VERSION 5.8 ;
BUSBITCHARS "[]" ;
DIVIDERCHAR "/" ;
UNITS
    DATABASE MICRONS 1000 ;
END UNITS

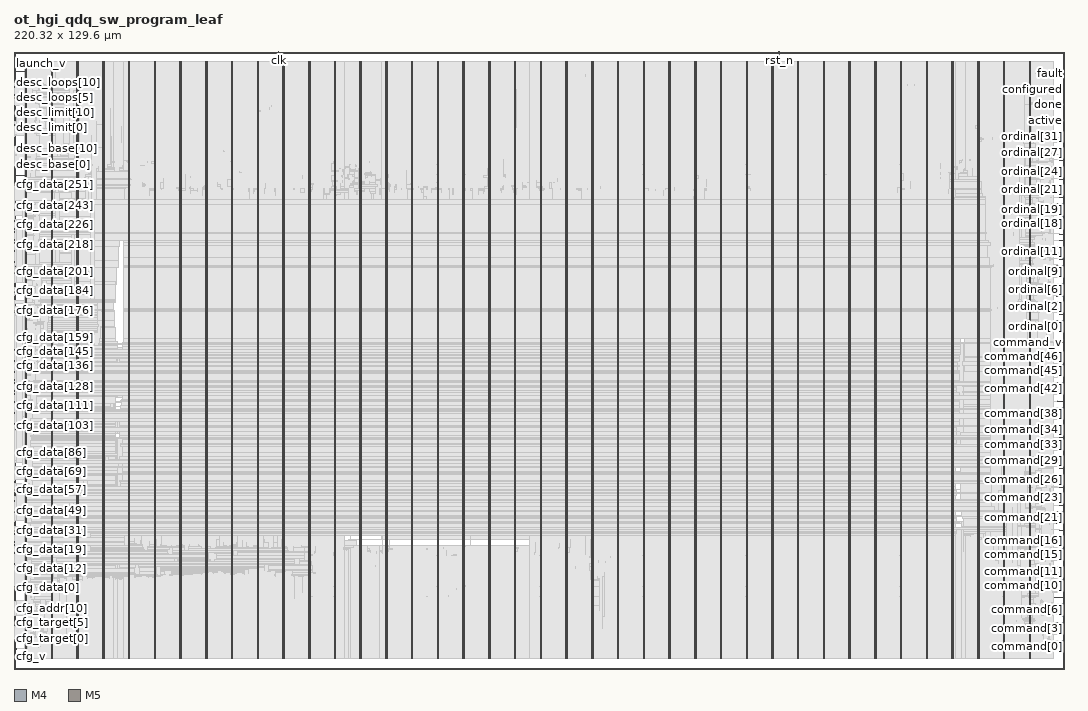
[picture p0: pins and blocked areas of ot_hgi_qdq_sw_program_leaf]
MACRO ot_hgi_qdq_sw_program_leaf
  FOREIGN ot_hgi_qdq_sw_program_leaf 0 0 ;
  CLASS BLOCK ;
  SIZE 220.32 BY 129.6 ;
  PIN active
    DIRECTION OUTPUT ;
    USE SIGNAL ;
    PORT
      LAYER M4 ;
        RECT  220.236 115.056 220.32 115.08 ;
    END
    PORT
      LAYER M4 ;
        RECT  218.869 115.056 220.284 115.08 ;
    END
  END active
  PIN cfg_addr[0]
    DIRECTION INPUT ;
    USE SIGNAL ;
    PORT
      LAYER M4 ;
        RECT  0 11.136 0.084 11.16 ;
    END
  END cfg_addr[0]
  PIN cfg_addr[10]
    DIRECTION INPUT ;
    USE SIGNAL ;
    PORT
      LAYER M4 ;
        RECT  0 14.4 0.084 14.424 ;
    END
  END cfg_addr[10]
  PIN cfg_addr[11]
    DIRECTION INPUT ;
    USE SIGNAL ;
    PORT
      LAYER M4 ;
        RECT  0 14.736 0.084 14.76 ;
    END
  END cfg_addr[11]
  PIN cfg_addr[1]
    DIRECTION INPUT ;
    USE SIGNAL ;
    PORT
      LAYER M4 ;
        RECT  0 11.472 0.084 11.496 ;
    END
  END cfg_addr[1]
  PIN cfg_addr[2]
    DIRECTION INPUT ;
    USE SIGNAL ;
    PORT
      LAYER M4 ;
        RECT  0 11.76 0.084 11.784 ;
    END
  END cfg_addr[2]
  PIN cfg_addr[3]
    DIRECTION INPUT ;
    USE SIGNAL ;
    PORT
      LAYER M4 ;
        RECT  0 12.096 0.084 12.12 ;
    END
  END cfg_addr[3]
  PIN cfg_addr[4]
    DIRECTION INPUT ;
    USE SIGNAL ;
    PORT
      LAYER M4 ;
        RECT  0 12.432 0.084 12.456 ;
    END
  END cfg_addr[4]
  PIN cfg_addr[5]
    DIRECTION INPUT ;
    USE SIGNAL ;
    PORT
      LAYER M4 ;
        RECT  0 12.768 0.084 12.792 ;
    END
  END cfg_addr[5]
  PIN cfg_addr[6]
    DIRECTION INPUT ;
    USE SIGNAL ;
    PORT
      LAYER M4 ;
        RECT  0 13.104 0.084 13.128 ;
    END
  END cfg_addr[6]
  PIN cfg_addr[7]
    DIRECTION INPUT ;
    USE SIGNAL ;
    PORT
      LAYER M4 ;
        RECT  0 13.44 0.084 13.464 ;
    END
  END cfg_addr[7]
  PIN cfg_addr[8]
    DIRECTION INPUT ;
    USE SIGNAL ;
    PORT
      LAYER M4 ;
        RECT  0 13.776 0.084 13.8 ;
    END
  END cfg_addr[8]
  PIN cfg_addr[9]
    DIRECTION INPUT ;
    USE SIGNAL ;
    PORT
      LAYER M4 ;
        RECT  0 14.112 0.084 14.136 ;
    END
  END cfg_addr[9]
  PIN cfg_data[0]
    DIRECTION INPUT ;
    USE SIGNAL ;
    PORT
      LAYER M4 ;
        RECT  0 17.088 0.084 17.112 ;
    END
  END cfg_data[0]
  PIN cfg_data[100]
    DIRECTION INPUT ;
    USE SIGNAL ;
    PORT
      LAYER M4 ;
        RECT  0 50.064 0.084 50.088 ;
    END
  END cfg_data[100]
  PIN cfg_data[101]
    DIRECTION INPUT ;
    USE SIGNAL ;
    PORT
      LAYER M4 ;
        RECT  0 50.4 0.084 50.424 ;
    END
  END cfg_data[101]
  PIN cfg_data[102]
    DIRECTION INPUT ;
    USE SIGNAL ;
    PORT
      LAYER M4 ;
        RECT  0 50.736 0.084 50.76 ;
    END
  END cfg_data[102]
  PIN cfg_data[103]
    DIRECTION INPUT ;
    USE SIGNAL ;
    PORT
      LAYER M4 ;
        RECT  0 51.072 0.084 51.096 ;
    END
  END cfg_data[103]
  PIN cfg_data[104]
    DIRECTION INPUT ;
    USE SIGNAL ;
    PORT
      LAYER M4 ;
        RECT  0 51.408 0.084 51.432 ;
    END
  END cfg_data[104]
  PIN cfg_data[105]
    DIRECTION INPUT ;
    USE SIGNAL ;
    PORT
      LAYER M4 ;
        RECT  0 51.744 0.084 51.768 ;
    END
  END cfg_data[105]
  PIN cfg_data[106]
    DIRECTION INPUT ;
    USE SIGNAL ;
    PORT
      LAYER M4 ;
        RECT  0 52.08 0.084 52.104 ;
    END
  END cfg_data[106]
  PIN cfg_data[107]
    DIRECTION INPUT ;
    USE SIGNAL ;
    PORT
      LAYER M4 ;
        RECT  0 52.416 0.084 52.44 ;
    END
  END cfg_data[107]
  PIN cfg_data[108]
    DIRECTION INPUT ;
    USE SIGNAL ;
    PORT
      LAYER M4 ;
        RECT  0 52.704 0.084 52.728 ;
    END
  END cfg_data[108]
  PIN cfg_data[109]
    DIRECTION INPUT ;
    USE SIGNAL ;
    PORT
      LAYER M4 ;
        RECT  0 53.04 0.084 53.064 ;
    END
  END cfg_data[109]
  PIN cfg_data[10]
    DIRECTION INPUT ;
    USE SIGNAL ;
    PORT
      LAYER M4 ;
        RECT  0 20.4 0.084 20.424 ;
    END
  END cfg_data[10]
  PIN cfg_data[110]
    DIRECTION INPUT ;
    USE SIGNAL ;
    PORT
      LAYER M4 ;
        RECT  0 53.376 0.084 53.4 ;
    END
  END cfg_data[110]
  PIN cfg_data[111]
    DIRECTION INPUT ;
    USE SIGNAL ;
    PORT
      LAYER M4 ;
        RECT  0 53.712 0.084 53.736 ;
    END
  END cfg_data[111]
  PIN cfg_data[112]
    DIRECTION INPUT ;
    USE SIGNAL ;
    PORT
      LAYER M4 ;
        RECT  0 54.048 0.084 54.072 ;
    END
  END cfg_data[112]
  PIN cfg_data[113]
    DIRECTION INPUT ;
    USE SIGNAL ;
    PORT
      LAYER M4 ;
        RECT  0 54.384 0.084 54.408 ;
    END
  END cfg_data[113]
  PIN cfg_data[114]
    DIRECTION INPUT ;
    USE SIGNAL ;
    PORT
      LAYER M4 ;
        RECT  0 54.72 0.084 54.744 ;
    END
  END cfg_data[114]
  PIN cfg_data[115]
    DIRECTION INPUT ;
    USE SIGNAL ;
    PORT
      LAYER M4 ;
        RECT  0 55.056 0.084 55.08 ;
    END
  END cfg_data[115]
  PIN cfg_data[116]
    DIRECTION INPUT ;
    USE SIGNAL ;
    PORT
      LAYER M4 ;
        RECT  0 55.344 0.084 55.368 ;
    END
  END cfg_data[116]
  PIN cfg_data[117]
    DIRECTION INPUT ;
    USE SIGNAL ;
    PORT
      LAYER M4 ;
        RECT  0 55.68 0.084 55.704 ;
    END
  END cfg_data[117]
  PIN cfg_data[118]
    DIRECTION INPUT ;
    USE SIGNAL ;
    PORT
      LAYER M4 ;
        RECT  0 56.016 0.084 56.04 ;
    END
  END cfg_data[118]
  PIN cfg_data[119]
    DIRECTION INPUT ;
    USE SIGNAL ;
    PORT
      LAYER M4 ;
        RECT  0 56.352 0.084 56.376 ;
    END
  END cfg_data[119]
  PIN cfg_data[11]
    DIRECTION INPUT ;
    USE SIGNAL ;
    PORT
      LAYER M4 ;
        RECT  0 20.736 0.084 20.76 ;
    END
  END cfg_data[11]
  PIN cfg_data[120]
    DIRECTION INPUT ;
    USE SIGNAL ;
    PORT
      LAYER M4 ;
        RECT  0 56.688 0.084 56.712 ;
    END
  END cfg_data[120]
  PIN cfg_data[121]
    DIRECTION INPUT ;
    USE SIGNAL ;
    PORT
      LAYER M4 ;
        RECT  0 57.024 0.084 57.048 ;
    END
  END cfg_data[121]
  PIN cfg_data[122]
    DIRECTION INPUT ;
    USE SIGNAL ;
    PORT
      LAYER M4 ;
        RECT  0 57.36 0.084 57.384 ;
    END
  END cfg_data[122]
  PIN cfg_data[123]
    DIRECTION INPUT ;
    USE SIGNAL ;
    PORT
      LAYER M4 ;
        RECT  0 57.696 0.084 57.72 ;
    END
  END cfg_data[123]
  PIN cfg_data[124]
    DIRECTION INPUT ;
    USE SIGNAL ;
    PORT
      LAYER M4 ;
        RECT  0 57.984 0.084 58.008 ;
    END
  END cfg_data[124]
  PIN cfg_data[125]
    DIRECTION INPUT ;
    USE SIGNAL ;
    PORT
      LAYER M4 ;
        RECT  0 58.32 0.084 58.344 ;
    END
  END cfg_data[125]
  PIN cfg_data[126]
    DIRECTION INPUT ;
    USE SIGNAL ;
    PORT
      LAYER M4 ;
        RECT  0 58.656 0.084 58.68 ;
    END
  END cfg_data[126]
  PIN cfg_data[127]
    DIRECTION INPUT ;
    USE SIGNAL ;
    PORT
      LAYER M4 ;
        RECT  0 58.992 0.084 59.016 ;
    END
  END cfg_data[127]
  PIN cfg_data[128]
    DIRECTION INPUT ;
    USE SIGNAL ;
    PORT
      LAYER M4 ;
        RECT  0 59.328 0.084 59.352 ;
    END
  END cfg_data[128]
  PIN cfg_data[129]
    DIRECTION INPUT ;
    USE SIGNAL ;
    PORT
      LAYER M4 ;
        RECT  0 59.664 0.084 59.688 ;
    END
  END cfg_data[129]
  PIN cfg_data[12]
    DIRECTION INPUT ;
    USE SIGNAL ;
    PORT
      LAYER M4 ;
        RECT  0 21.024 0.084 21.048 ;
    END
  END cfg_data[12]
  PIN cfg_data[130]
    DIRECTION INPUT ;
    USE SIGNAL ;
    PORT
      LAYER M4 ;
        RECT  0 60 0.084 60.024 ;
    END
  END cfg_data[130]
  PIN cfg_data[131]
    DIRECTION INPUT ;
    USE SIGNAL ;
    PORT
      LAYER M4 ;
        RECT  0 60.336 0.084 60.36 ;
    END
  END cfg_data[131]
  PIN cfg_data[132]
    DIRECTION INPUT ;
    USE SIGNAL ;
    PORT
      LAYER M4 ;
        RECT  0 60.624 0.084 60.648 ;
    END
  END cfg_data[132]
  PIN cfg_data[133]
    DIRECTION INPUT ;
    USE SIGNAL ;
    PORT
      LAYER M4 ;
        RECT  0 60.96 0.084 60.984 ;
    END
  END cfg_data[133]
  PIN cfg_data[134]
    DIRECTION INPUT ;
    USE SIGNAL ;
    PORT
      LAYER M4 ;
        RECT  0 61.296 0.084 61.32 ;
    END
  END cfg_data[134]
  PIN cfg_data[135]
    DIRECTION INPUT ;
    USE SIGNAL ;
    PORT
      LAYER M4 ;
        RECT  0 61.632 0.084 61.656 ;
    END
  END cfg_data[135]
  PIN cfg_data[136]
    DIRECTION INPUT ;
    USE SIGNAL ;
    PORT
      LAYER M4 ;
        RECT  0 61.968 0.084 61.992 ;
    END
  END cfg_data[136]
  PIN cfg_data[137]
    DIRECTION INPUT ;
    USE SIGNAL ;
    PORT
      LAYER M4 ;
        RECT  0 62.304 0.084 62.328 ;
    END
  END cfg_data[137]
  PIN cfg_data[138]
    DIRECTION INPUT ;
    USE SIGNAL ;
    PORT
      LAYER M4 ;
        RECT  0 62.64 0.084 62.664 ;
    END
  END cfg_data[138]
  PIN cfg_data[139]
    DIRECTION INPUT ;
    USE SIGNAL ;
    PORT
      LAYER M4 ;
        RECT  0 62.976 0.084 63 ;
    END
  END cfg_data[139]
  PIN cfg_data[13]
    DIRECTION INPUT ;
    USE SIGNAL ;
    PORT
      LAYER M4 ;
        RECT  0 21.36 0.084 21.384 ;
    END
  END cfg_data[13]
  PIN cfg_data[140]
    DIRECTION INPUT ;
    USE SIGNAL ;
    PORT
      LAYER M4 ;
        RECT  0 63.264 0.084 63.288 ;
    END
  END cfg_data[140]
  PIN cfg_data[141]
    DIRECTION INPUT ;
    USE SIGNAL ;
    PORT
      LAYER M4 ;
        RECT  0 63.6 0.084 63.624 ;
    END
  END cfg_data[141]
  PIN cfg_data[142]
    DIRECTION INPUT ;
    USE SIGNAL ;
    PORT
      LAYER M4 ;
        RECT  0 63.936 0.084 63.96 ;
    END
  END cfg_data[142]
  PIN cfg_data[143]
    DIRECTION INPUT ;
    USE SIGNAL ;
    PORT
      LAYER M4 ;
        RECT  0 64.272 0.084 64.296 ;
    END
  END cfg_data[143]
  PIN cfg_data[144]
    DIRECTION INPUT ;
    USE SIGNAL ;
    PORT
      LAYER M4 ;
        RECT  0 64.608 0.084 64.632 ;
    END
  END cfg_data[144]
  PIN cfg_data[145]
    DIRECTION INPUT ;
    USE SIGNAL ;
    PORT
      LAYER M4 ;
        RECT  0 64.944 0.084 64.968 ;
    END
  END cfg_data[145]
  PIN cfg_data[146]
    DIRECTION INPUT ;
    USE SIGNAL ;
    PORT
      LAYER M4 ;
        RECT  0 65.28 0.084 65.304 ;
    END
  END cfg_data[146]
  PIN cfg_data[147]
    DIRECTION INPUT ;
    USE SIGNAL ;
    PORT
      LAYER M4 ;
        RECT  0 65.616 0.084 65.64 ;
    END
  END cfg_data[147]
  PIN cfg_data[148]
    DIRECTION INPUT ;
    USE SIGNAL ;
    PORT
      LAYER M4 ;
        RECT  0 65.904 0.084 65.928 ;
    END
  END cfg_data[148]
  PIN cfg_data[149]
    DIRECTION INPUT ;
    USE SIGNAL ;
    PORT
      LAYER M4 ;
        RECT  0 66.24 0.084 66.264 ;
    END
  END cfg_data[149]
  PIN cfg_data[14]
    DIRECTION INPUT ;
    USE SIGNAL ;
    PORT
      LAYER M4 ;
        RECT  0 21.696 0.084 21.72 ;
    END
  END cfg_data[14]
  PIN cfg_data[150]
    DIRECTION INPUT ;
    USE SIGNAL ;
    PORT
      LAYER M4 ;
        RECT  0 66.576 0.084 66.6 ;
    END
  END cfg_data[150]
  PIN cfg_data[151]
    DIRECTION INPUT ;
    USE SIGNAL ;
    PORT
      LAYER M4 ;
        RECT  0 66.912 0.084 66.936 ;
    END
  END cfg_data[151]
  PIN cfg_data[152]
    DIRECTION INPUT ;
    USE SIGNAL ;
    PORT
      LAYER M4 ;
        RECT  0 67.248 0.084 67.272 ;
    END
  END cfg_data[152]
  PIN cfg_data[153]
    DIRECTION INPUT ;
    USE SIGNAL ;
    PORT
      LAYER M4 ;
        RECT  0 67.584 0.084 67.608 ;
    END
  END cfg_data[153]
  PIN cfg_data[154]
    DIRECTION INPUT ;
    USE SIGNAL ;
    PORT
      LAYER M4 ;
        RECT  0 67.92 0.084 67.944 ;
    END
  END cfg_data[154]
  PIN cfg_data[155]
    DIRECTION INPUT ;
    USE SIGNAL ;
    PORT
      LAYER M4 ;
        RECT  0 68.256 0.084 68.28 ;
    END
  END cfg_data[155]
  PIN cfg_data[156]
    DIRECTION INPUT ;
    USE SIGNAL ;
    PORT
      LAYER M4 ;
        RECT  0 68.544 0.084 68.568 ;
    END
  END cfg_data[156]
  PIN cfg_data[157]
    DIRECTION INPUT ;
    USE SIGNAL ;
    PORT
      LAYER M4 ;
        RECT  0 68.88 0.084 68.904 ;
    END
  END cfg_data[157]
  PIN cfg_data[158]
    DIRECTION INPUT ;
    USE SIGNAL ;
    PORT
      LAYER M4 ;
        RECT  0 69.216 0.084 69.24 ;
    END
  END cfg_data[158]
  PIN cfg_data[159]
    DIRECTION INPUT ;
    USE SIGNAL ;
    PORT
      LAYER M4 ;
        RECT  0 69.552 0.084 69.576 ;
    END
  END cfg_data[159]
  PIN cfg_data[15]
    DIRECTION INPUT ;
    USE SIGNAL ;
    PORT
      LAYER M4 ;
        RECT  0 22.032 0.084 22.056 ;
    END
  END cfg_data[15]
  PIN cfg_data[160]
    DIRECTION INPUT ;
    USE SIGNAL ;
    PORT
      LAYER M4 ;
        RECT  0 69.888 0.084 69.912 ;
    END
  END cfg_data[160]
  PIN cfg_data[161]
    DIRECTION INPUT ;
    USE SIGNAL ;
    PORT
      LAYER M4 ;
        RECT  0 70.224 0.084 70.248 ;
    END
  END cfg_data[161]
  PIN cfg_data[162]
    DIRECTION INPUT ;
    USE SIGNAL ;
    PORT
      LAYER M4 ;
        RECT  0 70.56 0.084 70.584 ;
    END
  END cfg_data[162]
  PIN cfg_data[163]
    DIRECTION INPUT ;
    USE SIGNAL ;
    PORT
      LAYER M4 ;
        RECT  0 70.896 0.084 70.92 ;
    END
  END cfg_data[163]
  PIN cfg_data[164]
    DIRECTION INPUT ;
    USE SIGNAL ;
    PORT
      LAYER M4 ;
        RECT  0 71.184 0.084 71.208 ;
    END
  END cfg_data[164]
  PIN cfg_data[165]
    DIRECTION INPUT ;
    USE SIGNAL ;
    PORT
      LAYER M4 ;
        RECT  0 71.52 0.084 71.544 ;
    END
  END cfg_data[165]
  PIN cfg_data[166]
    DIRECTION INPUT ;
    USE SIGNAL ;
    PORT
      LAYER M4 ;
        RECT  0 71.856 0.084 71.88 ;
    END
  END cfg_data[166]
  PIN cfg_data[167]
    DIRECTION INPUT ;
    USE SIGNAL ;
    PORT
      LAYER M4 ;
        RECT  0 72.192 0.084 72.216 ;
    END
  END cfg_data[167]
  PIN cfg_data[168]
    DIRECTION INPUT ;
    USE SIGNAL ;
    PORT
      LAYER M4 ;
        RECT  0 72.528 0.084 72.552 ;
    END
  END cfg_data[168]
  PIN cfg_data[169]
    DIRECTION INPUT ;
    USE SIGNAL ;
    PORT
      LAYER M4 ;
        RECT  0 72.864 0.084 72.888 ;
    END
  END cfg_data[169]
  PIN cfg_data[16]
    DIRECTION INPUT ;
    USE SIGNAL ;
    PORT
      LAYER M4 ;
        RECT  0 22.368 0.084 22.392 ;
    END
  END cfg_data[16]
  PIN cfg_data[170]
    DIRECTION INPUT ;
    USE SIGNAL ;
    PORT
      LAYER M4 ;
        RECT  0 73.2 0.084 73.224 ;
    END
  END cfg_data[170]
  PIN cfg_data[171]
    DIRECTION INPUT ;
    USE SIGNAL ;
    PORT
      LAYER M4 ;
        RECT  0 73.536 0.084 73.56 ;
    END
  END cfg_data[171]
  PIN cfg_data[172]
    DIRECTION INPUT ;
    USE SIGNAL ;
    PORT
      LAYER M4 ;
        RECT  0 73.824 0.084 73.848 ;
    END
  END cfg_data[172]
  PIN cfg_data[173]
    DIRECTION INPUT ;
    USE SIGNAL ;
    PORT
      LAYER M4 ;
        RECT  0 74.16 0.084 74.184 ;
    END
  END cfg_data[173]
  PIN cfg_data[174]
    DIRECTION INPUT ;
    USE SIGNAL ;
    PORT
      LAYER M4 ;
        RECT  0 74.496 0.084 74.52 ;
    END
  END cfg_data[174]
  PIN cfg_data[175]
    DIRECTION INPUT ;
    USE SIGNAL ;
    PORT
      LAYER M4 ;
        RECT  0 74.832 0.084 74.856 ;
    END
  END cfg_data[175]
  PIN cfg_data[176]
    DIRECTION INPUT ;
    USE SIGNAL ;
    PORT
      LAYER M4 ;
        RECT  0 75.168 0.084 75.192 ;
    END
  END cfg_data[176]
  PIN cfg_data[177]
    DIRECTION INPUT ;
    USE SIGNAL ;
    PORT
      LAYER M4 ;
        RECT  0 75.504 0.084 75.528 ;
    END
  END cfg_data[177]
  PIN cfg_data[178]
    DIRECTION INPUT ;
    USE SIGNAL ;
    PORT
      LAYER M4 ;
        RECT  0 75.84 0.084 75.864 ;
    END
  END cfg_data[178]
  PIN cfg_data[179]
    DIRECTION INPUT ;
    USE SIGNAL ;
    PORT
      LAYER M4 ;
        RECT  0 76.176 0.084 76.2 ;
    END
  END cfg_data[179]
  PIN cfg_data[17]
    DIRECTION INPUT ;
    USE SIGNAL ;
    PORT
      LAYER M4 ;
        RECT  0 22.704 0.084 22.728 ;
    END
  END cfg_data[17]
  PIN cfg_data[180]
    DIRECTION INPUT ;
    USE SIGNAL ;
    PORT
      LAYER M4 ;
        RECT  0 76.464 0.084 76.488 ;
    END
  END cfg_data[180]
  PIN cfg_data[181]
    DIRECTION INPUT ;
    USE SIGNAL ;
    PORT
      LAYER M4 ;
        RECT  0 76.8 0.084 76.824 ;
    END
  END cfg_data[181]
  PIN cfg_data[182]
    DIRECTION INPUT ;
    USE SIGNAL ;
    PORT
      LAYER M4 ;
        RECT  0 77.136 0.084 77.16 ;
    END
  END cfg_data[182]
  PIN cfg_data[183]
    DIRECTION INPUT ;
    USE SIGNAL ;
    PORT
      LAYER M4 ;
        RECT  0 77.472 0.084 77.496 ;
    END
  END cfg_data[183]
  PIN cfg_data[184]
    DIRECTION INPUT ;
    USE SIGNAL ;
    PORT
      LAYER M4 ;
        RECT  0 77.808 0.084 77.832 ;
    END
  END cfg_data[184]
  PIN cfg_data[185]
    DIRECTION INPUT ;
    USE SIGNAL ;
    PORT
      LAYER M4 ;
        RECT  0 78.144 0.084 78.168 ;
    END
  END cfg_data[185]
  PIN cfg_data[186]
    DIRECTION INPUT ;
    USE SIGNAL ;
    PORT
      LAYER M4 ;
        RECT  0 78.48 0.084 78.504 ;
    END
  END cfg_data[186]
  PIN cfg_data[187]
    DIRECTION INPUT ;
    USE SIGNAL ;
    PORT
      LAYER M4 ;
        RECT  0 78.816 0.084 78.84 ;
    END
  END cfg_data[187]
  PIN cfg_data[188]
    DIRECTION INPUT ;
    USE SIGNAL ;
    PORT
      LAYER M4 ;
        RECT  0 79.104 0.084 79.128 ;
    END
  END cfg_data[188]
  PIN cfg_data[189]
    DIRECTION INPUT ;
    USE SIGNAL ;
    PORT
      LAYER M4 ;
        RECT  0 79.44 0.084 79.464 ;
    END
  END cfg_data[189]
  PIN cfg_data[18]
    DIRECTION INPUT ;
    USE SIGNAL ;
    PORT
      LAYER M4 ;
        RECT  0 23.04 0.084 23.064 ;
    END
  END cfg_data[18]
  PIN cfg_data[190]
    DIRECTION INPUT ;
    USE SIGNAL ;
    PORT
      LAYER M4 ;
        RECT  0 79.776 0.084 79.8 ;
    END
  END cfg_data[190]
  PIN cfg_data[191]
    DIRECTION INPUT ;
    USE SIGNAL ;
    PORT
      LAYER M4 ;
        RECT  0 80.112 0.084 80.136 ;
    END
  END cfg_data[191]
  PIN cfg_data[192]
    DIRECTION INPUT ;
    USE SIGNAL ;
    PORT
      LAYER M4 ;
        RECT  0 80.448 0.084 80.472 ;
    END
  END cfg_data[192]
  PIN cfg_data[193]
    DIRECTION INPUT ;
    USE SIGNAL ;
    PORT
      LAYER M4 ;
        RECT  0 80.784 0.084 80.808 ;
    END
  END cfg_data[193]
  PIN cfg_data[194]
    DIRECTION INPUT ;
    USE SIGNAL ;
    PORT
      LAYER M4 ;
        RECT  0 81.12 0.084 81.144 ;
    END
  END cfg_data[194]
  PIN cfg_data[195]
    DIRECTION INPUT ;
    USE SIGNAL ;
    PORT
      LAYER M4 ;
        RECT  0 81.456 0.084 81.48 ;
    END
  END cfg_data[195]
  PIN cfg_data[196]
    DIRECTION INPUT ;
    USE SIGNAL ;
    PORT
      LAYER M4 ;
        RECT  0 81.744 0.084 81.768 ;
    END
  END cfg_data[196]
  PIN cfg_data[197]
    DIRECTION INPUT ;
    USE SIGNAL ;
    PORT
      LAYER M4 ;
        RECT  0 82.08 0.084 82.104 ;
    END
  END cfg_data[197]
  PIN cfg_data[198]
    DIRECTION INPUT ;
    USE SIGNAL ;
    PORT
      LAYER M4 ;
        RECT  0 82.416 0.084 82.44 ;
    END
  END cfg_data[198]
  PIN cfg_data[199]
    DIRECTION INPUT ;
    USE SIGNAL ;
    PORT
      LAYER M4 ;
        RECT  0 82.752 0.084 82.776 ;
    END
  END cfg_data[199]
  PIN cfg_data[19]
    DIRECTION INPUT ;
    USE SIGNAL ;
    PORT
      LAYER M4 ;
        RECT  0 23.376 0.084 23.4 ;
    END
  END cfg_data[19]
  PIN cfg_data[1]
    DIRECTION INPUT ;
    USE SIGNAL ;
    PORT
      LAYER M4 ;
        RECT  0 17.424 0.084 17.448 ;
    END
  END cfg_data[1]
  PIN cfg_data[200]
    DIRECTION INPUT ;
    USE SIGNAL ;
    PORT
      LAYER M4 ;
        RECT  0 83.088 0.084 83.112 ;
    END
  END cfg_data[200]
  PIN cfg_data[201]
    DIRECTION INPUT ;
    USE SIGNAL ;
    PORT
      LAYER M4 ;
        RECT  0 83.424 0.084 83.448 ;
    END
  END cfg_data[201]
  PIN cfg_data[202]
    DIRECTION INPUT ;
    USE SIGNAL ;
    PORT
      LAYER M4 ;
        RECT  0 83.76 0.084 83.784 ;
    END
  END cfg_data[202]
  PIN cfg_data[203]
    DIRECTION INPUT ;
    USE SIGNAL ;
    PORT
      LAYER M4 ;
        RECT  0 84.096 0.084 84.12 ;
    END
  END cfg_data[203]
  PIN cfg_data[204]
    DIRECTION INPUT ;
    USE SIGNAL ;
    PORT
      LAYER M4 ;
        RECT  0 84.384 0.084 84.408 ;
    END
  END cfg_data[204]
  PIN cfg_data[205]
    DIRECTION INPUT ;
    USE SIGNAL ;
    PORT
      LAYER M4 ;
        RECT  0 84.72 0.084 84.744 ;
    END
  END cfg_data[205]
  PIN cfg_data[206]
    DIRECTION INPUT ;
    USE SIGNAL ;
    PORT
      LAYER M4 ;
        RECT  0 85.056 0.084 85.08 ;
    END
  END cfg_data[206]
  PIN cfg_data[207]
    DIRECTION INPUT ;
    USE SIGNAL ;
    PORT
      LAYER M4 ;
        RECT  0 85.392 0.084 85.416 ;
    END
  END cfg_data[207]
  PIN cfg_data[208]
    DIRECTION INPUT ;
    USE SIGNAL ;
    PORT
      LAYER M4 ;
        RECT  0 85.728 0.084 85.752 ;
    END
  END cfg_data[208]
  PIN cfg_data[209]
    DIRECTION INPUT ;
    USE SIGNAL ;
    PORT
      LAYER M4 ;
        RECT  0 86.064 0.084 86.088 ;
    END
  END cfg_data[209]
  PIN cfg_data[20]
    DIRECTION INPUT ;
    USE SIGNAL ;
    PORT
      LAYER M4 ;
        RECT  0 23.664 0.084 23.688 ;
    END
  END cfg_data[20]
  PIN cfg_data[210]
    DIRECTION INPUT ;
    USE SIGNAL ;
    PORT
      LAYER M4 ;
        RECT  0 86.4 0.084 86.424 ;
    END
  END cfg_data[210]
  PIN cfg_data[211]
    DIRECTION INPUT ;
    USE SIGNAL ;
    PORT
      LAYER M4 ;
        RECT  0 86.736 0.084 86.76 ;
    END
  END cfg_data[211]
  PIN cfg_data[212]
    DIRECTION INPUT ;
    USE SIGNAL ;
    PORT
      LAYER M4 ;
        RECT  0 87.024 0.084 87.048 ;
    END
  END cfg_data[212]
  PIN cfg_data[213]
    DIRECTION INPUT ;
    USE SIGNAL ;
    PORT
      LAYER M4 ;
        RECT  0 87.36 0.084 87.384 ;
    END
  END cfg_data[213]
  PIN cfg_data[214]
    DIRECTION INPUT ;
    USE SIGNAL ;
    PORT
      LAYER M4 ;
        RECT  0 87.696 0.084 87.72 ;
    END
  END cfg_data[214]
  PIN cfg_data[215]
    DIRECTION INPUT ;
    USE SIGNAL ;
    PORT
      LAYER M4 ;
        RECT  0 88.032 0.084 88.056 ;
    END
  END cfg_data[215]
  PIN cfg_data[216]
    DIRECTION INPUT ;
    USE SIGNAL ;
    PORT
      LAYER M4 ;
        RECT  0 88.368 0.084 88.392 ;
    END
  END cfg_data[216]
  PIN cfg_data[217]
    DIRECTION INPUT ;
    USE SIGNAL ;
    PORT
      LAYER M4 ;
        RECT  0 88.704 0.084 88.728 ;
    END
  END cfg_data[217]
  PIN cfg_data[218]
    DIRECTION INPUT ;
    USE SIGNAL ;
    PORT
      LAYER M4 ;
        RECT  0 89.04 0.084 89.064 ;
    END
  END cfg_data[218]
  PIN cfg_data[219]
    DIRECTION INPUT ;
    USE SIGNAL ;
    PORT
      LAYER M4 ;
        RECT  0 89.376 0.084 89.4 ;
    END
  END cfg_data[219]
  PIN cfg_data[21]
    DIRECTION INPUT ;
    USE SIGNAL ;
    PORT
      LAYER M4 ;
        RECT  0 24 0.084 24.024 ;
    END
  END cfg_data[21]
  PIN cfg_data[220]
    DIRECTION INPUT ;
    USE SIGNAL ;
    PORT
      LAYER M4 ;
        RECT  0 89.664 0.084 89.688 ;
    END
  END cfg_data[220]
  PIN cfg_data[221]
    DIRECTION INPUT ;
    USE SIGNAL ;
    PORT
      LAYER M4 ;
        RECT  0 90 0.084 90.024 ;
    END
  END cfg_data[221]
  PIN cfg_data[222]
    DIRECTION INPUT ;
    USE SIGNAL ;
    PORT
      LAYER M4 ;
        RECT  0 90.336 0.084 90.36 ;
    END
  END cfg_data[222]
  PIN cfg_data[223]
    DIRECTION INPUT ;
    USE SIGNAL ;
    PORT
      LAYER M4 ;
        RECT  0 90.672 0.084 90.696 ;
    END
  END cfg_data[223]
  PIN cfg_data[224]
    DIRECTION INPUT ;
    USE SIGNAL ;
    PORT
      LAYER M4 ;
        RECT  0 91.008 0.084 91.032 ;
    END
  END cfg_data[224]
  PIN cfg_data[225]
    DIRECTION INPUT ;
    USE SIGNAL ;
    PORT
      LAYER M4 ;
        RECT  0 91.344 0.084 91.368 ;
    END
  END cfg_data[225]
  PIN cfg_data[226]
    DIRECTION INPUT ;
    USE SIGNAL ;
    PORT
      LAYER M4 ;
        RECT  0 91.68 0.084 91.704 ;
    END
  END cfg_data[226]
  PIN cfg_data[227]
    DIRECTION INPUT ;
    USE SIGNAL ;
    PORT
      LAYER M4 ;
        RECT  0 92.016 0.084 92.04 ;
    END
  END cfg_data[227]
  PIN cfg_data[228]
    DIRECTION INPUT ;
    USE SIGNAL ;
    PORT
      LAYER M4 ;
        RECT  0 92.304 0.084 92.328 ;
    END
  END cfg_data[228]
  PIN cfg_data[229]
    DIRECTION INPUT ;
    USE SIGNAL ;
    PORT
      LAYER M4 ;
        RECT  0 92.64 0.084 92.664 ;
    END
  END cfg_data[229]
  PIN cfg_data[22]
    DIRECTION INPUT ;
    USE SIGNAL ;
    PORT
      LAYER M4 ;
        RECT  0 24.336 0.084 24.36 ;
    END
  END cfg_data[22]
  PIN cfg_data[230]
    DIRECTION INPUT ;
    USE SIGNAL ;
    PORT
      LAYER M4 ;
        RECT  0 92.976 0.084 93 ;
    END
  END cfg_data[230]
  PIN cfg_data[231]
    DIRECTION INPUT ;
    USE SIGNAL ;
    PORT
      LAYER M4 ;
        RECT  0 93.312 0.084 93.336 ;
    END
  END cfg_data[231]
  PIN cfg_data[232]
    DIRECTION INPUT ;
    USE SIGNAL ;
    PORT
      LAYER M4 ;
        RECT  0 93.648 0.084 93.672 ;
    END
  END cfg_data[232]
  PIN cfg_data[233]
    DIRECTION INPUT ;
    USE SIGNAL ;
    PORT
      LAYER M4 ;
        RECT  0 93.984 0.084 94.008 ;
    END
  END cfg_data[233]
  PIN cfg_data[234]
    DIRECTION INPUT ;
    USE SIGNAL ;
    PORT
      LAYER M4 ;
        RECT  0 94.32 0.084 94.344 ;
    END
  END cfg_data[234]
  PIN cfg_data[235]
    DIRECTION INPUT ;
    USE SIGNAL ;
    PORT
      LAYER M4 ;
        RECT  0 94.656 0.084 94.68 ;
    END
  END cfg_data[235]
  PIN cfg_data[236]
    DIRECTION INPUT ;
    USE SIGNAL ;
    PORT
      LAYER M4 ;
        RECT  0 94.944 0.084 94.968 ;
    END
  END cfg_data[236]
  PIN cfg_data[237]
    DIRECTION INPUT ;
    USE SIGNAL ;
    PORT
      LAYER M4 ;
        RECT  0 95.28 0.084 95.304 ;
    END
  END cfg_data[237]
  PIN cfg_data[238]
    DIRECTION INPUT ;
    USE SIGNAL ;
    PORT
      LAYER M4 ;
        RECT  0 95.616 0.084 95.64 ;
    END
  END cfg_data[238]
  PIN cfg_data[239]
    DIRECTION INPUT ;
    USE SIGNAL ;
    PORT
      LAYER M4 ;
        RECT  0 95.952 0.084 95.976 ;
    END
  END cfg_data[239]
  PIN cfg_data[23]
    DIRECTION INPUT ;
    USE SIGNAL ;
    PORT
      LAYER M4 ;
        RECT  0 24.672 0.084 24.696 ;
    END
  END cfg_data[23]
  PIN cfg_data[240]
    DIRECTION INPUT ;
    USE SIGNAL ;
    PORT
      LAYER M4 ;
        RECT  0 96.288 0.084 96.312 ;
    END
  END cfg_data[240]
  PIN cfg_data[241]
    DIRECTION INPUT ;
    USE SIGNAL ;
    PORT
      LAYER M4 ;
        RECT  0 96.624 0.084 96.648 ;
    END
  END cfg_data[241]
  PIN cfg_data[242]
    DIRECTION INPUT ;
    USE SIGNAL ;
    PORT
      LAYER M4 ;
        RECT  0 96.96 0.084 96.984 ;
    END
  END cfg_data[242]
  PIN cfg_data[243]
    DIRECTION INPUT ;
    USE SIGNAL ;
    PORT
      LAYER M4 ;
        RECT  0 97.296 0.084 97.32 ;
    END
  END cfg_data[243]
  PIN cfg_data[244]
    DIRECTION INPUT ;
    USE SIGNAL ;
    PORT
      LAYER M4 ;
        RECT  0 97.584 0.084 97.608 ;
    END
  END cfg_data[244]
  PIN cfg_data[245]
    DIRECTION INPUT ;
    USE SIGNAL ;
    PORT
      LAYER M4 ;
        RECT  0 97.92 0.084 97.944 ;
    END
  END cfg_data[245]
  PIN cfg_data[246]
    DIRECTION INPUT ;
    USE SIGNAL ;
    PORT
      LAYER M4 ;
        RECT  0 98.256 0.084 98.28 ;
    END
  END cfg_data[246]
  PIN cfg_data[247]
    DIRECTION INPUT ;
    USE SIGNAL ;
    PORT
      LAYER M4 ;
        RECT  0 98.592 0.084 98.616 ;
    END
  END cfg_data[247]
  PIN cfg_data[248]
    DIRECTION INPUT ;
    USE SIGNAL ;
    PORT
      LAYER M4 ;
        RECT  0 98.928 0.084 98.952 ;
    END
  END cfg_data[248]
  PIN cfg_data[249]
    DIRECTION INPUT ;
    USE SIGNAL ;
    PORT
      LAYER M4 ;
        RECT  0 99.264 0.084 99.288 ;
    END
  END cfg_data[249]
  PIN cfg_data[24]
    DIRECTION INPUT ;
    USE SIGNAL ;
    PORT
      LAYER M4 ;
        RECT  0 25.008 0.084 25.032 ;
    END
  END cfg_data[24]
  PIN cfg_data[250]
    DIRECTION INPUT ;
    USE SIGNAL ;
    PORT
      LAYER M4 ;
        RECT  0 99.6 0.084 99.624 ;
    END
  END cfg_data[250]
  PIN cfg_data[251]
    DIRECTION INPUT ;
    USE SIGNAL ;
    PORT
      LAYER M4 ;
        RECT  0 99.936 0.084 99.96 ;
    END
  END cfg_data[251]
  PIN cfg_data[252]
    DIRECTION INPUT ;
    USE SIGNAL ;
    PORT
      LAYER M4 ;
        RECT  0 100.224 0.084 100.248 ;
    END
  END cfg_data[252]
  PIN cfg_data[253]
    DIRECTION INPUT ;
    USE SIGNAL ;
    PORT
      LAYER M4 ;
        RECT  0 100.56 0.084 100.584 ;
    END
  END cfg_data[253]
  PIN cfg_data[254]
    DIRECTION INPUT ;
    USE SIGNAL ;
    PORT
      LAYER M4 ;
        RECT  0 100.896 0.084 100.92 ;
    END
  END cfg_data[254]
  PIN cfg_data[255]
    DIRECTION INPUT ;
    USE SIGNAL ;
    PORT
      LAYER M4 ;
        RECT  0 101.232 0.084 101.256 ;
    END
  END cfg_data[255]
  PIN cfg_data[25]
    DIRECTION INPUT ;
    USE SIGNAL ;
    PORT
      LAYER M4 ;
        RECT  0 25.344 0.084 25.368 ;
    END
  END cfg_data[25]
  PIN cfg_data[26]
    DIRECTION INPUT ;
    USE SIGNAL ;
    PORT
      LAYER M4 ;
        RECT  0 25.68 0.084 25.704 ;
    END
  END cfg_data[26]
  PIN cfg_data[27]
    DIRECTION INPUT ;
    USE SIGNAL ;
    PORT
      LAYER M4 ;
        RECT  0 26.016 0.084 26.04 ;
    END
  END cfg_data[27]
  PIN cfg_data[28]
    DIRECTION INPUT ;
    USE SIGNAL ;
    PORT
      LAYER M4 ;
        RECT  0 26.304 0.084 26.328 ;
    END
  END cfg_data[28]
  PIN cfg_data[29]
    DIRECTION INPUT ;
    USE SIGNAL ;
    PORT
      LAYER M4 ;
        RECT  0 26.64 0.084 26.664 ;
    END
  END cfg_data[29]
  PIN cfg_data[2]
    DIRECTION INPUT ;
    USE SIGNAL ;
    PORT
      LAYER M4 ;
        RECT  0 17.76 0.084 17.784 ;
    END
  END cfg_data[2]
  PIN cfg_data[30]
    DIRECTION INPUT ;
    USE SIGNAL ;
    PORT
      LAYER M4 ;
        RECT  0 26.976 0.084 27 ;
    END
  END cfg_data[30]
  PIN cfg_data[31]
    DIRECTION INPUT ;
    USE SIGNAL ;
    PORT
      LAYER M4 ;
        RECT  0 27.312 0.084 27.336 ;
    END
  END cfg_data[31]
  PIN cfg_data[32]
    DIRECTION INPUT ;
    USE SIGNAL ;
    PORT
      LAYER M4 ;
        RECT  0 27.648 0.084 27.672 ;
    END
  END cfg_data[32]
  PIN cfg_data[33]
    DIRECTION INPUT ;
    USE SIGNAL ;
    PORT
      LAYER M4 ;
        RECT  0 27.984 0.084 28.008 ;
    END
  END cfg_data[33]
  PIN cfg_data[34]
    DIRECTION INPUT ;
    USE SIGNAL ;
    PORT
      LAYER M4 ;
        RECT  0 28.32 0.084 28.344 ;
    END
  END cfg_data[34]
  PIN cfg_data[35]
    DIRECTION INPUT ;
    USE SIGNAL ;
    PORT
      LAYER M4 ;
        RECT  0 28.656 0.084 28.68 ;
    END
  END cfg_data[35]
  PIN cfg_data[36]
    DIRECTION INPUT ;
    USE SIGNAL ;
    PORT
      LAYER M4 ;
        RECT  0 28.944 0.084 28.968 ;
    END
  END cfg_data[36]
  PIN cfg_data[37]
    DIRECTION INPUT ;
    USE SIGNAL ;
    PORT
      LAYER M4 ;
        RECT  0 29.28 0.084 29.304 ;
    END
  END cfg_data[37]
  PIN cfg_data[38]
    DIRECTION INPUT ;
    USE SIGNAL ;
    PORT
      LAYER M4 ;
        RECT  0 29.616 0.084 29.64 ;
    END
  END cfg_data[38]
  PIN cfg_data[39]
    DIRECTION INPUT ;
    USE SIGNAL ;
    PORT
      LAYER M4 ;
        RECT  0 29.952 0.084 29.976 ;
    END
  END cfg_data[39]
  PIN cfg_data[3]
    DIRECTION INPUT ;
    USE SIGNAL ;
    PORT
      LAYER M4 ;
        RECT  0 18.096 0.084 18.12 ;
    END
  END cfg_data[3]
  PIN cfg_data[40]
    DIRECTION INPUT ;
    USE SIGNAL ;
    PORT
      LAYER M4 ;
        RECT  0 30.288 0.084 30.312 ;
    END
  END cfg_data[40]
  PIN cfg_data[41]
    DIRECTION INPUT ;
    USE SIGNAL ;
    PORT
      LAYER M4 ;
        RECT  0 30.624 0.084 30.648 ;
    END
  END cfg_data[41]
  PIN cfg_data[42]
    DIRECTION INPUT ;
    USE SIGNAL ;
    PORT
      LAYER M4 ;
        RECT  0 30.96 0.084 30.984 ;
    END
  END cfg_data[42]
  PIN cfg_data[43]
    DIRECTION INPUT ;
    USE SIGNAL ;
    PORT
      LAYER M4 ;
        RECT  0 31.296 0.084 31.32 ;
    END
  END cfg_data[43]
  PIN cfg_data[44]
    DIRECTION INPUT ;
    USE SIGNAL ;
    PORT
      LAYER M4 ;
        RECT  0 31.584 0.084 31.608 ;
    END
  END cfg_data[44]
  PIN cfg_data[45]
    DIRECTION INPUT ;
    USE SIGNAL ;
    PORT
      LAYER M4 ;
        RECT  0 31.92 0.084 31.944 ;
    END
  END cfg_data[45]
  PIN cfg_data[46]
    DIRECTION INPUT ;
    USE SIGNAL ;
    PORT
      LAYER M4 ;
        RECT  0 32.256 0.084 32.28 ;
    END
  END cfg_data[46]
  PIN cfg_data[47]
    DIRECTION INPUT ;
    USE SIGNAL ;
    PORT
      LAYER M4 ;
        RECT  0 32.592 0.084 32.616 ;
    END
  END cfg_data[47]
  PIN cfg_data[48]
    DIRECTION INPUT ;
    USE SIGNAL ;
    PORT
      LAYER M4 ;
        RECT  0 32.928 0.084 32.952 ;
    END
  END cfg_data[48]
  PIN cfg_data[49]
    DIRECTION INPUT ;
    USE SIGNAL ;
    PORT
      LAYER M4 ;
        RECT  0 33.264 0.084 33.288 ;
    END
  END cfg_data[49]
  PIN cfg_data[4]
    DIRECTION INPUT ;
    USE SIGNAL ;
    PORT
      LAYER M4 ;
        RECT  0 18.384 0.084 18.408 ;
    END
  END cfg_data[4]
  PIN cfg_data[50]
    DIRECTION INPUT ;
    USE SIGNAL ;
    PORT
      LAYER M4 ;
        RECT  0 33.6 0.084 33.624 ;
    END
  END cfg_data[50]
  PIN cfg_data[51]
    DIRECTION INPUT ;
    USE SIGNAL ;
    PORT
      LAYER M4 ;
        RECT  0 33.936 0.084 33.96 ;
    END
  END cfg_data[51]
  PIN cfg_data[52]
    DIRECTION INPUT ;
    USE SIGNAL ;
    PORT
      LAYER M4 ;
        RECT  0 34.224 0.084 34.248 ;
    END
  END cfg_data[52]
  PIN cfg_data[53]
    DIRECTION INPUT ;
    USE SIGNAL ;
    PORT
      LAYER M4 ;
        RECT  0 34.56 0.084 34.584 ;
    END
  END cfg_data[53]
  PIN cfg_data[54]
    DIRECTION INPUT ;
    USE SIGNAL ;
    PORT
      LAYER M4 ;
        RECT  0 34.896 0.084 34.92 ;
    END
  END cfg_data[54]
  PIN cfg_data[55]
    DIRECTION INPUT ;
    USE SIGNAL ;
    PORT
      LAYER M4 ;
        RECT  0 35.232 0.084 35.256 ;
    END
  END cfg_data[55]
  PIN cfg_data[56]
    DIRECTION INPUT ;
    USE SIGNAL ;
    PORT
      LAYER M4 ;
        RECT  0 35.568 0.084 35.592 ;
    END
  END cfg_data[56]
  PIN cfg_data[57]
    DIRECTION INPUT ;
    USE SIGNAL ;
    PORT
      LAYER M4 ;
        RECT  0 35.904 0.084 35.928 ;
    END
  END cfg_data[57]
  PIN cfg_data[58]
    DIRECTION INPUT ;
    USE SIGNAL ;
    PORT
      LAYER M4 ;
        RECT  0 36.24 0.084 36.264 ;
    END
  END cfg_data[58]
  PIN cfg_data[59]
    DIRECTION INPUT ;
    USE SIGNAL ;
    PORT
      LAYER M4 ;
        RECT  0 36.576 0.084 36.6 ;
    END
  END cfg_data[59]
  PIN cfg_data[5]
    DIRECTION INPUT ;
    USE SIGNAL ;
    PORT
      LAYER M4 ;
        RECT  0 18.72 0.084 18.744 ;
    END
  END cfg_data[5]
  PIN cfg_data[60]
    DIRECTION INPUT ;
    USE SIGNAL ;
    PORT
      LAYER M4 ;
        RECT  0 36.864 0.084 36.888 ;
    END
  END cfg_data[60]
  PIN cfg_data[61]
    DIRECTION INPUT ;
    USE SIGNAL ;
    PORT
      LAYER M4 ;
        RECT  0 37.2 0.084 37.224 ;
    END
  END cfg_data[61]
  PIN cfg_data[62]
    DIRECTION INPUT ;
    USE SIGNAL ;
    PORT
      LAYER M4 ;
        RECT  0 37.536 0.084 37.56 ;
    END
  END cfg_data[62]
  PIN cfg_data[63]
    DIRECTION INPUT ;
    USE SIGNAL ;
    PORT
      LAYER M4 ;
        RECT  0 37.872 0.084 37.896 ;
    END
  END cfg_data[63]
  PIN cfg_data[64]
    DIRECTION INPUT ;
    USE SIGNAL ;
    PORT
      LAYER M4 ;
        RECT  0 38.208 0.084 38.232 ;
    END
  END cfg_data[64]
  PIN cfg_data[65]
    DIRECTION INPUT ;
    USE SIGNAL ;
    PORT
      LAYER M4 ;
        RECT  0 38.544 0.084 38.568 ;
    END
  END cfg_data[65]
  PIN cfg_data[66]
    DIRECTION INPUT ;
    USE SIGNAL ;
    PORT
      LAYER M4 ;
        RECT  0 38.88 0.084 38.904 ;
    END
  END cfg_data[66]
  PIN cfg_data[67]
    DIRECTION INPUT ;
    USE SIGNAL ;
    PORT
      LAYER M4 ;
        RECT  0 39.216 0.084 39.24 ;
    END
  END cfg_data[67]
  PIN cfg_data[68]
    DIRECTION INPUT ;
    USE SIGNAL ;
    PORT
      LAYER M4 ;
        RECT  0 39.504 0.084 39.528 ;
    END
  END cfg_data[68]
  PIN cfg_data[69]
    DIRECTION INPUT ;
    USE SIGNAL ;
    PORT
      LAYER M4 ;
        RECT  0 39.84 0.084 39.864 ;
    END
  END cfg_data[69]
  PIN cfg_data[6]
    DIRECTION INPUT ;
    USE SIGNAL ;
    PORT
      LAYER M4 ;
        RECT  0 19.056 0.084 19.08 ;
    END
  END cfg_data[6]
  PIN cfg_data[70]
    DIRECTION INPUT ;
    USE SIGNAL ;
    PORT
      LAYER M4 ;
        RECT  0 40.176 0.084 40.2 ;
    END
  END cfg_data[70]
  PIN cfg_data[71]
    DIRECTION INPUT ;
    USE SIGNAL ;
    PORT
      LAYER M4 ;
        RECT  0 40.512 0.084 40.536 ;
    END
  END cfg_data[71]
  PIN cfg_data[72]
    DIRECTION INPUT ;
    USE SIGNAL ;
    PORT
      LAYER M4 ;
        RECT  0 40.848 0.084 40.872 ;
    END
  END cfg_data[72]
  PIN cfg_data[73]
    DIRECTION INPUT ;
    USE SIGNAL ;
    PORT
      LAYER M4 ;
        RECT  0 41.184 0.084 41.208 ;
    END
  END cfg_data[73]
  PIN cfg_data[74]
    DIRECTION INPUT ;
    USE SIGNAL ;
    PORT
      LAYER M4 ;
        RECT  0 41.52 0.084 41.544 ;
    END
  END cfg_data[74]
  PIN cfg_data[75]
    DIRECTION INPUT ;
    USE SIGNAL ;
    PORT
      LAYER M4 ;
        RECT  0 41.856 0.084 41.88 ;
    END
  END cfg_data[75]
  PIN cfg_data[76]
    DIRECTION INPUT ;
    USE SIGNAL ;
    PORT
      LAYER M4 ;
        RECT  0 42.144 0.084 42.168 ;
    END
  END cfg_data[76]
  PIN cfg_data[77]
    DIRECTION INPUT ;
    USE SIGNAL ;
    PORT
      LAYER M4 ;
        RECT  0 42.48 0.084 42.504 ;
    END
  END cfg_data[77]
  PIN cfg_data[78]
    DIRECTION INPUT ;
    USE SIGNAL ;
    PORT
      LAYER M4 ;
        RECT  0 42.816 0.084 42.84 ;
    END
  END cfg_data[78]
  PIN cfg_data[79]
    DIRECTION INPUT ;
    USE SIGNAL ;
    PORT
      LAYER M4 ;
        RECT  0 43.152 0.084 43.176 ;
    END
  END cfg_data[79]
  PIN cfg_data[7]
    DIRECTION INPUT ;
    USE SIGNAL ;
    PORT
      LAYER M4 ;
        RECT  0 19.392 0.084 19.416 ;
    END
  END cfg_data[7]
  PIN cfg_data[80]
    DIRECTION INPUT ;
    USE SIGNAL ;
    PORT
      LAYER M4 ;
        RECT  0 43.488 0.084 43.512 ;
    END
  END cfg_data[80]
  PIN cfg_data[81]
    DIRECTION INPUT ;
    USE SIGNAL ;
    PORT
      LAYER M4 ;
        RECT  0 43.824 0.084 43.848 ;
    END
  END cfg_data[81]
  PIN cfg_data[82]
    DIRECTION INPUT ;
    USE SIGNAL ;
    PORT
      LAYER M4 ;
        RECT  0 44.16 0.084 44.184 ;
    END
  END cfg_data[82]
  PIN cfg_data[83]
    DIRECTION INPUT ;
    USE SIGNAL ;
    PORT
      LAYER M4 ;
        RECT  0 44.496 0.084 44.52 ;
    END
  END cfg_data[83]
  PIN cfg_data[84]
    DIRECTION INPUT ;
    USE SIGNAL ;
    PORT
      LAYER M4 ;
        RECT  0 44.784 0.084 44.808 ;
    END
  END cfg_data[84]
  PIN cfg_data[85]
    DIRECTION INPUT ;
    USE SIGNAL ;
    PORT
      LAYER M4 ;
        RECT  0 45.12 0.084 45.144 ;
    END
  END cfg_data[85]
  PIN cfg_data[86]
    DIRECTION INPUT ;
    USE SIGNAL ;
    PORT
      LAYER M4 ;
        RECT  0 45.456 0.084 45.48 ;
    END
  END cfg_data[86]
  PIN cfg_data[87]
    DIRECTION INPUT ;
    USE SIGNAL ;
    PORT
      LAYER M4 ;
        RECT  0 45.792 0.084 45.816 ;
    END
  END cfg_data[87]
  PIN cfg_data[88]
    DIRECTION INPUT ;
    USE SIGNAL ;
    PORT
      LAYER M4 ;
        RECT  0 46.128 0.084 46.152 ;
    END
  END cfg_data[88]
  PIN cfg_data[89]
    DIRECTION INPUT ;
    USE SIGNAL ;
    PORT
      LAYER M4 ;
        RECT  0 46.464 0.084 46.488 ;
    END
  END cfg_data[89]
  PIN cfg_data[8]
    DIRECTION INPUT ;
    USE SIGNAL ;
    PORT
      LAYER M4 ;
        RECT  0 19.728 0.084 19.752 ;
    END
  END cfg_data[8]
  PIN cfg_data[90]
    DIRECTION INPUT ;
    USE SIGNAL ;
    PORT
      LAYER M4 ;
        RECT  0 46.8 0.084 46.824 ;
    END
  END cfg_data[90]
  PIN cfg_data[91]
    DIRECTION INPUT ;
    USE SIGNAL ;
    PORT
      LAYER M4 ;
        RECT  0 47.136 0.084 47.16 ;
    END
  END cfg_data[91]
  PIN cfg_data[92]
    DIRECTION INPUT ;
    USE SIGNAL ;
    PORT
      LAYER M4 ;
        RECT  0 47.424 0.084 47.448 ;
    END
  END cfg_data[92]
  PIN cfg_data[93]
    DIRECTION INPUT ;
    USE SIGNAL ;
    PORT
      LAYER M4 ;
        RECT  0 47.76 0.084 47.784 ;
    END
  END cfg_data[93]
  PIN cfg_data[94]
    DIRECTION INPUT ;
    USE SIGNAL ;
    PORT
      LAYER M4 ;
        RECT  0 48.096 0.084 48.12 ;
    END
  END cfg_data[94]
  PIN cfg_data[95]
    DIRECTION INPUT ;
    USE SIGNAL ;
    PORT
      LAYER M4 ;
        RECT  0 48.432 0.084 48.456 ;
    END
  END cfg_data[95]
  PIN cfg_data[96]
    DIRECTION INPUT ;
    USE SIGNAL ;
    PORT
      LAYER M4 ;
        RECT  0 48.768 0.084 48.792 ;
    END
  END cfg_data[96]
  PIN cfg_data[97]
    DIRECTION INPUT ;
    USE SIGNAL ;
    PORT
      LAYER M4 ;
        RECT  0 49.104 0.084 49.128 ;
    END
  END cfg_data[97]
  PIN cfg_data[98]
    DIRECTION INPUT ;
    USE SIGNAL ;
    PORT
      LAYER M4 ;
        RECT  0 49.44 0.084 49.464 ;
    END
  END cfg_data[98]
  PIN cfg_data[99]
    DIRECTION INPUT ;
    USE SIGNAL ;
    PORT
      LAYER M4 ;
        RECT  0 49.776 0.084 49.8 ;
    END
  END cfg_data[99]
  PIN cfg_data[9]
    DIRECTION INPUT ;
    USE SIGNAL ;
    PORT
      LAYER M4 ;
        RECT  0 20.064 0.084 20.088 ;
    END
  END cfg_data[9]
  PIN cfg_target[0]
    DIRECTION INPUT ;
    USE SIGNAL ;
    PORT
      LAYER M4 ;
        RECT  0 6.48 0.084 6.504 ;
    END
  END cfg_target[0]
  PIN cfg_target[1]
    DIRECTION INPUT ;
    USE SIGNAL ;
    PORT
      LAYER M4 ;
        RECT  0 6.816 0.084 6.84 ;
    END
  END cfg_target[1]
  PIN cfg_target[2]
    DIRECTION INPUT ;
    USE SIGNAL ;
    PORT
      LAYER M4 ;
        RECT  0 7.152 0.084 7.176 ;
    END
  END cfg_target[2]
  PIN cfg_target[3]
    DIRECTION INPUT ;
    USE SIGNAL ;
    PORT
      LAYER M4 ;
        RECT  0 7.488 0.084 7.512 ;
    END
  END cfg_target[3]
  PIN cfg_target[4]
    DIRECTION INPUT ;
    USE SIGNAL ;
    PORT
      LAYER M4 ;
        RECT  0 7.824 0.084 7.848 ;
    END
  END cfg_target[4]
  PIN cfg_target[5]
    DIRECTION INPUT ;
    USE SIGNAL ;
    PORT
      LAYER M4 ;
        RECT  0 8.112 0.084 8.136 ;
    END
  END cfg_target[5]
  PIN cfg_target[6]
    DIRECTION INPUT ;
    USE SIGNAL ;
    PORT
      LAYER M4 ;
        RECT  0 8.448 0.084 8.472 ;
    END
  END cfg_target[6]
  PIN cfg_target[7]
    DIRECTION INPUT ;
    USE SIGNAL ;
    PORT
      LAYER M4 ;
        RECT  0 8.784 0.084 8.808 ;
    END
  END cfg_target[7]
  PIN cfg_v
    DIRECTION INPUT ;
    USE SIGNAL ;
    PORT
      LAYER M4 ;
        RECT  0 4.176 0.084 4.2 ;
    END
    PORT
      LAYER M4 ;
        RECT  0.06 4.176 0.569 4.2 ;
    END
  END cfg_v
  PIN clk
    DIRECTION INPUT ;
    USE SIGNAL ;
    PORT
      LAYER M5 ;
        RECT  55.488 129.516 55.512 129.6 ;
    END
    PORT
      LAYER M5 ;
        RECT  55.488 127.463 55.512 129.552 ;
    END
  END clk
  PIN command[0]
    DIRECTION OUTPUT ;
    USE SIGNAL ;
    PORT
      LAYER M4 ;
        RECT  220.236 4.656 220.32 4.68 ;
    END
    PORT
      LAYER M4 ;
        RECT  219.409 4.656 220.284 4.68 ;
    END
  END command[0]
  PIN command[10]
    DIRECTION OUTPUT ;
    USE SIGNAL ;
    PORT
      LAYER M4 ;
        RECT  220.236 17.52 220.32 17.544 ;
    END
    PORT
      LAYER M4 ;
        RECT  219.409 17.52 220.284 17.544 ;
    END
  END command[10]
  PIN command[11]
    DIRECTION OUTPUT ;
    USE SIGNAL ;
    PORT
      LAYER M4 ;
        RECT  220.236 18.816 220.32 18.84 ;
    END
    PORT
      LAYER M4 ;
        RECT  219.409 18.816 220.284 18.84 ;
    END
  END command[11]
  PIN command[12]
    DIRECTION OUTPUT ;
    USE SIGNAL ;
    PORT
      LAYER M4 ;
        RECT  220.236 20.112 220.32 20.136 ;
    END
    PORT
      LAYER M4 ;
        RECT  219.409 20.112 220.284 20.136 ;
    END
  END command[12]
  PIN command[13]
    DIRECTION OUTPUT ;
    USE SIGNAL ;
    PORT
      LAYER M4 ;
        RECT  220.236 21.408 220.32 21.432 ;
    END
    PORT
      LAYER M4 ;
        RECT  218.869 21.408 220.284 21.432 ;
    END
  END command[13]
  PIN command[14]
    DIRECTION OUTPUT ;
    USE SIGNAL ;
    PORT
      LAYER M4 ;
        RECT  220.236 22.704 220.32 22.728 ;
    END
    PORT
      LAYER M4 ;
        RECT  219.409 22.704 220.284 22.728 ;
    END
  END command[14]
  PIN command[15]
    DIRECTION OUTPUT ;
    USE SIGNAL ;
    PORT
      LAYER M4 ;
        RECT  220.236 23.952 220.32 23.976 ;
    END
    PORT
      LAYER M4 ;
        RECT  219.409 23.952 220.284 23.976 ;
    END
  END command[15]
  PIN command[16]
    DIRECTION OUTPUT ;
    USE SIGNAL ;
    PORT
      LAYER M4 ;
        RECT  220.236 25.248 220.32 25.272 ;
    END
    PORT
      LAYER M4 ;
        RECT  219.409 25.248 220.284 25.272 ;
    END
  END command[16]
  PIN command[17]
    DIRECTION OUTPUT ;
    USE SIGNAL ;
    PORT
      LAYER M4 ;
        RECT  220.236 26.544 220.32 26.568 ;
    END
    PORT
      LAYER M4 ;
        RECT  219.409 26.544 220.284 26.568 ;
    END
  END command[17]
  PIN command[18]
    DIRECTION OUTPUT ;
    USE SIGNAL ;
    PORT
      LAYER M4 ;
        RECT  220.236 27.84 220.32 27.864 ;
    END
    PORT
      LAYER M4 ;
        RECT  219.409 27.84 220.284 27.864 ;
    END
  END command[18]
  PIN command[19]
    DIRECTION OUTPUT ;
    USE SIGNAL ;
    PORT
      LAYER M4 ;
        RECT  220.236 29.136 220.32 29.16 ;
    END
    PORT
      LAYER M4 ;
        RECT  219.409 29.136 220.284 29.16 ;
    END
  END command[19]
  PIN command[1]
    DIRECTION OUTPUT ;
    USE SIGNAL ;
    PORT
      LAYER M4 ;
        RECT  220.236 5.904 220.32 5.928 ;
    END
    PORT
      LAYER M4 ;
        RECT  219.409 5.904 220.284 5.928 ;
    END
  END command[1]
  PIN command[20]
    DIRECTION OUTPUT ;
    USE SIGNAL ;
    PORT
      LAYER M4 ;
        RECT  220.236 30.432 220.32 30.456 ;
    END
    PORT
      LAYER M4 ;
        RECT  218.833 30.432 220.284 30.456 ;
    END
  END command[20]
  PIN command[21]
    DIRECTION OUTPUT ;
    USE SIGNAL ;
    PORT
      LAYER M4 ;
        RECT  220.236 31.728 220.32 31.752 ;
    END
    PORT
      LAYER M4 ;
        RECT  219.409 31.728 220.284 31.752 ;
    END
  END command[21]
  PIN command[22]
    DIRECTION OUTPUT ;
    USE SIGNAL ;
    PORT
      LAYER M4 ;
        RECT  220.236 33.024 220.32 33.048 ;
    END
    PORT
      LAYER M4 ;
        RECT  218.869 33.024 220.284 33.048 ;
    END
  END command[22]
  PIN command[23]
    DIRECTION OUTPUT ;
    USE SIGNAL ;
    PORT
      LAYER M4 ;
        RECT  220.236 34.272 220.32 34.296 ;
    END
    PORT
      LAYER M4 ;
        RECT  219.409 34.272 220.284 34.296 ;
    END
  END command[23]
  PIN command[24]
    DIRECTION OUTPUT ;
    USE SIGNAL ;
    PORT
      LAYER M4 ;
        RECT  220.236 35.568 220.32 35.592 ;
    END
    PORT
      LAYER M4 ;
        RECT  218.833 35.568 220.284 35.592 ;
    END
  END command[24]
  PIN command[25]
    DIRECTION OUTPUT ;
    USE SIGNAL ;
    PORT
      LAYER M4 ;
        RECT  220.236 36.864 220.32 36.888 ;
    END
    PORT
      LAYER M4 ;
        RECT  219.409 36.864 220.284 36.888 ;
    END
  END command[25]
  PIN command[26]
    DIRECTION OUTPUT ;
    USE SIGNAL ;
    PORT
      LAYER M4 ;
        RECT  220.236 38.16 220.32 38.184 ;
    END
    PORT
      LAYER M4 ;
        RECT  219.409 38.16 220.284 38.184 ;
    END
  END command[26]
  PIN command[27]
    DIRECTION OUTPUT ;
    USE SIGNAL ;
    PORT
      LAYER M4 ;
        RECT  220.236 39.456 220.32 39.48 ;
    END
    PORT
      LAYER M4 ;
        RECT  218.869 39.456 220.284 39.48 ;
    END
  END command[27]
  PIN command[28]
    DIRECTION OUTPUT ;
    USE SIGNAL ;
    PORT
      LAYER M4 ;
        RECT  220.236 40.752 220.32 40.776 ;
    END
    PORT
      LAYER M4 ;
        RECT  218.833 40.752 220.284 40.776 ;
    END
  END command[28]
  PIN command[29]
    DIRECTION OUTPUT ;
    USE SIGNAL ;
    PORT
      LAYER M4 ;
        RECT  220.236 42.048 220.32 42.072 ;
    END
    PORT
      LAYER M4 ;
        RECT  219.409 42.048 220.284 42.072 ;
    END
  END command[29]
  PIN command[2]
    DIRECTION OUTPUT ;
    USE SIGNAL ;
    PORT
      LAYER M4 ;
        RECT  220.236 7.2 220.32 7.224 ;
    END
    PORT
      LAYER M4 ;
        RECT  219.409 7.2 220.284 7.224 ;
    END
  END command[2]
  PIN command[30]
    DIRECTION OUTPUT ;
    USE SIGNAL ;
    PORT
      LAYER M4 ;
        RECT  220.236 43.296 220.32 43.32 ;
    END
    PORT
      LAYER M4 ;
        RECT  219.409 43.296 220.284 43.32 ;
    END
  END command[30]
  PIN command[31]
    DIRECTION OUTPUT ;
    USE SIGNAL ;
    PORT
      LAYER M4 ;
        RECT  220.236 44.592 220.32 44.616 ;
    END
    PORT
      LAYER M4 ;
        RECT  218.869 44.592 220.284 44.616 ;
    END
  END command[31]
  PIN command[32]
    DIRECTION OUTPUT ;
    USE SIGNAL ;
    PORT
      LAYER M4 ;
        RECT  220.236 45.888 220.32 45.912 ;
    END
    PORT
      LAYER M4 ;
        RECT  218.869 45.888 220.284 45.912 ;
    END
  END command[32]
  PIN command[33]
    DIRECTION OUTPUT ;
    USE SIGNAL ;
    PORT
      LAYER M4 ;
        RECT  220.236 47.184 220.32 47.208 ;
    END
    PORT
      LAYER M4 ;
        RECT  219.409 47.184 220.284 47.208 ;
    END
  END command[33]
  PIN command[34]
    DIRECTION OUTPUT ;
    USE SIGNAL ;
    PORT
      LAYER M4 ;
        RECT  220.236 48.48 220.32 48.504 ;
    END
    PORT
      LAYER M4 ;
        RECT  219.409 48.48 220.284 48.504 ;
    END
  END command[34]
  PIN command[35]
    DIRECTION OUTPUT ;
    USE SIGNAL ;
    PORT
      LAYER M4 ;
        RECT  220.236 49.776 220.32 49.8 ;
    END
    PORT
      LAYER M4 ;
        RECT  218.869 49.776 220.284 49.8 ;
    END
  END command[35]
  PIN command[36]
    DIRECTION OUTPUT ;
    USE SIGNAL ;
    PORT
      LAYER M4 ;
        RECT  220.236 51.072 220.32 51.096 ;
    END
    PORT
      LAYER M4 ;
        RECT  218.869 51.072 220.284 51.096 ;
    END
  END command[36]
  PIN command[37]
    DIRECTION OUTPUT ;
    USE SIGNAL ;
    PORT
      LAYER M4 ;
        RECT  220.236 52.32 220.32 52.344 ;
    END
    PORT
      LAYER M4 ;
        RECT  219.409 52.32 220.284 52.344 ;
    END
  END command[37]
  PIN command[38]
    DIRECTION OUTPUT ;
    USE SIGNAL ;
    PORT
      LAYER M4 ;
        RECT  220.236 53.616 220.32 53.64 ;
    END
    PORT
      LAYER M4 ;
        RECT  219.445 53.616 220.284 53.64 ;
    END
  END command[38]
  PIN command[39]
    DIRECTION OUTPUT ;
    USE SIGNAL ;
    PORT
      LAYER M4 ;
        RECT  220.236 54.912 220.32 54.936 ;
    END
    PORT
      LAYER M4 ;
        RECT  219.409 54.912 220.284 54.936 ;
    END
  END command[39]
  PIN command[3]
    DIRECTION OUTPUT ;
    USE SIGNAL ;
    PORT
      LAYER M4 ;
        RECT  220.236 8.496 220.32 8.52 ;
    END
    PORT
      LAYER M4 ;
        RECT  219.409 8.496 220.284 8.52 ;
    END
  END command[3]
  PIN command[40]
    DIRECTION OUTPUT ;
    USE SIGNAL ;
    PORT
      LAYER M4 ;
        RECT  220.236 56.208 220.32 56.232 ;
    END
    PORT
      LAYER M4 ;
        RECT  218.869 56.208 220.284 56.232 ;
    END
  END command[40]
  PIN command[41]
    DIRECTION OUTPUT ;
    USE SIGNAL ;
    PORT
      LAYER M4 ;
        RECT  220.236 57.504 220.32 57.528 ;
    END
    PORT
      LAYER M4 ;
        RECT  219.409 57.504 220.284 57.528 ;
    END
  END command[41]
  PIN command[42]
    DIRECTION OUTPUT ;
    USE SIGNAL ;
    PORT
      LAYER M4 ;
        RECT  220.236 58.8 220.32 58.824 ;
    END
    PORT
      LAYER M4 ;
        RECT  219.445 58.8 220.284 58.824 ;
    END
  END command[42]
  PIN command[43]
    DIRECTION OUTPUT ;
    USE SIGNAL ;
    PORT
      LAYER M4 ;
        RECT  220.236 60.096 220.32 60.12 ;
    END
    PORT
      LAYER M4 ;
        RECT  218.869 60.096 220.284 60.12 ;
    END
  END command[43]
  PIN command[44]
    DIRECTION OUTPUT ;
    USE SIGNAL ;
    PORT
      LAYER M4 ;
        RECT  220.236 61.344 220.32 61.368 ;
    END
    PORT
      LAYER M4 ;
        RECT  218.869 61.344 220.284 61.368 ;
    END
  END command[44]
  PIN command[45]
    DIRECTION OUTPUT ;
    USE SIGNAL ;
    PORT
      LAYER M4 ;
        RECT  220.236 62.64 220.32 62.664 ;
    END
    PORT
      LAYER M4 ;
        RECT  219.409 62.64 220.284 62.664 ;
    END
  END command[45]
  PIN command[46]
    DIRECTION OUTPUT ;
    USE SIGNAL ;
    PORT
      LAYER M4 ;
        RECT  220.236 63.936 220.32 63.96 ;
    END
    PORT
      LAYER M4 ;
        RECT  219.409 63.936 220.284 63.96 ;
    END
  END command[46]
  PIN command[47]
    DIRECTION OUTPUT ;
    USE SIGNAL ;
    PORT
      LAYER M4 ;
        RECT  220.236 65.232 220.32 65.256 ;
    END
    PORT
      LAYER M4 ;
        RECT  219.409 65.232 220.284 65.256 ;
    END
  END command[47]
  PIN command[4]
    DIRECTION OUTPUT ;
    USE SIGNAL ;
    PORT
      LAYER M4 ;
        RECT  220.236 9.792 220.32 9.816 ;
    END
    PORT
      LAYER M4 ;
        RECT  218.293 9.792 220.284 9.816 ;
    END
  END command[4]
  PIN command[5]
    DIRECTION OUTPUT ;
    USE SIGNAL ;
    PORT
      LAYER M4 ;
        RECT  220.236 11.088 220.32 11.112 ;
    END
    PORT
      LAYER M4 ;
        RECT  219.409 11.088 220.284 11.112 ;
    END
  END command[5]
  PIN command[6]
    DIRECTION OUTPUT ;
    USE SIGNAL ;
    PORT
      LAYER M4 ;
        RECT  220.236 12.384 220.32 12.408 ;
    END
    PORT
      LAYER M4 ;
        RECT  219.409 12.384 220.284 12.408 ;
    END
  END command[6]
  PIN command[7]
    DIRECTION OUTPUT ;
    USE SIGNAL ;
    PORT
      LAYER M4 ;
        RECT  220.236 13.68 220.32 13.704 ;
    END
    PORT
      LAYER M4 ;
        RECT  219.409 13.68 220.284 13.704 ;
    END
  END command[7]
  PIN command[8]
    DIRECTION OUTPUT ;
    USE SIGNAL ;
    PORT
      LAYER M4 ;
        RECT  220.236 14.928 220.32 14.952 ;
    END
    PORT
      LAYER M4 ;
        RECT  218.293 14.928 220.284 14.952 ;
    END
  END command[8]
  PIN command[9]
    DIRECTION OUTPUT ;
    USE SIGNAL ;
    PORT
      LAYER M4 ;
        RECT  220.236 16.224 220.32 16.248 ;
    END
    PORT
      LAYER M4 ;
        RECT  218.869 16.224 220.284 16.248 ;
    END
  END command[9]
  PIN command_v
    DIRECTION OUTPUT ;
    USE SIGNAL ;
    PORT
      LAYER M4 ;
        RECT  220.236 68.544 220.32 68.568 ;
    END
    PORT
      LAYER M4 ;
        RECT  219.409 68.544 220.284 68.568 ;
    END
  END command_v
  PIN configured
    DIRECTION OUTPUT ;
    USE SIGNAL ;
    PORT
      LAYER M4 ;
        RECT  220.236 121.632 220.32 121.656 ;
    END
    PORT
      LAYER M4 ;
        RECT  219.409 121.632 220.284 121.656 ;
    END
  END configured
  PIN desc_base[0]
    DIRECTION INPUT ;
    USE SIGNAL ;
    PORT
      LAYER M4 ;
        RECT  0 105.888 0.084 105.912 ;
    END
  END desc_base[0]
  PIN desc_base[10]
    DIRECTION INPUT ;
    USE SIGNAL ;
    PORT
      LAYER M4 ;
        RECT  0 109.2 0.084 109.224 ;
    END
  END desc_base[10]
  PIN desc_base[11]
    DIRECTION INPUT ;
    USE SIGNAL ;
    PORT
      LAYER M4 ;
        RECT  0 109.536 0.084 109.56 ;
    END
  END desc_base[11]
  PIN desc_base[1]
    DIRECTION INPUT ;
    USE SIGNAL ;
    PORT
      LAYER M4 ;
        RECT  0 106.224 0.084 106.248 ;
    END
  END desc_base[1]
  PIN desc_base[2]
    DIRECTION INPUT ;
    USE SIGNAL ;
    PORT
      LAYER M4 ;
        RECT  0 106.56 0.084 106.584 ;
    END
  END desc_base[2]
  PIN desc_base[3]
    DIRECTION INPUT ;
    USE SIGNAL ;
    PORT
      LAYER M4 ;
        RECT  0 106.896 0.084 106.92 ;
    END
  END desc_base[3]
  PIN desc_base[4]
    DIRECTION INPUT ;
    USE SIGNAL ;
    PORT
      LAYER M4 ;
        RECT  0 107.232 0.084 107.256 ;
    END
  END desc_base[4]
  PIN desc_base[5]
    DIRECTION INPUT ;
    USE SIGNAL ;
    PORT
      LAYER M4 ;
        RECT  0 107.52 0.084 107.544 ;
    END
  END desc_base[5]
  PIN desc_base[6]
    DIRECTION INPUT ;
    USE SIGNAL ;
    PORT
      LAYER M4 ;
        RECT  0 107.856 0.084 107.88 ;
    END
  END desc_base[6]
  PIN desc_base[7]
    DIRECTION INPUT ;
    USE SIGNAL ;
    PORT
      LAYER M4 ;
        RECT  0 108.192 0.084 108.216 ;
    END
  END desc_base[7]
  PIN desc_base[8]
    DIRECTION INPUT ;
    USE SIGNAL ;
    PORT
      LAYER M4 ;
        RECT  0 108.528 0.084 108.552 ;
    END
  END desc_base[8]
  PIN desc_base[9]
    DIRECTION INPUT ;
    USE SIGNAL ;
    PORT
      LAYER M4 ;
        RECT  0 108.864 0.084 108.888 ;
    END
  END desc_base[9]
  PIN desc_limit[0]
    DIRECTION INPUT ;
    USE SIGNAL ;
    PORT
      LAYER M4 ;
        RECT  0 111.84 0.084 111.864 ;
    END
  END desc_limit[0]
  PIN desc_limit[10]
    DIRECTION INPUT ;
    USE SIGNAL ;
    PORT
      LAYER M4 ;
        RECT  0 115.152 0.084 115.176 ;
    END
  END desc_limit[10]
  PIN desc_limit[11]
    DIRECTION INPUT ;
    USE SIGNAL ;
    PORT
      LAYER M4 ;
        RECT  0 115.488 0.084 115.512 ;
    END
  END desc_limit[11]
  PIN desc_limit[12]
    DIRECTION INPUT ;
    USE SIGNAL ;
    PORT
      LAYER M4 ;
        RECT  0 115.824 0.084 115.848 ;
    END
  END desc_limit[12]
  PIN desc_limit[1]
    DIRECTION INPUT ;
    USE SIGNAL ;
    PORT
      LAYER M4 ;
        RECT  0 112.176 0.084 112.2 ;
    END
  END desc_limit[1]
  PIN desc_limit[2]
    DIRECTION INPUT ;
    USE SIGNAL ;
    PORT
      LAYER M4 ;
        RECT  0 112.512 0.084 112.536 ;
    END
  END desc_limit[2]
  PIN desc_limit[3]
    DIRECTION INPUT ;
    USE SIGNAL ;
    PORT
      LAYER M4 ;
        RECT  0 112.848 0.084 112.872 ;
    END
  END desc_limit[3]
  PIN desc_limit[4]
    DIRECTION INPUT ;
    USE SIGNAL ;
    PORT
      LAYER M4 ;
        RECT  0 113.184 0.084 113.208 ;
    END
  END desc_limit[4]
  PIN desc_limit[5]
    DIRECTION INPUT ;
    USE SIGNAL ;
    PORT
      LAYER M4 ;
        RECT  0 113.52 0.084 113.544 ;
    END
  END desc_limit[5]
  PIN desc_limit[6]
    DIRECTION INPUT ;
    USE SIGNAL ;
    PORT
      LAYER M4 ;
        RECT  0 113.856 0.084 113.88 ;
    END
  END desc_limit[6]
  PIN desc_limit[7]
    DIRECTION INPUT ;
    USE SIGNAL ;
    PORT
      LAYER M4 ;
        RECT  0 114.144 0.084 114.168 ;
    END
  END desc_limit[7]
  PIN desc_limit[8]
    DIRECTION INPUT ;
    USE SIGNAL ;
    PORT
      LAYER M4 ;
        RECT  0 114.48 0.084 114.504 ;
    END
  END desc_limit[8]
  PIN desc_limit[9]
    DIRECTION INPUT ;
    USE SIGNAL ;
    PORT
      LAYER M4 ;
        RECT  0 114.816 0.084 114.84 ;
    END
  END desc_limit[9]
  PIN desc_loops[0]
    DIRECTION INPUT ;
    USE SIGNAL ;
    PORT
      LAYER M4 ;
        RECT  0 118.128 0.084 118.152 ;
    END
  END desc_loops[0]
  PIN desc_loops[10]
    DIRECTION INPUT ;
    USE SIGNAL ;
    PORT
      LAYER M4 ;
        RECT  0 121.44 0.084 121.464 ;
    END
  END desc_loops[10]
  PIN desc_loops[11]
    DIRECTION INPUT ;
    USE SIGNAL ;
    PORT
      LAYER M4 ;
        RECT  0 121.776 0.084 121.8 ;
    END
  END desc_loops[11]
  PIN desc_loops[12]
    DIRECTION INPUT ;
    USE SIGNAL ;
    PORT
      LAYER M4 ;
        RECT  0 122.112 0.084 122.136 ;
    END
  END desc_loops[12]
  PIN desc_loops[13]
    DIRECTION INPUT ;
    USE SIGNAL ;
    PORT
      LAYER M4 ;
        RECT  0 122.448 0.084 122.472 ;
    END
  END desc_loops[13]
  PIN desc_loops[14]
    DIRECTION INPUT ;
    USE SIGNAL ;
    PORT
      LAYER M4 ;
        RECT  0 122.784 0.084 122.808 ;
    END
  END desc_loops[14]
  PIN desc_loops[15]
    DIRECTION INPUT ;
    USE SIGNAL ;
    PORT
      LAYER M4 ;
        RECT  0 123.072 0.084 123.096 ;
    END
  END desc_loops[15]
  PIN desc_loops[1]
    DIRECTION INPUT ;
    USE SIGNAL ;
    PORT
      LAYER M4 ;
        RECT  0 118.464 0.084 118.488 ;
    END
  END desc_loops[1]
  PIN desc_loops[2]
    DIRECTION INPUT ;
    USE SIGNAL ;
    PORT
      LAYER M4 ;
        RECT  0 118.8 0.084 118.824 ;
    END
  END desc_loops[2]
  PIN desc_loops[3]
    DIRECTION INPUT ;
    USE SIGNAL ;
    PORT
      LAYER M4 ;
        RECT  0 119.136 0.084 119.16 ;
    END
  END desc_loops[3]
  PIN desc_loops[4]
    DIRECTION INPUT ;
    USE SIGNAL ;
    PORT
      LAYER M4 ;
        RECT  0 119.472 0.084 119.496 ;
    END
  END desc_loops[4]
  PIN desc_loops[5]
    DIRECTION INPUT ;
    USE SIGNAL ;
    PORT
      LAYER M4 ;
        RECT  0 119.808 0.084 119.832 ;
    END
  END desc_loops[5]
  PIN desc_loops[6]
    DIRECTION INPUT ;
    USE SIGNAL ;
    PORT
      LAYER M4 ;
        RECT  0 120.144 0.084 120.168 ;
    END
  END desc_loops[6]
  PIN desc_loops[7]
    DIRECTION INPUT ;
    USE SIGNAL ;
    PORT
      LAYER M4 ;
        RECT  0 120.432 0.084 120.456 ;
    END
  END desc_loops[7]
  PIN desc_loops[8]
    DIRECTION INPUT ;
    USE SIGNAL ;
    PORT
      LAYER M4 ;
        RECT  0 120.768 0.084 120.792 ;
    END
  END desc_loops[8]
  PIN desc_loops[9]
    DIRECTION INPUT ;
    USE SIGNAL ;
    PORT
      LAYER M4 ;
        RECT  0 121.104 0.084 121.128 ;
    END
  END desc_loops[9]
  PIN desc_v
    DIRECTION INPUT ;
    USE SIGNAL ;
    PORT
      LAYER M4 ;
        RECT  0 103.584 0.084 103.608 ;
    END
    PORT
      LAYER M4 ;
        RECT  0.06 103.584 2.408 103.608 ;
    END
  END desc_v
  PIN done
    DIRECTION OUTPUT ;
    USE SIGNAL ;
    PORT
      LAYER M4 ;
        RECT  220.236 118.368 220.32 118.392 ;
    END
    PORT
      LAYER M4 ;
        RECT  218.869 118.368 220.284 118.392 ;
    END
  END done
  PIN fault
    DIRECTION OUTPUT ;
    USE SIGNAL ;
    PORT
      LAYER M4 ;
        RECT  220.236 124.944 220.32 124.968 ;
    END
    PORT
      LAYER M4 ;
        RECT  219.445 124.944 220.284 124.968 ;
    END
  END fault
  PIN launch_v
    DIRECTION INPUT ;
    USE SIGNAL ;
    PORT
      LAYER M4 ;
        RECT  0 125.424 0.084 125.448 ;
    END
    PORT
      LAYER M4 ;
        RECT  0.06 125.424 2.408 125.448 ;
    END
  END launch_v
  PIN ordinal[0]
    DIRECTION OUTPUT ;
    USE SIGNAL ;
    PORT
      LAYER M4 ;
        RECT  220.236 71.808 220.32 71.832 ;
    END
    PORT
      LAYER M4 ;
        RECT  219.409 71.808 220.284 71.832 ;
    END
  END ordinal[0]
  PIN ordinal[10]
    DIRECTION OUTPUT ;
    USE SIGNAL ;
    PORT
      LAYER M4 ;
        RECT  220.236 84.72 220.32 84.744 ;
    END
    PORT
      LAYER M4 ;
        RECT  218.833 84.72 220.284 84.744 ;
    END
  END ordinal[10]
  PIN ordinal[11]
    DIRECTION OUTPUT ;
    USE SIGNAL ;
    PORT
      LAYER M4 ;
        RECT  220.236 86.016 220.32 86.04 ;
    END
    PORT
      LAYER M4 ;
        RECT  219.409 86.016 220.284 86.04 ;
    END
  END ordinal[11]
  PIN ordinal[12]
    DIRECTION OUTPUT ;
    USE SIGNAL ;
    PORT
      LAYER M4 ;
        RECT  220.236 87.264 220.32 87.288 ;
    END
    PORT
      LAYER M4 ;
        RECT  219.409 87.264 220.284 87.288 ;
    END
  END ordinal[12]
  PIN ordinal[13]
    DIRECTION OUTPUT ;
    USE SIGNAL ;
    PORT
      LAYER M4 ;
        RECT  220.236 88.56 220.32 88.584 ;
    END
    PORT
      LAYER M4 ;
        RECT  218.833 88.56 220.284 88.584 ;
    END
  END ordinal[13]
  PIN ordinal[14]
    DIRECTION OUTPUT ;
    USE SIGNAL ;
    PORT
      LAYER M4 ;
        RECT  220.236 89.856 220.32 89.88 ;
    END
    PORT
      LAYER M4 ;
        RECT  219.409 89.856 220.284 89.88 ;
    END
  END ordinal[14]
  PIN ordinal[15]
    DIRECTION OUTPUT ;
    USE SIGNAL ;
    PORT
      LAYER M4 ;
        RECT  220.236 91.152 220.32 91.176 ;
    END
    PORT
      LAYER M4 ;
        RECT  219.409 91.152 220.284 91.176 ;
    END
  END ordinal[15]
  PIN ordinal[16]
    DIRECTION OUTPUT ;
    USE SIGNAL ;
    PORT
      LAYER M4 ;
        RECT  220.236 92.448 220.32 92.472 ;
    END
    PORT
      LAYER M4 ;
        RECT  218.869 92.448 220.284 92.472 ;
    END
  END ordinal[16]
  PIN ordinal[17]
    DIRECTION OUTPUT ;
    USE SIGNAL ;
    PORT
      LAYER M4 ;
        RECT  220.236 93.744 220.32 93.768 ;
    END
    PORT
      LAYER M4 ;
        RECT  219.409 93.744 220.284 93.768 ;
    END
  END ordinal[17]
  PIN ordinal[18]
    DIRECTION OUTPUT ;
    USE SIGNAL ;
    PORT
      LAYER M4 ;
        RECT  220.236 95.04 220.32 95.064 ;
    END
    PORT
      LAYER M4 ;
        RECT  219.409 95.04 220.284 95.064 ;
    END
  END ordinal[18]
  PIN ordinal[19]
    DIRECTION OUTPUT ;
    USE SIGNAL ;
    PORT
      LAYER M4 ;
        RECT  220.236 96.336 220.32 96.36 ;
    END
    PORT
      LAYER M4 ;
        RECT  219.445 96.336 220.284 96.36 ;
    END
  END ordinal[19]
  PIN ordinal[1]
    DIRECTION OUTPUT ;
    USE SIGNAL ;
    PORT
      LAYER M4 ;
        RECT  220.236 73.104 220.32 73.128 ;
    END
    PORT
      LAYER M4 ;
        RECT  218.833 73.104 220.284 73.128 ;
    END
  END ordinal[1]
  PIN ordinal[20]
    DIRECTION OUTPUT ;
    USE SIGNAL ;
    PORT
      LAYER M4 ;
        RECT  220.236 97.584 220.32 97.608 ;
    END
    PORT
      LAYER M4 ;
        RECT  218.869 97.584 220.284 97.608 ;
    END
  END ordinal[20]
  PIN ordinal[21]
    DIRECTION OUTPUT ;
    USE SIGNAL ;
    PORT
      LAYER M4 ;
        RECT  220.236 98.88 220.32 98.904 ;
    END
    PORT
      LAYER M4 ;
        RECT  219.409 98.88 220.284 98.904 ;
    END
  END ordinal[21]
  PIN ordinal[22]
    DIRECTION OUTPUT ;
    USE SIGNAL ;
    PORT
      LAYER M4 ;
        RECT  220.236 100.176 220.32 100.2 ;
    END
    PORT
      LAYER M4 ;
        RECT  218.257 100.176 220.284 100.2 ;
    END
  END ordinal[22]
  PIN ordinal[23]
    DIRECTION OUTPUT ;
    USE SIGNAL ;
    PORT
      LAYER M4 ;
        RECT  220.236 101.472 220.32 101.496 ;
    END
    PORT
      LAYER M4 ;
        RECT  219.409 101.472 220.284 101.496 ;
    END
  END ordinal[23]
  PIN ordinal[24]
    DIRECTION OUTPUT ;
    USE SIGNAL ;
    PORT
      LAYER M4 ;
        RECT  220.236 102.768 220.32 102.792 ;
    END
    PORT
      LAYER M4 ;
        RECT  219.409 102.768 220.284 102.792 ;
    END
  END ordinal[24]
  PIN ordinal[25]
    DIRECTION OUTPUT ;
    USE SIGNAL ;
    PORT
      LAYER M4 ;
        RECT  220.236 104.064 220.32 104.088 ;
    END
    PORT
      LAYER M4 ;
        RECT  218.869 104.064 220.284 104.088 ;
    END
  END ordinal[25]
  PIN ordinal[26]
    DIRECTION OUTPUT ;
    USE SIGNAL ;
    PORT
      LAYER M4 ;
        RECT  220.236 105.36 220.32 105.384 ;
    END
    PORT
      LAYER M4 ;
        RECT  219.409 105.36 220.284 105.384 ;
    END
  END ordinal[26]
  PIN ordinal[27]
    DIRECTION OUTPUT ;
    USE SIGNAL ;
    PORT
      LAYER M4 ;
        RECT  220.236 106.608 220.32 106.632 ;
    END
    PORT
      LAYER M4 ;
        RECT  219.409 106.608 220.284 106.632 ;
    END
  END ordinal[27]
  PIN ordinal[28]
    DIRECTION OUTPUT ;
    USE SIGNAL ;
    PORT
      LAYER M4 ;
        RECT  220.236 107.904 220.32 107.928 ;
    END
    PORT
      LAYER M4 ;
        RECT  219.409 107.904 220.284 107.928 ;
    END
  END ordinal[28]
  PIN ordinal[29]
    DIRECTION OUTPUT ;
    USE SIGNAL ;
    PORT
      LAYER M4 ;
        RECT  220.236 109.2 220.32 109.224 ;
    END
    PORT
      LAYER M4 ;
        RECT  218.833 109.2 220.284 109.224 ;
    END
  END ordinal[29]
  PIN ordinal[2]
    DIRECTION OUTPUT ;
    USE SIGNAL ;
    PORT
      LAYER M4 ;
        RECT  220.236 74.4 220.32 74.424 ;
    END
    PORT
      LAYER M4 ;
        RECT  219.409 74.4 220.284 74.424 ;
    END
  END ordinal[2]
  PIN ordinal[30]
    DIRECTION OUTPUT ;
    USE SIGNAL ;
    PORT
      LAYER M4 ;
        RECT  220.236 110.496 220.32 110.52 ;
    END
    PORT
      LAYER M4 ;
        RECT  219.409 110.496 220.284 110.52 ;
    END
  END ordinal[30]
  PIN ordinal[31]
    DIRECTION OUTPUT ;
    USE SIGNAL ;
    PORT
      LAYER M4 ;
        RECT  220.236 111.792 220.32 111.816 ;
    END
    PORT
      LAYER M4 ;
        RECT  219.445 111.792 220.284 111.816 ;
    END
  END ordinal[31]
  PIN ordinal[3]
    DIRECTION OUTPUT ;
    USE SIGNAL ;
    PORT
      LAYER M4 ;
        RECT  220.236 75.696 220.32 75.72 ;
    END
    PORT
      LAYER M4 ;
        RECT  219.409 75.696 220.284 75.72 ;
    END
  END ordinal[3]
  PIN ordinal[4]
    DIRECTION OUTPUT ;
    USE SIGNAL ;
    PORT
      LAYER M4 ;
        RECT  220.236 76.992 220.32 77.016 ;
    END
    PORT
      LAYER M4 ;
        RECT  218.869 76.992 220.284 77.016 ;
    END
  END ordinal[4]
  PIN ordinal[5]
    DIRECTION OUTPUT ;
    USE SIGNAL ;
    PORT
      LAYER M4 ;
        RECT  220.236 78.24 220.32 78.264 ;
    END
    PORT
      LAYER M4 ;
        RECT  218.833 78.24 220.284 78.264 ;
    END
  END ordinal[5]
  PIN ordinal[6]
    DIRECTION OUTPUT ;
    USE SIGNAL ;
    PORT
      LAYER M4 ;
        RECT  220.236 79.536 220.32 79.56 ;
    END
    PORT
      LAYER M4 ;
        RECT  219.409 79.536 220.284 79.56 ;
    END
  END ordinal[6]
  PIN ordinal[7]
    DIRECTION OUTPUT ;
    USE SIGNAL ;
    PORT
      LAYER M4 ;
        RECT  220.236 80.832 220.32 80.856 ;
    END
    PORT
      LAYER M4 ;
        RECT  219.409 80.832 220.284 80.856 ;
    END
  END ordinal[7]
  PIN ordinal[8]
    DIRECTION OUTPUT ;
    USE SIGNAL ;
    PORT
      LAYER M4 ;
        RECT  220.236 82.128 220.32 82.152 ;
    END
    PORT
      LAYER M4 ;
        RECT  218.869 82.128 220.284 82.152 ;
    END
  END ordinal[8]
  PIN ordinal[9]
    DIRECTION OUTPUT ;
    USE SIGNAL ;
    PORT
      LAYER M4 ;
        RECT  220.236 83.424 220.32 83.448 ;
    END
    PORT
      LAYER M4 ;
        RECT  219.409 83.424 220.284 83.448 ;
    END
  END ordinal[9]
  PIN rst_n
    DIRECTION INPUT ;
    USE SIGNAL ;
    PORT
      LAYER M5 ;
        RECT  160.512 129.516 160.536 129.6 ;
    END
    PORT
      LAYER M5 ;
        RECT  160.512 127.909 160.536 129.552 ;
    END
  END rst_n
  PIN VDD
    DIRECTION INOUT ;
    USE POWER ;
    PORT
      LAYER M5 ;
        RECT  213.192 2.151 213.312 127.449 ;
        RECT  207.792 2.151 207.912 127.449 ;
        RECT  202.392 2.151 202.512 127.449 ;
        RECT  196.992 2.151 197.112 127.449 ;
        RECT  191.592 2.151 191.712 127.449 ;
        RECT  186.192 2.151 186.312 127.449 ;
        RECT  180.792 2.151 180.912 127.449 ;
        RECT  175.392 2.151 175.512 127.449 ;
        RECT  169.992 2.151 170.112 127.449 ;
        RECT  164.592 2.151 164.712 127.449 ;
        RECT  159.192 2.151 159.312 127.449 ;
        RECT  153.792 2.151 153.912 127.449 ;
        RECT  148.392 2.151 148.512 127.449 ;
        RECT  142.992 2.151 143.112 127.449 ;
        RECT  137.592 2.151 137.712 127.449 ;
        RECT  132.192 2.151 132.312 127.449 ;
        RECT  126.792 2.151 126.912 127.449 ;
        RECT  121.392 2.151 121.512 127.449 ;
        RECT  115.992 2.151 116.112 127.449 ;
        RECT  110.592 2.151 110.712 127.449 ;
        RECT  105.192 2.151 105.312 127.449 ;
        RECT  99.792 2.151 99.912 127.449 ;
        RECT  94.392 2.151 94.512 127.449 ;
        RECT  88.992 2.151 89.112 127.449 ;
        RECT  83.592 2.151 83.712 127.449 ;
        RECT  78.192 2.151 78.312 127.449 ;
        RECT  72.792 2.151 72.912 127.449 ;
        RECT  67.392 2.151 67.512 127.449 ;
        RECT  61.992 2.151 62.112 127.449 ;
        RECT  56.592 2.151 56.712 127.449 ;
        RECT  51.192 2.151 51.312 127.449 ;
        RECT  45.792 2.151 45.912 127.449 ;
        RECT  40.392 2.151 40.512 127.449 ;
        RECT  34.992 2.151 35.112 127.449 ;
        RECT  29.592 2.151 29.712 127.449 ;
        RECT  24.192 2.151 24.312 127.449 ;
        RECT  18.792 2.151 18.912 127.449 ;
        RECT  13.392 2.151 13.512 127.449 ;
        RECT  7.992 2.151 8.112 127.449 ;
        RECT  2.592 2.151 2.712 127.449 ;
    END
  END VDD
  PIN VSS
    DIRECTION INOUT ;
    USE GROUND ;
    PORT
      LAYER M5 ;
        RECT  213 2.137 213.12 127.463 ;
        RECT  207.6 2.137 207.72 127.463 ;
        RECT  202.2 2.137 202.32 127.463 ;
        RECT  196.8 2.137 196.92 127.463 ;
        RECT  191.4 2.137 191.52 127.463 ;
        RECT  186 2.137 186.12 127.463 ;
        RECT  180.6 2.137 180.72 127.463 ;
        RECT  175.2 2.137 175.32 127.463 ;
        RECT  169.8 2.137 169.92 127.463 ;
        RECT  164.4 2.137 164.52 127.463 ;
        RECT  159 2.137 159.12 127.463 ;
        RECT  153.6 2.137 153.72 127.463 ;
        RECT  148.2 2.137 148.32 127.463 ;
        RECT  142.8 2.137 142.92 127.463 ;
        RECT  137.4 2.137 137.52 127.463 ;
        RECT  132 2.137 132.12 127.463 ;
        RECT  126.6 2.137 126.72 127.463 ;
        RECT  121.2 2.137 121.32 127.463 ;
        RECT  115.8 2.137 115.92 127.463 ;
        RECT  110.4 2.137 110.52 127.463 ;
        RECT  105 2.137 105.12 127.463 ;
        RECT  99.6 2.137 99.72 127.463 ;
        RECT  94.2 2.137 94.32 127.463 ;
        RECT  88.8 2.137 88.92 127.463 ;
        RECT  83.4 2.137 83.52 127.463 ;
        RECT  78 2.137 78.12 127.463 ;
        RECT  72.6 2.137 72.72 127.463 ;
        RECT  67.2 2.137 67.32 127.463 ;
        RECT  61.8 2.137 61.92 127.463 ;
        RECT  56.4 2.137 56.52 127.463 ;
        RECT  51 2.137 51.12 127.463 ;
        RECT  45.6 2.137 45.72 127.463 ;
        RECT  40.2 2.137 40.32 127.463 ;
        RECT  34.8 2.137 34.92 127.463 ;
        RECT  29.4 2.137 29.52 127.463 ;
        RECT  24 2.137 24.12 127.463 ;
        RECT  18.6 2.137 18.72 127.463 ;
        RECT  13.2 2.137 13.32 127.463 ;
        RECT  7.8 2.137 7.92 127.463 ;
        RECT  2.4 2.137 2.52 127.463 ;
    END
  END VSS
  # OT_OBS_CLOSED layer=M5 d_um=1.536 added=190
  OBS
    LAYER RVTN ;
     RECT  2.16 2.16 218.16 2.295 ;
     RECT  2.16 2.565 218.16 2.835 ;
     RECT  2.16 3.105 218.16 3.375 ;
     RECT  2.16 3.645 218.16 3.915 ;
     RECT  2.16 4.185 218.16 4.455 ;
     RECT  2.16 4.725 218.16 4.995 ;
     RECT  2.16 5.265 218.16 5.535 ;
     RECT  2.16 5.805 218.16 6.075 ;
     RECT  2.16 6.345 218.16 6.615 ;
     RECT  2.16 6.885 218.16 7.155 ;
     RECT  2.16 7.425 218.16 7.695 ;
     RECT  2.16 7.965 218.16 8.235 ;
     RECT  2.16 8.505 218.16 8.775 ;
     RECT  2.16 9.045 218.16 9.315 ;
     RECT  2.16 9.585 218.16 9.855 ;
     RECT  2.16 10.125 218.16 10.395 ;
     RECT  2.16 10.665 218.16 10.935 ;
     RECT  2.16 11.205 218.16 11.475 ;
     RECT  2.16 11.745 218.16 12.015 ;
     RECT  2.16 12.285 218.16 12.555 ;
     RECT  2.16 12.825 218.16 13.095 ;
     RECT  2.16 13.365 218.16 13.635 ;
     RECT  2.16 13.905 218.16 14.175 ;
     RECT  2.16 14.445 218.16 14.715 ;
     RECT  2.16 14.985 218.16 15.255 ;
     RECT  2.16 15.525 218.16 15.795 ;
     RECT  2.16 16.065 218.16 16.335 ;
     RECT  2.16 16.605 218.16 16.875 ;
     RECT  2.16 17.145 218.16 17.415 ;
     RECT  2.16 17.685 218.16 17.955 ;
     RECT  2.16 18.225 218.16 18.495 ;
     RECT  2.16 18.765 218.16 19.035 ;
     RECT  2.16 19.305 218.16 19.575 ;
     RECT  2.16 19.845 218.16 20.115 ;
     RECT  2.16 20.385 218.16 20.655 ;
     RECT  2.16 20.925 218.16 21.195 ;
     RECT  2.16 21.465 218.16 21.735 ;
     RECT  2.16 22.005 218.16 22.275 ;
     RECT  2.16 22.545 218.16 22.815 ;
     RECT  2.16 23.085 218.16 23.355 ;
     RECT  2.16 23.625 218.16 23.895 ;
     RECT  2.16 24.165 218.16 24.435 ;
     RECT  2.16 24.705 218.16 24.975 ;
     RECT  2.16 25.245 218.16 25.515 ;
     RECT  2.16 25.785 218.16 25.92 ;
     RECT  2.16 25.92 20.844 26.055 ;
     RECT  199.692 25.92 218.16 26.055 ;
     RECT  2.16 26.325 20.844 26.595 ;
     RECT  199.692 26.325 218.16 26.595 ;
     RECT  2.16 26.865 20.844 27.135 ;
     RECT  199.692 26.865 218.16 27.135 ;
     RECT  2.16 27.405 20.844 27.675 ;
     RECT  199.692 27.405 218.16 27.675 ;
     RECT  2.16 27.945 20.844 28.215 ;
     RECT  199.692 27.945 218.16 28.215 ;
     RECT  2.16 28.485 20.844 28.755 ;
     RECT  199.692 28.485 218.16 28.755 ;
     RECT  2.16 29.025 20.844 29.295 ;
     RECT  199.692 29.025 218.16 29.295 ;
     RECT  2.16 29.565 20.844 29.835 ;
     RECT  199.692 29.565 218.16 29.835 ;
     RECT  2.16 30.105 20.844 30.375 ;
     RECT  199.692 30.105 218.16 30.375 ;
     RECT  2.16 30.645 20.844 30.915 ;
     RECT  199.692 30.645 218.16 30.915 ;
     RECT  2.16 31.185 20.844 31.455 ;
     RECT  199.692 31.185 218.16 31.455 ;
     RECT  2.16 31.725 20.844 31.995 ;
     RECT  199.692 31.725 218.16 31.995 ;
     RECT  2.16 32.265 20.844 32.535 ;
     RECT  199.692 32.265 218.16 32.535 ;
     RECT  2.16 32.805 20.844 33.075 ;
     RECT  199.692 32.805 218.16 33.075 ;
     RECT  2.16 33.345 20.844 33.615 ;
     RECT  199.692 33.345 218.16 33.615 ;
     RECT  2.16 33.885 20.844 34.155 ;
     RECT  199.692 33.885 218.16 34.155 ;
     RECT  2.16 34.425 20.844 34.695 ;
     RECT  199.692 34.425 218.16 34.695 ;
     RECT  2.16 34.965 20.844 35.235 ;
     RECT  199.692 34.965 218.16 35.235 ;
     RECT  2.16 35.505 20.844 35.775 ;
     RECT  199.692 35.505 218.16 35.775 ;
     RECT  2.16 36.045 20.844 36.315 ;
     RECT  199.692 36.045 218.16 36.315 ;
     RECT  2.16 36.585 20.844 36.855 ;
     RECT  199.692 36.585 218.16 36.855 ;
     RECT  2.16 37.125 20.844 37.395 ;
     RECT  199.692 37.125 218.16 37.395 ;
     RECT  2.16 37.665 20.844 37.935 ;
     RECT  199.692 37.665 218.16 37.935 ;
     RECT  2.16 38.205 20.844 38.475 ;
     RECT  199.692 38.205 218.16 38.475 ;
     RECT  2.16 38.745 20.844 39.015 ;
     RECT  199.692 38.745 218.16 39.015 ;
     RECT  2.16 39.285 20.844 39.555 ;
     RECT  199.692 39.285 218.16 39.555 ;
     RECT  2.16 39.825 20.844 40.095 ;
     RECT  199.692 39.825 218.16 40.095 ;
     RECT  2.16 40.365 20.844 40.635 ;
     RECT  199.692 40.365 218.16 40.635 ;
     RECT  2.16 40.905 20.844 41.175 ;
     RECT  199.692 40.905 218.16 41.175 ;
     RECT  2.16 41.445 20.844 41.715 ;
     RECT  199.692 41.445 218.16 41.715 ;
     RECT  2.16 41.985 20.844 42.255 ;
     RECT  199.692 41.985 218.16 42.255 ;
     RECT  2.16 42.525 20.844 42.795 ;
     RECT  199.692 42.525 218.16 42.795 ;
     RECT  2.16 43.065 20.844 43.335 ;
     RECT  199.692 43.065 218.16 43.335 ;
     RECT  2.16 43.605 20.844 43.875 ;
     RECT  199.692 43.605 218.16 43.875 ;
     RECT  2.16 44.145 20.844 44.415 ;
     RECT  199.692 44.145 218.16 44.415 ;
     RECT  2.16 44.685 20.844 44.955 ;
     RECT  199.692 44.685 218.16 44.955 ;
     RECT  2.16 45.225 20.844 45.495 ;
     RECT  199.692 45.225 218.16 45.495 ;
     RECT  2.16 45.765 20.844 46.035 ;
     RECT  199.692 45.765 218.16 46.035 ;
     RECT  2.16 46.305 20.844 46.575 ;
     RECT  199.692 46.305 218.16 46.575 ;
     RECT  2.16 46.845 20.844 47.115 ;
     RECT  199.692 46.845 218.16 47.115 ;
     RECT  2.16 47.385 20.844 47.655 ;
     RECT  199.692 47.385 218.16 47.655 ;
     RECT  2.16 47.925 20.844 48.195 ;
     RECT  199.692 47.925 218.16 48.195 ;
     RECT  2.16 48.465 20.844 48.735 ;
     RECT  199.692 48.465 218.16 48.735 ;
     RECT  2.16 49.005 20.844 49.275 ;
     RECT  199.692 49.005 218.16 49.275 ;
     RECT  2.16 49.545 20.844 49.815 ;
     RECT  199.692 49.545 218.16 49.815 ;
     RECT  2.16 50.085 20.844 50.355 ;
     RECT  199.692 50.085 218.16 50.355 ;
     RECT  2.16 50.625 20.844 50.895 ;
     RECT  199.692 50.625 218.16 50.895 ;
     RECT  2.16 51.165 20.844 51.435 ;
     RECT  199.692 51.165 218.16 51.435 ;
     RECT  2.16 51.705 20.844 51.975 ;
     RECT  199.692 51.705 218.16 51.975 ;
     RECT  2.16 52.245 20.844 52.515 ;
     RECT  199.692 52.245 218.16 52.515 ;
     RECT  2.16 52.785 20.844 53.055 ;
     RECT  199.692 52.785 218.16 53.055 ;
     RECT  2.16 53.325 20.844 53.595 ;
     RECT  199.692 53.325 218.16 53.595 ;
     RECT  2.16 53.865 20.844 54.135 ;
     RECT  199.692 53.865 218.16 54.135 ;
     RECT  2.16 54.405 20.844 54.675 ;
     RECT  199.692 54.405 218.16 54.675 ;
     RECT  2.16 54.945 20.844 55.215 ;
     RECT  199.692 54.945 218.16 55.215 ;
     RECT  2.16 55.485 20.844 55.755 ;
     RECT  199.692 55.485 218.16 55.755 ;
     RECT  2.16 56.025 20.844 56.295 ;
     RECT  199.692 56.025 218.16 56.295 ;
     RECT  2.16 56.565 20.844 56.835 ;
     RECT  199.692 56.565 218.16 56.835 ;
     RECT  2.16 57.105 20.844 57.375 ;
     RECT  199.692 57.105 218.16 57.375 ;
     RECT  2.16 57.645 20.844 57.915 ;
     RECT  199.692 57.645 218.16 57.915 ;
     RECT  2.16 58.185 20.844 58.455 ;
     RECT  199.692 58.185 218.16 58.455 ;
     RECT  2.16 58.725 20.844 58.995 ;
     RECT  199.692 58.725 218.16 58.995 ;
     RECT  2.16 59.265 20.844 59.535 ;
     RECT  199.692 59.265 218.16 59.535 ;
     RECT  2.16 59.805 20.844 60.075 ;
     RECT  199.692 59.805 218.16 60.075 ;
     RECT  2.16 60.345 20.844 60.615 ;
     RECT  199.692 60.345 218.16 60.615 ;
     RECT  2.16 60.885 20.844 61.155 ;
     RECT  199.692 60.885 218.16 61.155 ;
     RECT  2.16 61.425 20.844 61.695 ;
     RECT  199.692 61.425 218.16 61.695 ;
     RECT  2.16 61.965 20.844 62.235 ;
     RECT  199.692 61.965 218.16 62.235 ;
     RECT  2.16 62.505 20.844 62.775 ;
     RECT  199.692 62.505 218.16 62.775 ;
     RECT  2.16 63.045 20.844 63.315 ;
     RECT  199.692 63.045 218.16 63.315 ;
     RECT  2.16 63.585 20.844 63.855 ;
     RECT  199.692 63.585 218.16 63.855 ;
     RECT  2.16 64.125 20.844 64.395 ;
     RECT  199.692 64.125 218.16 64.395 ;
     RECT  2.16 64.665 20.844 64.935 ;
     RECT  199.692 64.665 218.16 64.935 ;
     RECT  2.16 65.205 20.844 65.475 ;
     RECT  199.692 65.205 218.16 65.475 ;
     RECT  2.16 65.745 20.844 66.015 ;
     RECT  199.692 65.745 218.16 66.015 ;
     RECT  2.16 66.285 20.844 66.555 ;
     RECT  199.692 66.285 218.16 66.555 ;
     RECT  2.16 66.825 20.844 67.095 ;
     RECT  199.692 66.825 218.16 67.095 ;
     RECT  2.16 67.365 20.844 67.635 ;
     RECT  199.692 67.365 218.16 67.635 ;
     RECT  2.16 67.905 20.844 68.175 ;
     RECT  199.692 67.905 218.16 68.175 ;
     RECT  2.16 68.445 20.844 68.715 ;
     RECT  199.692 68.445 218.16 68.715 ;
     RECT  2.16 68.985 20.844 69.255 ;
     RECT  199.692 68.985 218.16 69.255 ;
     RECT  2.16 69.525 20.844 69.795 ;
     RECT  199.692 69.525 218.16 69.795 ;
     RECT  2.16 70.065 20.844 70.335 ;
     RECT  199.692 70.065 218.16 70.335 ;
     RECT  2.16 70.605 20.844 70.875 ;
     RECT  199.692 70.605 218.16 70.875 ;
     RECT  2.16 71.145 20.844 71.415 ;
     RECT  199.692 71.145 218.16 71.415 ;
     RECT  2.16 71.685 20.844 71.955 ;
     RECT  199.692 71.685 218.16 71.955 ;
     RECT  2.16 72.225 20.844 72.495 ;
     RECT  199.692 72.225 218.16 72.495 ;
     RECT  2.16 72.765 20.844 73.035 ;
     RECT  199.692 72.765 218.16 73.035 ;
     RECT  2.16 73.305 20.844 73.575 ;
     RECT  199.692 73.305 218.16 73.575 ;
     RECT  2.16 73.845 20.844 74.115 ;
     RECT  199.692 73.845 218.16 74.115 ;
     RECT  2.16 74.385 20.844 74.655 ;
     RECT  199.692 74.385 218.16 74.655 ;
     RECT  2.16 74.925 20.844 75.195 ;
     RECT  199.692 74.925 218.16 75.195 ;
     RECT  2.16 75.465 20.844 75.735 ;
     RECT  199.692 75.465 218.16 75.735 ;
     RECT  2.16 76.005 20.844 76.275 ;
     RECT  199.692 76.005 218.16 76.275 ;
     RECT  2.16 76.545 20.844 76.815 ;
     RECT  199.692 76.545 218.16 76.815 ;
     RECT  2.16 77.085 20.844 77.355 ;
     RECT  199.692 77.085 218.16 77.355 ;
     RECT  2.16 77.625 20.844 77.895 ;
     RECT  199.692 77.625 218.16 77.895 ;
     RECT  2.16 78.165 20.844 78.435 ;
     RECT  199.692 78.165 218.16 78.435 ;
     RECT  2.16 78.705 20.844 78.975 ;
     RECT  199.692 78.705 218.16 78.975 ;
     RECT  2.16 79.245 20.844 79.515 ;
     RECT  199.692 79.245 218.16 79.515 ;
     RECT  2.16 79.785 20.844 80.055 ;
     RECT  199.692 79.785 218.16 80.055 ;
     RECT  2.16 80.325 20.844 80.595 ;
     RECT  199.692 80.325 218.16 80.595 ;
     RECT  2.16 80.865 20.844 81.135 ;
     RECT  199.692 80.865 218.16 81.135 ;
     RECT  2.16 81.405 20.844 81.675 ;
     RECT  199.692 81.405 218.16 81.675 ;
     RECT  2.16 81.945 20.844 82.215 ;
     RECT  199.692 81.945 218.16 82.215 ;
     RECT  2.16 82.485 20.844 82.755 ;
     RECT  199.692 82.485 218.16 82.755 ;
     RECT  2.16 83.025 20.844 83.295 ;
     RECT  199.692 83.025 218.16 83.295 ;
     RECT  2.16 83.565 20.844 83.835 ;
     RECT  199.692 83.565 218.16 83.835 ;
     RECT  2.16 84.105 20.844 84.375 ;
     RECT  199.692 84.105 218.16 84.375 ;
     RECT  2.16 84.645 20.844 84.915 ;
     RECT  199.692 84.645 218.16 84.915 ;
     RECT  2.16 85.185 20.844 85.455 ;
     RECT  199.692 85.185 218.16 85.455 ;
     RECT  2.16 85.725 20.844 85.995 ;
     RECT  199.692 85.725 218.16 85.995 ;
     RECT  2.16 86.265 20.844 86.535 ;
     RECT  199.692 86.265 218.16 86.535 ;
     RECT  2.16 86.805 20.844 87.075 ;
     RECT  199.692 86.805 218.16 87.075 ;
     RECT  2.16 87.345 20.844 87.615 ;
     RECT  199.692 87.345 218.16 87.615 ;
     RECT  2.16 87.885 20.844 88.155 ;
     RECT  199.692 87.885 218.16 88.155 ;
     RECT  2.16 88.425 20.844 88.695 ;
     RECT  199.692 88.425 218.16 88.695 ;
     RECT  2.16 88.965 20.844 89.235 ;
     RECT  199.692 88.965 218.16 89.235 ;
     RECT  2.16 89.505 20.844 89.775 ;
     RECT  199.692 89.505 218.16 89.775 ;
     RECT  2.16 90.045 20.844 90.315 ;
     RECT  199.692 90.045 218.16 90.315 ;
     RECT  2.16 90.585 20.844 90.855 ;
     RECT  199.692 90.585 218.16 90.855 ;
     RECT  2.16 91.125 20.844 91.395 ;
     RECT  199.692 91.125 218.16 91.395 ;
     RECT  2.16 91.665 20.844 91.935 ;
     RECT  199.692 91.665 218.16 91.935 ;
     RECT  2.16 92.205 20.844 92.475 ;
     RECT  199.692 92.205 218.16 92.475 ;
     RECT  2.16 92.745 20.844 93.015 ;
     RECT  199.692 92.745 218.16 93.015 ;
     RECT  2.16 93.285 20.844 93.555 ;
     RECT  199.692 93.285 218.16 93.555 ;
     RECT  2.16 93.825 20.844 94.095 ;
     RECT  199.692 93.825 218.16 94.095 ;
     RECT  2.16 94.365 20.844 94.635 ;
     RECT  199.692 94.365 218.16 94.635 ;
     RECT  2.16 94.905 20.844 95.175 ;
     RECT  199.692 94.905 218.16 95.175 ;
     RECT  2.16 95.445 20.844 95.715 ;
     RECT  199.692 95.445 218.16 95.715 ;
     RECT  2.16 95.985 20.844 96.255 ;
     RECT  199.692 95.985 218.16 96.255 ;
     RECT  2.16 96.525 20.844 96.795 ;
     RECT  199.692 96.525 218.16 96.795 ;
     RECT  2.16 97.065 20.844 97.335 ;
     RECT  199.692 97.065 218.16 97.335 ;
     RECT  2.16 97.605 20.844 97.875 ;
     RECT  199.692 97.605 218.16 97.875 ;
     RECT  2.16 98.145 20.844 98.415 ;
     RECT  199.692 98.145 218.16 98.415 ;
     RECT  2.16 98.685 20.844 98.955 ;
     RECT  199.692 98.685 218.16 98.955 ;
     RECT  2.16 99.225 20.844 99.495 ;
     RECT  199.692 99.225 218.16 99.495 ;
     RECT  2.16 99.765 20.844 100.035 ;
     RECT  199.692 99.765 218.16 100.035 ;
     RECT  2.16 100.305 20.844 100.575 ;
     RECT  199.692 100.305 218.16 100.575 ;
     RECT  2.16 100.845 218.16 101.115 ;
     RECT  2.16 101.385 218.16 101.655 ;
     RECT  2.16 101.925 218.16 102.195 ;
     RECT  2.16 102.465 218.16 102.735 ;
     RECT  2.16 103.005 218.16 103.275 ;
     RECT  2.16 103.545 218.16 103.815 ;
     RECT  2.16 104.085 218.16 104.355 ;
     RECT  2.16 104.625 218.16 104.895 ;
     RECT  2.16 105.165 218.16 105.435 ;
     RECT  2.16 105.705 218.16 105.975 ;
     RECT  2.16 106.245 218.16 106.515 ;
     RECT  2.16 106.785 218.16 107.055 ;
     RECT  2.16 107.325 218.16 107.595 ;
     RECT  2.16 107.865 218.16 108.135 ;
     RECT  2.16 108.405 218.16 108.675 ;
     RECT  2.16 108.945 218.16 109.215 ;
     RECT  2.16 109.485 218.16 109.755 ;
     RECT  2.16 110.025 218.16 110.295 ;
     RECT  2.16 110.565 218.16 110.835 ;
     RECT  2.16 111.105 218.16 111.375 ;
     RECT  2.16 111.645 218.16 111.915 ;
     RECT  2.16 112.185 218.16 112.455 ;
     RECT  2.16 112.725 218.16 112.995 ;
     RECT  2.16 113.265 218.16 113.535 ;
     RECT  2.16 113.805 218.16 114.075 ;
     RECT  2.16 114.345 218.16 114.615 ;
     RECT  2.16 114.885 218.16 115.155 ;
     RECT  2.16 115.425 218.16 115.695 ;
     RECT  2.16 115.965 218.16 116.235 ;
     RECT  2.16 116.505 218.16 116.775 ;
     RECT  2.16 117.045 218.16 117.315 ;
     RECT  2.16 117.585 218.16 117.855 ;
     RECT  2.16 118.125 218.16 118.395 ;
     RECT  2.16 118.665 218.16 118.935 ;
     RECT  2.16 119.205 218.16 119.475 ;
     RECT  2.16 119.745 218.16 120.015 ;
     RECT  2.16 120.285 218.16 120.555 ;
     RECT  2.16 120.825 218.16 121.095 ;
     RECT  2.16 121.365 218.16 121.635 ;
     RECT  2.16 121.905 218.16 122.175 ;
     RECT  2.16 122.445 218.16 122.715 ;
     RECT  2.16 122.985 218.16 123.255 ;
     RECT  2.16 123.525 218.16 123.795 ;
     RECT  2.16 124.065 218.16 124.335 ;
     RECT  2.16 124.605 218.16 124.875 ;
     RECT  2.16 125.145 218.16 125.415 ;
     RECT  2.16 125.685 218.16 125.955 ;
     RECT  2.16 126.225 218.16 126.495 ;
     RECT  2.16 126.765 218.16 127.035 ;
     RECT  2.16 127.305 218.16 127.44 ;
    LAYER RVTP ;
     RECT  2.16 2.295 218.16 2.565 ;
     RECT  2.16 2.835 218.16 3.105 ;
     RECT  2.16 3.375 218.16 3.645 ;
     RECT  2.16 3.915 218.16 4.185 ;
     RECT  2.16 4.455 218.16 4.725 ;
     RECT  2.16 4.995 218.16 5.265 ;
     RECT  2.16 5.535 218.16 5.805 ;
     RECT  2.16 6.075 218.16 6.345 ;
     RECT  2.16 6.615 218.16 6.885 ;
     RECT  2.16 7.155 218.16 7.425 ;
     RECT  2.16 7.695 218.16 7.965 ;
     RECT  2.16 8.235 218.16 8.505 ;
     RECT  2.16 8.775 218.16 9.045 ;
     RECT  2.16 9.315 218.16 9.585 ;
     RECT  2.16 9.855 218.16 10.125 ;
     RECT  2.16 10.395 218.16 10.665 ;
     RECT  2.16 10.935 218.16 11.205 ;
     RECT  2.16 11.475 218.16 11.745 ;
     RECT  2.16 12.015 218.16 12.285 ;
     RECT  2.16 12.555 218.16 12.825 ;
     RECT  2.16 13.095 218.16 13.365 ;
     RECT  2.16 13.635 218.16 13.905 ;
     RECT  2.16 14.175 218.16 14.445 ;
     RECT  2.16 14.715 218.16 14.985 ;
     RECT  2.16 15.255 218.16 15.525 ;
     RECT  2.16 15.795 218.16 16.065 ;
     RECT  2.16 16.335 218.16 16.605 ;
     RECT  2.16 16.875 218.16 17.145 ;
     RECT  2.16 17.415 218.16 17.685 ;
     RECT  2.16 17.955 218.16 18.225 ;
     RECT  2.16 18.495 218.16 18.765 ;
     RECT  2.16 19.035 218.16 19.305 ;
     RECT  2.16 19.575 218.16 19.845 ;
     RECT  2.16 20.115 218.16 20.385 ;
     RECT  2.16 20.655 218.16 20.925 ;
     RECT  2.16 21.195 218.16 21.465 ;
     RECT  2.16 21.735 218.16 22.005 ;
     RECT  2.16 22.275 218.16 22.545 ;
     RECT  2.16 22.815 218.16 23.085 ;
     RECT  2.16 23.355 218.16 23.625 ;
     RECT  2.16 23.895 218.16 24.165 ;
     RECT  2.16 24.435 218.16 24.705 ;
     RECT  2.16 24.975 218.16 25.245 ;
     RECT  2.16 25.515 218.16 25.785 ;
     RECT  2.16 26.055 20.844 26.325 ;
     RECT  199.692 26.055 218.16 26.325 ;
     RECT  2.16 26.595 20.844 26.865 ;
     RECT  199.692 26.595 218.16 26.865 ;
     RECT  2.16 27.135 20.844 27.405 ;
     RECT  199.692 27.135 218.16 27.405 ;
     RECT  2.16 27.675 20.844 27.945 ;
     RECT  199.692 27.675 218.16 27.945 ;
     RECT  2.16 28.215 20.844 28.485 ;
     RECT  199.692 28.215 218.16 28.485 ;
     RECT  2.16 28.755 20.844 29.025 ;
     RECT  199.692 28.755 218.16 29.025 ;
     RECT  2.16 29.295 20.844 29.565 ;
     RECT  199.692 29.295 218.16 29.565 ;
     RECT  2.16 29.835 20.844 30.105 ;
     RECT  199.692 29.835 218.16 30.105 ;
     RECT  2.16 30.375 20.844 30.645 ;
     RECT  199.692 30.375 218.16 30.645 ;
     RECT  2.16 30.915 20.844 31.185 ;
     RECT  199.692 30.915 218.16 31.185 ;
     RECT  2.16 31.455 20.844 31.725 ;
     RECT  199.692 31.455 218.16 31.725 ;
     RECT  2.16 31.995 20.844 32.265 ;
     RECT  199.692 31.995 218.16 32.265 ;
     RECT  2.16 32.535 20.844 32.805 ;
     RECT  199.692 32.535 218.16 32.805 ;
     RECT  2.16 33.075 20.844 33.345 ;
     RECT  199.692 33.075 218.16 33.345 ;
     RECT  2.16 33.615 20.844 33.885 ;
     RECT  199.692 33.615 218.16 33.885 ;
     RECT  2.16 34.155 20.844 34.425 ;
     RECT  199.692 34.155 218.16 34.425 ;
     RECT  2.16 34.695 20.844 34.965 ;
     RECT  199.692 34.695 218.16 34.965 ;
     RECT  2.16 35.235 20.844 35.505 ;
     RECT  199.692 35.235 218.16 35.505 ;
     RECT  2.16 35.775 20.844 36.045 ;
     RECT  199.692 35.775 218.16 36.045 ;
     RECT  2.16 36.315 20.844 36.585 ;
     RECT  199.692 36.315 218.16 36.585 ;
     RECT  2.16 36.855 20.844 37.125 ;
     RECT  199.692 36.855 218.16 37.125 ;
     RECT  2.16 37.395 20.844 37.665 ;
     RECT  199.692 37.395 218.16 37.665 ;
     RECT  2.16 37.935 20.844 38.205 ;
     RECT  199.692 37.935 218.16 38.205 ;
     RECT  2.16 38.475 20.844 38.745 ;
     RECT  199.692 38.475 218.16 38.745 ;
     RECT  2.16 39.015 20.844 39.285 ;
     RECT  199.692 39.015 218.16 39.285 ;
     RECT  2.16 39.555 20.844 39.825 ;
     RECT  199.692 39.555 218.16 39.825 ;
     RECT  2.16 40.095 20.844 40.365 ;
     RECT  199.692 40.095 218.16 40.365 ;
     RECT  2.16 40.635 20.844 40.905 ;
     RECT  199.692 40.635 218.16 40.905 ;
     RECT  2.16 41.175 20.844 41.445 ;
     RECT  199.692 41.175 218.16 41.445 ;
     RECT  2.16 41.715 20.844 41.985 ;
     RECT  199.692 41.715 218.16 41.985 ;
     RECT  2.16 42.255 20.844 42.525 ;
     RECT  199.692 42.255 218.16 42.525 ;
     RECT  2.16 42.795 20.844 43.065 ;
     RECT  199.692 42.795 218.16 43.065 ;
     RECT  2.16 43.335 20.844 43.605 ;
     RECT  199.692 43.335 218.16 43.605 ;
     RECT  2.16 43.875 20.844 44.145 ;
     RECT  199.692 43.875 218.16 44.145 ;
     RECT  2.16 44.415 20.844 44.685 ;
     RECT  199.692 44.415 218.16 44.685 ;
     RECT  2.16 44.955 20.844 45.225 ;
     RECT  199.692 44.955 218.16 45.225 ;
     RECT  2.16 45.495 20.844 45.765 ;
     RECT  199.692 45.495 218.16 45.765 ;
     RECT  2.16 46.035 20.844 46.305 ;
     RECT  199.692 46.035 218.16 46.305 ;
     RECT  2.16 46.575 20.844 46.845 ;
     RECT  199.692 46.575 218.16 46.845 ;
     RECT  2.16 47.115 20.844 47.385 ;
     RECT  199.692 47.115 218.16 47.385 ;
     RECT  2.16 47.655 20.844 47.925 ;
     RECT  199.692 47.655 218.16 47.925 ;
     RECT  2.16 48.195 20.844 48.465 ;
     RECT  199.692 48.195 218.16 48.465 ;
     RECT  2.16 48.735 20.844 49.005 ;
     RECT  199.692 48.735 218.16 49.005 ;
     RECT  2.16 49.275 20.844 49.545 ;
     RECT  199.692 49.275 218.16 49.545 ;
     RECT  2.16 49.815 20.844 50.085 ;
     RECT  199.692 49.815 218.16 50.085 ;
     RECT  2.16 50.355 20.844 50.625 ;
     RECT  199.692 50.355 218.16 50.625 ;
     RECT  2.16 50.895 20.844 51.165 ;
     RECT  199.692 50.895 218.16 51.165 ;
     RECT  2.16 51.435 20.844 51.705 ;
     RECT  199.692 51.435 218.16 51.705 ;
     RECT  2.16 51.975 20.844 52.245 ;
     RECT  199.692 51.975 218.16 52.245 ;
     RECT  2.16 52.515 20.844 52.785 ;
     RECT  199.692 52.515 218.16 52.785 ;
     RECT  2.16 53.055 20.844 53.325 ;
     RECT  199.692 53.055 218.16 53.325 ;
     RECT  2.16 53.595 20.844 53.865 ;
     RECT  199.692 53.595 218.16 53.865 ;
     RECT  2.16 54.135 20.844 54.405 ;
     RECT  199.692 54.135 218.16 54.405 ;
     RECT  2.16 54.675 20.844 54.945 ;
     RECT  199.692 54.675 218.16 54.945 ;
     RECT  2.16 55.215 20.844 55.485 ;
     RECT  199.692 55.215 218.16 55.485 ;
     RECT  2.16 55.755 20.844 56.025 ;
     RECT  199.692 55.755 218.16 56.025 ;
     RECT  2.16 56.295 20.844 56.565 ;
     RECT  199.692 56.295 218.16 56.565 ;
     RECT  2.16 56.835 20.844 57.105 ;
     RECT  199.692 56.835 218.16 57.105 ;
     RECT  2.16 57.375 20.844 57.645 ;
     RECT  199.692 57.375 218.16 57.645 ;
     RECT  2.16 57.915 20.844 58.185 ;
     RECT  199.692 57.915 218.16 58.185 ;
     RECT  2.16 58.455 20.844 58.725 ;
     RECT  199.692 58.455 218.16 58.725 ;
     RECT  2.16 58.995 20.844 59.265 ;
     RECT  199.692 58.995 218.16 59.265 ;
     RECT  2.16 59.535 20.844 59.805 ;
     RECT  199.692 59.535 218.16 59.805 ;
     RECT  2.16 60.075 20.844 60.345 ;
     RECT  199.692 60.075 218.16 60.345 ;
     RECT  2.16 60.615 20.844 60.885 ;
     RECT  199.692 60.615 218.16 60.885 ;
     RECT  2.16 61.155 20.844 61.425 ;
     RECT  199.692 61.155 218.16 61.425 ;
     RECT  2.16 61.695 20.844 61.965 ;
     RECT  199.692 61.695 218.16 61.965 ;
     RECT  2.16 62.235 20.844 62.505 ;
     RECT  199.692 62.235 218.16 62.505 ;
     RECT  2.16 62.775 20.844 63.045 ;
     RECT  199.692 62.775 218.16 63.045 ;
     RECT  2.16 63.315 20.844 63.585 ;
     RECT  199.692 63.315 218.16 63.585 ;
     RECT  2.16 63.855 20.844 64.125 ;
     RECT  199.692 63.855 218.16 64.125 ;
     RECT  2.16 64.395 20.844 64.665 ;
     RECT  199.692 64.395 218.16 64.665 ;
     RECT  2.16 64.935 20.844 65.205 ;
     RECT  199.692 64.935 218.16 65.205 ;
     RECT  2.16 65.475 20.844 65.745 ;
     RECT  199.692 65.475 218.16 65.745 ;
     RECT  2.16 66.015 20.844 66.285 ;
     RECT  199.692 66.015 218.16 66.285 ;
     RECT  2.16 66.555 20.844 66.825 ;
     RECT  199.692 66.555 218.16 66.825 ;
     RECT  2.16 67.095 20.844 67.365 ;
     RECT  199.692 67.095 218.16 67.365 ;
     RECT  2.16 67.635 20.844 67.905 ;
     RECT  199.692 67.635 218.16 67.905 ;
     RECT  2.16 68.175 20.844 68.445 ;
     RECT  199.692 68.175 218.16 68.445 ;
     RECT  2.16 68.715 20.844 68.985 ;
     RECT  199.692 68.715 218.16 68.985 ;
     RECT  2.16 69.255 20.844 69.525 ;
     RECT  199.692 69.255 218.16 69.525 ;
     RECT  2.16 69.795 20.844 70.065 ;
     RECT  199.692 69.795 218.16 70.065 ;
     RECT  2.16 70.335 20.844 70.605 ;
     RECT  199.692 70.335 218.16 70.605 ;
     RECT  2.16 70.875 20.844 71.145 ;
     RECT  199.692 70.875 218.16 71.145 ;
     RECT  2.16 71.415 20.844 71.685 ;
     RECT  199.692 71.415 218.16 71.685 ;
     RECT  2.16 71.955 20.844 72.225 ;
     RECT  199.692 71.955 218.16 72.225 ;
     RECT  2.16 72.495 20.844 72.765 ;
     RECT  199.692 72.495 218.16 72.765 ;
     RECT  2.16 73.035 20.844 73.305 ;
     RECT  199.692 73.035 218.16 73.305 ;
     RECT  2.16 73.575 20.844 73.845 ;
     RECT  199.692 73.575 218.16 73.845 ;
     RECT  2.16 74.115 20.844 74.385 ;
     RECT  199.692 74.115 218.16 74.385 ;
     RECT  2.16 74.655 20.844 74.925 ;
     RECT  199.692 74.655 218.16 74.925 ;
     RECT  2.16 75.195 20.844 75.465 ;
     RECT  199.692 75.195 218.16 75.465 ;
     RECT  2.16 75.735 20.844 76.005 ;
     RECT  199.692 75.735 218.16 76.005 ;
     RECT  2.16 76.275 20.844 76.545 ;
     RECT  199.692 76.275 218.16 76.545 ;
     RECT  2.16 76.815 20.844 77.085 ;
     RECT  199.692 76.815 218.16 77.085 ;
     RECT  2.16 77.355 20.844 77.625 ;
     RECT  199.692 77.355 218.16 77.625 ;
     RECT  2.16 77.895 20.844 78.165 ;
     RECT  199.692 77.895 218.16 78.165 ;
     RECT  2.16 78.435 20.844 78.705 ;
     RECT  199.692 78.435 218.16 78.705 ;
     RECT  2.16 78.975 20.844 79.245 ;
     RECT  199.692 78.975 218.16 79.245 ;
     RECT  2.16 79.515 20.844 79.785 ;
     RECT  199.692 79.515 218.16 79.785 ;
     RECT  2.16 80.055 20.844 80.325 ;
     RECT  199.692 80.055 218.16 80.325 ;
     RECT  2.16 80.595 20.844 80.865 ;
     RECT  199.692 80.595 218.16 80.865 ;
     RECT  2.16 81.135 20.844 81.405 ;
     RECT  199.692 81.135 218.16 81.405 ;
     RECT  2.16 81.675 20.844 81.945 ;
     RECT  199.692 81.675 218.16 81.945 ;
     RECT  2.16 82.215 20.844 82.485 ;
     RECT  199.692 82.215 218.16 82.485 ;
     RECT  2.16 82.755 20.844 83.025 ;
     RECT  199.692 82.755 218.16 83.025 ;
     RECT  2.16 83.295 20.844 83.565 ;
     RECT  199.692 83.295 218.16 83.565 ;
     RECT  2.16 83.835 20.844 84.105 ;
     RECT  199.692 83.835 218.16 84.105 ;
     RECT  2.16 84.375 20.844 84.645 ;
     RECT  199.692 84.375 218.16 84.645 ;
     RECT  2.16 84.915 20.844 85.185 ;
     RECT  199.692 84.915 218.16 85.185 ;
     RECT  2.16 85.455 20.844 85.725 ;
     RECT  199.692 85.455 218.16 85.725 ;
     RECT  2.16 85.995 20.844 86.265 ;
     RECT  199.692 85.995 218.16 86.265 ;
     RECT  2.16 86.535 20.844 86.805 ;
     RECT  199.692 86.535 218.16 86.805 ;
     RECT  2.16 87.075 20.844 87.345 ;
     RECT  199.692 87.075 218.16 87.345 ;
     RECT  2.16 87.615 20.844 87.885 ;
     RECT  199.692 87.615 218.16 87.885 ;
     RECT  2.16 88.155 20.844 88.425 ;
     RECT  199.692 88.155 218.16 88.425 ;
     RECT  2.16 88.695 20.844 88.965 ;
     RECT  199.692 88.695 218.16 88.965 ;
     RECT  2.16 89.235 20.844 89.505 ;
     RECT  199.692 89.235 218.16 89.505 ;
     RECT  2.16 89.775 20.844 90.045 ;
     RECT  199.692 89.775 218.16 90.045 ;
     RECT  2.16 90.315 20.844 90.585 ;
     RECT  199.692 90.315 218.16 90.585 ;
     RECT  2.16 90.855 20.844 91.125 ;
     RECT  199.692 90.855 218.16 91.125 ;
     RECT  2.16 91.395 20.844 91.665 ;
     RECT  199.692 91.395 218.16 91.665 ;
     RECT  2.16 91.935 20.844 92.205 ;
     RECT  199.692 91.935 218.16 92.205 ;
     RECT  2.16 92.475 20.844 92.745 ;
     RECT  199.692 92.475 218.16 92.745 ;
     RECT  2.16 93.015 20.844 93.285 ;
     RECT  199.692 93.015 218.16 93.285 ;
     RECT  2.16 93.555 20.844 93.825 ;
     RECT  199.692 93.555 218.16 93.825 ;
     RECT  2.16 94.095 20.844 94.365 ;
     RECT  199.692 94.095 218.16 94.365 ;
     RECT  2.16 94.635 20.844 94.905 ;
     RECT  199.692 94.635 218.16 94.905 ;
     RECT  2.16 95.175 20.844 95.445 ;
     RECT  199.692 95.175 218.16 95.445 ;
     RECT  2.16 95.715 20.844 95.985 ;
     RECT  199.692 95.715 218.16 95.985 ;
     RECT  2.16 96.255 20.844 96.525 ;
     RECT  199.692 96.255 218.16 96.525 ;
     RECT  2.16 96.795 20.844 97.065 ;
     RECT  199.692 96.795 218.16 97.065 ;
     RECT  2.16 97.335 20.844 97.605 ;
     RECT  199.692 97.335 218.16 97.605 ;
     RECT  2.16 97.875 20.844 98.145 ;
     RECT  199.692 97.875 218.16 98.145 ;
     RECT  2.16 98.415 20.844 98.685 ;
     RECT  199.692 98.415 218.16 98.685 ;
     RECT  2.16 98.955 20.844 99.225 ;
     RECT  199.692 98.955 218.16 99.225 ;
     RECT  2.16 99.495 20.844 99.765 ;
     RECT  199.692 99.495 218.16 99.765 ;
     RECT  2.16 100.035 20.844 100.305 ;
     RECT  199.692 100.035 218.16 100.305 ;
     RECT  2.16 100.575 20.844 100.71 ;
     RECT  199.692 100.575 218.16 100.71 ;
     RECT  2.16 100.71 218.16 100.845 ;
     RECT  2.16 101.115 218.16 101.385 ;
     RECT  2.16 101.655 218.16 101.925 ;
     RECT  2.16 102.195 218.16 102.465 ;
     RECT  2.16 102.735 218.16 103.005 ;
     RECT  2.16 103.275 218.16 103.545 ;
     RECT  2.16 103.815 218.16 104.085 ;
     RECT  2.16 104.355 218.16 104.625 ;
     RECT  2.16 104.895 218.16 105.165 ;
     RECT  2.16 105.435 218.16 105.705 ;
     RECT  2.16 105.975 218.16 106.245 ;
     RECT  2.16 106.515 218.16 106.785 ;
     RECT  2.16 107.055 218.16 107.325 ;
     RECT  2.16 107.595 218.16 107.865 ;
     RECT  2.16 108.135 218.16 108.405 ;
     RECT  2.16 108.675 218.16 108.945 ;
     RECT  2.16 109.215 218.16 109.485 ;
     RECT  2.16 109.755 218.16 110.025 ;
     RECT  2.16 110.295 218.16 110.565 ;
     RECT  2.16 110.835 218.16 111.105 ;
     RECT  2.16 111.375 218.16 111.645 ;
     RECT  2.16 111.915 218.16 112.185 ;
     RECT  2.16 112.455 218.16 112.725 ;
     RECT  2.16 112.995 218.16 113.265 ;
     RECT  2.16 113.535 218.16 113.805 ;
     RECT  2.16 114.075 218.16 114.345 ;
     RECT  2.16 114.615 218.16 114.885 ;
     RECT  2.16 115.155 218.16 115.425 ;
     RECT  2.16 115.695 218.16 115.965 ;
     RECT  2.16 116.235 218.16 116.505 ;
     RECT  2.16 116.775 218.16 117.045 ;
     RECT  2.16 117.315 218.16 117.585 ;
     RECT  2.16 117.855 218.16 118.125 ;
     RECT  2.16 118.395 218.16 118.665 ;
     RECT  2.16 118.935 218.16 119.205 ;
     RECT  2.16 119.475 218.16 119.745 ;
     RECT  2.16 120.015 218.16 120.285 ;
     RECT  2.16 120.555 218.16 120.825 ;
     RECT  2.16 121.095 218.16 121.365 ;
     RECT  2.16 121.635 218.16 121.905 ;
     RECT  2.16 122.175 218.16 122.445 ;
     RECT  2.16 122.715 218.16 122.985 ;
     RECT  2.16 123.255 218.16 123.525 ;
     RECT  2.16 123.795 218.16 124.065 ;
     RECT  2.16 124.335 218.16 124.605 ;
     RECT  2.16 124.875 218.16 125.145 ;
     RECT  2.16 125.415 218.16 125.685 ;
     RECT  2.16 125.955 218.16 126.225 ;
     RECT  2.16 126.495 218.16 126.765 ;
     RECT  2.16 127.035 218.16 127.305 ;
    LAYER M1 ;
     RECT  2.16 2.151 218.16 25.929 ;
     RECT  22.896 28.08 197.64 98.55 ;
     RECT  2.16 25.929 20.844 100.701 ;
     RECT  199.692 25.929 218.16 100.701 ;
     RECT  2.16 100.701 218.16 127.449 ;
    LAYER M2 ;
     RECT  0.103 17.622 0.139 25.74 ;
     RECT  0.103 27.072 0.139 28.71 ;
     RECT  0.103 43.272 0.139 43.56 ;
     RECT  0.103 44.892 0.139 50.04 ;
     RECT  0.103 50.832 0.139 53.82 ;
     RECT  0.103 54.882 0.139 58.41 ;
     RECT  0.103 59.814 0.139 69.246 ;
     RECT  0.103 118.332 0.139 119.16 ;
     RECT  0.103 120.222 0.139 122.94 ;
     RECT  0.103 11.142 0.535 14.13 ;
     RECT  0.103 31.122 0.535 36.27 ;
     RECT  0.103 37.332 0.535 38.97 ;
     RECT  0.139 43.272 0.535 50.04 ;
     RECT  0.139 50.832 0.535 69.246 ;
     RECT  0.103 70.002 0.535 74.34 ;
     RECT  0.103 75.51 0.535 75.96 ;
     RECT  0.103 81.144 0.535 83.79 ;
     RECT  0.103 84.582 0.535 94.32 ;
     RECT  0.103 114.282 0.535 114.84 ;
     RECT  0.103 115.902 0.535 115.92 ;
     RECT  0.103 41.994 1.723 42.48 ;
     RECT  0.535 43.272 1.723 69.246 ;
     RECT  0.535 70.002 1.723 74.412 ;
     RECT  0.535 75.168 1.723 75.96 ;
     RECT  0.103 78.642 1.723 80.118 ;
     RECT  0.535 81.144 1.723 94.32 ;
     RECT  0.103 95.112 1.723 97.56 ;
     RECT  0.535 4.23 2.16 4.248 ;
     RECT  0.103 6.552 2.16 9 ;
     RECT  0.535 11.142 2.16 14.4 ;
     RECT  0.139 17.622 2.16 28.71 ;
     RECT  0.103 29.502 2.16 29.898 ;
     RECT  0.535 31.122 2.16 38.97 ;
     RECT  0.103 39.762 2.16 41.238 ;
     RECT  1.723 41.994 2.16 75.96 ;
     RECT  0.103 76.752 2.16 77.31 ;
     RECT  1.723 78.642 2.16 80.28 ;
     RECT  1.723 81.144 2.16 97.56 ;
     RECT  0.103 98.352 2.16 101.34 ;
     RECT  0.103 105.75 2.16 109.71 ;
     RECT  0.103 111.852 2.16 113.49 ;
     RECT  0.535 114.282 2.16 115.92 ;
     RECT  0.139 118.332 2.16 122.94 ;
     RECT  1.723 125.352 2.16 125.37 ;
     RECT  2.16 2.151 20.844 127.449 ;
     RECT  20.844 79.686 20.867 81.864 ;
     RECT  20.844 84.312 20.903 86.364 ;
     RECT  20.844 89.856 20.939 91.692 ;
     RECT  20.867 79.686 20.975 79.704 ;
     RECT  20.844 31.086 21.011 33.534 ;
     RECT  20.903 85.626 21.011 86.364 ;
     RECT  20.844 75.096 21.047 75.114 ;
     RECT  21.011 31.086 21.083 32.724 ;
     RECT  20.844 34.47 21.083 62.694 ;
     RECT  21.083 49.446 21.119 62.694 ;
     RECT  21.119 55.836 21.155 62.694 ;
     RECT  21.083 34.47 21.263 48.564 ;
     RECT  21.083 31.086 21.299 31.284 ;
     RECT  20.844 92.556 21.299 96.714 ;
     RECT  20.844 71.586 21.371 71.604 ;
     RECT  20.844 76.986 21.371 77.004 ;
     RECT  20.867 80.766 21.407 81.864 ;
     RECT  21.407 81.306 21.443 81.864 ;
     RECT  20.844 82.926 21.479 82.944 ;
     RECT  21.299 31.158 21.515 31.284 ;
     RECT  21.263 34.506 21.515 48.564 ;
     RECT  21.443 81.306 21.515 81.324 ;
     RECT  21.515 34.506 21.551 36.954 ;
     RECT  20.903 84.312 21.551 84.636 ;
     RECT  20.844 88.128 21.587 88.65 ;
     RECT  21.011 85.77 21.623 86.364 ;
     RECT  20.844 29.61 21.659 30.204 ;
     RECT  21.083 32.166 21.659 32.598 ;
     RECT  21.011 33.516 21.659 33.534 ;
     RECT  21.515 37.71 21.659 48.564 ;
     RECT  21.119 49.446 21.659 54.234 ;
     RECT  20.844 63.522 21.659 68.4 ;
     RECT  20.939 90.936 21.659 91.692 ;
     RECT  20.844 2.151 21.695 28.584 ;
     RECT  21.551 36.936 21.695 36.954 ;
     RECT  21.659 63.594 21.695 68.4 ;
     RECT  21.299 92.556 21.839 96.624 ;
     RECT  21.839 92.556 21.911 95.094 ;
     RECT  21.551 84.312 21.947 84.33 ;
     RECT  21.587 88.2 21.983 88.65 ;
     RECT  21.623 85.77 22.019 85.788 ;
     RECT  21.983 88.632 22.055 88.65 ;
     RECT  21.659 91.368 22.091 91.692 ;
     RECT  21.551 34.506 22.127 35.604 ;
     RECT  21.659 30.006 22.459 30.024 ;
     RECT  22.135 30.852 22.459 30.87 ;
     RECT  22.279 34.281 22.459 34.299 ;
     RECT  21.659 32.166 22.531 32.292 ;
     RECT  22.459 30.006 22.675 30.87 ;
     RECT  21.119 55.026 22.711 55.044 ;
     RECT  22.531 32.076 22.783 32.292 ;
     RECT  21.695 2.151 22.896 28.44 ;
     RECT  22.675 29.916 22.896 30.87 ;
     RECT  22.783 31.932 22.896 32.292 ;
     RECT  22.459 34.2 22.896 34.299 ;
     RECT  22.127 35.208 22.896 35.604 ;
     RECT  21.659 37.71 22.896 48.492 ;
     RECT  21.659 49.446 22.896 53.964 ;
     RECT  22.711 55.026 22.896 55.089 ;
     RECT  21.155 55.836 22.896 56.124 ;
     RECT  21.155 56.916 22.896 62.694 ;
     RECT  21.695 63.594 22.896 67.392 ;
     RECT  21.695 68.184 22.896 68.364 ;
     RECT  20.939 89.856 22.896 89.874 ;
     RECT  22.091 91.674 22.896 91.692 ;
     RECT  21.911 92.556 22.896 94.392 ;
     RECT  21.839 95.886 22.896 96.624 ;
     RECT  20.844 97.776 22.896 127.449 ;
     RECT  22.896 2.151 69.395 127.449 ;
     RECT  69.395 2.151 70.267 26.964 ;
     RECT  70.267 2.151 70.511 27.09 ;
     RECT  70.511 2.151 70.583 26.118 ;
     RECT  70.583 2.151 76.775 25.974 ;
     RECT  70.511 27.072 77.215 27.09 ;
     RECT  69.395 28.08 77.215 127.449 ;
     RECT  76.775 2.151 108.211 25.929 ;
     RECT  77.215 27.072 108.211 127.449 ;
     RECT  108.211 2.151 197.64 127.449 ;
     RECT  197.64 31.932 198.383 32.184 ;
     RECT  197.64 78.912 198.383 79.236 ;
     RECT  197.64 92.214 198.383 92.304 ;
     RECT  197.64 35.586 198.391 35.604 ;
     RECT  197.64 39.366 198.391 41.364 ;
     RECT  198.391 34.974 198.679 35.604 ;
     RECT  197.64 70.506 198.679 70.524 ;
     RECT  198.679 70.416 198.715 70.524 ;
     RECT  198.391 39.33 198.751 41.364 ;
     RECT  198.715 70.038 198.751 70.524 ;
     RECT  197.64 2.151 198.823 29.664 ;
     RECT  197.64 30.546 198.823 31.014 ;
     RECT  198.751 69.336 198.823 70.524 ;
     RECT  198.679 34.974 198.859 36.144 ;
     RECT  198.859 34.434 198.895 36.612 ;
     RECT  198.823 69.336 198.895 71.136 ;
     RECT  197.64 37.674 198.931 37.692 ;
     RECT  198.751 39.258 199.147 41.364 ;
     RECT  197.64 42.192 199.147 68.544 ;
     RECT  198.787 75.51 199.219 75.528 ;
     RECT  199.183 73.512 199.255 73.53 ;
     RECT  199.219 74.898 199.327 75.528 ;
     RECT  199.327 74.898 199.363 76.068 ;
     RECT  199.147 81.684 199.399 81.702 ;
     RECT  199.075 88.164 199.435 88.182 ;
     RECT  199.111 84.15 199.471 84.168 ;
     RECT  198.383 32.004 199.507 32.184 ;
     RECT  198.895 34.434 199.507 36.684 ;
     RECT  198.931 37.674 199.507 38.304 ;
     RECT  198.571 90.522 199.507 90.54 ;
     RECT  199.507 32.004 199.543 32.832 ;
     RECT  199.507 33.966 199.543 36.684 ;
     RECT  197.64 94.266 199.543 95.544 ;
     RECT  199.435 96.696 199.543 96.714 ;
     RECT  199.507 37.476 199.579 38.304 ;
     RECT  199.147 39.258 199.579 68.544 ;
     RECT  198.859 85.806 199.579 85.824 ;
     RECT  199.543 94.266 199.579 96.714 ;
     RECT  197.64 97.506 199.579 127.449 ;
     RECT  199.471 84.15 199.615 84.834 ;
     RECT  197.64 80.334 199.651 80.352 ;
     RECT  199.399 81.45 199.651 81.702 ;
     RECT  198.823 2.151 199.692 31.014 ;
     RECT  199.543 32.004 199.692 36.684 ;
     RECT  199.579 37.476 199.692 68.544 ;
     RECT  198.895 69.336 199.692 71.208 ;
     RECT  199.255 73.476 199.692 73.53 ;
     RECT  199.363 74.826 199.692 76.068 ;
     RECT  199.507 77.526 199.692 77.544 ;
     RECT  198.383 78.912 199.692 78.93 ;
     RECT  199.651 80.334 199.692 81.702 ;
     RECT  199.615 83.736 199.692 84.834 ;
     RECT  199.579 85.77 199.692 85.824 ;
     RECT  199.435 88.164 199.692 88.254 ;
     RECT  199.507 90.396 199.692 90.54 ;
     RECT  198.383 92.286 199.692 92.304 ;
     RECT  199.579 94.266 199.692 127.449 ;
     RECT  199.692 2.151 218.16 127.449 ;
     RECT  218.16 100.206 218.291 100.224 ;
     RECT  218.16 9.756 218.327 9.774 ;
     RECT  218.16 14.922 218.327 14.94 ;
     RECT  218.16 30.546 218.867 30.564 ;
     RECT  218.16 35.676 218.867 35.694 ;
     RECT  218.16 40.806 218.867 40.824 ;
     RECT  218.16 73.206 218.867 73.224 ;
     RECT  218.16 78.336 218.867 78.354 ;
     RECT  218.16 84.816 218.867 84.834 ;
     RECT  218.16 88.596 218.867 88.614 ;
     RECT  218.16 109.386 218.867 109.404 ;
     RECT  218.16 16.146 218.903 16.164 ;
     RECT  218.16 21.402 218.903 21.42 ;
     RECT  218.16 33.012 218.903 33.03 ;
     RECT  218.16 39.456 218.903 39.474 ;
     RECT  218.16 44.586 218.903 44.604 ;
     RECT  218.16 45.846 218.903 45.864 ;
     RECT  218.16 49.716 218.903 49.734 ;
     RECT  218.16 50.94 218.903 50.958 ;
     RECT  218.16 56.196 218.903 56.214 ;
     RECT  218.16 60.084 218.903 60.102 ;
     RECT  218.16 61.2 218.903 61.218 ;
     RECT  218.16 76.986 218.903 77.004 ;
     RECT  218.16 82.116 218.903 82.134 ;
     RECT  218.16 92.448 218.903 92.466 ;
     RECT  218.16 97.578 218.903 97.596 ;
     RECT  218.16 104.058 218.903 104.076 ;
     RECT  218.16 115.056 218.903 115.074 ;
     RECT  218.16 118.368 218.903 118.386 ;
     RECT  218.16 4.662 219.443 4.68 ;
     RECT  218.16 5.976 219.443 5.994 ;
     RECT  218.16 7.326 219.443 7.344 ;
     RECT  218.16 8.676 219.443 8.694 ;
     RECT  218.16 11.376 219.443 11.394 ;
     RECT  218.16 12.456 219.443 12.474 ;
     RECT  218.16 13.806 219.443 13.824 ;
     RECT  218.16 17.586 219.443 17.604 ;
     RECT  218.16 18.936 219.443 18.954 ;
     RECT  218.16 20.286 219.443 20.304 ;
     RECT  218.16 22.716 219.443 22.734 ;
     RECT  218.16 24.066 219.443 24.084 ;
     RECT  218.16 25.416 219.443 25.434 ;
     RECT  218.16 26.766 219.443 26.784 ;
     RECT  218.16 27.846 219.443 27.864 ;
     RECT  218.16 29.196 219.443 29.214 ;
     RECT  218.16 31.896 219.443 31.914 ;
     RECT  218.16 34.326 219.443 34.344 ;
     RECT  218.16 37.026 219.443 37.044 ;
     RECT  218.16 38.178 219.443 38.196 ;
     RECT  218.16 42.426 219.443 42.444 ;
     RECT  218.16 43.308 219.443 43.326 ;
     RECT  218.16 47.322 219.443 47.34 ;
     RECT  218.16 48.636 219.443 48.654 ;
     RECT  218.16 52.326 219.443 52.344 ;
     RECT  218.16 54.918 219.443 54.936 ;
     RECT  218.16 57.582 219.443 57.6 ;
     RECT  218.16 62.676 219.443 62.694 ;
     RECT  218.16 64.062 219.443 64.08 ;
     RECT  218.16 65.376 219.443 65.394 ;
     RECT  218.16 68.616 219.443 68.634 ;
     RECT  218.16 71.856 219.443 71.874 ;
     RECT  218.16 74.826 219.443 74.844 ;
     RECT  218.16 75.708 219.443 75.726 ;
     RECT  218.16 79.686 219.443 79.704 ;
     RECT  218.16 80.838 219.443 80.856 ;
     RECT  218.16 83.466 219.443 83.484 ;
     RECT  218.16 86.166 219.443 86.184 ;
     RECT  218.16 87.282 219.443 87.3 ;
     RECT  218.16 89.946 219.443 89.964 ;
     RECT  218.16 91.296 219.443 91.314 ;
     RECT  218.16 93.762 219.443 93.78 ;
     RECT  218.16 95.076 219.443 95.094 ;
     RECT  218.16 98.892 219.443 98.91 ;
     RECT  218.16 101.556 219.443 101.574 ;
     RECT  218.16 102.906 219.443 102.924 ;
     RECT  218.16 105.372 219.443 105.39 ;
     RECT  218.16 106.956 219.443 106.974 ;
     RECT  218.16 108.036 219.443 108.054 ;
     RECT  218.16 110.502 219.443 110.52 ;
     RECT  218.16 121.806 219.443 121.824 ;
     RECT  218.16 53.262 219.479 53.28 ;
     RECT  218.16 58.662 219.479 58.68 ;
     RECT  218.16 96.156 219.479 96.174 ;
     RECT  218.16 111.546 219.479 111.564 ;
     RECT  218.16 124.506 219.479 124.524 ;
    LAYER M3 ;
     RECT  2.415 2.143 2.505 2.413 ;
     RECT  7.815 2.143 7.905 2.413 ;
     RECT  13.215 2.143 13.305 2.413 ;
     RECT  18.615 2.143 18.705 2.413 ;
     RECT  24.015 2.143 24.105 2.413 ;
     RECT  29.415 2.143 29.505 2.413 ;
     RECT  34.815 2.143 34.905 2.413 ;
     RECT  40.215 2.143 40.305 2.413 ;
     RECT  45.615 2.143 45.705 2.413 ;
     RECT  51.015 2.143 51.105 2.413 ;
     RECT  56.415 2.143 56.505 2.413 ;
     RECT  61.815 2.143 61.905 2.413 ;
     RECT  67.215 2.143 67.305 2.413 ;
     RECT  72.615 2.143 72.705 2.413 ;
     RECT  78.015 2.143 78.105 2.413 ;
     RECT  83.415 2.143 83.505 2.413 ;
     RECT  88.815 2.143 88.905 2.413 ;
     RECT  94.215 2.143 94.305 2.413 ;
     RECT  99.615 2.143 99.705 2.413 ;
     RECT  105.015 2.143 105.105 2.413 ;
     RECT  110.415 2.143 110.505 2.413 ;
     RECT  115.815 2.143 115.905 2.413 ;
     RECT  121.215 2.143 121.305 2.413 ;
     RECT  126.615 2.143 126.705 2.413 ;
     RECT  132.015 2.143 132.105 2.413 ;
     RECT  137.415 2.143 137.505 2.413 ;
     RECT  142.815 2.143 142.905 2.413 ;
     RECT  148.215 2.143 148.305 2.413 ;
     RECT  153.615 2.143 153.705 2.413 ;
     RECT  159.015 2.143 159.105 2.413 ;
     RECT  164.415 2.143 164.505 2.413 ;
     RECT  169.815 2.143 169.905 2.413 ;
     RECT  175.215 2.143 175.305 2.413 ;
     RECT  180.615 2.143 180.705 2.413 ;
     RECT  186.015 2.143 186.105 2.413 ;
     RECT  191.415 2.143 191.505 2.413 ;
     RECT  196.815 2.143 196.905 2.413 ;
     RECT  202.215 2.143 202.305 2.413 ;
     RECT  207.615 2.143 207.705 2.413 ;
     RECT  213.015 2.143 213.105 2.413 ;
     RECT  0.54 4.171 0.558 4.253 ;
     RECT  2.415 2.413 2.697 4.261 ;
     RECT  2.415 4.261 2.862 4.649 ;
     RECT  5.112 4.531 5.13 4.685 ;
     RECT  219.42 4.648 219.438 4.685 ;
     RECT  4.392 4.729 4.59 4.801 ;
     RECT  5.364 4.693 5.382 4.801 ;
     RECT  3.996 4.801 4.59 4.919 ;
     RECT  3.996 4.919 4.41 4.955 ;
     RECT  4.392 4.955 4.41 5.117 ;
     RECT  5.364 4.801 5.634 5.459 ;
     RECT  217.008 5.845 217.026 5.881 ;
     RECT  219.42 5.899 219.438 5.999 ;
     RECT  217.008 5.881 217.134 6.115 ;
     RECT  215.964 6.115 215.982 6.151 ;
     RECT  217.008 6.115 217.386 6.151 ;
     RECT  215.928 6.151 215.982 6.269 ;
     RECT  216.936 6.151 217.386 6.269 ;
     RECT  216.936 6.269 217.314 6.305 ;
     RECT  4.5 6.523 4.518 6.691 ;
     RECT  5.616 5.459 5.634 6.691 ;
     RECT  4.068 6.691 4.698 6.809 ;
     RECT  4.068 6.809 4.59 6.817 ;
     RECT  217.08 6.305 217.314 6.845 ;
     RECT  215.928 6.269 215.946 7.123 ;
     RECT  215.892 7.123 215.946 7.195 ;
     RECT  3.996 6.817 4.59 7.231 ;
     RECT  3.888 7.231 4.59 7.259 ;
     RECT  215.892 7.195 215.982 7.321 ;
     RECT  5.472 6.691 5.634 7.339 ;
     RECT  219.42 7.195 219.438 7.349 ;
     RECT  2.415 4.649 2.697 7.357 ;
     RECT  217.8 7.321 217.818 7.421 ;
     RECT  215.892 7.321 216.018 7.465 ;
     RECT  3.888 7.259 4.554 7.501 ;
     RECT  214.704 7.483 214.722 7.501 ;
     RECT  215.892 7.465 216.27 7.501 ;
     RECT  1.728 7.357 2.697 7.517 ;
     RECT  3.456 7.501 4.554 7.655 ;
     RECT  5.472 7.339 6.03 7.663 ;
     RECT  6.804 7.501 6.822 7.663 ;
     RECT  214.704 7.501 214.902 7.735 ;
     RECT  215.712 7.501 216.27 7.735 ;
     RECT  5.472 7.663 6.822 7.889 ;
     RECT  214.704 7.735 216.27 7.997 ;
     RECT  4.068 7.655 4.554 8.041 ;
     RECT  214.884 7.997 216.27 8.041 ;
     RECT  5.472 7.889 6.246 8.159 ;
     RECT  214.884 8.041 216.63 8.159 ;
     RECT  214.92 8.159 216.63 8.195 ;
     RECT  213.015 2.413 213.297 8.203 ;
     RECT  4.068 8.041 4.626 8.311 ;
     RECT  5.472 8.159 6.21 8.311 ;
     RECT  4.068 8.311 6.21 8.429 ;
     RECT  6.984 7.933 7.002 8.429 ;
     RECT  214.92 8.195 215.982 8.429 ;
     RECT  210.348 8.311 210.366 8.501 ;
     RECT  214.92 8.429 215.838 8.501 ;
     RECT  213.015 8.203 213.39 8.509 ;
     RECT  214.92 8.501 215.766 8.537 ;
     RECT  5.544 8.429 6.21 8.699 ;
     RECT  219.42 8.491 219.438 8.699 ;
     RECT  4.068 8.429 4.554 8.735 ;
     RECT  217.188 8.509 217.206 8.735 ;
     RECT  4.068 8.735 4.086 8.815 ;
     RECT  3.924 8.815 4.086 8.861 ;
     RECT  5.544 8.699 5.706 8.879 ;
     RECT  214.92 8.537 215.478 8.941 ;
     RECT  3.96 8.861 4.086 8.969 ;
     RECT  214.524 8.941 215.478 8.969 ;
     RECT  0.108 6.475 0.126 9.005 ;
     RECT  215.316 8.969 215.334 9.005 ;
     RECT  212.652 8.509 213.39 9.019 ;
     RECT  3.96 8.969 3.978 9.041 ;
     RECT  214.524 8.969 214.542 9.077 ;
     RECT  121.215 2.413 121.497 9.247 ;
     RECT  212.292 9.019 213.39 9.481 ;
     RECT  218.304 9.751 218.322 9.821 ;
     RECT  212.076 9.481 213.75 9.895 ;
     RECT  212.076 9.895 214.218 10.123 ;
     RECT  210.348 10.027 210.366 10.157 ;
     RECT  212.076 10.123 214.326 10.229 ;
     RECT  215.82 10.201 215.838 10.253 ;
     RECT  212.076 10.229 214.218 10.267 ;
     RECT  5.544 8.879 5.634 10.291 ;
     RECT  5.22 10.291 5.634 10.349 ;
     RECT  211.788 10.267 214.218 10.363 ;
     RECT  211.608 10.363 214.218 10.589 ;
     RECT  211.608 10.589 214.074 10.625 ;
     RECT  5.508 10.349 5.634 10.637 ;
     RECT  212.148 10.625 213.75 10.733 ;
     RECT  212.616 10.733 213.75 10.895 ;
     RECT  123.516 8.473 123.534 11.101 ;
     RECT  212.652 10.895 213.75 11.129 ;
     RECT  215.964 11.222 215.982 11.281 ;
     RECT  217.26 11.245 217.71 11.281 ;
     RECT  3.816 11.281 3.834 11.323 ;
     RECT  215.676 11.281 215.982 11.365 ;
     RECT  215.568 11.365 215.982 11.371 ;
     RECT  215.496 11.371 215.982 11.399 ;
     RECT  219.42 11.083 219.438 11.399 ;
     RECT  216.936 11.281 217.818 11.435 ;
     RECT  3.672 11.323 3.834 11.551 ;
     RECT  215.496 11.399 215.766 11.551 ;
     RECT  216.936 11.435 217.494 11.551 ;
     RECT  215.388 11.551 215.766 11.669 ;
     RECT  216.504 11.551 217.494 11.669 ;
     RECT  213.015 11.129 213.75 11.677 ;
     RECT  4.752 11.371 4.77 11.749 ;
     RECT  213.015 11.677 214.362 11.749 ;
     RECT  5.544 10.637 5.634 11.785 ;
     RECT  6.372 10.603 6.39 11.785 ;
     RECT  216.504 11.669 217.35 11.813 ;
     RECT  2.415 7.517 2.697 11.821 ;
     RECT  3.672 11.551 3.942 11.821 ;
     RECT  5.544 11.785 6.426 11.821 ;
     RECT  7.815 2.413 8.097 11.821 ;
     RECT  7.308 11.821 8.097 11.885 ;
     RECT  2.415 11.821 3.942 11.899 ;
     RECT  4.752 11.749 4.806 11.899 ;
     RECT  5.544 11.821 6.534 11.911 ;
     RECT  216.576 11.813 217.35 11.939 ;
     RECT  7.815 11.885 8.097 11.941 ;
     RECT  2.415 11.899 4.806 11.947 ;
     RECT  1.728 11.947 4.806 11.975 ;
     RECT  216.576 11.939 217.242 11.975 ;
     RECT  5.544 11.911 6.822 11.981 ;
     RECT  7.815 11.941 8.154 11.981 ;
     RECT  3.6 11.975 4.806 12.091 ;
     RECT  5.544 11.981 5.922 12.091 ;
     RECT  1.728 11.975 2.697 12.125 ;
     RECT  3.6 12.091 5.922 12.209 ;
     RECT  6.696 11.981 6.822 12.209 ;
     RECT  3.6 12.209 4.014 12.245 ;
     RECT  210.348 12.181 210.366 12.281 ;
     RECT  213.015 11.749 214.938 12.353 ;
     RECT  213.015 12.353 214.866 12.479 ;
     RECT  219.42 12.379 219.438 12.479 ;
     RECT  213.015 12.479 214.758 12.551 ;
     RECT  213.015 12.551 214.686 12.557 ;
     RECT  9.072 11.911 9.09 12.559 ;
     RECT  9.072 12.559 9.486 12.587 ;
     RECT  216.576 11.975 216.954 12.631 ;
     RECT  4.752 12.209 5.922 12.749 ;
     RECT  3.996 12.245 4.014 12.785 ;
     RECT  215.82 12.631 216.954 12.785 ;
     RECT  215.928 12.785 216.954 13.019 ;
     RECT  215.928 13.019 215.946 13.055 ;
     RECT  216.72 13.019 216.738 13.055 ;
     RECT  4.752 12.749 5.706 13.063 ;
     RECT  6.696 12.209 6.714 13.063 ;
     RECT  7.815 11.981 8.097 13.099 ;
     RECT  121.215 9.247 121.554 13.261 ;
     RECT  122.76 12.253 122.778 13.261 ;
     RECT  9.468 12.587 9.486 13.567 ;
     RECT  4.536 13.063 5.706 13.595 ;
     RECT  8.82 13.567 9.486 13.613 ;
     RECT  2.415 12.125 2.697 13.639 ;
     RECT  2.415 13.639 3.222 13.829 ;
     RECT  213.015 12.557 214.398 13.829 ;
     RECT  219.42 13.675 219.438 13.829 ;
     RECT  217.8 13.801 217.818 13.901 ;
     RECT  215.46 13.801 215.478 13.945 ;
     RECT  4.536 13.595 5.634 13.981 ;
     RECT  215.46 13.945 216.054 13.981 ;
     RECT  4.14 13.981 5.634 14.071 ;
     RECT  6.696 13.063 6.894 14.071 ;
     RECT  7.704 13.099 8.097 14.071 ;
     RECT  215.316 13.981 216.054 14.099 ;
     RECT  0.108 11.128 0.126 14.144 ;
     RECT  215.316 14.099 215.802 14.369 ;
     RECT  215.316 14.369 215.622 14.405 ;
     RECT  0.54 14.377 0.558 14.429 ;
     RECT  6.696 14.071 8.097 14.485 ;
     RECT  213.015 13.829 213.93 14.485 ;
     RECT  3.996 14.071 5.634 14.521 ;
     RECT  6.516 14.485 8.097 14.521 ;
     RECT  215.496 14.405 215.622 14.639 ;
     RECT  91.188 14.611 91.206 14.669 ;
     RECT  3.744 14.521 8.097 14.675 ;
     RECT  59.904 14.635 59.922 14.675 ;
     RECT  92.304 14.635 92.322 14.675 ;
     RECT  215.496 14.639 215.514 14.675 ;
     RECT  2.415 13.829 2.697 14.731 ;
     RECT  2.304 14.731 2.697 14.945 ;
     RECT  218.304 14.917 218.322 14.957 ;
     RECT  212.976 14.485 213.93 15.025 ;
     RECT  211.392 10.705 211.41 15.061 ;
     RECT  67.215 2.413 67.497 15.151 ;
     RECT  78.015 2.413 78.297 15.151 ;
     RECT  99.615 2.413 99.897 15.151 ;
     RECT  110.415 2.413 110.697 15.151 ;
     RECT  121.215 13.261 122.778 15.151 ;
     RECT  132.015 2.413 132.297 15.151 ;
     RECT  142.815 2.413 143.097 15.151 ;
     RECT  153.615 2.413 153.897 15.151 ;
     RECT  164.415 2.413 164.697 15.151 ;
     RECT  175.215 2.413 175.497 15.151 ;
     RECT  186.015 2.413 186.297 15.151 ;
     RECT  196.815 2.413 197.097 15.151 ;
     RECT  207.615 2.413 207.897 15.151 ;
     RECT  211.392 15.061 212.094 15.151 ;
     RECT  212.832 15.025 214.326 15.151 ;
     RECT  61.815 2.413 62.097 15.163 ;
     RECT  94.215 2.413 94.497 15.163 ;
     RECT  4.356 14.675 8.097 15.179 ;
     RECT  67.104 15.151 67.497 15.197 ;
     RECT  77.904 15.151 78.297 15.197 ;
     RECT  99.504 15.151 99.897 15.197 ;
     RECT  110.304 15.151 110.697 15.197 ;
     RECT  121.104 15.151 122.778 15.197 ;
     RECT  131.904 15.151 132.297 15.197 ;
     RECT  142.704 15.151 143.097 15.197 ;
     RECT  153.504 15.151 153.897 15.197 ;
     RECT  164.304 15.151 164.697 15.197 ;
     RECT  175.104 15.151 175.497 15.197 ;
     RECT  185.904 15.151 186.297 15.197 ;
     RECT  196.704 15.151 197.097 15.197 ;
     RECT  207.504 15.151 207.897 15.197 ;
     RECT  3.564 15.061 3.582 15.215 ;
     RECT  61.815 15.163 62.694 15.293 ;
     RECT  86.652 15.163 86.67 15.293 ;
     RECT  94.215 15.163 94.626 15.293 ;
     RECT  211.392 15.151 214.326 15.295 ;
     RECT  90.036 15.259 90.054 15.296 ;
     RECT  91.152 15.259 91.17 15.359 ;
     RECT  211.392 15.295 214.866 15.449 ;
     RECT  211.392 15.449 211.95 15.485 ;
     RECT  212.688 15.449 214.866 15.755 ;
     RECT  60.696 15.961 60.714 16.013 ;
     RECT  218.88 16.141 218.898 16.253 ;
     RECT  217.944 16.105 217.962 16.259 ;
     RECT  216.252 16.375 216.27 16.411 ;
     RECT  217.8 16.375 217.818 16.411 ;
     RECT  214.344 15.755 214.866 16.507 ;
     RECT  217.188 16.411 217.818 16.529 ;
     RECT  214.2 16.507 214.866 16.537 ;
     RECT  215.676 16.411 216.27 16.537 ;
     RECT  214.2 16.537 216.27 16.541 ;
     RECT  217.188 16.529 217.602 16.565 ;
     RECT  214.2 16.541 215.55 16.637 ;
     RECT  94.215 15.293 94.497 16.795 ;
     RECT  217.224 16.565 217.53 16.799 ;
     RECT  11.016 5.431 11.034 16.807 ;
     RECT  92.916 16.771 92.934 16.829 ;
     RECT  94.032 16.795 94.497 16.835 ;
     RECT  214.416 16.637 215.55 16.979 ;
     RECT  2.415 14.945 2.697 17.077 ;
     RECT  4.752 15.179 8.097 17.077 ;
     RECT  217.224 16.799 217.386 17.105 ;
     RECT  2.268 17.077 2.697 17.117 ;
     RECT  67.215 15.197 67.497 17.311 ;
     RECT  78.015 15.197 78.297 17.311 ;
     RECT  88.815 2.413 89.097 17.311 ;
     RECT  99.615 15.197 99.897 17.311 ;
     RECT  110.415 15.197 110.697 17.311 ;
     RECT  121.215 15.197 122.778 17.311 ;
     RECT  132.015 15.197 132.297 17.311 ;
     RECT  142.815 15.197 143.097 17.311 ;
     RECT  153.615 15.197 153.897 17.311 ;
     RECT  164.415 15.197 164.697 17.311 ;
     RECT  175.215 15.197 175.497 17.311 ;
     RECT  186.015 15.197 186.297 17.311 ;
     RECT  196.815 15.197 197.097 17.311 ;
     RECT  207.615 15.197 207.897 17.311 ;
     RECT  94.215 16.835 94.497 17.323 ;
     RECT  67.104 17.311 67.497 17.357 ;
     RECT  77.904 17.311 78.297 17.357 ;
     RECT  88.704 17.311 89.097 17.357 ;
     RECT  92.304 17.311 92.322 17.357 ;
     RECT  99.504 17.311 99.897 17.357 ;
     RECT  110.304 17.311 110.697 17.357 ;
     RECT  121.104 17.311 122.778 17.357 ;
     RECT  131.904 17.311 132.297 17.357 ;
     RECT  142.704 17.311 143.097 17.357 ;
     RECT  153.504 17.311 153.897 17.357 ;
     RECT  164.304 17.311 164.697 17.357 ;
     RECT  175.104 17.311 175.497 17.357 ;
     RECT  185.904 17.311 186.297 17.357 ;
     RECT  196.704 17.311 197.097 17.357 ;
     RECT  207.504 17.311 207.897 17.357 ;
     RECT  213.015 15.755 213.297 17.419 ;
     RECT  214.416 16.979 215.514 17.419 ;
     RECT  94.215 17.323 94.662 17.453 ;
     RECT  210.348 17.323 210.366 17.453 ;
     RECT  93.42 17.419 93.438 17.519 ;
     RECT  213.015 17.419 215.514 17.609 ;
     RECT  219.42 17.515 219.438 17.609 ;
     RECT  217.8 17.581 217.818 17.681 ;
     RECT  4.5 17.077 8.097 17.761 ;
     RECT  214.416 17.609 215.514 17.761 ;
     RECT  216.612 17.581 216.774 17.761 ;
     RECT  2.415 17.117 2.697 18.139 ;
     RECT  3.78 17.761 8.097 18.139 ;
     RECT  214.416 17.761 216.774 18.149 ;
     RECT  214.416 18.149 216.63 18.185 ;
     RECT  214.416 18.185 215.622 18.221 ;
     RECT  9.468 13.613 9.486 18.301 ;
     RECT  2.415 18.139 8.097 18.455 ;
     RECT  121.215 17.357 122.778 18.499 ;
     RECT  211.392 15.485 211.41 18.527 ;
     RECT  9.072 18.301 9.486 18.535 ;
     RECT  13.215 2.413 13.497 18.697 ;
     RECT  14.328 18.661 14.346 18.697 ;
     RECT  3.42 18.455 8.097 18.725 ;
     RECT  12.96 18.697 14.346 18.769 ;
     RECT  12.6 18.769 14.346 18.805 ;
     RECT  121.176 18.499 122.778 18.805 ;
     RECT  121.068 18.805 122.778 18.833 ;
     RECT  214.416 18.221 214.434 18.907 ;
     RECT  4.212 18.725 8.097 18.931 ;
     RECT  21.312 18.841 21.33 18.931 ;
     RECT  22.14 18.841 22.554 18.931 ;
     RECT  122.508 18.833 122.778 18.959 ;
     RECT  219.42 18.811 219.438 18.959 ;
     RECT  3.42 18.725 3.438 18.995 ;
     RECT  21.312 18.931 22.554 19.003 ;
     RECT  217.8 18.931 217.818 19.031 ;
     RECT  4.212 18.931 8.262 19.039 ;
     RECT  9.036 18.535 9.486 19.039 ;
     RECT  11.016 16.807 11.07 19.039 ;
     RECT  21.312 19.003 22.986 19.039 ;
     RECT  4.212 19.039 9.486 19.111 ;
     RECT  10.584 19.039 11.07 19.111 ;
     RECT  21.312 19.039 23.022 19.111 ;
     RECT  213.015 17.609 213.297 19.111 ;
     RECT  215.28 18.221 215.622 19.111 ;
     RECT  18.615 2.413 18.897 19.201 ;
     RECT  19.944 18.967 19.962 19.201 ;
     RECT  215.208 19.111 215.622 19.229 ;
     RECT  15.48 19.039 15.498 19.237 ;
     RECT  16.524 19.075 16.542 19.237 ;
     RECT  29.415 2.413 29.697 19.237 ;
     RECT  4.212 19.111 11.07 19.301 ;
     RECT  15.444 19.237 16.974 19.309 ;
     RECT  9.036 19.301 11.07 19.345 ;
     RECT  12.24 18.805 14.346 19.345 ;
     RECT  15.444 19.309 17.262 19.345 ;
     RECT  18.615 19.201 19.962 19.381 ;
     RECT  24.015 2.413 24.297 19.381 ;
     RECT  28.26 19.237 28.278 19.381 ;
     RECT  29.016 19.237 29.697 19.381 ;
     RECT  30.636 19.345 30.654 19.381 ;
     RECT  60.48 16.105 60.498 19.381 ;
     RECT  213.015 19.111 213.354 19.381 ;
     RECT  214.236 18.907 214.434 19.381 ;
     RECT  59.904 19.381 60.498 19.387 ;
     RECT  122.508 18.959 122.526 19.409 ;
     RECT  15.3 19.345 17.622 19.435 ;
     RECT  18.396 19.381 19.962 19.435 ;
     RECT  9.036 19.345 11.106 19.471 ;
     RECT  12.024 19.345 14.346 19.471 ;
     RECT  20.7 19.111 23.022 19.471 ;
     RECT  23.904 19.381 24.297 19.471 ;
     RECT  26.712 19.381 26.73 19.471 ;
     RECT  28.26 19.381 30.654 19.471 ;
     RECT  58.788 14.755 58.806 19.471 ;
     RECT  59.904 19.387 60.786 19.471 ;
     RECT  207.615 17.357 207.897 19.471 ;
     RECT  123.516 11.101 123.966 19.499 ;
     RECT  25.38 19.243 25.398 19.507 ;
     RECT  26.712 19.471 26.802 19.507 ;
     RECT  28.08 19.471 30.654 19.507 ;
     RECT  61.815 15.293 62.097 19.507 ;
     RECT  207.504 19.471 207.897 19.517 ;
     RECT  9.036 19.471 14.346 19.531 ;
     RECT  15.3 19.435 19.962 19.531 ;
     RECT  213.015 19.381 214.434 19.535 ;
     RECT  58.572 19.471 58.806 19.543 ;
     RECT  25.38 19.507 26.802 19.579 ;
     RECT  27.72 19.507 30.654 19.579 ;
     RECT  210.348 19.483 210.366 19.613 ;
     RECT  9.036 19.531 19.962 19.615 ;
     RECT  20.7 19.471 24.297 19.615 ;
     RECT  25.38 19.579 26.946 19.615 ;
     RECT  27.72 19.579 30.906 19.615 ;
     RECT  59.76 19.471 60.786 19.615 ;
     RECT  61.815 19.507 62.154 19.615 ;
     RECT  58.284 19.543 58.878 19.627 ;
     RECT  59.76 19.615 62.154 19.627 ;
     RECT  25.38 19.615 30.906 19.643 ;
     RECT  2.415 18.455 2.697 19.651 ;
     RECT  30.78 19.643 30.906 19.651 ;
     RECT  33.156 19.579 33.174 19.651 ;
     RECT  34.815 2.413 35.097 19.651 ;
     RECT  54.828 19.381 54.846 19.651 ;
     RECT  214.2 19.535 214.434 19.651 ;
     RECT  215.208 19.229 215.514 19.651 ;
     RECT  214.2 19.651 215.514 19.679 ;
     RECT  9.036 19.615 24.297 19.741 ;
     RECT  34.815 19.651 35.622 19.741 ;
     RECT  30.78 19.651 31.122 19.768 ;
     RECT  214.416 19.679 215.514 19.769 ;
     RECT  30.78 19.768 31.374 19.777 ;
     RECT  32.688 19.651 33.174 19.777 ;
     RECT  34.2 19.741 35.622 19.777 ;
     RECT  45.615 2.413 45.897 19.777 ;
     RECT  211.464 19.768 211.482 19.777 ;
     RECT  25.38 19.643 30.006 19.805 ;
     RECT  32.688 19.777 35.622 19.805 ;
     RECT  58.284 19.627 62.154 19.805 ;
     RECT  90.036 19.768 90.054 19.805 ;
     RECT  91.152 19.741 91.17 19.805 ;
     RECT  211.464 19.777 212.022 19.805 ;
     RECT  9.036 19.741 24.606 19.813 ;
     RECT  25.38 19.805 25.398 19.813 ;
     RECT  58.356 19.805 62.154 19.841 ;
     RECT  33.048 19.805 35.622 19.849 ;
     RECT  36.504 19.813 36.63 19.849 ;
     RECT  30.78 19.777 31.806 19.853 ;
     RECT  54.72 19.651 54.846 19.877 ;
     RECT  213.015 19.535 213.354 19.877 ;
     RECT  45.324 19.777 45.897 19.885 ;
     RECT  4.212 19.301 8.262 19.921 ;
     RECT  33.048 19.849 36.63 19.921 ;
     RECT  37.44 19.777 37.458 19.921 ;
     RECT  9.036 19.813 25.398 19.949 ;
     RECT  39.24 19.885 39.258 20.011 ;
     RECT  121.068 18.833 121.554 20.039 ;
     RECT  33.048 19.921 37.458 20.047 ;
     RECT  44.208 20.011 44.226 20.047 ;
     RECT  45.324 19.885 46.17 20.047 ;
     RECT  48.384 19.849 48.402 20.047 ;
     RECT  63.216 19.963 63.234 20.047 ;
     RECT  38.52 20.011 39.258 20.059 ;
     RECT  4.032 19.921 8.262 20.075 ;
     RECT  33.048 20.047 37.494 20.083 ;
     RECT  38.34 20.059 39.366 20.083 ;
     RECT  44.208 20.047 44.442 20.083 ;
     RECT  33.048 20.083 39.366 20.119 ;
     RECT  63.216 20.047 63.342 20.119 ;
     RECT  62.928 20.119 63.342 20.147 ;
     RECT  44.136 20.083 44.442 20.149 ;
     RECT  43.992 20.149 44.442 20.155 ;
     RECT  45.324 20.047 46.782 20.155 ;
     RECT  54.828 19.877 54.846 20.155 ;
     RECT  2.415 19.651 3.114 20.191 ;
     RECT  4.212 20.075 8.262 20.191 ;
     RECT  9.036 19.949 25.182 20.191 ;
     RECT  33.048 20.119 39.474 20.191 ;
     RECT  40.215 2.413 40.497 20.191 ;
     RECT  41.904 20.119 41.922 20.191 ;
     RECT  43.992 20.155 47.034 20.191 ;
     RECT  48.024 20.047 48.402 20.191 ;
     RECT  54.828 20.155 54.918 20.191 ;
     RECT  56.415 2.413 56.697 20.191 ;
     RECT  62.928 20.147 62.946 20.219 ;
     RECT  33.048 20.191 40.554 20.281 ;
     RECT  123.948 19.499 123.966 20.309 ;
     RECT  219.42 20.107 219.438 20.309 ;
     RECT  41.832 20.191 41.922 20.317 ;
     RECT  42.768 20.281 42.786 20.317 ;
     RECT  43.992 20.191 48.402 20.317 ;
     RECT  54.828 20.191 56.697 20.317 ;
     RECT  58.464 19.841 62.154 20.317 ;
     RECT  214.416 19.769 215.442 20.345 ;
     RECT  33.048 20.281 40.842 20.425 ;
     RECT  41.724 20.317 42.786 20.425 ;
     RECT  54.828 20.317 56.862 20.425 ;
     RECT  214.416 20.345 215.118 20.425 ;
     RECT  2.415 20.191 3.15 20.461 ;
     RECT  53.136 20.461 53.838 20.525 ;
     RECT  26.244 19.805 29.862 20.551 ;
     RECT  30.78 19.853 31.626 20.551 ;
     RECT  43.956 20.317 48.402 20.551 ;
     RECT  2.415 20.461 3.402 20.579 ;
     RECT  214.344 20.425 215.118 20.579 ;
     RECT  33.048 20.425 42.786 20.587 ;
     RECT  53.388 20.525 53.838 20.587 ;
     RECT  54.828 20.425 56.97 20.587 ;
     RECT  58.464 20.317 62.73 20.587 ;
     RECT  212.004 19.805 212.022 20.587 ;
     RECT  213.015 19.877 213.297 20.587 ;
     RECT  214.416 20.579 214.902 20.615 ;
     RECT  53.388 20.587 54.09 20.623 ;
     RECT  54.828 20.587 62.73 20.623 ;
     RECT  32.4 20.587 42.786 20.659 ;
     RECT  43.56 20.551 48.402 20.659 ;
     RECT  30.708 20.551 31.626 20.695 ;
     RECT  32.4 20.659 48.402 20.695 ;
     RECT  121.068 20.039 121.497 20.695 ;
     RECT  30.708 20.695 48.402 20.857 ;
     RECT  90.612 20.821 90.63 20.861 ;
     RECT  53.388 20.623 62.73 20.885 ;
     RECT  212.004 20.587 213.297 20.92 ;
     RECT  30.708 20.857 48.438 20.929 ;
     RECT  49.248 20.011 49.266 20.929 ;
     RECT  206.352 20.827 206.37 20.957 ;
     RECT  211.428 20.92 213.297 20.957 ;
     RECT  212.112 20.957 213.297 20.993 ;
     RECT  4.212 20.191 25.182 21.001 ;
     RECT  30.708 20.929 49.266 21.001 ;
     RECT  2.415 20.579 2.697 21.019 ;
     RECT  4.176 21.001 25.182 21.029 ;
     RECT  30.708 21.001 49.734 21.091 ;
     RECT  51.015 2.413 51.297 21.091 ;
     RECT  22.068 21.029 25.182 21.127 ;
     RECT  2.304 21.019 2.697 21.155 ;
     RECT  4.176 21.029 21.222 21.155 ;
     RECT  212.724 20.993 213.297 21.155 ;
     RECT  22.068 21.127 25.29 21.199 ;
     RECT  26.244 20.551 29.898 21.235 ;
     RECT  30.708 21.091 51.297 21.271 ;
     RECT  217.116 21.235 217.134 21.271 ;
     RECT  217.116 21.271 217.242 21.361 ;
     RECT  30.636 21.271 51.354 21.397 ;
     RECT  52.524 20.731 52.542 21.397 ;
     RECT  26.208 21.235 29.898 21.403 ;
     RECT  30.636 21.397 52.542 21.403 ;
     RECT  117.792 21.163 117.81 21.425 ;
     RECT  218.88 21.397 218.898 21.437 ;
     RECT  217.116 21.361 217.818 21.461 ;
     RECT  26.208 21.403 52.542 21.469 ;
     RECT  215.82 21.433 215.838 21.469 ;
     RECT  214.416 20.615 214.434 21.505 ;
     RECT  215.424 21.469 215.838 21.505 ;
     RECT  120.816 20.695 121.497 21.541 ;
     RECT  214.416 21.505 215.838 21.541 ;
     RECT  217.116 21.461 217.422 21.541 ;
     RECT  214.416 21.541 216.018 21.581 ;
     RECT  211.176 21.361 211.194 21.631 ;
     RECT  53.496 20.885 62.73 21.659 ;
     RECT  214.416 21.581 215.838 21.659 ;
     RECT  0.108 17.419 0.126 21.667 ;
     RECT  214.416 21.659 215.73 21.695 ;
     RECT  217.008 21.541 217.422 21.695 ;
     RECT  0.108 21.667 0.558 21.725 ;
     RECT  75.816 21.469 75.834 21.731 ;
     RECT  4.212 21.155 21.222 21.775 ;
     RECT  214.416 21.695 215.442 21.839 ;
     RECT  22.068 21.199 25.47 21.901 ;
     RECT  26.208 21.469 52.578 21.901 ;
     RECT  53.496 21.659 62.334 21.901 ;
     RECT  213.015 21.155 213.297 21.928 ;
     RECT  214.416 21.839 214.866 21.928 ;
     RECT  4.212 21.775 21.258 21.937 ;
     RECT  21.996 21.901 62.334 21.937 ;
     RECT  92.304 21.928 92.322 21.965 ;
     RECT  93.42 21.901 93.438 21.965 ;
     RECT  213.015 21.928 214.866 21.965 ;
     RECT  217.224 21.695 217.422 21.965 ;
     RECT  4.212 21.937 62.334 22.001 ;
     RECT  214.2 21.965 214.866 22.037 ;
     RECT  4.212 22.001 58.95 22.081 ;
     RECT  3.636 22.081 58.95 22.199 ;
     RECT  120.708 21.541 121.497 22.235 ;
     RECT  217.26 21.965 217.422 22.235 ;
     RECT  9 22.199 58.95 22.469 ;
     RECT  59.832 22.001 62.334 22.469 ;
     RECT  3.636 22.199 8.262 22.505 ;
     RECT  124.02 22.315 124.038 22.505 ;
     RECT  34.344 22.469 41.418 22.55 ;
     RECT  3.636 22.505 8.097 22.585 ;
     RECT  34.344 22.55 41.382 22.589 ;
     RECT  2.415 21.155 2.697 22.621 ;
     RECT  216.252 22.585 216.27 22.621 ;
     RECT  206.604 22.171 206.622 22.711 ;
     RECT  219.42 22.699 219.438 22.739 ;
     RECT  59.832 22.469 62.097 22.775 ;
     RECT  122.544 22.351 122.562 22.775 ;
     RECT  217.8 22.621 217.818 22.775 ;
     RECT  34.344 22.589 41.202 22.784 ;
     RECT  213.015 21.965 213.297 22.795 ;
     RECT  214.2 22.037 214.218 22.795 ;
     RECT  215.172 22.711 215.19 22.829 ;
     RECT  34.344 22.784 41.166 22.883 ;
     RECT  42.156 22.469 58.95 22.883 ;
     RECT  2.415 22.621 2.79 22.891 ;
     RECT  3.6 22.585 8.097 22.891 ;
     RECT  213.015 22.795 214.218 22.891 ;
     RECT  216.252 22.621 216.486 22.891 ;
     RECT  34.344 22.883 41.022 23.009 ;
     RECT  216.108 22.891 216.486 23.045 ;
     RECT  42.444 22.883 58.95 23.161 ;
     RECT  59.832 22.775 61.038 23.161 ;
     RECT  213.015 22.891 214.398 23.161 ;
     RECT  213.015 23.161 214.974 23.213 ;
     RECT  9 22.469 33.606 23.251 ;
     RECT  34.344 23.009 40.806 23.251 ;
     RECT  2.415 22.891 8.097 23.287 ;
     RECT  216.36 23.045 216.486 23.315 ;
     RECT  2.415 23.287 8.154 23.323 ;
     RECT  9 23.251 40.806 23.323 ;
     RECT  121.215 22.235 121.497 23.431 ;
     RECT  207.615 19.517 207.897 23.521 ;
     RECT  216.396 23.315 216.486 23.549 ;
     RECT  120.672 23.431 121.497 23.585 ;
     RECT  125.244 23.395 125.262 23.585 ;
     RECT  214.2 23.213 214.974 23.585 ;
     RECT  216.396 23.549 216.414 23.585 ;
     RECT  214.272 23.585 214.974 23.621 ;
     RECT  213.015 23.213 213.318 23.629 ;
     RECT  212.616 23.629 213.318 23.657 ;
     RECT  214.272 23.621 214.326 23.657 ;
     RECT  42.444 23.161 61.038 23.729 ;
     RECT  67.215 17.357 67.497 23.791 ;
     RECT  78.015 17.357 78.297 23.791 ;
     RECT  88.815 17.357 89.097 23.791 ;
     RECT  99.615 17.357 99.897 23.791 ;
     RECT  110.415 17.357 110.697 23.791 ;
     RECT  132.015 17.357 132.297 23.791 ;
     RECT  142.815 17.357 143.097 23.791 ;
     RECT  153.615 17.357 153.897 23.791 ;
     RECT  164.415 17.357 164.697 23.791 ;
     RECT  175.215 17.357 175.497 23.791 ;
     RECT  186.015 17.357 186.297 23.791 ;
     RECT  196.815 17.357 197.097 23.791 ;
     RECT  207.615 23.521 208.314 23.791 ;
     RECT  61.815 22.775 62.097 23.803 ;
     RECT  94.215 17.453 94.497 23.803 ;
     RECT  91.764 23.791 91.782 23.827 ;
     RECT  77.904 23.791 78.297 23.837 ;
     RECT  88.704 23.791 89.097 23.837 ;
     RECT  91.764 23.827 92.178 23.837 ;
     RECT  99.504 23.791 99.897 23.837 ;
     RECT  110.304 23.791 110.697 23.837 ;
     RECT  131.904 23.791 132.297 23.837 ;
     RECT  142.704 23.791 143.097 23.837 ;
     RECT  153.504 23.791 153.897 23.837 ;
     RECT  164.304 23.791 164.697 23.837 ;
     RECT  175.104 23.791 175.497 23.837 ;
     RECT  185.904 23.791 186.297 23.837 ;
     RECT  196.704 23.791 197.097 23.837 ;
     RECT  207.504 23.791 208.314 23.837 ;
     RECT  92.16 23.837 92.178 23.899 ;
     RECT  92.16 23.899 92.898 23.927 ;
     RECT  61.815 23.803 62.694 23.933 ;
     RECT  94.215 23.803 94.626 23.933 ;
     RECT  92.88 23.927 92.898 23.999 ;
     RECT  206.028 22.711 206.622 24.061 ;
     RECT  2.415 23.323 40.806 24.089 ;
     RECT  219.42 23.947 219.438 24.089 ;
     RECT  215.244 23.791 215.442 24.133 ;
     RECT  217.8 24.061 217.818 24.161 ;
     RECT  215.244 24.133 215.514 24.205 ;
     RECT  2.415 24.089 32.49 24.233 ;
     RECT  33.3 24.089 40.806 24.241 ;
     RECT  42.444 23.729 45.99 24.241 ;
     RECT  46.98 23.729 61.038 24.367 ;
     RECT  61.815 23.933 62.097 24.367 ;
     RECT  109.116 23.935 109.134 24.367 ;
     RECT  115.815 2.413 116.097 24.367 ;
     RECT  67.104 23.791 67.497 24.368 ;
     RECT  109.116 24.367 109.458 24.395 ;
     RECT  215.244 24.205 215.586 24.395 ;
     RECT  212.616 23.657 213.297 24.403 ;
     RECT  215.352 24.395 215.586 24.431 ;
     RECT  106.596 24.367 106.614 24.467 ;
     RECT  109.368 24.395 109.458 24.467 ;
     RECT  33.3 24.241 40.914 24.511 ;
     RECT  42.048 24.241 45.99 24.511 ;
     RECT  63.036 24.205 63.054 24.511 ;
     RECT  77.22 24.331 77.238 24.511 ;
     RECT  74.7 24.511 74.718 24.619 ;
     RECT  78.015 23.837 78.297 24.619 ;
     RECT  63.036 24.511 63.306 24.629 ;
     RECT  215.424 24.431 215.586 24.629 ;
     RECT  74.664 24.619 74.718 24.637 ;
     RECT  75.996 24.331 76.014 24.653 ;
     RECT  214.308 23.657 214.326 24.653 ;
     RECT  74.628 24.637 74.718 24.673 ;
     RECT  2.415 24.233 32.166 24.701 ;
     RECT  46.98 24.367 62.097 24.701 ;
     RECT  63.252 24.629 63.306 24.709 ;
     RECT  105.015 2.413 105.297 24.709 ;
     RECT  77.184 24.511 77.238 24.745 ;
     RECT  212.292 24.403 213.297 24.745 ;
     RECT  33.3 24.511 46.098 24.781 ;
     RECT  46.98 24.701 57.618 24.781 ;
     RECT  76.932 24.745 77.238 24.781 ;
     RECT  15.984 24.701 32.166 24.809 ;
     RECT  33.3 24.781 57.618 24.809 ;
     RECT  74.124 24.673 74.718 24.809 ;
     RECT  36.648 24.809 57.618 24.899 ;
     RECT  63.252 24.709 63.342 24.899 ;
     RECT  90.648 23.827 90.666 24.899 ;
     RECT  215.424 24.629 215.514 24.899 ;
     RECT  36.648 24.899 57.51 24.935 ;
     RECT  76.716 24.781 77.238 24.935 ;
     RECT  215.424 24.899 215.442 24.935 ;
     RECT  91.764 24.907 91.782 24.944 ;
     RECT  15.984 24.809 27.378 25.007 ;
     RECT  69.732 24.781 69.75 25.051 ;
     RECT  78.015 24.619 78.57 25.051 ;
     RECT  28.116 24.809 32.166 25.141 ;
     RECT  61.815 24.701 62.097 25.147 ;
     RECT  212.076 24.745 213.297 25.177 ;
     RECT  36.648 24.935 57.438 25.205 ;
     RECT  210.6 21.631 211.194 25.213 ;
     RECT  211.968 25.177 213.297 25.213 ;
     RECT  42.228 25.205 57.438 25.241 ;
     RECT  78.015 25.051 79.398 25.241 ;
     RECT  61.815 25.147 62.19 25.277 ;
     RECT  86.652 25.147 86.67 25.277 ;
     RECT  15.984 25.007 27.198 25.286 ;
     RECT  36.648 25.205 41.202 25.313 ;
     RECT  74.124 24.809 74.682 25.313 ;
     RECT  69.156 25.051 70.29 25.321 ;
     RECT  105.015 24.709 105.57 25.321 ;
     RECT  42.228 25.241 53.334 25.439 ;
     RECT  54.108 25.241 57.438 25.439 ;
     RECT  58.608 24.701 60.966 25.439 ;
     RECT  90.036 25.243 90.054 25.439 ;
     RECT  105.015 25.321 105.822 25.439 ;
     RECT  219.42 25.243 219.438 25.439 ;
     RECT  91.152 25.411 91.17 25.469 ;
     RECT  15.984 25.286 27.162 25.475 ;
     RECT  42.444 25.439 47.898 25.475 ;
     RECT  48.708 25.439 53.334 25.475 ;
     RECT  54.252 25.439 55.242 25.475 ;
     RECT  105.015 25.439 105.57 25.475 ;
     RECT  114.192 25.249 114.21 25.475 ;
     RECT  115.815 24.367 116.586 25.475 ;
     RECT  48.708 25.475 51.534 25.511 ;
     RECT  58.608 25.439 59.13 25.511 ;
     RECT  217.584 25.411 217.602 25.511 ;
     RECT  54.324 25.475 55.242 25.517 ;
     RECT  55.98 25.439 57.078 25.517 ;
     RECT  33.3 24.809 35.874 25.547 ;
     RECT  48.708 25.511 49.446 25.547 ;
     RECT  56.088 25.517 57.078 25.547 ;
     RECT  28.116 25.141 32.562 25.555 ;
     RECT  60.228 25.439 60.966 25.555 ;
     RECT  61.815 25.277 62.097 25.555 ;
     RECT  214.056 25.447 214.074 25.555 ;
     RECT  69.156 25.321 70.686 25.565 ;
     RECT  50.256 25.511 51.534 25.583 ;
     RECT  28.044 25.555 32.562 25.591 ;
     RECT  33.3 25.547 35.694 25.591 ;
     RECT  69.372 25.565 70.686 25.591 ;
     RECT  132.015 23.837 132.297 25.591 ;
     RECT  210.6 25.213 213.297 25.591 ;
     RECT  214.056 25.555 214.758 25.591 ;
     RECT  28.044 25.591 35.694 25.613 ;
     RECT  28.332 25.613 35.694 25.619 ;
     RECT  36.648 25.313 39.402 25.619 ;
     RECT  58.608 25.511 58.734 25.619 ;
     RECT  37.656 25.619 39.402 25.661 ;
     RECT  50.256 25.583 51.297 25.667 ;
     RECT  60.228 25.555 62.097 25.667 ;
     RECT  67.215 24.368 67.497 25.667 ;
     RECT  72.615 2.413 72.897 25.667 ;
     RECT  78.015 25.241 78.858 25.667 ;
     RECT  83.415 2.413 83.697 25.667 ;
     RECT  88.815 23.837 89.097 25.667 ;
     RECT  99.615 23.837 99.897 25.667 ;
     RECT  105.015 25.475 105.297 25.667 ;
     RECT  110.415 23.837 110.697 25.667 ;
     RECT  115.815 25.475 116.097 25.667 ;
     RECT  120.924 23.585 121.497 25.667 ;
     RECT  126.615 2.413 126.897 25.667 ;
     RECT  137.415 2.413 137.697 25.667 ;
     RECT  142.815 23.837 143.097 25.667 ;
     RECT  148.215 2.413 148.497 25.667 ;
     RECT  153.615 23.837 153.897 25.667 ;
     RECT  159.015 2.413 159.297 25.667 ;
     RECT  164.415 23.837 164.697 25.667 ;
     RECT  169.815 2.413 170.097 25.667 ;
     RECT  175.215 23.837 175.497 25.667 ;
     RECT  180.615 2.413 180.897 25.667 ;
     RECT  186.015 23.837 186.297 25.667 ;
     RECT  191.415 2.413 191.697 25.667 ;
     RECT  196.815 23.837 197.097 25.667 ;
     RECT  94.215 23.933 94.497 25.681 ;
     RECT  30.708 25.619 35.694 25.709 ;
     RECT  42.444 25.475 46.998 25.709 ;
     RECT  48.708 25.547 49.122 25.709 ;
     RECT  50.256 25.667 51.174 25.709 ;
     RECT  56.16 25.547 57.078 25.709 ;
     RECT  58.608 25.619 58.626 25.709 ;
     RECT  60.228 25.667 61.905 25.709 ;
     RECT  210.6 25.591 214.758 25.709 ;
     RECT  0.108 21.725 0.126 25.745 ;
     RECT  33.084 25.709 35.694 25.745 ;
     RECT  38.16 25.661 39.402 25.745 ;
     RECT  56.16 25.709 57.006 25.745 ;
     RECT  60.228 25.709 60.354 25.745 ;
     RECT  61.236 25.709 61.905 25.745 ;
     RECT  74.124 25.313 74.142 25.745 ;
     RECT  36.648 25.619 36.918 25.757 ;
     RECT  38.772 25.745 39.402 25.757 ;
     RECT  210.6 25.709 211.698 25.757 ;
     RECT  40.215 25.313 41.202 25.781 ;
     RECT  43.956 25.709 46.998 25.781 ;
     RECT  63.252 24.899 63.27 25.781 ;
     RECT  48.708 25.709 48.87 25.817 ;
     RECT  56.16 25.745 56.574 25.817 ;
     RECT  94.215 25.681 94.698 25.817 ;
     RECT  2.415 24.701 15.174 25.825 ;
     RECT  15.984 25.475 26.982 25.825 ;
     RECT  199.26 24.637 199.278 25.825 ;
     RECT  30.708 25.709 31.95 25.853 ;
     RECT  34.164 25.745 35.694 25.853 ;
     RECT  43.956 25.781 44.55 25.853 ;
     RECT  60.336 25.745 60.354 25.853 ;
     RECT  69.372 25.591 71.226 25.861 ;
     RECT  34.776 25.853 35.694 25.889 ;
     RECT  40.215 25.781 40.698 25.889 ;
     RECT  45.288 25.781 46.998 25.889 ;
     RECT  50.256 25.709 51.105 25.889 ;
     RECT  34.815 25.889 35.694 25.937 ;
     RECT  40.215 25.889 40.305 25.937 ;
     RECT  45.615 25.889 46.998 25.937 ;
     RECT  51.015 25.889 51.105 25.937 ;
     RECT  56.16 25.817 56.505 25.937 ;
     RECT  61.815 25.745 61.905 25.937 ;
     RECT  67.215 25.667 67.305 25.937 ;
     RECT  72.615 25.667 72.705 25.937 ;
     RECT  78.015 25.667 78.105 25.937 ;
     RECT  83.415 25.667 83.505 25.937 ;
     RECT  88.815 25.667 88.905 25.937 ;
     RECT  94.215 25.817 94.305 25.937 ;
     RECT  99.615 25.667 99.705 25.937 ;
     RECT  105.015 25.667 105.105 25.937 ;
     RECT  110.415 25.667 110.505 25.937 ;
     RECT  115.815 25.667 115.905 25.937 ;
     RECT  120.924 25.667 121.305 25.937 ;
     RECT  126.615 25.667 126.705 25.937 ;
     RECT  132.015 25.591 132.39 25.937 ;
     RECT  137.415 25.667 137.505 25.937 ;
     RECT  142.815 25.667 142.905 25.937 ;
     RECT  148.215 25.667 148.305 25.937 ;
     RECT  153.615 25.667 153.705 25.937 ;
     RECT  159.015 25.667 159.105 25.937 ;
     RECT  164.415 25.667 164.505 25.937 ;
     RECT  169.815 25.667 169.905 25.937 ;
     RECT  175.215 25.667 175.305 25.937 ;
     RECT  180.615 25.667 180.705 25.937 ;
     RECT  186.015 25.667 186.105 25.937 ;
     RECT  191.415 25.667 191.505 25.937 ;
     RECT  196.815 25.667 196.905 25.937 ;
     RECT  31.86 25.853 31.95 25.979 ;
     RECT  33.084 25.745 33.138 25.979 ;
     RECT  38.772 25.757 38.862 25.979 ;
     RECT  46.044 25.937 46.998 25.979 ;
     RECT  76.752 24.935 77.238 25.979 ;
     RECT  2.415 25.825 26.982 25.997 ;
     RECT  30.708 25.853 31.05 26.015 ;
     RECT  31.932 25.979 31.95 26.015 ;
     RECT  33.12 25.979 33.138 26.015 ;
     RECT  35.424 25.937 35.694 26.015 ;
     RECT  212.616 25.709 214.758 26.015 ;
     RECT  24.156 25.997 26.982 26.051 ;
     RECT  35.424 26.015 35.442 26.051 ;
     RECT  38.772 25.979 38.79 26.051 ;
     RECT  46.116 25.979 46.998 26.051 ;
     RECT  26.604 26.051 26.982 26.087 ;
     RECT  28.332 25.619 29.97 26.159 ;
     RECT  30.78 26.015 31.05 26.159 ;
     RECT  36.9 25.757 36.918 26.159 ;
     RECT  28.332 26.159 29.898 26.204 ;
     RECT  114.444 25.591 114.462 26.249 ;
     RECT  213.015 26.015 214.758 26.285 ;
     RECT  0.144 26.299 0.162 26.357 ;
     RECT  205.452 24.061 206.622 26.365 ;
     RECT  24.156 26.051 25.686 26.393 ;
     RECT  214.092 26.285 214.11 26.393 ;
     RECT  203.868 26.329 203.886 26.401 ;
     RECT  205.02 26.365 206.622 26.401 ;
     RECT  54.396 25.517 55.242 26.477 ;
     RECT  215.676 26.401 215.694 26.491 ;
     RECT  216.9 26.401 216.99 26.491 ;
     RECT  132.372 25.937 132.39 26.519 ;
     RECT  52.272 25.475 53.334 26.525 ;
     RECT  109.368 24.467 109.386 26.555 ;
     RECT  203.724 26.401 204.174 26.555 ;
     RECT  215.676 26.491 216.99 26.555 ;
     RECT  48.852 25.817 48.87 26.573 ;
     RECT  43.956 25.853 43.974 26.591 ;
     RECT  108.216 25.861 108.234 26.591 ;
     RECT  215.676 26.555 216.306 26.591 ;
     RECT  46.584 26.051 46.998 26.621 ;
     RECT  28.332 26.204 28.53 26.627 ;
     RECT  2.415 25.997 23.274 26.635 ;
     RECT  203.76 26.555 204.174 26.635 ;
     RECT  204.948 26.401 206.622 26.635 ;
     RECT  28.332 26.627 28.35 26.663 ;
     RECT  217.368 26.599 217.602 26.671 ;
     RECT  24.156 26.393 25.254 26.699 ;
     RECT  203.76 26.635 206.622 26.789 ;
     RECT  219.42 26.539 219.438 26.789 ;
     RECT  2.412 26.635 23.274 26.825 ;
     RECT  217.368 26.671 217.818 26.825 ;
     RECT  47.88 25.475 47.898 26.933 ;
     RECT  215.604 26.761 215.622 26.941 ;
     RECT  69.372 25.861 71.766 26.969 ;
     RECT  203.832 26.789 206.622 26.969 ;
     RECT  70.272 26.969 71.766 27.053 ;
     RECT  26.604 26.087 26.802 27.059 ;
     RECT  203.832 26.969 204.174 27.059 ;
     RECT  56.16 25.937 56.178 27.095 ;
     RECT  70.272 27.053 70.686 27.095 ;
     RECT  71.748 27.053 71.766 27.101 ;
     RECT  202.215 2.413 202.497 27.103 ;
     RECT  42.444 25.709 43.074 27.131 ;
     RECT  78.84 25.667 78.858 27.131 ;
     RECT  52.272 26.525 52.65 27.167 ;
     RECT  116.82 25.591 116.838 27.167 ;
     RECT  29.88 26.204 29.898 27.203 ;
     RECT  210.6 25.757 211.194 27.211 ;
     RECT  25.2 26.699 25.254 27.239 ;
     RECT  120.924 25.937 120.942 27.239 ;
     RECT  25.2 27.239 25.218 27.284 ;
     RECT  24.156 26.699 24.174 27.329 ;
     RECT  202.215 27.103 202.95 27.509 ;
     RECT  213.015 26.285 213.297 27.547 ;
     RECT  214.092 27.481 214.11 27.547 ;
     RECT  2.415 26.825 23.274 27.599 ;
     RECT  213.015 27.547 214.11 27.599 ;
     RECT  2.415 27.599 15.174 27.635 ;
     RECT  203.832 27.059 203.85 27.643 ;
     RECT  204.948 26.969 206.622 27.679 ;
     RECT  207.615 23.837 208.314 27.679 ;
     RECT  204.948 27.679 208.314 27.715 ;
     RECT  215.1 26.941 215.622 27.751 ;
     RECT  217.548 27.715 217.566 27.751 ;
     RECT  214.884 27.751 215.622 27.841 ;
     RECT  216.468 27.751 216.558 27.869 ;
     RECT  217.548 27.751 217.746 27.869 ;
     RECT  219.42 27.832 219.438 27.869 ;
     RECT  214.884 27.841 215.658 27.905 ;
     RECT  216.54 27.869 216.558 27.905 ;
     RECT  217.728 27.869 217.746 27.905 ;
     RECT  215.1 27.905 215.658 27.941 ;
     RECT  200.7 27.841 200.718 27.985 ;
     RECT  15.948 27.599 23.274 28.08 ;
     RECT  26.784 27.059 26.802 28.08 ;
     RECT  31.032 26.159 31.05 28.08 ;
     RECT  43.056 27.131 43.074 28.08 ;
     RECT  46.98 26.621 46.998 28.08 ;
     RECT  52.272 27.167 52.29 28.08 ;
     RECT  54.504 26.477 55.242 28.08 ;
     RECT  69.372 26.969 69.39 28.08 ;
     RECT  70.668 27.095 70.686 28.08 ;
     RECT  77.22 25.979 77.238 28.08 ;
     RECT  95.76 25.861 95.778 28.08 ;
     RECT  119.988 23.971 120.006 28.08 ;
     RECT  199.188 25.825 199.278 28.111 ;
     RECT  200.052 27.985 200.718 28.111 ;
     RECT  199.188 28.111 200.718 28.147 ;
     RECT  199.188 28.147 201.222 28.255 ;
     RECT  15.948 28.08 197.64 28.381 ;
     RECT  199.188 28.255 201.402 28.381 ;
     RECT  202.215 27.509 202.497 28.381 ;
     RECT  199.188 28.381 202.734 28.453 ;
     RECT  203.508 27.643 203.85 28.453 ;
     RECT  2.415 27.635 15.138 28.723 ;
     RECT  15.948 28.381 197.766 28.723 ;
     RECT  213.015 27.599 213.297 28.831 ;
     RECT  199.188 28.453 203.85 28.921 ;
     RECT  204.876 27.715 208.314 28.921 ;
     RECT  2.415 28.723 197.766 28.939 ;
     RECT  213.015 28.831 213.354 28.949 ;
     RECT  219.42 29.131 219.438 29.219 ;
     RECT  2.304 28.939 197.766 29.263 ;
     RECT  217.8 29.191 217.818 29.291 ;
     RECT  2.304 29.263 198.378 29.323 ;
     RECT  199.188 28.921 208.314 29.323 ;
     RECT  214.344 28.921 214.362 29.371 ;
     RECT  215.1 27.941 215.622 29.371 ;
     RECT  214.344 29.371 215.622 29.525 ;
     RECT  2.304 29.323 208.314 29.633 ;
     RECT  3.42 29.633 208.314 29.669 ;
     RECT  213.015 28.949 213.297 29.707 ;
     RECT  214.344 29.525 214.362 29.707 ;
     RECT  213.015 29.707 214.362 29.731 ;
     RECT  210.6 27.211 211.374 29.839 ;
     RECT  212.472 29.731 214.362 29.839 ;
     RECT  198.828 29.669 208.314 29.939 ;
     RECT  0.108 26.971 0.126 29.981 ;
     RECT  210.6 29.839 214.362 30.101 ;
     RECT  212.004 30.101 214.362 30.173 ;
     RECT  2.304 29.633 2.697 30.451 ;
     RECT  3.42 29.669 197.64 30.451 ;
     RECT  2.304 30.451 197.64 30.475 ;
     RECT  212.112 30.173 214.362 30.479 ;
     RECT  212.148 30.479 214.362 30.569 ;
     RECT  218.844 30.427 218.862 30.569 ;
     RECT  217.224 30.271 217.242 30.605 ;
     RECT  212.148 30.569 212.166 30.611 ;
     RECT  2.304 30.475 198.378 30.713 ;
     RECT  2.304 30.713 2.898 30.839 ;
     RECT  213.015 30.569 214.362 30.839 ;
     RECT  213.015 30.839 213.498 30.875 ;
     RECT  3.636 30.713 198.378 31.019 ;
     RECT  213.015 30.875 213.354 31.109 ;
     RECT  2.304 30.839 2.697 31.415 ;
     RECT  3.636 31.019 197.766 31.531 ;
     RECT  199.188 29.939 208.314 31.531 ;
     RECT  214.344 30.839 214.362 31.531 ;
     RECT  215.1 29.525 215.622 31.531 ;
     RECT  198.936 31.531 208.314 31.559 ;
     RECT  214.344 31.531 215.622 31.765 ;
     RECT  2.415 31.415 2.697 31.801 ;
     RECT  3.42 31.531 197.766 31.801 ;
     RECT  217.44 31.765 217.458 31.801 ;
     RECT  214.344 31.765 215.73 31.901 ;
     RECT  219.42 31.723 219.438 31.919 ;
     RECT  2.415 31.801 197.766 31.927 ;
     RECT  198.936 31.559 207.897 31.927 ;
     RECT  216.828 31.801 217.818 31.955 ;
     RECT  2.415 31.927 207.897 32.027 ;
     RECT  210.6 30.101 211.194 32.071 ;
     RECT  2.415 32.027 197.73 32.189 ;
     RECT  216.936 31.955 217.566 32.189 ;
     RECT  216.936 32.189 217.53 32.225 ;
     RECT  210.348 32.071 211.194 32.261 ;
     RECT  217.368 32.225 217.53 32.459 ;
     RECT  217.368 32.459 217.386 32.495 ;
     RECT  214.344 31.901 215.622 32.837 ;
     RECT  214.452 32.837 215.622 32.971 ;
     RECT  218.88 33.007 218.898 33.053 ;
     RECT  2.415 32.189 197.64 33.067 ;
     RECT  198.9 32.027 207.897 33.067 ;
     RECT  214.452 32.971 216.27 33.115 ;
     RECT  2.415 33.067 207.897 33.269 ;
     RECT  2.415 33.269 205.794 33.305 ;
     RECT  214.452 33.115 216.486 33.539 ;
     RECT  214.452 33.539 216.378 33.575 ;
     RECT  213.015 31.109 213.297 33.643 ;
     RECT  213.015 33.643 213.354 33.691 ;
     RECT  213.015 33.691 213.642 33.781 ;
     RECT  214.452 33.575 216.27 33.809 ;
     RECT  209.448 22.441 209.466 33.845 ;
     RECT  214.452 33.809 216.198 33.845 ;
     RECT  212.328 33.781 213.642 33.917 ;
     RECT  213.015 33.917 213.642 33.925 ;
     RECT  214.452 33.845 215.622 33.925 ;
     RECT  213.015 33.925 215.622 34.079 ;
     RECT  2.415 33.305 205.722 34.187 ;
     RECT  213.015 34.079 213.57 34.349 ;
     RECT  219.42 34.267 219.438 34.349 ;
     RECT  214.344 34.079 215.622 34.655 ;
     RECT  2.415 34.187 11.682 35.005 ;
     RECT  12.528 34.187 205.11 35.005 ;
     RECT  2.415 35.005 205.11 35.311 ;
     RECT  210.6 32.261 211.194 35.401 ;
     RECT  212.184 33.925 212.202 35.401 ;
     RECT  2.415 35.311 205.326 35.465 ;
     RECT  210.6 35.401 212.202 35.509 ;
     RECT  213.015 34.349 213.297 35.509 ;
     RECT  214.524 34.655 215.622 35.545 ;
     RECT  214.128 35.545 215.622 35.581 ;
     RECT  2.415 35.465 205.11 35.609 ;
     RECT  218.844 35.563 218.862 35.699 ;
     RECT  210.6 35.509 213.297 35.744 ;
     RECT  211.716 35.744 213.297 35.771 ;
     RECT  212.04 35.771 213.297 35.851 ;
     RECT  214.092 35.581 215.622 35.851 ;
     RECT  212.04 35.851 215.622 36.005 ;
     RECT  0.108 30.955 0.126 36.275 ;
     RECT  212.616 36.005 215.622 36.275 ;
     RECT  2.415 35.609 197.64 36.331 ;
     RECT  214.02 36.275 215.622 36.509 ;
     RECT  214.02 36.509 214.038 36.545 ;
     RECT  214.848 36.509 215.622 36.553 ;
     RECT  214.848 36.553 215.946 36.581 ;
     RECT  0.54 36.571 0.558 36.653 ;
     RECT  210.6 35.744 210.618 36.653 ;
     RECT  214.92 36.581 215.946 36.653 ;
     RECT  214.956 36.653 215.946 36.661 ;
     RECT  217.44 36.625 217.458 36.661 ;
     RECT  2.415 36.331 197.73 36.763 ;
     RECT  198.612 35.609 205.11 36.763 ;
     RECT  217.44 36.661 217.566 36.787 ;
     RECT  217.44 36.787 217.674 36.931 ;
     RECT  2.415 36.763 205.11 36.941 ;
     RECT  217.44 36.931 217.818 37.021 ;
     RECT  214.956 36.661 216.414 37.049 ;
     RECT  219.42 36.859 219.438 37.049 ;
     RECT  217.26 37.021 217.818 37.085 ;
     RECT  214.956 37.049 216.27 37.091 ;
     RECT  217.26 37.085 217.458 37.201 ;
     RECT  217.188 37.201 217.458 37.319 ;
     RECT  2.415 36.941 197.73 37.355 ;
     RECT  217.188 37.319 217.386 37.355 ;
     RECT  206.604 33.269 207.897 37.391 ;
     RECT  3.492 37.355 197.73 37.427 ;
     RECT  3.564 37.427 197.73 37.463 ;
     RECT  214.956 37.091 215.622 37.471 ;
     RECT  3.888 37.463 197.73 37.697 ;
     RECT  214.38 37.471 215.622 37.967 ;
     RECT  217.224 37.355 217.386 37.967 ;
     RECT  212.616 36.275 213.297 38.011 ;
     RECT  212.616 38.011 213.786 38.129 ;
     RECT  214.56 37.967 215.622 38.137 ;
     RECT  214.56 38.137 216.09 38.173 ;
     RECT  3.888 37.697 197.64 38.201 ;
     RECT  217.8 38.101 217.818 38.201 ;
     RECT  219.42 38.155 219.438 38.201 ;
     RECT  15.3 38.201 197.64 38.285 ;
     RECT  214.56 38.173 216.63 38.399 ;
     RECT  214.56 38.399 216.414 38.435 ;
     RECT  15.3 38.285 21.402 38.543 ;
     RECT  215.1 38.435 216.414 38.669 ;
     RECT  15.372 38.543 21.402 38.765 ;
     RECT  2.415 37.355 2.697 38.821 ;
     RECT  22.248 38.285 197.64 38.923 ;
     RECT  2.415 38.821 3.15 38.939 ;
     RECT  215.1 38.669 216.27 38.939 ;
     RECT  215.1 38.939 216.09 38.975 ;
     RECT  22.248 38.923 197.73 39.019 ;
     RECT  198.612 36.941 205.11 39.019 ;
     RECT  211.86 39.091 211.878 39.181 ;
     RECT  212.616 38.129 213.297 39.181 ;
     RECT  2.415 38.939 2.697 39.211 ;
     RECT  22.248 39.019 205.11 39.245 ;
     RECT  22.248 39.245 204.894 39.307 ;
     RECT  211.608 39.181 213.297 39.361 ;
     RECT  22.212 39.307 204.894 39.479 ;
     RECT  211.608 39.361 213.57 39.479 ;
     RECT  218.88 39.445 218.898 39.485 ;
     RECT  2.34 39.211 2.697 39.515 ;
     RECT  22.248 39.479 204.894 39.533 ;
     RECT  217.8 39.451 217.818 39.551 ;
     RECT  3.888 38.201 14.562 39.559 ;
     RECT  15.372 38.765 21.366 39.559 ;
     RECT  211.608 39.479 213.426 39.581 ;
     RECT  3.888 39.559 21.366 39.589 ;
     RECT  3.708 39.589 21.366 39.629 ;
     RECT  215.1 38.975 215.622 39.631 ;
     RECT  213.012 39.581 213.297 39.785 ;
     RECT  2.415 39.515 2.697 39.835 ;
     RECT  214.344 39.631 215.622 40.019 ;
     RECT  214.344 40.019 214.362 40.055 ;
     RECT  211.608 39.581 211.626 40.405 ;
     RECT  213.015 39.785 213.297 40.507 ;
     RECT  211.608 40.405 212.058 40.531 ;
     RECT  213.015 40.507 213.57 40.531 ;
     RECT  211.608 40.531 213.57 40.631 ;
     RECT  2.415 39.835 2.754 40.675 ;
     RECT  3.888 39.629 21.366 40.675 ;
     RECT  22.716 39.533 204.894 40.747 ;
     RECT  2.415 40.675 21.366 40.829 ;
     RECT  212.004 40.631 213.57 40.829 ;
     RECT  218.844 40.747 218.862 40.829 ;
     RECT  0.108 37.195 0.126 40.837 ;
     RECT  3.888 40.829 21.366 40.843 ;
     RECT  22.248 40.747 204.894 40.843 ;
     RECT  0.108 40.837 0.558 40.877 ;
     RECT  215.1 40.019 215.622 40.945 ;
     RECT  3.888 40.843 204.894 40.973 ;
     RECT  212.04 40.829 213.57 40.981 ;
     RECT  214.524 40.945 215.622 40.981 ;
     RECT  212.04 40.981 215.622 41.099 ;
     RECT  212.076 41.099 215.622 41.171 ;
     RECT  22.752 40.973 204.894 41.261 ;
     RECT  22.788 41.261 204.894 41.279 ;
     RECT  22.788 41.279 197.73 41.369 ;
     RECT  212.076 41.171 213.297 41.477 ;
     RECT  2.415 40.829 2.697 41.515 ;
     RECT  3.888 40.973 21.69 41.549 ;
     RECT  214.236 41.171 215.622 41.675 ;
     RECT  214.956 41.675 215.622 42.061 ;
     RECT  217.944 42.025 217.962 42.061 ;
     RECT  214.956 42.061 216.27 42.151 ;
     RECT  217.224 42.061 217.962 42.151 ;
     RECT  214.956 42.151 217.962 42.173 ;
     RECT  22.788 41.369 197.64 42.178 ;
     RECT  215.46 42.173 217.962 42.179 ;
     RECT  22.752 42.178 197.64 42.187 ;
     RECT  198.612 41.279 204.894 42.187 ;
     RECT  215.46 42.179 217.818 42.215 ;
     RECT  216.432 42.215 217.818 42.251 ;
     RECT  3.888 41.549 21.654 42.295 ;
     RECT  22.752 42.187 204.894 42.295 ;
     RECT  3.888 42.295 204.894 42.413 ;
     RECT  219.42 42.043 219.438 42.449 ;
     RECT  216.648 42.251 217.818 42.485 ;
     RECT  2.304 41.515 2.697 42.727 ;
     RECT  207.18 37.391 207.897 42.827 ;
     RECT  1.728 42.727 2.697 42.845 ;
     RECT  212.328 41.477 213.297 42.871 ;
     RECT  215.46 42.215 215.622 42.989 ;
     RECT  216.648 42.485 216.846 43.141 ;
     RECT  3.888 42.413 21.942 43.147 ;
     RECT  22.788 42.413 204.894 43.147 ;
     RECT  216.396 43.141 216.846 43.295 ;
     RECT  217.8 42.485 217.818 43.295 ;
     RECT  219.42 43.291 219.438 43.331 ;
     RECT  212.328 42.871 213.354 43.339 ;
     RECT  216.468 43.295 216.846 43.375 ;
     RECT  211.392 43.339 213.354 43.411 ;
     RECT  211.392 43.411 213.39 43.529 ;
     RECT  216.468 43.375 216.918 43.529 ;
     RECT  0.108 40.877 0.126 43.565 ;
     RECT  216.468 43.529 216.846 43.565 ;
     RECT  211.392 43.529 213.354 43.613 ;
     RECT  212.04 43.613 213.354 43.673 ;
     RECT  214.128 43.411 214.146 43.673 ;
     RECT  3.888 43.147 204.894 43.709 ;
     RECT  216.612 43.565 216.774 43.799 ;
     RECT  212.328 43.673 213.354 43.835 ;
     RECT  216.612 43.799 216.63 43.835 ;
     RECT  0.144 43.807 0.558 43.853 ;
     RECT  19.908 43.709 204.894 44.045 ;
     RECT  0.144 43.853 0.162 44.213 ;
     RECT  3.888 43.709 19.134 44.221 ;
     RECT  3.852 44.221 19.134 44.311 ;
     RECT  2.415 42.845 2.697 44.347 ;
     RECT  215.172 44.311 215.19 44.455 ;
     RECT  1.728 44.347 2.697 44.525 ;
     RECT  212.976 43.835 213.354 44.587 ;
     RECT  22.176 44.045 204.894 44.609 ;
     RECT  218.88 44.581 218.898 44.621 ;
     RECT  212.976 44.587 213.894 44.645 ;
     RECT  3.42 44.311 19.134 44.683 ;
     RECT  19.908 44.045 21.366 44.683 ;
     RECT  212.976 44.645 213.354 44.753 ;
     RECT  214.992 44.455 215.19 44.761 ;
     RECT  3.42 44.683 21.366 44.779 ;
     RECT  3.42 44.779 21.69 44.789 ;
     RECT  214.812 44.761 215.19 44.915 ;
     RECT  214.956 44.915 215.19 44.995 ;
     RECT  214.956 44.995 215.226 45.149 ;
     RECT  214.956 45.149 215.19 45.185 ;
     RECT  3.888 44.789 21.69 45.293 ;
     RECT  214.992 45.185 215.19 45.293 ;
     RECT  22.788 44.609 204.894 45.391 ;
     RECT  214.992 45.293 215.154 45.419 ;
     RECT  214.992 45.419 215.01 45.455 ;
     RECT  3.888 45.293 21.366 45.689 ;
     RECT  218.88 45.841 218.898 45.917 ;
     RECT  2.415 44.525 2.697 46.111 ;
     RECT  2.415 46.111 3.186 46.123 ;
     RECT  2.304 46.123 3.186 46.229 ;
     RECT  2.304 46.229 2.697 46.535 ;
     RECT  22.752 45.391 204.894 46.603 ;
     RECT  3.996 45.689 21.366 46.615 ;
     RECT  22.248 46.603 204.894 47.039 ;
     RECT  22.248 47.039 197.766 47.213 ;
     RECT  22.284 47.213 197.766 47.219 ;
     RECT  3.42 46.615 21.366 47.309 ;
     RECT  219.42 47.179 219.438 47.345 ;
     RECT  3.528 47.309 21.366 47.849 ;
     RECT  22.68 47.219 197.766 48.163 ;
     RECT  198.612 47.039 204.894 48.163 ;
     RECT  3.636 47.849 21.366 48.235 ;
     RECT  3.636 48.235 21.654 48.469 ;
     RECT  22.68 48.163 204.894 48.469 ;
     RECT  3.636 48.469 204.894 48.569 ;
     RECT  219.42 48.475 219.438 48.659 ;
     RECT  3.636 48.569 21.366 48.775 ;
     RECT  3.492 48.775 21.366 48.989 ;
     RECT  22.212 48.569 204.894 49.001 ;
     RECT  4.032 48.989 21.366 49.469 ;
     RECT  2.415 46.535 2.697 49.579 ;
     RECT  198.612 49.001 204.894 49.649 ;
     RECT  2.415 49.579 3.258 49.739 ;
     RECT  4.176 49.469 21.366 49.783 ;
     RECT  22.212 49.001 197.766 49.783 ;
     RECT  218.88 49.711 218.898 49.805 ;
     RECT  4.176 49.783 198.45 49.883 ;
     RECT  2.415 49.739 3.114 50.279 ;
     RECT  0.108 44.779 0.126 50.389 ;
     RECT  0.108 50.389 0.558 50.429 ;
     RECT  2.415 50.279 3.042 50.549 ;
     RECT  4.176 49.883 197.766 50.621 ;
     RECT  22.212 50.621 197.766 50.863 ;
     RECT  4.176 50.621 21.366 50.971 ;
     RECT  22.212 50.863 198.45 50.971 ;
     RECT  199.188 49.649 204.894 50.971 ;
     RECT  218.88 50.935 218.898 51.101 ;
     RECT  22.212 50.971 204.894 51.125 ;
     RECT  3.96 50.971 21.366 51.241 ;
     RECT  3.6 51.241 21.366 51.511 ;
     RECT  2.415 50.549 2.697 51.739 ;
     RECT  3.456 51.511 21.366 51.907 ;
     RECT  22.212 51.125 198.45 51.907 ;
     RECT  219.42 52.312 219.438 52.349 ;
     RECT  3.456 51.907 198.45 52.519 ;
     RECT  199.188 51.125 204.894 52.519 ;
     RECT  3.456 52.519 204.894 52.619 ;
     RECT  2.304 51.739 2.697 52.987 ;
     RECT  1.728 52.987 2.697 53.069 ;
     RECT  3.78 52.619 204.894 53.645 ;
     RECT  219.456 53.257 219.474 53.645 ;
     RECT  0.108 50.429 0.126 53.825 ;
     RECT  2.415 53.069 2.697 54.043 ;
     RECT  3.78 53.645 198.378 54.131 ;
     RECT  3.996 54.131 198.378 54.329 ;
     RECT  2.304 54.043 2.697 54.365 ;
     RECT  4.32 54.329 198.378 54.413 ;
     RECT  0.144 54.379 0.162 54.437 ;
     RECT  22.248 54.413 198.378 54.526 ;
     RECT  199.188 53.645 204.894 54.526 ;
     RECT  22.248 54.526 204.894 54.635 ;
     RECT  4.32 54.413 21.366 54.707 ;
     RECT  4.572 54.707 21.366 54.869 ;
     RECT  219.42 54.904 219.438 54.941 ;
     RECT  199.188 54.635 204.894 55.021 ;
     RECT  199.188 55.021 204.966 55.139 ;
     RECT  4.572 54.869 20.178 55.175 ;
     RECT  22.248 54.635 198.45 55.277 ;
     RECT  199.188 55.139 204.93 55.409 ;
     RECT  2.415 54.365 2.697 55.675 ;
     RECT  4.752 55.175 20.178 55.723 ;
     RECT  21.024 54.869 21.366 55.723 ;
     RECT  2.304 55.675 2.697 56.057 ;
     RECT  2.415 56.057 2.697 56.101 ;
     RECT  3.528 55.561 3.546 56.101 ;
     RECT  22.5 55.277 198.45 56.101 ;
     RECT  218.88 56.191 218.898 56.237 ;
     RECT  22.248 56.101 198.45 56.333 ;
     RECT  2.415 56.101 3.546 56.371 ;
     RECT  2.415 56.371 3.906 56.491 ;
     RECT  22.5 56.333 198.45 56.525 ;
     RECT  2.415 56.491 3.942 56.531 ;
     RECT  2.415 56.531 3.906 56.597 ;
     RECT  22.752 56.525 198.45 56.632 ;
     RECT  199.188 55.409 204.894 56.632 ;
     RECT  4.752 55.723 21.366 57.145 ;
     RECT  2.415 56.597 3.474 57.299 ;
     RECT  0.108 54.715 0.126 57.307 ;
     RECT  22.752 56.632 204.894 57.335 ;
     RECT  4.752 57.145 21.69 57.343 ;
     RECT  22.752 57.335 198.45 57.343 ;
     RECT  0.108 57.307 0.162 57.389 ;
     RECT  219.42 57.499 219.438 57.605 ;
     RECT  4.752 57.343 198.45 57.991 ;
     RECT  4.464 57.991 198.45 58.019 ;
     RECT  4.464 58.019 197.766 58.061 ;
     RECT  4.464 58.061 197.73 58.117 ;
     RECT  199.188 57.335 204.894 58.117 ;
     RECT  198.936 58.117 204.894 58.253 ;
     RECT  4.176 58.117 197.73 58.379 ;
     RECT  0.108 57.389 0.126 58.415 ;
     RECT  219.456 58.657 219.474 58.829 ;
     RECT  2.415 57.299 2.697 59.071 ;
     RECT  4.32 58.379 197.73 59.071 ;
     RECT  2.415 59.071 3.114 59.189 ;
     RECT  4.32 59.071 197.766 59.227 ;
     RECT  199.188 58.253 204.894 59.233 ;
     RECT  4.248 59.227 197.766 59.305 ;
     RECT  0.144 58.987 0.162 59.323 ;
     RECT  4.032 59.305 197.766 59.467 ;
     RECT  198.936 59.233 204.894 59.467 ;
     RECT  0.108 59.323 0.162 59.765 ;
     RECT  218.88 60.079 218.898 60.125 ;
     RECT  2.415 59.189 2.862 60.151 ;
     RECT  4.032 59.467 204.894 60.151 ;
     RECT  2.415 60.151 204.894 60.269 ;
     RECT  4.032 60.269 204.894 60.341 ;
     RECT  4.032 60.341 198.45 60.461 ;
     RECT  2.415 60.269 3.294 60.539 ;
     RECT  2.415 60.539 2.697 60.955 ;
     RECT  2.304 60.955 2.697 61.223 ;
     RECT  218.88 61.195 218.898 61.373 ;
     RECT  2.415 61.223 2.697 61.591 ;
     RECT  2.415 61.591 3.402 61.889 ;
     RECT  4.464 60.461 198.45 62.069 ;
     RECT  4.464 62.069 198.414 62.195 ;
     RECT  4.644 62.195 198.414 62.501 ;
     RECT  199.188 60.341 204.894 62.501 ;
     RECT  4.644 62.501 198.378 62.573 ;
     RECT  2.415 61.889 2.697 62.635 ;
     RECT  219.42 62.635 219.438 62.699 ;
     RECT  4.644 62.573 198.054 62.735 ;
     RECT  2.304 62.635 2.697 63.121 ;
     RECT  2.304 63.121 3.15 63.239 ;
     RECT  2.304 63.239 2.97 63.247 ;
     RECT  1.728 63.247 2.97 63.275 ;
     RECT  1.728 63.275 2.697 63.293 ;
     RECT  4.968 62.735 198.054 63.419 ;
     RECT  5.004 63.419 198.054 63.481 ;
     RECT  5.004 63.481 198.378 63.517 ;
     RECT  5.004 63.517 198.45 63.653 ;
     RECT  199.476 62.501 204.894 63.787 ;
     RECT  4.104 63.121 4.122 64.061 ;
     RECT  219.42 63.931 219.438 64.085 ;
     RECT  4.248 64.201 4.266 64.319 ;
     RECT  5.004 63.653 198.054 64.319 ;
     RECT  198.936 63.787 204.894 64.493 ;
     RECT  5.004 64.319 21.438 64.555 ;
     RECT  22.212 64.319 198.054 64.561 ;
     RECT  4.752 64.555 21.438 64.595 ;
     RECT  2.415 63.293 2.697 64.975 ;
     RECT  2.415 64.975 3.15 65.129 ;
     RECT  4.932 64.595 21.438 65.227 ;
     RECT  22.212 64.561 198.45 65.227 ;
     RECT  3.456 65.281 3.546 65.399 ;
     RECT  219.42 65.227 219.438 65.399 ;
     RECT  4.932 65.227 198.45 65.443 ;
     RECT  199.44 64.493 204.894 65.443 ;
     RECT  212.976 44.753 213.297 65.509 ;
     RECT  2.415 65.129 2.697 65.515 ;
     RECT  214.452 65.479 214.47 65.515 ;
     RECT  212.832 65.509 213.297 65.549 ;
     RECT  213.015 65.549 213.297 65.551 ;
     RECT  214.452 65.515 214.866 65.551 ;
     RECT  1.728 65.515 2.697 65.645 ;
     RECT  199.404 65.443 204.894 65.645 ;
     RECT  213.015 65.551 214.866 65.669 ;
     RECT  4.536 65.443 198.45 65.705 ;
     RECT  213.015 65.669 214.758 65.705 ;
     RECT  5.328 65.705 198.45 65.785 ;
     RECT  5.328 65.785 198.486 65.911 ;
     RECT  3.456 65.399 3.474 65.939 ;
     RECT  4.536 65.705 4.554 65.939 ;
     RECT  214.056 65.705 214.758 65.939 ;
     RECT  214.056 65.939 214.614 65.975 ;
     RECT  5.328 65.911 198.666 66.047 ;
     RECT  2.415 65.645 2.697 66.055 ;
     RECT  2.415 66.055 3.114 66.209 ;
     RECT  5.328 66.047 198.63 66.317 ;
     RECT  5.328 66.317 8.37 66.721 ;
     RECT  4.464 66.559 4.482 66.829 ;
     RECT  5.256 66.721 8.37 66.829 ;
     RECT  2.415 66.209 2.862 66.929 ;
     RECT  4.464 66.829 8.37 66.929 ;
     RECT  9.108 66.317 198.63 67.019 ;
     RECT  4.536 66.929 8.37 67.055 ;
     RECT  5.328 67.055 8.37 67.171 ;
     RECT  9.108 67.019 21.69 67.171 ;
     RECT  22.752 67.019 198.63 67.711 ;
     RECT  4.536 67.055 4.554 67.909 ;
     RECT  5.328 67.171 21.69 67.909 ;
     RECT  0.108 59.765 0.126 67.915 ;
     RECT  0.108 67.915 0.162 67.973 ;
     RECT  4.536 67.909 21.69 67.973 ;
     RECT  4.536 67.973 16.974 68.099 ;
     RECT  17.784 67.973 21.69 68.107 ;
     RECT  22.752 67.711 198.666 68.107 ;
     RECT  4.536 68.099 8.298 68.215 ;
     RECT  17.784 68.107 198.666 68.237 ;
     RECT  4.248 68.215 8.298 68.341 ;
     RECT  9.324 68.099 16.974 68.369 ;
     RECT  17.892 68.237 198.666 68.369 ;
     RECT  22.788 68.369 198.666 68.377 ;
     RECT  199.44 65.645 204.894 68.377 ;
     RECT  4.176 68.341 8.298 68.381 ;
     RECT  22.788 68.377 204.894 68.429 ;
     RECT  217.116 68.341 217.134 68.485 ;
     RECT  2.415 66.929 2.697 68.521 ;
     RECT  22.788 68.429 198.666 68.525 ;
     RECT  217.08 68.485 217.134 68.611 ;
     RECT  17.892 68.369 21.69 68.621 ;
     RECT  2.415 68.521 2.934 68.639 ;
     RECT  219.42 68.539 219.438 68.639 ;
     RECT  213.015 65.705 213.297 68.683 ;
     RECT  5.544 68.381 8.298 68.711 ;
     RECT  217.08 68.611 217.818 68.711 ;
     RECT  217.08 68.711 217.35 68.719 ;
     RECT  215.64 68.683 215.658 68.72 ;
     RECT  216.612 68.719 217.35 68.755 ;
     RECT  216.36 68.755 217.35 68.909 ;
     RECT  6.66 68.711 8.298 68.953 ;
     RECT  9.324 68.369 16.686 68.953 ;
     RECT  4.176 68.381 4.806 68.957 ;
     RECT  3.672 69.061 3.69 69.179 ;
     RECT  5.544 68.711 5.886 69.179 ;
     RECT  6.66 68.953 16.686 69.179 ;
     RECT  17.892 68.621 21.366 69.323 ;
     RECT  22.896 68.525 198.666 69.331 ;
     RECT  199.44 68.429 204.894 69.331 ;
     RECT  216.612 68.909 217.314 69.449 ;
     RECT  216.612 69.449 217.17 69.485 ;
     RECT  2.415 68.639 2.697 69.493 ;
     RECT  1.728 69.493 2.697 69.581 ;
     RECT  7.056 69.179 16.686 69.961 ;
     RECT  7.056 69.961 16.722 70.025 ;
     RECT  4.788 68.957 4.806 70.061 ;
     RECT  5.544 69.179 5.742 70.141 ;
     RECT  7.128 70.025 16.722 70.141 ;
     RECT  5.544 70.141 6.282 70.259 ;
     RECT  7.128 70.141 16.866 70.645 ;
     RECT  7.128 70.645 17.478 70.795 ;
     RECT  3.456 70.939 3.474 70.979 ;
     RECT  6.444 70.795 17.478 71.069 ;
     RECT  2.415 69.581 2.697 71.311 ;
     RECT  5.544 70.259 5.634 71.347 ;
     RECT  4.5 71.275 4.518 71.375 ;
     RECT  7.128 71.069 17.478 71.419 ;
     RECT  5.544 71.347 6.21 71.491 ;
     RECT  2.415 71.311 2.934 71.519 ;
     RECT  18.252 69.323 21.366 71.609 ;
     RECT  2.415 71.519 2.697 71.725 ;
     RECT  214.776 68.881 214.794 71.803 ;
     RECT  18.252 71.609 21.042 71.837 ;
     RECT  219.42 71.803 219.438 71.879 ;
     RECT  2.268 71.725 2.697 71.885 ;
     RECT  217.8 71.851 217.818 71.951 ;
     RECT  7.128 71.419 17.514 71.959 ;
     RECT  215.784 71.851 215.802 71.995 ;
     RECT  216.612 69.485 216.63 71.995 ;
     RECT  4.572 71.995 4.59 72.031 ;
     RECT  214.2 71.803 214.794 72.031 ;
     RECT  215.784 71.995 216.63 72.031 ;
     RECT  214.2 72.031 216.63 72.059 ;
     RECT  214.2 72.059 216.162 72.149 ;
     RECT  214.2 72.149 216.054 72.185 ;
     RECT  7.128 71.959 17.658 72.221 ;
     RECT  4.572 72.031 4.734 72.265 ;
     RECT  5.472 71.491 6.21 72.265 ;
     RECT  214.308 72.185 216.054 72.419 ;
     RECT  214.308 72.419 215.91 72.455 ;
     RECT  4.572 72.265 6.21 72.535 ;
     RECT  7.128 72.221 17.514 72.689 ;
     RECT  215.748 72.455 215.91 72.689 ;
     RECT  4.14 72.535 6.21 72.701 ;
     RECT  215.748 72.689 215.766 72.725 ;
     RECT  4.932 72.701 6.21 72.841 ;
     RECT  2.415 71.885 2.697 72.859 ;
     RECT  4.932 72.841 6.354 72.959 ;
     RECT  2.304 72.859 2.697 72.995 ;
     RECT  212.616 68.683 213.297 73.003 ;
     RECT  7.272 72.689 17.514 73.075 ;
     RECT  18.54 71.837 21.042 73.075 ;
     RECT  212.616 73.003 213.39 73.075 ;
     RECT  214.308 72.455 214.938 73.075 ;
     RECT  2.415 72.995 2.697 73.201 ;
     RECT  3.96 73.111 3.978 73.201 ;
     RECT  2.415 73.201 3.978 73.229 ;
     RECT  7.272 73.075 21.042 73.229 ;
     RECT  218.844 73.099 218.862 73.229 ;
     RECT  212.616 73.075 214.938 73.309 ;
     RECT  212.4 73.309 214.938 73.373 ;
     RECT  2.415 73.229 3.258 73.409 ;
     RECT  4.932 72.959 5.634 73.535 ;
     RECT  7.272 73.229 17.514 73.651 ;
     RECT  2.415 73.409 3.186 73.769 ;
     RECT  0.108 67.973 0.126 73.777 ;
     RECT  0.108 73.777 0.162 74.155 ;
     RECT  7.2 73.651 17.514 74.191 ;
     RECT  7.2 74.191 17.622 74.309 ;
     RECT  0.108 74.155 0.558 74.417 ;
     RECT  6.372 74.281 6.39 74.461 ;
     RECT  7.2 74.309 17.514 74.461 ;
     RECT  5.148 73.535 5.634 74.489 ;
     RECT  0.108 74.417 0.126 74.525 ;
     RECT  3.96 74.191 3.978 74.551 ;
     RECT  2.415 73.769 2.697 74.587 ;
     RECT  3.78 74.551 3.978 74.623 ;
     RECT  217.152 74.551 217.17 74.695 ;
     RECT  3.78 74.623 4.41 74.717 ;
     RECT  5.328 74.489 5.634 74.731 ;
     RECT  6.372 74.461 17.514 74.731 ;
     RECT  217.152 74.695 217.674 74.731 ;
     RECT  3.78 74.717 3.798 74.759 ;
     RECT  212.4 73.373 214.902 74.821 ;
     RECT  217.152 74.731 217.818 74.849 ;
     RECT  219.42 74.395 219.438 74.849 ;
     RECT  1.728 74.587 2.697 74.861 ;
     RECT  217.296 74.849 217.818 74.885 ;
     RECT  212.4 74.821 215.118 74.929 ;
     RECT  18.615 73.229 21.042 75.001 ;
     RECT  22.896 69.331 204.894 75.001 ;
     RECT  18.324 75.001 21.042 75.119 ;
     RECT  0.54 75.157 0.558 75.197 ;
     RECT  18.324 75.119 20.826 75.199 ;
     RECT  5.328 74.731 17.514 75.235 ;
     RECT  18.288 75.199 20.826 75.235 ;
     RECT  22.896 75.001 204.966 75.271 ;
     RECT  211.752 74.929 215.118 75.271 ;
     RECT  5.328 75.235 20.826 75.389 ;
     RECT  22.896 75.271 205.11 75.389 ;
     RECT  6.408 75.389 20.826 75.425 ;
     RECT  211.752 75.271 215.442 75.425 ;
     RECT  211.932 75.425 215.442 75.469 ;
     RECT  5.328 75.389 5.634 75.505 ;
     RECT  210.492 75.163 210.51 75.631 ;
     RECT  217.548 74.885 217.674 75.631 ;
     RECT  22.896 75.389 204.966 75.659 ;
     RECT  211.932 75.469 216.162 75.731 ;
     RECT  217.548 75.631 217.818 75.731 ;
     RECT  219.42 75.691 219.438 75.731 ;
     RECT  212.688 75.731 216.162 75.767 ;
     RECT  206.352 75.643 206.37 75.773 ;
     RECT  210.204 75.631 210.51 75.773 ;
     RECT  217.548 75.731 217.674 75.775 ;
     RECT  211.932 75.731 211.95 75.803 ;
     RECT  212.832 75.767 216.162 75.803 ;
     RECT  5.148 75.505 5.634 75.811 ;
     RECT  217.224 75.775 217.674 75.811 ;
     RECT  212.832 75.803 215.658 75.929 ;
     RECT  216.828 75.811 217.674 75.929 ;
     RECT  216.828 75.929 217.566 75.965 ;
     RECT  212.832 75.929 215.334 76.037 ;
     RECT  2.415 74.861 2.697 76.171 ;
     RECT  216.972 75.965 217.566 76.199 ;
     RECT  216.972 76.199 217.35 76.235 ;
     RECT  2.304 76.171 2.697 76.351 ;
     RECT  6.408 75.425 17.55 76.351 ;
     RECT  4.968 75.811 5.634 76.363 ;
     RECT  6.408 76.351 17.622 76.363 ;
     RECT  4.536 76.363 17.622 76.397 ;
     RECT  4.536 76.397 4.554 76.441 ;
     RECT  4.248 76.441 4.554 76.469 ;
     RECT  2.304 76.351 3.402 76.505 ;
     RECT  2.415 76.505 3.402 76.585 ;
     RECT  4.248 76.469 4.266 76.585 ;
     RECT  213.015 76.037 215.334 76.775 ;
     RECT  0.108 75.496 0.126 76.795 ;
     RECT  0.108 76.795 0.162 76.847 ;
     RECT  216.972 76.235 217.206 76.855 ;
     RECT  5.616 76.397 17.622 76.891 ;
     RECT  18.615 75.425 20.826 76.891 ;
     RECT  216.792 76.855 217.206 76.891 ;
     RECT  2.415 76.585 4.266 76.919 ;
     RECT  5.616 76.891 20.826 76.981 ;
     RECT  213.015 76.775 214.686 77.009 ;
     RECT  210.492 75.773 210.51 77.017 ;
     RECT  218.88 76.981 218.898 77.021 ;
     RECT  210.492 77.017 210.762 77.045 ;
     RECT  211.68 76.891 211.698 77.045 ;
     RECT  216.072 76.891 217.206 77.045 ;
     RECT  210.744 77.045 210.762 77.053 ;
     RECT  5.616 76.981 21.366 77.161 ;
     RECT  213.015 77.009 214.362 77.161 ;
     RECT  5.184 77.161 21.366 77.279 ;
     RECT  216.54 77.045 216.702 77.279 ;
     RECT  0.108 76.847 0.126 77.315 ;
     RECT  3.96 76.919 4.266 77.315 ;
     RECT  216.54 77.279 216.558 77.315 ;
     RECT  212.364 77.161 214.362 77.351 ;
     RECT  212.364 77.351 214.146 77.423 ;
     RECT  2.415 76.919 2.697 77.467 ;
     RECT  210.744 77.053 211.302 77.501 ;
     RECT  5.616 77.279 21.366 77.549 ;
     RECT  212.364 77.423 214.038 77.549 ;
     RECT  2.34 77.467 2.697 77.701 ;
     RECT  2.34 77.701 3.186 77.803 ;
     RECT  2.304 77.803 3.186 78.125 ;
     RECT  2.415 78.125 3.186 78.133 ;
     RECT  3.96 77.315 3.978 78.133 ;
     RECT  2.415 78.133 3.978 78.241 ;
     RECT  2.415 78.241 4.014 78.359 ;
     RECT  218.844 78.235 218.862 78.359 ;
     RECT  217.476 78.331 217.494 78.431 ;
     RECT  212.364 77.549 213.894 78.475 ;
     RECT  2.415 78.359 3.222 78.629 ;
     RECT  212.364 78.475 214.542 78.629 ;
     RECT  5.616 77.549 16.038 78.637 ;
     RECT  5.58 78.637 16.038 78.781 ;
     RECT  5.508 78.781 16.038 78.899 ;
     RECT  212.364 78.629 214.362 78.899 ;
     RECT  5.58 78.899 16.038 78.971 ;
     RECT  5.58 78.971 11.97 79.043 ;
     RECT  212.364 78.899 214.11 79.169 ;
     RECT  212.364 79.169 214.002 79.205 ;
     RECT  219.42 79.531 219.438 79.709 ;
     RECT  4.572 78.992 4.59 79.753 ;
     RECT  217.8 79.681 217.818 79.781 ;
     RECT  212.364 79.205 213.75 79.819 ;
     RECT  5.58 79.043 6.03 79.825 ;
     RECT  4.212 79.753 4.59 79.861 ;
     RECT  212.076 79.819 213.75 79.951 ;
     RECT  5.472 79.825 6.03 79.979 ;
     RECT  212.076 79.951 214.254 80.095 ;
     RECT  6.876 79.043 11.97 80.131 ;
     RECT  210.888 77.501 211.302 80.131 ;
     RECT  212.076 80.095 214.902 80.131 ;
     RECT  0.108 78.475 0.126 80.141 ;
     RECT  5.616 79.979 6.03 80.159 ;
     RECT  3.888 79.861 4.59 80.249 ;
     RECT  210.888 80.131 214.902 80.249 ;
     RECT  2.415 78.629 2.697 80.257 ;
     RECT  3.888 80.249 3.978 80.257 ;
     RECT  1.728 80.257 3.978 80.381 ;
     RECT  210.888 80.249 211.626 80.381 ;
     RECT  1.728 80.381 2.697 80.477 ;
     RECT  212.364 80.249 214.902 80.563 ;
     RECT  216 79.717 216.018 80.563 ;
     RECT  212.364 80.563 214.938 80.599 ;
     RECT  216 80.563 216.162 80.599 ;
     RECT  4.716 80.401 4.878 80.663 ;
     RECT  212.364 80.599 216.162 80.671 ;
     RECT  217.26 80.635 217.278 80.671 ;
     RECT  16.848 77.549 21.366 80.761 ;
     RECT  217.224 80.671 217.278 80.761 ;
     RECT  5.688 80.159 6.03 80.789 ;
     RECT  212.364 80.671 216.342 80.825 ;
     RECT  212.364 80.825 216.162 80.861 ;
     RECT  219.42 80.824 219.438 80.861 ;
     RECT  217.116 80.761 217.278 80.905 ;
     RECT  6.84 80.131 11.97 80.941 ;
     RECT  217.116 80.905 217.53 80.941 ;
     RECT  4.716 80.663 4.734 80.957 ;
     RECT  216.936 80.941 217.53 81.059 ;
     RECT  216.936 81.059 217.386 81.095 ;
     RECT  212.364 80.861 214.902 81.167 ;
     RECT  12.744 78.971 16.038 81.239 ;
     RECT  16.848 80.761 21.402 81.301 ;
     RECT  217.08 81.095 217.386 81.329 ;
     RECT  217.08 81.329 217.242 81.365 ;
     RECT  3.888 80.381 3.978 81.445 ;
     RECT  5.796 80.789 6.03 81.445 ;
     RECT  6.804 80.941 11.97 81.445 ;
     RECT  2.304 80.477 2.697 81.481 ;
     RECT  3.492 81.445 3.978 81.481 ;
     RECT  2.304 81.481 3.978 81.595 ;
     RECT  2.304 81.595 4.374 81.635 ;
     RECT  217.116 81.365 217.17 81.635 ;
     RECT  217.116 81.635 217.134 81.707 ;
     RECT  214.848 81.167 214.902 81.751 ;
     RECT  5.796 81.445 11.97 81.985 ;
     RECT  5.688 81.985 11.97 82.021 ;
     RECT  212.364 81.167 214.002 82.021 ;
     RECT  5.364 82.021 11.97 82.123 ;
     RECT  218.88 82.111 218.898 82.157 ;
     RECT  214.848 81.751 215.226 82.291 ;
     RECT  216.828 82.255 216.846 82.291 ;
     RECT  212.364 82.021 214.038 82.409 ;
     RECT  214.848 82.291 215.334 82.409 ;
     RECT  216.144 82.291 216.846 82.409 ;
     RECT  214.884 82.409 215.334 82.445 ;
     RECT  2.415 81.635 3.906 82.525 ;
     RECT  4.644 82.123 11.97 82.525 ;
     RECT  216.144 82.409 216.738 82.525 ;
     RECT  212.364 82.409 214.002 82.637 ;
     RECT  215.712 82.525 216.738 82.679 ;
     RECT  215.712 82.679 215.73 82.715 ;
     RECT  216.612 82.679 216.63 82.715 ;
     RECT  2.415 82.525 11.97 82.949 ;
     RECT  2.415 82.949 4.338 83.083 ;
     RECT  5.364 82.949 11.97 83.191 ;
     RECT  12.78 81.239 16.038 83.191 ;
     RECT  2.304 83.083 4.338 83.327 ;
     RECT  214.884 82.445 214.902 83.335 ;
     RECT  5.364 83.191 16.038 83.363 ;
     RECT  212.364 82.637 213.75 83.371 ;
     RECT  214.884 83.335 215.118 83.371 ;
     RECT  219.42 83.419 219.438 83.489 ;
     RECT  217.8 83.191 217.818 83.525 ;
     RECT  212.364 83.371 215.118 83.605 ;
     RECT  5.364 83.363 11.97 83.731 ;
     RECT  212.364 83.605 215.19 83.759 ;
     RECT  212.364 83.759 215.046 83.795 ;
     RECT  212.364 83.795 214.254 84.029 ;
     RECT  0.108 81.115 0.126 84.091 ;
     RECT  0.108 84.091 0.558 84.173 ;
     RECT  22.896 75.659 204.894 84.181 ;
     RECT  16.848 81.301 21.51 84.307 ;
     RECT  212.364 84.029 213.534 84.343 ;
     RECT  2.415 83.327 4.338 84.451 ;
     RECT  5.22 83.731 11.97 84.451 ;
     RECT  22.896 84.181 205.038 84.451 ;
     RECT  22.896 84.451 205.47 84.677 ;
     RECT  205.452 84.677 205.47 84.721 ;
     RECT  210.888 80.381 211.302 84.811 ;
     RECT  212.184 84.343 213.534 84.811 ;
     RECT  205.452 84.721 205.578 84.839 ;
     RECT  218.844 84.715 218.862 84.839 ;
     RECT  2.415 84.451 11.97 84.875 ;
     RECT  205.452 84.839 205.47 84.875 ;
     RECT  217.152 84.811 217.17 84.911 ;
     RECT  210.888 84.811 213.534 84.955 ;
     RECT  210.888 84.955 213.894 85.109 ;
     RECT  5.364 84.875 11.97 85.217 ;
     RECT  210.888 85.109 213.642 85.649 ;
     RECT  16.848 84.307 21.942 85.765 ;
     RECT  217.296 85.765 217.314 85.801 ;
     RECT  217.296 85.801 217.458 85.891 ;
     RECT  216.072 85.927 216.09 85.999 ;
     RECT  212.184 85.649 213.642 86.161 ;
     RECT  215.28 86.071 215.298 86.161 ;
     RECT  216.072 85.999 216.378 86.161 ;
     RECT  219.42 86.011 219.438 86.189 ;
     RECT  215.28 86.161 216.378 86.225 ;
     RECT  217.296 85.891 217.818 86.225 ;
     RECT  215.28 86.225 216.162 86.233 ;
     RECT  22.896 84.677 204.606 86.297 ;
     RECT  217.296 86.225 217.566 86.305 ;
     RECT  217.116 86.305 217.566 86.341 ;
     RECT  212.184 86.161 214.218 86.431 ;
     RECT  215.172 86.233 216.162 86.459 ;
     RECT  216.936 86.341 217.566 86.459 ;
     RECT  216.936 86.459 217.53 86.495 ;
     RECT  216.072 86.459 216.126 86.567 ;
     RECT  216.072 86.567 216.09 86.603 ;
     RECT  217.368 86.495 217.53 86.729 ;
     RECT  217.368 86.729 217.386 86.765 ;
     RECT  212.184 86.431 214.434 86.881 ;
     RECT  215.172 86.459 215.298 86.881 ;
     RECT  2.415 84.875 4.446 86.971 ;
     RECT  0.108 84.173 0.126 87.019 ;
     RECT  2.415 86.971 4.518 87.035 ;
     RECT  0.108 87.019 0.162 87.107 ;
     RECT  9.504 85.217 11.97 87.277 ;
     RECT  219.42 87.259 219.438 87.305 ;
     RECT  9.504 87.277 12.042 87.377 ;
     RECT  212.184 86.881 215.298 87.421 ;
     RECT  216.396 87.385 216.414 87.421 ;
     RECT  212.184 87.421 216.414 87.647 ;
     RECT  215.64 87.647 216.414 87.655 ;
     RECT  2.415 87.035 4.446 87.691 ;
     RECT  215.64 87.655 216.45 87.809 ;
     RECT  2.304 87.691 4.446 87.845 ;
     RECT  215.64 87.809 216.27 87.845 ;
     RECT  214.884 87.647 214.902 87.881 ;
     RECT  2.415 87.845 4.446 88.123 ;
     RECT  5.364 85.217 8.73 88.123 ;
     RECT  212.184 87.647 214.038 88.501 ;
     RECT  212.184 88.501 214.182 88.619 ;
     RECT  218.844 88.555 218.862 88.619 ;
     RECT  16.848 85.765 22.014 88.627 ;
     RECT  2.415 88.123 8.73 88.655 ;
     RECT  217.224 88.501 217.242 88.655 ;
     RECT  22.896 86.297 204.282 88.771 ;
     RECT  22.896 88.771 204.966 88.889 ;
     RECT  210.888 85.649 211.302 88.897 ;
     RECT  212.184 88.619 214.11 88.897 ;
     RECT  210.888 88.897 214.11 89.159 ;
     RECT  22.896 88.889 204.93 89.429 ;
     RECT  210.888 89.159 214.074 89.429 ;
     RECT  22.896 89.429 204.822 89.465 ;
     RECT  210.888 89.429 213.858 89.465 ;
     RECT  22.896 89.465 204.534 89.843 ;
     RECT  2.415 88.655 4.158 89.851 ;
     RECT  16.848 88.627 22.05 89.851 ;
     RECT  22.896 89.843 203.922 89.851 ;
     RECT  5.148 88.655 8.73 89.941 ;
     RECT  9.504 87.377 11.97 89.941 ;
     RECT  219.42 89.851 219.438 89.969 ;
     RECT  5.148 89.941 11.97 90.041 ;
     RECT  210.888 89.465 213.642 90.211 ;
     RECT  216.504 90.013 216.522 90.239 ;
     RECT  215.748 90.211 215.766 90.311 ;
     RECT  210.888 90.211 214.074 90.605 ;
     RECT  5.292 90.041 11.97 90.779 ;
     RECT  212.184 90.605 214.074 90.823 ;
     RECT  2.415 89.851 4.194 90.895 ;
     RECT  212.184 90.823 214.398 90.931 ;
     RECT  2.415 90.895 4.374 90.941 ;
     RECT  212.184 90.931 214.902 91.057 ;
     RECT  215.856 90.931 215.874 91.057 ;
     RECT  5.364 90.779 11.97 91.165 ;
     RECT  12.78 83.363 16.038 91.165 ;
     RECT  2.415 90.941 4.194 91.229 ;
     RECT  219.42 91.147 219.438 91.319 ;
     RECT  217.8 91.291 217.818 91.391 ;
     RECT  16.848 89.851 203.922 91.435 ;
     RECT  209.664 91.021 209.682 91.435 ;
     RECT  212.184 91.057 215.874 91.471 ;
     RECT  217.332 91.435 217.458 91.471 ;
     RECT  209.664 91.435 209.754 91.499 ;
     RECT  5.364 91.165 16.038 91.561 ;
     RECT  212.184 91.471 216.162 91.561 ;
     RECT  217.152 91.471 217.458 91.561 ;
     RECT  16.848 91.435 203.958 91.589 ;
     RECT  212.184 91.561 217.458 91.625 ;
     RECT  216.324 91.625 217.458 91.661 ;
     RECT  5.148 91.561 16.038 91.733 ;
     RECT  217.26 91.661 217.458 91.859 ;
     RECT  217.26 91.859 217.422 92.129 ;
     RECT  217.26 92.129 217.278 92.165 ;
     RECT  2.415 91.229 4.158 92.281 ;
     RECT  2.415 92.281 4.626 92.299 ;
     RECT  2.304 92.299 4.626 92.399 ;
     RECT  2.304 92.399 4.482 92.435 ;
     RECT  218.88 92.437 218.898 92.477 ;
     RECT  212.184 91.625 215.55 92.515 ;
     RECT  2.415 92.435 4.482 92.573 ;
     RECT  210.888 90.605 211.302 92.641 ;
     RECT  212.184 92.515 215.694 92.641 ;
     RECT  210.888 92.641 215.694 92.669 ;
     RECT  210.888 92.669 215.586 92.861 ;
     RECT  212.184 92.861 215.586 93.011 ;
     RECT  214.38 93.011 215.586 93.209 ;
     RECT  0.108 87.107 0.126 93.217 ;
     RECT  5.364 91.733 16.038 93.245 ;
     RECT  214.38 93.209 215.442 93.281 ;
     RECT  0.108 93.217 0.162 93.341 ;
     RECT  214.452 93.281 215.298 93.479 ;
     RECT  214.452 93.479 215.19 93.515 ;
     RECT  219.42 93.739 219.438 93.785 ;
     RECT  212.184 93.011 213.642 93.901 ;
     RECT  2.415 92.573 4.158 93.979 ;
     RECT  212.184 93.901 213.714 94.055 ;
     RECT  214.452 93.515 215.118 94.091 ;
     RECT  214.884 94.091 215.118 94.289 ;
     RECT  214.884 94.289 214.902 94.325 ;
     RECT  2.304 93.979 4.158 94.603 ;
     RECT  210.888 92.861 211.302 94.651 ;
     RECT  212.184 94.055 213.426 94.651 ;
     RECT  1.728 94.603 4.158 94.685 ;
     RECT  9.504 93.245 16.038 94.901 ;
     RECT  2.415 94.685 4.158 94.981 ;
     RECT  5.364 93.245 8.73 95.071 ;
     RECT  2.415 94.981 4.41 95.099 ;
     RECT  219.42 95.035 219.438 95.099 ;
     RECT  2.415 95.099 4.266 95.135 ;
     RECT  5.184 95.071 8.73 95.165 ;
     RECT  217.8 95.071 217.818 95.171 ;
     RECT  210.888 94.651 213.426 95.215 ;
     RECT  210.888 95.215 213.57 95.251 ;
     RECT  214.56 95.071 214.578 95.251 ;
     RECT  208.944 95.323 208.962 95.341 ;
     RECT  216.072 95.215 216.09 95.341 ;
     RECT  208.944 95.341 209.286 95.369 ;
     RECT  210.888 95.251 214.578 95.369 ;
     RECT  209.268 95.369 209.286 95.405 ;
     RECT  214.56 95.369 214.578 95.405 ;
     RECT  215.856 95.341 216.09 95.441 ;
     RECT  5.364 95.165 8.73 95.639 ;
     RECT  210.888 95.369 213.822 95.747 ;
     RECT  212.04 95.747 213.822 96.053 ;
     RECT  2.415 95.135 4.158 96.061 ;
     RECT  215.316 95.989 215.334 96.061 ;
     RECT  2.415 96.061 4.266 96.179 ;
     RECT  216.288 96.061 216.306 96.179 ;
     RECT  212.184 96.053 213.822 96.187 ;
     RECT  215.172 96.061 215.334 96.187 ;
     RECT  214.812 96.187 215.334 96.295 ;
     RECT  212.184 96.187 213.858 96.331 ;
     RECT  214.812 96.295 216.018 96.331 ;
     RECT  219.456 96.151 219.474 96.365 ;
     RECT  217.836 96.295 217.854 96.449 ;
     RECT  217.692 96.565 217.71 96.601 ;
     RECT  5.472 95.639 8.73 96.629 ;
     RECT  216.756 96.601 217.71 96.719 ;
     RECT  212.184 96.331 216.018 96.755 ;
     RECT  216.756 96.719 217.602 96.791 ;
     RECT  217.368 96.791 217.602 97.025 ;
     RECT  212.184 96.755 214.902 97.259 ;
     RECT  2.415 96.179 4.158 97.375 ;
     RECT  5.472 96.629 8.55 97.411 ;
     RECT  9.54 94.901 16.038 97.411 ;
     RECT  16.848 91.589 203.922 97.411 ;
     RECT  2.415 97.375 4.374 97.435 ;
     RECT  214.812 97.259 214.902 97.565 ;
     RECT  217.8 97.501 217.818 97.601 ;
     RECT  218.88 97.573 218.898 97.613 ;
     RECT  212.184 97.259 214.038 97.661 ;
     RECT  214.884 97.565 214.902 97.681 ;
     RECT  216.036 97.645 216.054 97.681 ;
     RECT  212.184 97.661 213.93 97.709 ;
     RECT  2.415 97.435 4.59 97.915 ;
     RECT  5.364 97.411 8.55 97.915 ;
     RECT  214.884 97.681 216.054 97.915 ;
     RECT  214.884 97.915 216.09 98.069 ;
     RECT  214.884 98.069 216.054 98.105 ;
     RECT  2.415 97.915 8.55 98.311 ;
     RECT  215.928 98.105 216.054 98.339 ;
     RECT  215.928 98.339 215.946 98.375 ;
     RECT  2.415 98.311 8.658 98.381 ;
     RECT  9.54 97.411 203.922 98.411 ;
     RECT  15.66 98.411 203.922 98.447 ;
     RECT  17.352 98.447 203.922 98.55 ;
     RECT  212.184 97.709 213.642 98.581 ;
     RECT  9.54 98.411 14.922 98.645 ;
     RECT  214.884 98.105 214.902 98.725 ;
     RECT  197.244 98.55 203.922 98.879 ;
     RECT  219.42 98.875 219.438 98.915 ;
     RECT  217.584 98.851 217.602 98.951 ;
     RECT  212.184 98.581 213.75 98.959 ;
     RECT  212.04 98.959 213.75 98.995 ;
     RECT  214.524 98.725 214.902 98.995 ;
     RECT  212.04 98.995 214.902 99.031 ;
     RECT  85.824 98.55 86.634 99.104 ;
     RECT  86.616 99.104 86.634 99.149 ;
     RECT  142.524 98.55 142.542 99.149 ;
     RECT  197.496 98.879 203.922 99.149 ;
     RECT  67.356 98.55 67.374 99.391 ;
     RECT  207.615 42.827 207.897 99.391 ;
     RECT  210.888 95.747 211.302 99.391 ;
     RECT  212.04 99.031 215.478 99.391 ;
     RECT  207.504 99.391 207.897 99.437 ;
     RECT  67.356 99.391 67.626 99.463 ;
     RECT  67.284 99.463 67.626 99.499 ;
     RECT  64.872 98.55 65.574 99.661 ;
     RECT  210.888 99.391 215.478 99.689 ;
     RECT  74.916 98.55 75.474 99.697 ;
     RECT  64.872 99.661 66.258 99.725 ;
     RECT  210.888 99.689 214.578 99.725 ;
     RECT  197.496 99.149 203.31 99.761 ;
     RECT  74.736 99.697 75.474 99.841 ;
     RECT  85.824 99.104 85.842 99.886 ;
     RECT  119.088 98.55 119.106 99.886 ;
     RECT  144.792 98.55 144.846 99.959 ;
     RECT  2.415 98.381 8.55 99.967 ;
     RECT  9.54 98.645 11.97 99.967 ;
     RECT  105.372 99.499 105.39 99.967 ;
     RECT  79.812 99.967 79.83 99.979 ;
     RECT  66.24 99.725 66.258 100.003 ;
     RECT  2.415 99.967 11.97 100.013 ;
     RECT  67.284 99.499 68.562 100.039 ;
     RECT  69.3 99.571 69.318 100.039 ;
     RECT  60.876 100.039 60.894 100.075 ;
     RECT  67.284 100.039 69.318 100.075 ;
     RECT  70.236 98.55 70.254 100.075 ;
     RECT  54.864 99.403 54.882 100.111 ;
     RECT  71.856 99.535 72.126 100.111 ;
     RECT  62.136 100.003 62.154 100.123 ;
     RECT  49.428 98.55 49.446 100.156 ;
     RECT  50.184 99.733 50.202 100.171 ;
     RECT  72.936 100.156 72.954 100.201 ;
     RECT  74.736 99.841 75.762 100.201 ;
     RECT  2.415 100.013 8.622 100.219 ;
     RECT  98.46 99.697 98.478 100.219 ;
     RECT  2.304 100.219 8.622 100.229 ;
     RECT  218.268 100.171 218.286 100.229 ;
     RECT  9.396 100.013 11.97 100.237 ;
     RECT  12.996 98.645 14.922 100.237 ;
     RECT  74.592 100.201 75.762 100.237 ;
     RECT  216.684 99.841 216.702 100.265 ;
     RECT  37.044 99.805 37.062 100.267 ;
     RECT  79.776 99.979 79.83 100.273 ;
     RECT  37.008 100.267 37.062 100.315 ;
     RECT  38.412 100.219 38.43 100.315 ;
     RECT  71.352 100.111 72.126 100.315 ;
     RECT  72.936 100.201 73.494 100.315 ;
     RECT  102.348 99.931 102.366 100.315 ;
     RECT  62.136 100.123 62.406 100.345 ;
     RECT  34.92 100.315 34.938 100.363 ;
     RECT  96.12 98.55 96.138 100.363 ;
     RECT  35.784 100.345 35.802 100.381 ;
     RECT  119.088 99.886 119.178 100.381 ;
     RECT  110.484 99.733 110.502 100.411 ;
     RECT  144.828 99.959 144.846 100.411 ;
     RECT  28.44 99.391 28.458 100.426 ;
     RECT  110.484 100.411 111.006 100.426 ;
     RECT  37.008 100.315 38.43 100.445 ;
     RECT  94.716 100.363 94.734 100.459 ;
     RECT  97.416 99.661 97.434 100.459 ;
     RECT  98.46 100.219 98.622 100.459 ;
     RECT  28.44 100.426 29.142 100.471 ;
     RECT  34.416 100.363 34.938 100.471 ;
     RECT  35.784 100.381 35.91 100.471 ;
     RECT  118.836 100.381 119.178 100.471 ;
     RECT  94.572 100.459 94.734 100.493 ;
     RECT  136.224 99.301 136.242 100.499 ;
     RECT  66.24 100.003 66.51 100.507 ;
     RECT  67.284 100.075 70.254 100.507 ;
     RECT  142.524 100.411 142.542 100.507 ;
     RECT  2.304 100.229 4.482 100.535 ;
     RECT  142.524 100.507 142.65 100.541 ;
     RECT  144.828 100.411 145.35 100.541 ;
     RECT  50.184 100.171 50.454 100.543 ;
     RECT  79.776 100.273 79.866 100.543 ;
     RECT  110.34 100.426 111.006 100.543 ;
     RECT  58.716 100.543 58.734 100.555 ;
     RECT  79.776 100.543 79.902 100.555 ;
     RECT  104.76 99.967 105.39 100.555 ;
     RECT  118.368 100.471 119.178 100.555 ;
     RECT  66.24 100.507 70.254 100.571 ;
     RECT  43.596 100.555 43.614 100.603 ;
     RECT  50.184 100.543 50.526 100.603 ;
     RECT  138.636 100.363 138.654 100.603 ;
     RECT  142.632 100.541 142.65 100.603 ;
     RECT  210.888 99.725 213.858 100.603 ;
     RECT  210.888 100.603 213.966 100.607 ;
     RECT  85.5 99.886 85.842 100.615 ;
     RECT  87.624 100.027 87.642 100.615 ;
     RECT  134.532 100.363 134.55 100.637 ;
     RECT  138.528 100.603 138.654 100.637 ;
     RECT  142.632 100.603 142.938 100.637 ;
     RECT  196.092 99.841 196.11 100.643 ;
     RECT  79.776 100.555 80.118 100.651 ;
     RECT  87.624 100.615 87.894 100.651 ;
     RECT  99.72 100.459 99.738 100.651 ;
     RECT  28.44 100.471 29.538 100.693 ;
     RECT  45.972 100.603 45.99 100.693 ;
     RECT  50.184 100.603 50.706 100.693 ;
     RECT  78.732 100.273 78.75 100.693 ;
     RECT  82.584 98.55 83.466 100.693 ;
     RECT  87.624 100.651 88.614 100.693 ;
     RECT  89.712 100.027 89.73 100.693 ;
     RECT  94.572 100.493 94.662 100.693 ;
     RECT  99.54 100.651 99.738 100.693 ;
     RECT  142.815 100.637 142.938 100.693 ;
     RECT  186.84 100.555 186.858 100.693 ;
     RECT  197.496 99.761 203.094 100.693 ;
     RECT  39.6 99.427 39.618 100.699 ;
     RECT  40.407 100.693 40.497 100.699 ;
     RECT  50.184 100.693 51.297 100.699 ;
     RECT  56.607 100.693 56.697 100.699 ;
     RECT  61.956 100.345 62.406 100.699 ;
     RECT  78.207 100.693 78.75 100.699 ;
     RECT  82.584 100.693 83.697 100.699 ;
     RECT  91.332 98.55 91.35 100.699 ;
     RECT  97.416 100.459 98.622 100.699 ;
     RECT  99.54 100.693 99.897 100.699 ;
     RECT  102.096 100.315 102.366 100.699 ;
     RECT  104.508 100.555 105.39 100.699 ;
     RECT  43.596 100.603 43.722 100.733 ;
     RECT  45.807 100.693 45.99 100.733 ;
     RECT  58.716 100.555 58.77 100.733 ;
     RECT  114.588 100.555 114.606 100.733 ;
     RECT  34.416 100.471 35.91 100.741 ;
     RECT  37.008 100.445 37.638 100.741 ;
     RECT  52.56 99.697 52.578 100.741 ;
     RECT  78.12 100.699 78.75 100.741 ;
     RECT  97.416 100.699 98.658 100.741 ;
     RECT  99.54 100.699 99.99 100.741 ;
     RECT  104.508 100.699 105.426 100.741 ;
     RECT  136.692 100.603 136.71 100.741 ;
     RECT  137.607 100.693 137.697 100.741 ;
     RECT  112.968 98.55 112.986 100.747 ;
     RECT  28.44 100.693 29.697 100.769 ;
     RECT  36.864 100.741 37.638 100.769 ;
     RECT  38.412 100.445 38.43 100.769 ;
     RECT  39.6 100.699 40.59 100.769 ;
     RECT  43.596 100.733 43.614 100.769 ;
     RECT  49.176 100.156 49.446 100.769 ;
     RECT  50.184 100.699 51.39 100.769 ;
     RECT  54.612 100.111 54.882 100.769 ;
     RECT  56.52 100.699 56.79 100.769 ;
     RECT  60.192 100.075 60.894 100.769 ;
     RECT  64.872 99.725 65.142 100.769 ;
     RECT  68.544 100.571 70.254 100.769 ;
     RECT  76.788 99.571 76.806 100.769 ;
     RECT  81.216 100.651 81.234 100.769 ;
     RECT  82.584 100.699 83.79 100.769 ;
     RECT  87.624 100.693 89.73 100.769 ;
     RECT  91.188 100.699 91.35 100.769 ;
     RECT  92.088 99.616 92.322 100.769 ;
     RECT  95.868 100.363 96.138 100.769 ;
     RECT  110.34 100.543 111.258 100.769 ;
     RECT  112.392 100.747 112.986 100.769 ;
     RECT  118.116 100.555 119.178 100.769 ;
     RECT  120.276 100.579 120.294 100.769 ;
     RECT  133.056 100.507 133.074 100.769 ;
     RECT  136.692 100.741 137.697 100.769 ;
     RECT  154.62 100.471 154.638 100.769 ;
     RECT  186.207 100.693 186.858 100.769 ;
     RECT  210.888 100.607 211.194 100.769 ;
     RECT  5.364 100.229 8.622 100.777 ;
     RECT  9.396 100.237 14.922 100.777 ;
     RECT  77.616 100.741 78.75 100.777 ;
     RECT  82.584 100.769 83.697 100.777 ;
     RECT  91.188 100.769 91.206 100.777 ;
     RECT  197.007 100.693 203.094 100.777 ;
     RECT  137.016 100.769 137.697 100.781 ;
     RECT  132.207 100.693 132.297 100.795 ;
     RECT  185.364 99.931 185.382 100.795 ;
     RECT  49.176 100.769 49.194 100.805 ;
     RECT  50.184 100.769 51.297 100.805 ;
     RECT  52.56 100.741 52.83 100.805 ;
     RECT  54.612 100.769 54.63 100.805 ;
     RECT  60.192 100.769 60.462 100.805 ;
     RECT  64.872 100.769 64.89 100.805 ;
     RECT  66.24 100.571 67.626 100.805 ;
     RECT  71.352 100.315 73.494 100.805 ;
     RECT  85.248 100.615 85.842 100.805 ;
     RECT  87.624 100.769 89.19 100.805 ;
     RECT  92.088 100.769 92.106 100.805 ;
     RECT  95.868 100.769 95.886 100.805 ;
     RECT  97.416 100.741 99.99 100.805 ;
     RECT  102.096 100.699 102.618 100.805 ;
     RECT  110.34 100.769 111.006 100.805 ;
     RECT  118.116 100.769 118.854 100.805 ;
     RECT  77.292 100.777 78.75 100.829 ;
     RECT  88.344 100.805 89.19 100.829 ;
     RECT  91.08 100.777 91.206 100.829 ;
     RECT  26.784 100.741 26.802 100.841 ;
     RECT  58.716 100.733 58.734 100.841 ;
     RECT  85.644 100.805 85.842 100.841 ;
     RECT  94.407 100.693 94.662 100.841 ;
     RECT  102.168 100.805 102.618 100.841 ;
     RECT  132.207 100.795 132.822 100.841 ;
     RECT  185.292 100.795 185.382 100.841 ;
     RECT  34.164 100.741 35.91 100.843 ;
     RECT  36.864 100.769 37.134 100.843 ;
     RECT  144.828 100.541 145.242 100.843 ;
     RECT  17.352 98.55 23.238 100.849 ;
     RECT  30.888 100.699 30.906 100.849 ;
     RECT  34.092 100.843 35.91 100.849 ;
     RECT  153.807 100.693 153.897 100.849 ;
     RECT  34.092 100.849 36.054 100.877 ;
     RECT  60.444 100.805 60.462 100.877 ;
     RECT  98.64 100.805 99.99 100.877 ;
     RECT  104.508 100.741 105.642 100.877 ;
     RECT  34.092 100.877 35.097 100.883 ;
     RECT  36.792 100.843 37.134 100.883 ;
     RECT  144.792 100.843 145.242 100.883 ;
     RECT  30.888 100.849 31.302 100.885 ;
     RECT  72.324 100.805 73.494 100.885 ;
     RECT  74.592 100.237 75.798 100.885 ;
     RECT  110.34 100.805 110.79 100.885 ;
     RECT  110.304 100.885 110.79 100.891 ;
     RECT  72.324 100.885 75.798 100.921 ;
     RECT  106.596 100.555 106.614 100.921 ;
     RECT  211.932 100.607 213.966 100.921 ;
     RECT  97.164 100.849 97.182 100.925 ;
     RECT  17.352 100.849 23.382 100.963 ;
     RECT  24.207 100.693 24.297 100.963 ;
     RECT  45.807 100.733 45.897 100.963 ;
     RECT  56.52 100.769 56.697 100.963 ;
     RECT  61.956 100.699 62.73 100.963 ;
     RECT  94.407 100.841 94.497 100.963 ;
     RECT  116.007 100.693 116.097 100.963 ;
     RECT  121.407 100.693 121.497 100.963 ;
     RECT  126.807 100.693 126.897 100.963 ;
     RECT  132.207 100.841 132.297 100.963 ;
     RECT  148.407 100.693 148.497 100.963 ;
     RECT  153.807 100.849 154.314 100.963 ;
     RECT  159.207 100.693 159.297 100.963 ;
     RECT  164.607 100.693 164.697 100.963 ;
     RECT  170.007 100.693 170.097 100.963 ;
     RECT  175.407 100.693 175.497 100.963 ;
     RECT  180.807 100.693 180.897 100.963 ;
     RECT  185.364 100.841 185.382 100.963 ;
     RECT  186.207 100.769 186.297 100.963 ;
     RECT  191.607 100.693 191.697 100.963 ;
     RECT  106.596 100.921 106.722 101.035 ;
     RECT  34.164 100.883 35.097 101.039 ;
     RECT  35.892 100.877 36.054 101.039 ;
     RECT  138.528 100.637 138.546 101.069 ;
     RECT  36.864 100.883 37.134 101.075 ;
     RECT  39.6 100.769 40.497 101.075 ;
     RECT  88.344 100.829 89.097 101.075 ;
     RECT  78.015 100.829 78.75 101.083 ;
     RECT  110.016 100.891 110.79 101.083 ;
     RECT  215.46 99.689 215.478 101.083 ;
     RECT  79.776 100.651 80.334 101.111 ;
     RECT  185.364 100.963 186.297 101.111 ;
     RECT  86.652 100.699 86.67 101.119 ;
     RECT  102.6 100.841 102.618 101.131 ;
     RECT  79.848 101.111 80.334 101.147 ;
     RECT  85.932 101.119 86.67 101.147 ;
     RECT  88.776 101.075 89.097 101.147 ;
     RECT  98.676 100.877 99.897 101.147 ;
     RECT  211.932 100.921 214.29 101.155 ;
     RECT  215.028 101.083 215.478 101.155 ;
     RECT  85.932 101.147 85.95 101.165 ;
     RECT  102.6 101.131 102.726 101.165 ;
     RECT  106.596 101.035 107.442 101.165 ;
     RECT  37.044 101.075 37.134 101.183 ;
     RECT  123.12 100.849 123.138 101.183 ;
     RECT  43.272 100.849 43.29 101.191 ;
     RECT  45.615 100.963 45.897 101.191 ;
     RECT  78.015 101.083 78.894 101.191 ;
     RECT  104.508 100.877 105.297 101.191 ;
     RECT  211.932 101.155 215.478 101.191 ;
     RECT  109.548 101.083 110.79 101.213 ;
     RECT  39.852 101.075 40.497 101.219 ;
     RECT  84.816 101.131 84.834 101.219 ;
     RECT  153.615 100.963 154.314 101.219 ;
     RECT  211.932 101.191 216.198 101.219 ;
     RECT  37.116 101.183 37.134 101.309 ;
     RECT  66.708 100.805 67.626 101.309 ;
     RECT  68.544 100.769 69.318 101.309 ;
     RECT  79.92 101.147 80.334 101.309 ;
     RECT  72.324 100.921 75.834 101.317 ;
     RECT  0.108 93.341 0.126 101.345 ;
     RECT  102.708 101.165 102.726 101.357 ;
     RECT  104.292 101.191 105.297 101.357 ;
     RECT  70.416 101.083 71.298 101.381 ;
     RECT  17.352 100.963 24.297 101.389 ;
     RECT  5.364 100.777 14.922 101.417 ;
     RECT  39.924 101.219 40.497 101.417 ;
     RECT  66.744 101.309 67.554 101.417 ;
     RECT  217.296 101.389 217.314 101.425 ;
     RECT  26.964 101.281 27.306 101.461 ;
     RECT  213.015 101.219 216.198 101.461 ;
     RECT  106.596 101.165 107.334 101.549 ;
     RECT  56.415 100.963 56.697 101.551 ;
     RECT  78.015 101.191 78.966 101.551 ;
     RECT  217.26 101.425 217.314 101.551 ;
     RECT  72.324 101.317 76.266 101.579 ;
     RECT  79.992 101.309 80.334 101.579 ;
     RECT  82.332 100.777 83.697 101.579 ;
     RECT  219.42 101.467 219.438 101.579 ;
     RECT  80.316 101.579 80.334 101.597 ;
     RECT  26.964 101.461 27.594 101.615 ;
     RECT  70.632 101.381 71.298 101.623 ;
     RECT  217.26 101.551 217.818 101.651 ;
     RECT  26.964 101.615 27.522 101.687 ;
     RECT  77.904 101.551 78.966 101.687 ;
     RECT  83.088 101.579 83.697 101.687 ;
     RECT  106.596 101.549 106.794 101.687 ;
     RECT  42.804 101.191 43.29 101.693 ;
     RECT  70.632 101.623 71.514 101.695 ;
     RECT  72.324 101.579 75.834 101.695 ;
     RECT  76.824 101.659 76.878 101.707 ;
     RECT  213.015 101.461 216.378 101.723 ;
     RECT  61.815 100.963 62.73 101.731 ;
     RECT  217.26 101.651 217.458 101.731 ;
     RECT  17.352 101.389 24.534 101.759 ;
     RECT  26.964 101.687 27.45 101.759 ;
     RECT  70.632 101.695 75.834 101.759 ;
     RECT  83.16 101.687 83.697 101.759 ;
     RECT  213.015 101.723 215.982 101.759 ;
     RECT  68.544 101.309 68.598 101.849 ;
     RECT  70.632 101.759 73.602 101.849 ;
     RECT  77.904 101.687 78.822 101.849 ;
     RECT  83.232 101.759 83.697 101.849 ;
     RECT  215.46 101.759 215.982 101.849 ;
     RECT  145.296 101.323 145.314 101.851 ;
     RECT  26.964 101.759 27.378 101.885 ;
     RECT  61.815 101.731 62.874 101.885 ;
     RECT  145.296 101.851 145.35 101.885 ;
     RECT  216.936 101.731 217.458 101.885 ;
     RECT  52.812 100.805 52.83 101.933 ;
     RECT  61.815 101.885 62.802 101.957 ;
     RECT  70.632 101.849 73.458 101.957 ;
     RECT  106.596 101.687 106.722 101.957 ;
     RECT  74.52 101.759 75.834 101.993 ;
     RECT  26.964 101.885 26.982 102.029 ;
     RECT  30.78 100.885 31.302 102.029 ;
     RECT  42.768 101.899 42.786 102.029 ;
     RECT  71.1 101.957 73.458 102.029 ;
     RECT  77.904 101.849 78.642 102.029 ;
     RECT  106.596 101.957 106.614 102.029 ;
     RECT  112.392 100.769 112.806 102.029 ;
     RECT  2.415 100.535 4.482 102.091 ;
     RECT  88.815 101.147 89.097 102.091 ;
     RECT  107.712 102.043 107.73 102.091 ;
     RECT  107.712 102.091 108.018 102.119 ;
     RECT  109.548 101.213 110.697 102.119 ;
     RECT  34.704 101.039 35.097 102.125 ;
     RECT  56.304 101.551 56.697 102.128 ;
     RECT  77.904 102.029 78.297 102.128 ;
     RECT  88.704 102.091 89.097 102.128 ;
     RECT  113.112 102.091 113.418 102.128 ;
     RECT  217.008 101.885 217.458 102.155 ;
     RECT  108 102.119 108.018 102.173 ;
     RECT  113.112 102.128 113.13 102.173 ;
     RECT  188.064 100.747 188.082 102.191 ;
     RECT  66.816 101.417 67.554 102.199 ;
     RECT  76.824 101.707 76.95 102.226 ;
     RECT  196.344 100.777 203.094 102.227 ;
     RECT  66.708 102.199 67.554 102.235 ;
     RECT  109.548 102.119 109.638 102.263 ;
     RECT  74.52 101.993 74.682 102.269 ;
     RECT  2.415 102.091 4.518 102.271 ;
     RECT  5.364 101.417 13.662 102.271 ;
     RECT  72.324 102.029 73.458 102.299 ;
     RECT  76.824 102.226 76.986 102.361 ;
     RECT  71.1 102.029 71.514 102.389 ;
     RECT  74.664 102.269 74.682 102.389 ;
     RECT  186.015 101.111 186.297 102.397 ;
     RECT  217.188 102.155 217.458 102.425 ;
     RECT  68.976 102.127 68.994 102.461 ;
     RECT  71.172 102.389 71.514 102.461 ;
     RECT  76.824 102.361 77.058 102.461 ;
     RECT  109.62 102.263 109.638 102.461 ;
     RECT  66.708 102.235 67.95 102.497 ;
     RECT  75.816 101.993 75.834 102.533 ;
     RECT  76.824 102.461 76.95 102.541 ;
     RECT  17.352 101.759 24.318 102.631 ;
     RECT  196.344 102.227 202.497 102.659 ;
     RECT  17.352 102.631 24.57 102.701 ;
     RECT  44.892 101.191 45.897 102.701 ;
     RECT  215.46 101.849 215.478 102.739 ;
     RECT  2.415 102.271 13.662 102.763 ;
     RECT  145.332 101.885 145.35 102.767 ;
     RECT  215.46 102.739 215.514 102.775 ;
     RECT  75.852 102.541 76.95 102.797 ;
     RECT  14.76 101.417 14.922 102.811 ;
     RECT  213.015 101.759 214.578 102.811 ;
     RECT  215.46 102.775 216.054 102.811 ;
     RECT  113.976 102.379 113.994 102.839 ;
     RECT  71.46 102.461 71.514 102.901 ;
     RECT  72.324 102.299 72.897 102.901 ;
     RECT  76.932 102.797 76.95 102.929 ;
     RECT  213.015 102.811 216.054 102.929 ;
     RECT  219.42 102.763 219.438 102.929 ;
     RECT  70.236 102.811 70.326 102.937 ;
     RECT  142.815 100.693 143.097 102.937 ;
     RECT  17.352 102.701 24.39 102.941 ;
     RECT  98.028 102.901 98.046 102.941 ;
     RECT  31.284 102.029 31.302 102.965 ;
     RECT  213.015 102.929 215.658 102.965 ;
     RECT  217.8 102.811 217.818 102.965 ;
     RECT  69.66 102.937 70.326 103.001 ;
     RECT  97.164 102.955 97.182 103.001 ;
     RECT  2.415 102.763 13.77 103.037 ;
     RECT  69.66 103.001 70.11 103.037 ;
     RECT  194.364 102.907 194.382 103.037 ;
     RECT  71.46 102.901 72.897 103.109 ;
     RECT  73.728 103.009 73.746 103.171 ;
     RECT  78.015 102.128 78.297 103.171 ;
     RECT  99.252 101.147 99.897 103.171 ;
     RECT  211.932 101.219 212.202 103.171 ;
     RECT  213.015 102.965 214.362 103.171 ;
     RECT  3.492 103.037 13.77 103.181 ;
     RECT  215.1 102.965 215.658 103.199 ;
     RECT  73.656 103.171 73.746 103.207 ;
     RECT  14.724 102.811 14.922 103.235 ;
     RECT  215.1 103.199 215.514 103.235 ;
     RECT  68.904 103.171 68.922 103.243 ;
     RECT  103.176 103.171 103.194 103.243 ;
     RECT  37.044 103.081 37.062 103.271 ;
     RECT  68.904 103.243 68.994 103.279 ;
     RECT  198.108 102.659 202.497 103.307 ;
     RECT  71.46 103.109 71.478 103.315 ;
     RECT  103.104 103.243 103.23 103.315 ;
     RECT  75.852 102.797 75.87 103.343 ;
     RECT  14.904 103.235 14.922 103.351 ;
     RECT  15.66 98.447 16.362 103.351 ;
     RECT  4.572 103.181 13.77 103.379 ;
     RECT  14.904 103.351 16.362 103.379 ;
     RECT  198.108 103.307 201.15 103.379 ;
     RECT  68.724 103.279 68.994 103.469 ;
     RECT  98.604 103.171 99.897 103.469 ;
     RECT  215.1 103.235 215.406 103.469 ;
     RECT  215.1 103.469 215.298 103.505 ;
     RECT  66.708 102.497 67.497 103.517 ;
     RECT  98.64 103.469 99.897 103.541 ;
     RECT  102.78 103.315 103.23 103.541 ;
     RECT  2.415 103.037 2.697 103.579 ;
     RECT  73.656 103.207 74.142 103.585 ;
     RECT  74.916 103.279 75.006 103.585 ;
     RECT  75.78 103.351 75.798 103.585 ;
     RECT  60.444 103.003 60.462 103.613 ;
     RECT  142.815 102.937 143.658 103.613 ;
     RECT  78.015 103.171 78.642 103.711 ;
     RECT  88.815 102.128 89.097 103.711 ;
     RECT  121.215 100.963 121.497 103.711 ;
     RECT  132.015 100.963 132.297 103.711 ;
     RECT  153.615 101.219 153.897 103.711 ;
     RECT  164.415 100.963 164.697 103.711 ;
     RECT  211.932 103.171 214.362 103.711 ;
     RECT  215.1 103.505 215.19 103.711 ;
     RECT  77.904 103.711 78.642 103.723 ;
     RECT  94.215 100.963 94.497 103.723 ;
     RECT  153.504 103.711 153.897 103.723 ;
     RECT  169.815 100.963 170.097 103.723 ;
     RECT  69.912 103.037 70.11 103.739 ;
     RECT  73.656 103.585 75.798 103.739 ;
     RECT  71.028 103.315 71.478 103.747 ;
     RECT  77.904 103.723 78.678 103.757 ;
     RECT  88.704 103.711 89.097 103.757 ;
     RECT  121.104 103.711 121.497 103.757 ;
     RECT  131.904 103.711 132.297 103.757 ;
     RECT  153.504 103.723 154.494 103.757 ;
     RECT  164.304 103.711 164.697 103.757 ;
     RECT  2.304 103.579 2.697 103.775 ;
     RECT  14.976 103.379 16.362 103.775 ;
     RECT  36.036 101.039 36.054 103.775 ;
     RECT  75.78 103.739 75.798 103.775 ;
     RECT  73.656 103.739 74.97 103.783 ;
     RECT  102.78 103.541 103.05 103.811 ;
     RECT  210.888 100.769 210.906 103.811 ;
     RECT  78.015 103.757 78.678 103.853 ;
     RECT  90.648 103.723 90.666 103.853 ;
     RECT  94.215 103.723 94.662 103.853 ;
     RECT  106.596 103.723 106.614 103.853 ;
     RECT  122.544 103.723 122.562 103.853 ;
     RECT  138.528 103.723 138.546 103.853 ;
     RECT  153.615 103.757 154.494 103.853 ;
     RECT  169.815 103.723 170.442 103.853 ;
     RECT  182.412 103.723 182.43 103.853 ;
     RECT  196.344 102.659 197.097 103.855 ;
     RECT  15.66 103.775 16.362 103.883 ;
     RECT  186.015 102.397 186.678 103.883 ;
     RECT  198.108 103.379 200.034 103.883 ;
     RECT  211.932 103.711 215.19 103.901 ;
     RECT  196.308 103.855 197.097 103.963 ;
     RECT  3.492 103.181 3.51 104.009 ;
     RECT  73.62 103.783 74.97 104.009 ;
     RECT  196.308 103.963 197.658 104.009 ;
     RECT  212.94 103.901 215.19 104.045 ;
     RECT  217.8 103.711 217.818 104.045 ;
     RECT  194.364 103.819 194.382 104.053 ;
     RECT  218.88 104.053 218.898 104.093 ;
     RECT  196.308 104.009 197.097 104.107 ;
     RECT  73.728 104.009 74.97 104.117 ;
     RECT  194.364 104.053 194.454 104.153 ;
     RECT  196.092 104.107 197.097 104.153 ;
     RECT  73.728 104.117 74.898 104.189 ;
     RECT  194.364 104.153 194.382 104.189 ;
     RECT  47.7 104.107 47.718 104.245 ;
     RECT  47.376 104.245 47.718 104.279 ;
     RECT  69.156 103.855 69.174 104.279 ;
     RECT  73.728 104.189 74.862 104.279 ;
     RECT  198.684 103.883 200.034 104.279 ;
     RECT  214.596 104.045 215.19 104.279 ;
     RECT  47.376 104.279 47.394 104.285 ;
     RECT  70.344 103.747 71.478 104.315 ;
     RECT  212.94 104.045 213.786 104.315 ;
     RECT  214.596 104.279 215.046 104.315 ;
     RECT  16.02 103.883 16.362 104.351 ;
     RECT  70.488 104.315 71.478 104.359 ;
     RECT  72.216 103.109 72.897 104.359 ;
     RECT  67.215 103.517 67.497 104.395 ;
     RECT  17.352 102.941 24.297 104.423 ;
     RECT  66.708 104.395 67.497 104.431 ;
     RECT  17.352 104.423 21.15 104.459 ;
     RECT  74.844 104.279 74.862 104.459 ;
     RECT  66.708 104.431 68.022 104.549 ;
     RECT  70.488 104.359 72.897 104.549 ;
     RECT  199.224 104.279 200.034 104.549 ;
     RECT  22.14 104.423 24.297 104.657 ;
     RECT  4.608 103.379 13.77 104.693 ;
     RECT  82.332 101.579 82.35 104.693 ;
     RECT  18.504 104.459 21.15 104.729 ;
     RECT  199.224 104.549 199.494 104.729 ;
     RECT  3.672 104.701 3.834 104.765 ;
     RECT  115.815 100.963 116.097 104.791 ;
     RECT  3.816 104.765 3.834 104.819 ;
     RECT  18.504 104.729 21.114 104.819 ;
     RECT  68.976 104.323 69.138 104.819 ;
     RECT  70.488 104.549 71.622 104.819 ;
     RECT  112.068 104.731 112.086 104.819 ;
     RECT  211.932 103.901 212.202 104.827 ;
     RECT  212.94 104.315 213.75 104.827 ;
     RECT  115.704 104.791 116.097 104.861 ;
     RECT  111.744 104.827 111.762 104.864 ;
     RECT  117.36 104.827 117.378 104.864 ;
     RECT  211.932 104.827 213.75 104.875 ;
     RECT  18.615 104.819 21.114 104.927 ;
     RECT  99.252 103.541 99.897 104.927 ;
     RECT  201.132 103.379 201.15 104.927 ;
     RECT  22.14 104.657 23.022 104.963 ;
     RECT  17.352 104.459 17.694 104.999 ;
     RECT  199.476 104.729 199.494 104.999 ;
     RECT  19.692 104.927 21.114 105.089 ;
     RECT  22.176 104.963 23.022 105.089 ;
     RECT  68.4 104.971 68.418 105.089 ;
     RECT  70.488 104.819 70.506 105.089 ;
     RECT  71.604 104.819 71.622 105.089 ;
     RECT  72.36 104.549 72.897 105.089 ;
     RECT  194.364 104.923 194.49 105.101 ;
     RECT  211.716 104.875 213.75 105.125 ;
     RECT  18.615 104.927 18.954 105.161 ;
     RECT  22.176 105.089 22.842 105.161 ;
     RECT  69.264 105.061 69.534 105.211 ;
     RECT  211.932 105.125 213.75 105.241 ;
     RECT  214.956 105.205 214.974 105.241 ;
     RECT  19.692 105.089 21.042 105.269 ;
     RECT  196.815 104.153 197.097 105.307 ;
     RECT  197.856 104.875 197.874 105.307 ;
     RECT  69.264 105.211 70.398 105.359 ;
     RECT  196.815 105.307 197.874 105.359 ;
     RECT  19.692 105.269 20.538 105.389 ;
     RECT  217.692 105.241 217.71 105.395 ;
     RECT  219.42 105.355 219.438 105.395 ;
     RECT  17.676 104.999 17.694 105.503 ;
     RECT  4.716 104.693 13.77 105.629 ;
     RECT  69.264 105.359 69.39 105.629 ;
     RECT  70.38 105.359 70.398 105.629 ;
     RECT  71.676 105.451 71.838 105.629 ;
     RECT  211.932 105.241 214.974 105.629 ;
     RECT  26.604 105.601 26.622 105.637 ;
     RECT  22.824 105.161 22.842 105.677 ;
     RECT  26.604 105.637 27.306 105.677 ;
     RECT  133.524 105.601 133.542 105.677 ;
     RECT  135.072 105.637 135.09 105.677 ;
     RECT  16.344 104.351 16.362 105.691 ;
     RECT  212.976 105.629 214.974 105.737 ;
     RECT  16.344 105.691 16.398 105.739 ;
     RECT  2.415 103.775 2.697 105.781 ;
     RECT  19.692 105.389 20.502 105.809 ;
     RECT  78.015 103.853 78.297 105.871 ;
     RECT  88.815 103.757 89.097 105.871 ;
     RECT  99.615 104.927 99.897 105.871 ;
     RECT  121.215 103.757 121.497 105.871 ;
     RECT  132.015 103.757 132.297 105.871 ;
     RECT  142.815 103.613 143.097 105.871 ;
     RECT  153.615 103.853 153.897 105.871 ;
     RECT  164.415 103.757 164.697 105.871 ;
     RECT  175.215 100.963 175.497 105.871 ;
     RECT  186.015 103.883 186.297 105.871 ;
     RECT  15.696 105.739 16.398 105.899 ;
     RECT  69.372 105.629 69.39 105.899 ;
     RECT  71.676 105.629 71.694 105.899 ;
     RECT  70.488 105.871 70.506 105.917 ;
     RECT  77.904 105.871 78.297 105.917 ;
     RECT  88.704 105.871 89.097 105.917 ;
     RECT  99.504 105.871 99.897 105.917 ;
     RECT  121.104 105.871 121.497 105.917 ;
     RECT  131.904 105.871 132.297 105.917 ;
     RECT  142.704 105.871 143.097 105.917 ;
     RECT  153.504 105.871 153.897 105.917 ;
     RECT  164.304 105.871 164.697 105.917 ;
     RECT  175.104 105.871 175.497 105.917 ;
     RECT  185.904 105.871 186.297 105.917 ;
     RECT  2.415 105.781 3.33 105.943 ;
     RECT  66.708 104.549 67.497 105.971 ;
     RECT  194.364 105.101 194.382 106.013 ;
     RECT  29.415 100.769 29.697 106.027 ;
     RECT  2.415 105.943 3.618 106.169 ;
     RECT  4.932 105.629 13.77 106.169 ;
     RECT  213.015 105.737 214.974 106.177 ;
     RECT  216.576 106.177 216.594 106.249 ;
     RECT  20.196 105.809 20.502 106.267 ;
     RECT  24.015 104.657 24.297 106.312 ;
     RECT  198.36 106.123 198.378 106.321 ;
     RECT  213.015 106.177 215.37 106.321 ;
     RECT  216.18 106.249 216.594 106.321 ;
     RECT  217.8 106.285 217.818 106.321 ;
     RECT  3.42 106.169 3.618 106.349 ;
     RECT  34.815 102.125 35.097 106.405 ;
     RECT  23.904 106.312 24.297 106.411 ;
     RECT  45.615 102.701 45.897 106.411 ;
     RECT  56.415 102.128 56.697 106.411 ;
     RECT  20.196 106.267 21.078 106.439 ;
     RECT  27.936 106.315 27.954 106.439 ;
     RECT  28.908 106.027 29.697 106.439 ;
     RECT  34.704 106.405 35.097 106.445 ;
     RECT  74.664 106.267 74.682 106.445 ;
     RECT  45.504 106.411 45.897 106.448 ;
     RECT  56.304 106.411 56.697 106.448 ;
     RECT  67.104 105.971 67.497 106.448 ;
     RECT  213.015 106.321 216.774 106.475 ;
     RECT  214.416 106.475 216.774 106.547 ;
     RECT  215.856 106.547 216.774 106.555 ;
     RECT  217.8 106.321 217.962 106.555 ;
     RECT  215.856 106.555 217.962 106.583 ;
     RECT  3.42 106.349 3.438 106.589 ;
     RECT  214.416 106.547 214.974 106.589 ;
     RECT  216.036 106.583 216.054 106.589 ;
     RECT  198.36 106.321 198.738 106.603 ;
     RECT  198.36 106.603 199.098 106.637 ;
     RECT  23.58 106.411 24.297 106.699 ;
     RECT  22.968 106.699 24.297 106.733 ;
     RECT  22.968 106.733 22.986 106.745 ;
     RECT  214.56 106.589 214.974 106.745 ;
     RECT  217.296 106.583 217.962 106.745 ;
     RECT  4.932 106.169 13.497 106.939 ;
     RECT  102.78 103.811 102.798 106.979 ;
     RECT  199.08 106.637 199.098 106.979 ;
     RECT  200.592 106.603 200.61 106.979 ;
     RECT  219.42 106.603 219.438 106.979 ;
     RECT  217.332 106.745 217.962 107.015 ;
     RECT  4.5 106.939 13.497 107.051 ;
     RECT  4.5 107.051 11.358 107.213 ;
     RECT  217.332 107.015 217.818 107.285 ;
     RECT  2.415 106.169 2.697 107.329 ;
     RECT  217.764 107.285 217.818 107.393 ;
     RECT  2.415 107.329 3.33 107.401 ;
     RECT  2.415 107.401 3.402 107.519 ;
     RECT  4.68 107.213 11.358 107.627 ;
     RECT  214.956 106.745 214.974 107.635 ;
     RECT  9.792 107.627 11.358 107.699 ;
     RECT  213.015 106.475 213.678 107.755 ;
     RECT  213.015 107.755 214.074 107.797 ;
     RECT  214.956 107.635 215.55 107.797 ;
     RECT  0.108 105.745 0.126 107.851 ;
     RECT  12.78 107.051 13.497 107.905 ;
     RECT  0.108 107.851 0.558 107.933 ;
     RECT  12.708 107.905 13.497 107.941 ;
     RECT  213.015 107.797 215.55 107.941 ;
     RECT  219.42 107.899 219.438 108.059 ;
     RECT  217.8 107.393 217.818 108.095 ;
     RECT  213.015 107.941 215.622 108.175 ;
     RECT  9.828 107.699 11.358 108.203 ;
     RECT  4.68 107.627 9.054 108.317 ;
     RECT  213.015 108.175 215.658 108.329 ;
     RECT  5.22 108.317 9.054 108.365 ;
     RECT  34.815 106.445 35.097 108.565 ;
     RECT  44.172 108.523 44.19 108.571 ;
     RECT  213.015 108.329 215.622 108.599 ;
     RECT  34.704 108.565 35.097 108.605 ;
     RECT  43.884 108.571 44.19 108.635 ;
     RECT  213.015 108.599 215.442 108.635 ;
     RECT  10.008 108.203 11.358 108.643 ;
     RECT  213.015 108.635 214.326 108.671 ;
     RECT  211.932 105.629 212.202 108.715 ;
     RECT  213.015 108.671 213.966 108.715 ;
     RECT  10.008 108.643 11.826 108.751 ;
     RECT  12.708 107.941 13.806 108.751 ;
     RECT  43.884 108.635 43.902 108.779 ;
     RECT  200.304 108.751 200.322 108.797 ;
     RECT  2.415 107.519 2.697 108.841 ;
     RECT  10.008 108.751 13.806 109.021 ;
     RECT  2.415 108.841 3.222 109.139 ;
     RECT  9.684 109.021 13.806 109.139 ;
     RECT  5.364 108.365 8.766 109.147 ;
     RECT  16.344 105.899 16.362 109.219 ;
     RECT  17.46 109.021 17.478 109.219 ;
     RECT  16.344 109.219 17.478 109.243 ;
     RECT  9.684 109.139 12.078 109.283 ;
     RECT  16.164 109.243 17.478 109.283 ;
     RECT  3.564 109.291 3.582 109.409 ;
     RECT  14.796 109.219 14.814 109.409 ;
     RECT  16.344 109.283 17.478 109.409 ;
     RECT  218.844 109.195 218.862 109.409 ;
     RECT  17.136 109.409 17.478 109.417 ;
     RECT  18.615 105.161 18.897 109.417 ;
     RECT  211.932 108.715 213.966 109.417 ;
     RECT  17.136 109.417 18.897 109.445 ;
     RECT  217.368 109.381 217.386 109.481 ;
     RECT  0.108 107.933 0.126 109.715 ;
     RECT  9.684 109.283 11.646 109.751 ;
     RECT  4.356 109.255 4.374 109.831 ;
     RECT  4.356 109.831 4.554 109.859 ;
     RECT  4.536 109.859 4.554 109.901 ;
     RECT  10.368 109.751 11.646 110.029 ;
     RECT  10.368 110.029 11.682 110.219 ;
     RECT  211.932 109.417 214.434 110.255 ;
     RECT  211.932 110.255 213.858 110.335 ;
     RECT  13.215 109.139 13.806 110.497 ;
     RECT  219.42 110.488 219.438 110.525 ;
     RECT  202.215 103.307 202.497 110.587 ;
     RECT  214.668 110.641 214.686 110.875 ;
     RECT  211.824 110.335 213.858 110.909 ;
     RECT  214.668 110.875 214.722 110.911 ;
     RECT  215.532 110.875 215.55 110.911 ;
     RECT  214.668 110.911 215.55 111.029 ;
     RECT  211.932 110.909 213.858 111.065 ;
     RECT  202.215 110.587 203.058 111.181 ;
     RECT  214.668 111.029 215.406 111.181 ;
     RECT  216.288 110.533 216.306 111.181 ;
     RECT  202.215 111.181 203.346 111.299 ;
     RECT  214.632 111.181 215.406 111.299 ;
     RECT  216.288 111.181 216.522 111.379 ;
     RECT  211.932 111.065 213.462 111.407 ;
     RECT  175.215 105.917 175.497 111.451 ;
     RECT  211.932 111.407 212.202 111.479 ;
     RECT  215.244 111.299 215.406 111.485 ;
     RECT  175.215 111.451 175.59 111.569 ;
     RECT  202.215 111.299 203.022 111.569 ;
     RECT  205.272 111.163 205.29 111.569 ;
     RECT  20.196 106.439 20.502 111.713 ;
     RECT  219.456 111.541 219.474 111.821 ;
     RECT  213.015 111.407 213.462 111.835 ;
     RECT  217.836 111.685 217.854 111.839 ;
     RECT  215.388 111.485 215.406 111.919 ;
     RECT  216.144 111.379 216.522 111.919 ;
     RECT  213.015 111.835 213.714 111.931 ;
     RECT  5.292 109.147 8.766 111.955 ;
     RECT  215.388 111.919 216.522 111.965 ;
     RECT  216.36 111.965 216.522 111.983 ;
     RECT  121.215 105.917 121.497 111.991 ;
     RECT  217.692 111.955 217.818 111.991 ;
     RECT  16.344 109.409 16.362 112.019 ;
     RECT  213.015 111.931 214.038 112.019 ;
     RECT  215.388 111.965 215.406 112.019 ;
     RECT  216.936 111.991 217.818 112.145 ;
     RECT  0.108 111.835 0.126 112.171 ;
     RECT  0.108 112.171 0.558 112.253 ;
     RECT  4.716 111.955 8.766 112.267 ;
     RECT  4.212 112.267 8.766 112.301 ;
     RECT  217.224 112.145 217.818 112.379 ;
     RECT  217.224 112.379 217.782 112.415 ;
     RECT  2.415 109.139 2.697 112.531 ;
     RECT  2.415 112.531 3.258 112.637 ;
     RECT  4.212 112.301 4.23 112.649 ;
     RECT  217.62 112.415 217.782 112.649 ;
     RECT  217.62 112.649 217.638 112.685 ;
     RECT  3.96 112.801 3.978 112.919 ;
     RECT  5.292 112.301 8.766 113.459 ;
     RECT  202.215 111.569 202.497 113.467 ;
     RECT  5.292 113.459 5.706 113.495 ;
     RECT  2.415 112.637 3.222 113.639 ;
     RECT  105.015 101.357 105.297 113.701 ;
     RECT  22.5 110.461 22.518 113.729 ;
     RECT  201.744 113.467 202.497 113.947 ;
     RECT  201.672 113.947 202.497 113.999 ;
     RECT  5.292 113.495 5.346 114.029 ;
     RECT  2.415 113.639 2.754 114.035 ;
     RECT  3.996 113.995 4.554 114.071 ;
     RECT  213.015 112.019 213.462 114.151 ;
     RECT  17.244 109.445 18.897 114.269 ;
     RECT  121.104 111.991 121.497 114.305 ;
     RECT  17.244 114.269 17.262 114.809 ;
     RECT  213.015 114.151 213.642 114.817 ;
     RECT  0.108 112.253 0.126 114.845 ;
     RECT  212.904 114.817 213.642 114.881 ;
     RECT  6.66 113.459 8.766 114.889 ;
     RECT  212.904 114.881 213.39 114.893 ;
     RECT  20.196 111.713 20.25 114.953 ;
     RECT  4.464 114.071 4.554 114.961 ;
     RECT  6.408 114.889 8.766 115.051 ;
     RECT  5.292 114.029 5.31 115.079 ;
     RECT  218.88 115.045 218.898 115.085 ;
     RECT  4.356 114.961 4.554 115.099 ;
     RECT  214.164 114.961 214.182 115.115 ;
     RECT  2.415 114.035 2.697 115.123 ;
     RECT  4.356 115.099 4.662 115.133 ;
     RECT  6.264 115.051 8.766 115.133 ;
     RECT  217.8 115.051 217.818 115.151 ;
     RECT  1.728 115.123 2.697 115.181 ;
     RECT  216.036 115.195 216.054 115.231 ;
     RECT  215.388 115.231 216.054 115.349 ;
     RECT  3.708 115.339 3.726 115.385 ;
     RECT  215.388 115.349 215.946 115.385 ;
     RECT  0.54 115.465 0.558 115.517 ;
     RECT  215.784 115.385 215.946 115.619 ;
     RECT  4.572 115.133 4.662 115.655 ;
     RECT  215.784 115.619 215.802 115.655 ;
     RECT  4.644 115.655 4.662 115.889 ;
     RECT  0.108 115.819 0.126 115.925 ;
     RECT  6.66 115.133 8.766 116.041 ;
     RECT  6.66 116.041 8.838 116.159 ;
     RECT  10.368 110.219 11.646 116.159 ;
     RECT  6.84 116.159 8.838 116.167 ;
     RECT  10.368 116.159 11.286 116.195 ;
     RECT  6.84 116.167 8.91 116.239 ;
     RECT  10.368 116.195 11.106 116.239 ;
     RECT  6.84 116.239 8.982 116.311 ;
     RECT  105.015 113.701 105.39 116.311 ;
     RECT  6.84 116.311 9.234 116.707 ;
     RECT  10.008 116.239 11.106 116.707 ;
     RECT  6.84 116.707 11.106 116.969 ;
     RECT  51.015 100.805 51.297 117.067 ;
     RECT  51.015 117.067 51.75 117.239 ;
     RECT  51.015 117.239 51.462 117.248 ;
     RECT  20.196 114.953 20.214 117.509 ;
     RECT  6.84 116.969 10.998 117.589 ;
     RECT  6.552 117.589 10.998 117.625 ;
     RECT  6.228 117.625 10.998 117.661 ;
     RECT  5.688 117.661 10.998 117.739 ;
     RECT  53.532 117.481 53.55 117.779 ;
     RECT  54.108 117.931 54.126 118.319 ;
     RECT  218.88 118.357 218.898 118.397 ;
     RECT  5.292 117.739 10.998 118.435 ;
     RECT  214.308 118.291 214.326 118.435 ;
     RECT  2.415 115.181 2.697 118.459 ;
     RECT  211.932 111.479 211.95 118.471 ;
     RECT  213.015 114.893 213.39 118.471 ;
     RECT  214.308 118.435 214.938 118.471 ;
     RECT  3.996 118.399 4.014 118.499 ;
     RECT  211.932 118.471 214.938 118.541 ;
     RECT  5.184 118.435 10.998 118.561 ;
     RECT  213.015 118.541 214.938 118.589 ;
     RECT  2.304 118.459 2.697 118.625 ;
     RECT  213.015 118.589 214.794 118.859 ;
     RECT  213.015 118.859 214.47 118.895 ;
     RECT  0.108 118.123 0.126 119.165 ;
     RECT  0.144 119.467 0.162 119.543 ;
     RECT  2.415 118.625 2.697 119.677 ;
     RECT  4.464 118.561 10.998 119.821 ;
     RECT  1.728 119.677 2.697 119.837 ;
     RECT  4.464 119.821 11.25 119.849 ;
     RECT  4.86 119.849 11.25 120.055 ;
     RECT  4.86 120.055 11.61 120.091 ;
     RECT  12.528 110.497 13.806 120.091 ;
     RECT  4.86 120.091 13.806 120.479 ;
     RECT  4.86 120.479 11.718 120.515 ;
     RECT  4.86 120.515 11.646 120.712 ;
     RECT  4.788 120.712 11.646 121.019 ;
     RECT  211.932 118.541 211.95 121.261 ;
     RECT  12.528 120.479 13.806 121.289 ;
     RECT  3.924 121.063 3.942 121.369 ;
     RECT  4.788 121.019 11.61 121.369 ;
     RECT  3.924 121.369 11.61 121.421 ;
     RECT  211.716 121.261 211.95 121.435 ;
     RECT  105.015 116.311 105.534 121.559 ;
     RECT  3.924 121.421 3.942 121.595 ;
     RECT  5.04 121.421 11.61 121.595 ;
     RECT  210.996 121.435 211.95 121.631 ;
     RECT  211.716 121.631 211.95 121.703 ;
     RECT  213.015 118.895 213.39 121.711 ;
     RECT  217.548 121.675 217.566 121.711 ;
     RECT  5.04 121.595 11.466 121.829 ;
     RECT  216.936 121.711 217.746 121.829 ;
     RECT  219.42 121.627 219.438 121.829 ;
     RECT  212.292 121.711 213.39 121.865 ;
     RECT  217.044 121.829 217.746 121.865 ;
     RECT  215.928 121.801 215.946 121.973 ;
     RECT  217.26 121.865 217.494 122.099 ;
     RECT  217.26 122.099 217.278 122.135 ;
     RECT  3.78 122.071 3.798 122.171 ;
     RECT  5.04 121.829 11.394 122.369 ;
     RECT  7.56 122.369 10.458 122.405 ;
     RECT  11.196 122.369 11.214 122.405 ;
     RECT  5.04 122.369 6.75 122.485 ;
     RECT  4.536 122.485 6.75 122.513 ;
     RECT  7.56 122.405 9.738 122.525 ;
     RECT  4.536 122.513 6.678 122.536 ;
     RECT  5.724 122.536 6.678 122.639 ;
     RECT  7.56 122.525 9.702 122.639 ;
     RECT  187.452 122.395 187.47 122.639 ;
     RECT  189 122.341 189.018 122.669 ;
     RECT  7.56 122.639 9.27 122.675 ;
     RECT  2.415 119.837 2.697 122.791 ;
     RECT  4.536 122.536 4.554 122.909 ;
     RECT  6.192 122.639 6.21 122.909 ;
     RECT  0.108 120.139 0.126 122.945 ;
     RECT  7.815 122.675 9.27 123.053 ;
     RECT  2.415 122.791 3.042 123.061 ;
     RECT  2.415 123.061 3.294 123.067 ;
     RECT  2.304 123.067 3.294 123.179 ;
     RECT  2.304 123.179 2.697 123.215 ;
     RECT  13.215 121.289 13.806 124.259 ;
     RECT  217.8 124.645 217.818 124.771 ;
     RECT  119.844 124.411 119.862 124.799 ;
     RECT  215.532 124.843 215.55 124.879 ;
     RECT  215.532 124.879 216.126 124.88 ;
     RECT  213.015 121.865 213.39 124.907 ;
     RECT  216.108 124.88 216.126 124.915 ;
     RECT  217.656 124.771 217.818 124.915 ;
     RECT  216.108 124.915 216.414 124.951 ;
     RECT  217.656 124.915 217.962 124.951 ;
     RECT  219.456 124.501 219.474 124.973 ;
     RECT  214.344 124.879 214.362 125.069 ;
     RECT  216.108 124.951 217.962 125.069 ;
     RECT  217.008 125.069 217.818 125.105 ;
     RECT  7.815 123.053 8.766 125.339 ;
     RECT  217.152 125.105 217.818 125.339 ;
     RECT  2.415 123.215 2.697 125.347 ;
     RECT  217.152 125.339 217.782 125.375 ;
     RECT  7.815 125.339 8.442 125.419 ;
     RECT  1.728 125.347 2.697 125.453 ;
     RECT  7.596 125.419 8.442 125.483 ;
     RECT  7.815 125.483 8.442 125.609 ;
     RECT  217.656 125.375 217.782 125.609 ;
     RECT  217.656 125.609 217.674 125.645 ;
     RECT  2.415 125.453 2.697 127.187 ;
     RECT  7.815 125.609 8.097 127.187 ;
     RECT  13.215 124.259 13.497 127.187 ;
     RECT  18.615 114.269 18.897 127.187 ;
     RECT  24.015 106.733 24.297 127.187 ;
     RECT  29.415 106.439 29.697 127.187 ;
     RECT  34.815 108.605 35.097 127.187 ;
     RECT  40.215 101.417 40.497 127.187 ;
     RECT  45.615 106.448 45.897 127.187 ;
     RECT  51.015 117.248 51.297 127.187 ;
     RECT  56.415 106.448 56.697 127.187 ;
     RECT  61.815 101.957 62.097 127.187 ;
     RECT  67.215 106.448 67.497 127.187 ;
     RECT  72.615 105.089 72.897 127.187 ;
     RECT  78.015 105.917 78.297 127.187 ;
     RECT  83.415 101.849 83.697 127.187 ;
     RECT  88.815 105.917 89.097 127.187 ;
     RECT  94.215 103.853 94.497 127.187 ;
     RECT  99.615 105.917 99.897 127.187 ;
     RECT  105.015 121.559 105.297 127.187 ;
     RECT  110.415 102.119 110.697 127.187 ;
     RECT  115.815 104.861 116.097 127.187 ;
     RECT  121.215 114.305 121.497 127.187 ;
     RECT  126.615 100.963 126.897 127.187 ;
     RECT  132.015 105.917 132.297 127.187 ;
     RECT  137.415 100.781 137.697 127.187 ;
     RECT  142.815 105.917 143.097 127.187 ;
     RECT  148.215 100.963 148.497 127.187 ;
     RECT  153.615 105.917 153.897 127.187 ;
     RECT  159.015 100.963 159.297 127.187 ;
     RECT  164.415 105.917 164.697 127.187 ;
     RECT  169.815 103.853 170.097 127.187 ;
     RECT  175.215 111.569 175.497 127.187 ;
     RECT  180.615 100.963 180.897 127.187 ;
     RECT  186.015 105.917 186.297 127.187 ;
     RECT  191.415 100.963 191.697 127.187 ;
     RECT  196.815 105.359 197.097 127.187 ;
     RECT  202.215 113.999 202.497 127.187 ;
     RECT  207.615 99.437 207.897 127.187 ;
     RECT  213.015 124.907 213.297 127.187 ;
     RECT  2.415 127.187 2.505 127.457 ;
     RECT  7.815 127.187 7.905 127.457 ;
     RECT  13.215 127.187 13.305 127.457 ;
     RECT  18.615 127.187 18.705 127.457 ;
     RECT  24.015 127.187 24.174 127.457 ;
     RECT  29.415 127.187 29.505 127.457 ;
     RECT  34.815 127.187 34.905 127.457 ;
     RECT  40.215 127.187 40.305 127.457 ;
     RECT  45.615 127.187 45.705 127.457 ;
     RECT  51.015 127.187 51.105 127.457 ;
     RECT  56.415 127.187 56.505 127.457 ;
     RECT  61.815 127.187 61.905 127.457 ;
     RECT  67.215 127.187 67.305 127.457 ;
     RECT  72.615 127.187 72.705 127.457 ;
     RECT  78.015 127.187 78.105 127.457 ;
     RECT  83.415 127.187 83.505 127.457 ;
     RECT  88.815 127.187 88.905 127.457 ;
     RECT  94.215 127.187 94.305 127.457 ;
     RECT  99.615 127.187 99.705 127.457 ;
     RECT  105.015 127.187 105.105 127.457 ;
     RECT  110.415 127.187 110.505 127.457 ;
     RECT  115.815 127.187 115.905 127.457 ;
     RECT  121.215 127.187 121.305 127.457 ;
     RECT  126.615 127.187 126.705 127.457 ;
     RECT  132.015 127.187 132.105 127.457 ;
     RECT  137.415 127.187 137.505 127.457 ;
     RECT  142.815 127.187 142.905 127.457 ;
     RECT  148.215 127.187 148.305 127.457 ;
     RECT  153.615 127.187 153.705 127.457 ;
     RECT  159.015 127.187 159.105 127.457 ;
     RECT  164.415 127.187 164.505 127.457 ;
     RECT  169.815 127.187 169.905 127.457 ;
     RECT  175.215 127.187 175.305 127.457 ;
     RECT  180.615 127.187 180.705 127.457 ;
     RECT  186.015 127.187 186.105 127.457 ;
     RECT  191.415 127.187 191.505 127.457 ;
     RECT  196.815 127.187 196.905 127.457 ;
     RECT  202.215 127.187 202.305 127.457 ;
     RECT  207.615 127.187 207.705 127.457 ;
     RECT  213.015 127.187 213.105 127.457 ;
     RECT  24.156 127.457 24.174 127.949 ;
    LAYER M4 ;
     RECT  0.06 6.48 0.137 8.808 ;
     RECT  0.06 11.136 0.137 14.76 ;
     RECT  0.06 17.088 0.137 101.256 ;
     RECT  0.06 105.888 0.137 109.56 ;
     RECT  0.06 111.84 0.137 115.848 ;
     RECT  0.06 118.128 0.137 123.096 ;
     RECT  0.137 54.048 0.173 54.408 ;
     RECT  0.137 57.36 0.173 57.384 ;
     RECT  0.137 58.656 0.173 59.688 ;
     RECT  0.137 67.92 0.173 67.944 ;
     RECT  0.137 72.864 0.173 75.192 ;
     RECT  0.137 76.176 0.173 78.168 ;
     RECT  0.137 87.024 0.173 87.72 ;
     RECT  0.137 93.312 0.173 94.68 ;
     RECT  0.137 119.472 0.173 119.832 ;
     RECT  0.137 14.4 0.569 14.76 ;
     RECT  0.137 21.024 0.569 21.72 ;
     RECT  0.137 36.576 0.569 36.888 ;
     RECT  0.137 40.848 0.569 42.84 ;
     RECT  0.137 43.824 0.569 44.52 ;
     RECT  0.137 50.4 0.569 50.424 ;
     RECT  0.173 74.16 0.569 75.192 ;
     RECT  0.137 84.096 0.569 84.12 ;
     RECT  0.137 107.856 0.569 107.88 ;
     RECT  0.137 112.176 0.569 112.2 ;
     RECT  0.137 115.152 0.569 115.512 ;
     RECT  0.137 7.488 2.408 7.512 ;
     RECT  0.137 12.096 2.408 12.12 ;
     RECT  0.569 14.736 2.408 14.76 ;
     RECT  0.137 17.088 2.408 17.112 ;
     RECT  0.569 21.024 2.408 21.048 ;
     RECT  0.137 25.008 2.408 25.032 ;
     RECT  0.137 26.016 2.408 26.664 ;
     RECT  0.137 28.944 2.408 31.32 ;
     RECT  0.137 33.264 2.408 33.288 ;
     RECT  0.569 36.864 2.408 36.888 ;
     RECT  0.137 39.216 2.408 39.864 ;
     RECT  0.569 41.52 2.408 42.84 ;
     RECT  0.569 44.496 2.408 44.52 ;
     RECT  0.137 46.128 2.408 46.152 ;
     RECT  0.137 51.744 2.408 53.064 ;
     RECT  0.173 54.048 2.408 54.072 ;
     RECT  0.137 55.68 2.408 55.704 ;
     RECT  0.173 58.656 2.408 58.68 ;
     RECT  0.137 60.96 2.408 60.984 ;
     RECT  0.137 62.64 2.408 63.288 ;
     RECT  0.137 65.616 2.408 66.6 ;
     RECT  0.137 69.552 2.408 69.576 ;
     RECT  0.137 71.184 2.408 71.88 ;
     RECT  0.173 72.864 2.408 72.888 ;
     RECT  0.569 74.832 2.408 74.856 ;
     RECT  0.173 76.176 2.408 76.2 ;
     RECT  0.173 77.472 2.408 78.168 ;
     RECT  0.137 80.448 2.408 81.48 ;
     RECT  0.137 83.088 2.408 83.112 ;
     RECT  0.173 87.696 2.408 87.72 ;
     RECT  0.137 91.68 2.408 92.328 ;
     RECT  0.173 93.984 2.408 94.68 ;
     RECT  0.137 97.296 2.408 98.616 ;
     RECT  0.137 100.224 2.408 100.248 ;
     RECT  0.137 113.184 2.408 113.88 ;
     RECT  0.569 115.152 2.408 115.176 ;
     RECT  0.137 118.464 2.408 118.488 ;
     RECT  0.173 119.808 2.408 119.832 ;
     RECT  0.137 123.072 2.408 123.096 ;
     RECT  2.408 2.148 2.512 127.452 ;
     RECT  2.512 2.418 2.704 127.182 ;
     RECT  2.704 25.008 2.765 25.032 ;
     RECT  2.704 39.84 2.765 40.824 ;
     RECT  2.704 66.576 2.765 66.6 ;
     RECT  2.704 112.608 2.765 113.88 ;
     RECT  2.704 36.864 2.801 37.032 ;
     RECT  2.765 112.608 2.801 113.208 ;
     RECT  2.704 80.352 3.305 80.376 ;
     RECT  2.704 81.6 3.349 82.776 ;
     RECT  2.704 48.96 3.443 49.608 ;
     RECT  2.704 78.144 3.449 78.168 ;
     RECT  2.704 85.488 3.557 87 ;
     RECT  3.557 86.016 3.587 87 ;
     RECT  2.704 26.112 3.769 27.48 ;
     RECT  2.704 31.248 3.769 31.272 ;
     RECT  3.841 24.624 3.877 24.648 ;
     RECT  2.704 103.008 3.877 103.032 ;
     RECT  3.769 30.288 3.935 31.272 ;
     RECT  2.704 33.024 3.971 35.688 ;
     RECT  2.704 11.328 3.973 11.352 ;
     RECT  2.704 106.56 3.973 106.584 ;
     RECT  3.769 25.776 3.989 27.48 ;
     RECT  3.971 33.024 4.012 33.624 ;
     RECT  3.913 8.832 4.019 8.856 ;
     RECT  3.973 11.328 4.019 11.928 ;
     RECT  3.973 106.56 4.019 106.968 ;
     RECT  3.973 41.856 4.057 41.88 ;
     RECT  4.057 41.856 4.06 42.696 ;
     RECT  3.989 25.776 4.097 26.76 ;
     RECT  4.012 33.024 4.097 33.384 ;
     RECT  3.971 34.752 4.133 35.688 ;
     RECT  3.973 7.776 4.169 7.8 ;
     RECT  2.801 112.608 4.201 112.632 ;
     RECT  4.201 112.272 4.241 112.632 ;
     RECT  4.097 25.776 4.277 26.472 ;
     RECT  2.704 91.44 4.281 91.464 ;
     RECT  2.704 89.856 4.309 89.88 ;
     RECT  4.281 90.912 4.309 91.464 ;
     RECT  2.801 37.008 4.316 37.032 ;
     RECT  3.697 115.344 4.345 115.368 ;
     RECT  4.309 89.856 4.355 91.464 ;
     RECT  4.316 37.008 4.403 37.848 ;
     RECT  2.704 70.944 4.405 70.968 ;
     RECT  2.704 93.504 4.405 93.528 ;
     RECT  4.06 42.672 4.417 42.696 ;
     RECT  3.443 48.96 4.417 48.984 ;
     RECT  4.133 34.752 4.421 34.872 ;
     RECT  4.355 90.624 4.451 91.464 ;
     RECT  4.405 92.544 4.451 93.528 ;
     RECT  2.704 18.144 4.453 18.168 ;
     RECT  3.877 103.008 4.453 103.176 ;
     RECT  2.704 22.752 4.489 22.776 ;
     RECT  3.877 24.24 4.489 24.648 ;
     RECT  4.019 106.944 4.489 106.968 ;
     RECT  4.453 17.856 4.493 18.168 ;
     RECT  4.381 5.088 4.499 5.112 ;
     RECT  4.345 109.392 4.501 109.416 ;
     RECT  4.453 6.528 4.525 6.552 ;
     RECT  4.489 22.752 4.529 24.648 ;
     RECT  3.935 30.192 4.529 31.272 ;
     RECT  4.097 33.024 4.529 33.048 ;
     RECT  4.405 70.032 4.529 71.304 ;
     RECT  4.525 6.528 4.54 7.368 ;
     RECT  4.237 27.936 4.549 28.008 ;
     RECT  4.529 22.752 4.565 24.504 ;
     RECT  4.501 109.392 4.588 109.896 ;
     RECT  4.345 97.44 4.601 97.464 ;
     RECT  4.345 115.104 4.601 115.368 ;
     RECT  4.525 14.688 4.633 14.712 ;
     RECT  4.549 27.936 4.636 28.968 ;
     RECT  3.913 121.392 4.637 121.416 ;
     RECT  3.349 81.6 4.693 81.624 ;
     RECT  4.633 82.608 4.693 82.632 ;
     RECT  4.529 30.192 4.709 30.216 ;
     RECT  4.489 106.944 4.709 107.208 ;
     RECT  4.693 80.928 4.739 82.632 ;
     RECT  4.093 64.032 4.741 64.056 ;
     RECT  4.381 68.928 4.777 68.952 ;
     RECT  4.529 70.032 4.777 70.824 ;
     RECT  4.739 80.928 4.78 80.952 ;
     RECT  4.739 82.128 4.78 82.632 ;
     RECT  2.765 40.8 4.813 40.824 ;
     RECT  3.697 39.6 4.817 39.624 ;
     RECT  4.777 68.928 4.817 70.824 ;
     RECT  4.813 40.8 4.853 41.016 ;
     RECT  4.561 55.008 4.885 55.032 ;
     RECT  3.913 56.496 4.885 56.52 ;
     RECT  2.704 60.432 4.885 60.456 ;
     RECT  4.417 48.96 4.889 49.56 ;
     RECT  4.453 102.624 4.889 103.176 ;
     RECT  4.403 37.008 4.921 37.656 ;
     RECT  4.741 64.032 4.921 64.584 ;
     RECT  4.525 65.904 4.921 65.928 ;
     RECT  4.885 60.432 4.961 61.08 ;
     RECT  4.921 62.64 5.036 62.664 ;
     RECT  4.921 64.032 5.057 65.928 ;
     RECT  4.889 49.056 5.064 49.56 ;
     RECT  5.064 49.056 5.065 50.28 ;
     RECT  4.493 17.856 5.077 17.88 ;
     RECT  5.036 62.544 5.077 62.664 ;
     RECT  5.057 63.648 5.077 65.928 ;
     RECT  4.019 11.904 5.125 11.928 ;
     RECT  4.633 13.776 5.125 14.712 ;
     RECT  5.077 62.544 5.141 65.928 ;
     RECT  4.889 102.624 5.141 103.032 ;
     RECT  5.077 17.04 5.164 17.88 ;
     RECT  4.885 55.008 5.171 56.52 ;
     RECT  4.237 95.088 5.173 95.112 ;
     RECT  5.141 62.544 5.209 62.76 ;
     RECT  5.125 11.904 5.213 14.712 ;
     RECT  4.705 21.312 5.237 21.336 ;
     RECT  4.817 68.928 5.245 69.192 ;
     RECT  4.669 108.288 5.249 108.312 ;
     RECT  4.237 59.232 5.269 59.256 ;
     RECT  5.237 21.072 5.276 21.336 ;
     RECT  5.209 83.76 5.293 83.784 ;
     RECT  5.209 62.16 5.315 62.76 ;
     RECT  5.269 59.232 5.317 59.832 ;
     RECT  5.276 21.072 5.321 21.912 ;
     RECT  4.529 31.248 5.321 31.272 ;
     RECT  5.317 58.992 5.357 59.832 ;
     RECT  3.985 114 5.357 114.024 ;
     RECT  4.417 43.776 5.389 43.8 ;
     RECT  4.525 45.024 5.389 45.048 ;
     RECT  5.173 99.744 5.389 99.768 ;
     RECT  4.453 100.896 5.389 100.92 ;
     RECT  5.173 95.088 5.42 95.16 ;
     RECT  4.093 96.144 5.42 96.168 ;
     RECT  5.141 64.56 5.425 65.928 ;
     RECT  5.389 99.744 5.425 100.92 ;
     RECT  5.42 95.088 5.453 96.168 ;
     RECT  5.357 58.992 5.461 59.256 ;
     RECT  5.453 94.56 5.461 96.168 ;
     RECT  5.213 13.776 5.465 14.712 ;
     RECT  5.389 43.776 5.465 45.048 ;
     RECT  4.921 36.144 5.468 37.656 ;
     RECT  3.587 86.976 5.489 87 ;
     RECT  5.209 10.32 5.497 10.344 ;
     RECT  5.461 58.752 5.501 59.256 ;
     RECT  5.461 94.56 5.507 96.888 ;
     RECT  4.421 34.752 5.509 34.776 ;
     RECT  5.468 36.048 5.509 37.656 ;
     RECT  5.171 55.008 5.525 55.032 ;
     RECT  5.507 94.56 5.537 94.584 ;
     RECT  5.321 21.312 5.569 21.912 ;
     RECT  4.565 23.376 5.569 24.504 ;
     RECT  5.465 44.448 5.569 45.048 ;
     RECT  4.417 46.704 5.569 46.728 ;
     RECT  4.451 90.624 5.569 90.744 ;
     RECT  5.509 36.048 5.573 38.424 ;
     RECT  5.489 86.592 5.573 87 ;
     RECT  5.425 99.744 5.596 101.448 ;
     RECT  5.507 96.864 5.605 96.888 ;
     RECT  5.569 44.448 5.609 46.728 ;
     RECT  4.451 92.544 5.609 92.568 ;
     RECT  5.065 49.056 5.641 50.664 ;
     RECT  5.573 37.584 5.653 38.424 ;
     RECT  3.769 52.992 5.653 53.016 ;
     RECT  4.741 98.256 5.653 98.28 ;
     RECT  5.596 99.744 5.653 100.248 ;
     RECT  4.961 61.056 5.677 61.08 ;
     RECT  5.101 122.496 5.713 122.52 ;
     RECT  5.609 44.448 5.717 46.536 ;
     RECT  5.653 37.584 5.745 39.096 ;
     RECT  5.525 54.144 5.785 55.032 ;
     RECT  5.677 61.056 5.785 61.176 ;
     RECT  5.605 96.864 5.785 97.272 ;
     RECT  5.653 98.256 5.785 100.248 ;
     RECT  5.213 11.904 5.789 12.504 ;
     RECT  5.713 83.856 5.797 83.88 ;
     RECT  5.653 52.656 5.821 53.016 ;
     RECT  5.501 58.752 5.821 59.016 ;
     RECT  5.573 86.976 5.821 87 ;
     RECT  4.921 88.32 5.821 88.344 ;
     RECT  5.101 119.568 5.821 119.592 ;
     RECT  5.785 54.096 5.825 55.032 ;
     RECT  5.164 17.856 5.857 17.88 ;
     RECT  2.704 104.736 5.893 104.76 ;
     RECT  5.173 106.416 5.893 106.44 ;
     RECT  5.857 17.856 5.897 18.216 ;
     RECT  5.785 96.864 5.897 100.248 ;
     RECT  4.241 112.272 5.897 112.296 ;
     RECT  5.425 64.56 5.933 66.12 ;
     RECT  5.745 37.584 6.005 37.896 ;
     RECT  4.78 82.608 6.005 82.632 ;
     RECT  5.389 19.92 6.035 19.944 ;
     RECT  5.897 97.248 6.035 100.248 ;
     RECT  4.853 40.992 6.037 41.016 ;
     RECT  5.821 52.464 6.037 53.016 ;
     RECT  4.777 120.72 6.037 121.032 ;
     RECT  5.713 122.496 6.037 122.616 ;
     RECT  4.54 7.344 6.041 7.368 ;
     RECT  5.569 21.312 6.041 24.504 ;
     RECT  5.509 34.752 6.073 35.064 ;
     RECT  5.573 36.048 6.073 36.408 ;
     RECT  5.171 56.112 6.092 56.52 ;
     RECT  4.417 42.672 6.113 42.744 ;
     RECT  6.037 120.72 6.121 122.616 ;
     RECT  6.092 56.112 6.133 56.952 ;
     RECT  4.277 26.112 6.14 26.472 ;
     RECT  4.636 27.936 6.14 28.008 ;
     RECT  6.037 40.608 6.181 41.016 ;
     RECT  6.113 42.672 6.181 42.696 ;
     RECT  5.785 61.056 6.181 61.224 ;
     RECT  4.588 109.392 6.181 109.416 ;
     RECT  5.315 62.64 6.217 62.76 ;
     RECT  6.14 26.112 6.227 28.008 ;
     RECT  6.181 40.608 6.229 42.696 ;
     RECT  5.569 90 6.229 90.744 ;
     RECT  5.893 104.736 6.245 106.44 ;
     RECT  6.121 120.72 6.257 121.224 ;
     RECT  6.229 40.416 6.275 42.696 ;
     RECT  6.041 23.328 6.277 24.504 ;
     RECT  5.745 38.928 6.277 39.096 ;
     RECT  6.275 40.416 6.277 40.632 ;
     RECT  6.245 104.736 6.277 106.584 ;
     RECT  5.717 45.696 6.329 46.536 ;
     RECT  6.121 122.256 6.329 122.616 ;
     RECT  5.209 33.264 6.361 33.288 ;
     RECT  6.073 34.752 6.361 36.408 ;
     RECT  5.641 49.056 6.361 51 ;
     RECT  4.381 74.688 6.361 74.712 ;
     RECT  6.277 104.736 6.361 107.208 ;
     RECT  6.284 64.224 6.371 64.344 ;
     RECT  6.181 60.24 6.397 61.224 ;
     RECT  4.561 79.008 6.397 79.032 ;
     RECT  5.497 10.32 6.401 10.632 ;
     RECT  6.361 74.304 6.401 74.712 ;
     RECT  5.141 103.008 6.421 103.032 ;
     RECT  4.817 70.8 6.433 70.824 ;
     RECT  4.525 76.368 6.437 76.392 ;
     RECT  6.229 90 6.437 91.176 ;
     RECT  6.428 29.616 6.469 29.64 ;
     RECT  6.133 56.112 6.476 57.624 ;
     RECT  5.821 58.656 6.476 59.016 ;
     RECT  6.397 78.048 6.481 79.032 ;
     RECT  5.821 119.088 6.505 119.592 ;
     RECT  6.421 103.008 6.509 103.752 ;
     RECT  6.476 56.112 6.517 59.016 ;
     RECT  6.397 60.24 6.517 61.56 ;
     RECT  5.465 14.688 6.545 14.712 ;
     RECT  6.277 38.928 6.545 40.632 ;
     RECT  6.517 56.112 6.563 61.56 ;
     RECT  5.245 68.352 6.563 69.192 ;
     RECT  6.433 70.8 6.611 70.92 ;
     RECT  5.717 44.448 6.613 44.472 ;
     RECT  5.821 86.976 6.613 88.344 ;
     RECT  6.217 62.64 6.617 63.096 ;
     RECT  6.257 120.72 6.617 121.128 ;
     RECT  6.469 29.616 6.649 30.216 ;
     RECT  4.601 115.104 6.649 115.128 ;
     RECT  6.361 104.736 6.653 107.352 ;
     RECT  2.704 47.856 6.659 47.88 ;
     RECT  6.563 58.656 6.659 61.56 ;
     RECT  6.613 86.976 6.668 88.968 ;
     RECT  6.041 21.312 6.689 22.296 ;
     RECT  6.668 86.928 6.697 88.968 ;
     RECT  6.037 52.464 6.716 53.064 ;
     RECT  6.437 90 6.716 90.648 ;
     RECT  6.649 115.104 6.733 115.752 ;
     RECT  6.697 86.928 6.755 88.2 ;
     RECT  6.227 26.112 6.757 26.76 ;
     RECT  6.716 52.368 6.757 53.064 ;
     RECT  5.825 54.096 6.757 54.168 ;
     RECT  6.035 100.08 6.757 100.248 ;
     RECT  5.596 101.424 6.757 101.448 ;
     RECT  5.857 31.968 6.793 31.992 ;
     RECT  6.361 33.264 6.793 36.408 ;
     RECT  6.755 87.792 6.797 88.2 ;
     RECT  6.481 78.624 6.853 79.032 ;
     RECT  5.281 117.744 6.853 117.768 ;
     RECT  5.857 93.984 6.86 94.008 ;
     RECT  6.653 104.784 6.865 107.352 ;
     RECT  6.227 27.744 6.901 28.008 ;
     RECT  6.649 29.616 6.901 30.408 ;
     RECT  6.659 60.24 6.901 61.56 ;
     RECT  6.86 93.984 6.901 94.248 ;
     RECT  6.793 31.968 6.937 36.408 ;
     RECT  6.005 37.584 6.937 37.608 ;
     RECT  6.793 67.344 6.937 67.368 ;
     RECT  6.853 116.832 6.949 117.768 ;
     RECT  6.361 48.912 6.973 51 ;
     RECT  6.949 116.112 7.004 117.768 ;
     RECT  6.505 119.088 7.004 119.736 ;
     RECT  6.973 48 7.009 51 ;
     RECT  6.757 52.368 7.009 54.168 ;
     RECT  6.937 31.968 7.081 37.608 ;
     RECT  6.035 97.248 7.081 98.952 ;
     RECT  7.004 116.112 7.093 119.736 ;
     RECT  6.617 120.72 7.093 121.032 ;
     RECT  6.275 41.952 7.141 42.696 ;
     RECT  6.613 43.92 7.141 44.472 ;
     RECT  6.865 104.784 7.189 108.168 ;
     RECT  6.181 109.2 7.189 109.416 ;
     RECT  4.129 72.672 7.261 72.696 ;
     RECT  6.401 74.304 7.261 74.328 ;
     RECT  5.789 11.904 7.292 11.976 ;
     RECT  7.081 31.488 7.333 37.608 ;
     RECT  6.545 38.928 7.333 38.952 ;
     RECT  6.563 56.112 7.429 57.624 ;
     RECT  6.611 70.8 7.429 70.824 ;
     RECT  6.901 93.456 7.429 94.248 ;
     RECT  6.277 23.328 7.477 24.792 ;
     RECT  6.757 25.824 7.477 26.76 ;
     RECT  7.333 31.488 7.477 38.952 ;
     RECT  6.901 27.744 7.549 30.408 ;
     RECT  7.477 31.392 7.549 38.952 ;
     RECT  6.716 89.952 7.573 90.648 ;
     RECT  6.329 122.256 7.631 122.28 ;
     RECT  7.261 72.672 7.765 74.328 ;
     RECT  7.573 89.328 7.801 90.648 ;
     RECT  6.401 10.32 7.808 10.344 ;
     RECT  7.292 11.856 7.808 11.976 ;
     RECT  7.649 13.104 7.808 13.128 ;
     RECT  5.897 18.048 7.808 18.216 ;
     RECT  7.045 19.248 7.808 19.272 ;
     RECT  6.689 21.312 7.808 22.056 ;
     RECT  7.477 23.328 7.808 26.76 ;
     RECT  7.549 27.744 7.808 38.952 ;
     RECT  6.545 40.416 7.808 40.632 ;
     RECT  7.141 41.952 7.808 44.472 ;
     RECT  6.329 45.696 7.808 46.44 ;
     RECT  7.009 48 7.808 54.168 ;
     RECT  7.429 55.968 7.808 57.624 ;
     RECT  6.659 58.656 7.808 59.256 ;
     RECT  6.901 60.24 7.808 62.184 ;
     RECT  6.371 64.32 7.808 64.344 ;
     RECT  5.933 65.952 7.808 66.12 ;
     RECT  6.937 67.104 7.808 67.368 ;
     RECT  6.563 69.168 7.808 69.192 ;
     RECT  7.429 70.416 7.808 70.824 ;
     RECT  7.765 72.672 7.808 74.616 ;
     RECT  6.853 78.624 7.808 79.848 ;
     RECT  6.937 83.232 7.808 83.256 ;
     RECT  6.517 84.816 7.808 84.84 ;
     RECT  7.669 85.92 7.808 85.944 ;
     RECT  6.797 88.128 7.808 88.2 ;
     RECT  7.801 89.328 7.808 91.08 ;
     RECT  7.429 92.832 7.808 94.584 ;
     RECT  7.081 97.248 7.808 99.048 ;
     RECT  6.757 100.08 7.808 101.448 ;
     RECT  6.509 103.008 7.808 103.512 ;
     RECT  7.189 104.784 7.808 109.416 ;
     RECT  6.733 115.104 7.808 115.128 ;
     RECT  7.093 116.112 7.808 121.032 ;
     RECT  7.631 122.256 7.808 122.52 ;
     RECT  7.585 125.424 7.808 125.448 ;
     RECT  7.808 2.148 7.912 127.452 ;
     RECT  7.912 2.418 8.104 127.182 ;
     RECT  8.104 11.952 8.165 11.976 ;
     RECT  8.104 64.128 8.165 65.976 ;
     RECT  8.104 44.928 8.201 63.096 ;
     RECT  8.104 67.104 8.201 67.8 ;
     RECT  8.104 99.984 8.237 109.416 ;
     RECT  8.104 25.104 8.243 37.992 ;
     RECT  8.104 81.168 8.243 81.192 ;
     RECT  8.104 82.944 8.243 83.256 ;
     RECT  8.104 90 8.243 91.08 ;
     RECT  8.201 44.928 8.245 49.992 ;
     RECT  8.104 121.968 8.245 122.52 ;
     RECT  8.104 22.032 8.273 22.44 ;
     RECT  8.237 99.984 8.273 107.304 ;
     RECT  8.104 96.048 8.291 96.072 ;
     RECT  8.104 97.344 8.291 98.952 ;
     RECT  8.104 40.704 8.345 41.976 ;
     RECT  8.165 64.128 8.381 65.4 ;
     RECT  8.104 119.952 8.381 120.504 ;
     RECT  8.201 50.976 8.387 63.096 ;
     RECT  8.273 99.984 8.387 107.256 ;
     RECT  8.243 25.104 8.428 36.024 ;
     RECT  8.104 92.304 8.435 92.328 ;
     RECT  8.237 108.864 8.461 109.416 ;
     RECT  8.387 51.312 8.531 63.096 ;
     RECT  8.243 37.008 8.561 37.992 ;
     RECT  8.428 28.512 8.633 36.024 ;
     RECT  8.245 44.928 8.777 49.896 ;
     RECT  8.633 28.752 8.813 36.024 ;
     RECT  8.243 90 8.849 90.456 ;
     RECT  8.104 13.584 8.867 13.608 ;
     RECT  8.104 43.296 8.915 43.752 ;
     RECT  8.104 116.544 8.921 117.432 ;
     RECT  8.345 40.704 8.956 41.64 ;
     RECT  8.387 102.24 8.963 107.256 ;
     RECT  8.531 51.312 9.065 58.968 ;
     RECT  8.273 22.416 9.169 22.44 ;
     RECT  8.428 25.104 9.173 26.856 ;
     RECT  8.381 64.848 9.173 65.4 ;
     RECT  8.104 70.8 9.205 71.448 ;
     RECT  8.104 72.48 9.205 75.48 ;
     RECT  8.921 117.408 9.205 117.432 ;
     RECT  8.104 19.248 9.209 19.272 ;
     RECT  8.777 49.056 9.241 49.896 ;
     RECT  8.531 60.384 9.245 63.096 ;
     RECT  9.169 22.416 9.277 23.064 ;
     RECT  8.201 67.152 9.277 67.8 ;
     RECT  9.277 22.224 9.281 23.064 ;
     RECT  8.561 37.008 9.317 37.608 ;
     RECT  9.173 65.376 9.317 65.4 ;
     RECT  8.104 10.32 9.395 10.344 ;
     RECT  8.381 119.952 9.421 120.264 ;
     RECT  9.349 92.352 9.433 92.376 ;
     RECT  9.349 21.12 9.461 21.144 ;
     RECT  8.963 102.24 9.461 103.656 ;
     RECT  9.245 60.96 9.493 63.096 ;
     RECT  9.277 66.72 9.493 67.8 ;
     RECT  9.281 22.224 9.529 22.584 ;
     RECT  8.813 28.752 9.533 28.776 ;
     RECT  8.104 76.992 9.557 77.016 ;
     RECT  9.205 70.8 9.561 75.48 ;
     RECT  9.065 51.936 9.565 58.968 ;
     RECT  9.561 75.264 9.589 75.48 ;
     RECT  9.557 76.848 9.589 77.016 ;
     RECT  8.104 85.92 9.601 85.944 ;
     RECT  9.421 119.952 9.601 120.84 ;
     RECT  9.589 75.264 9.676 77.016 ;
     RECT  9.561 70.8 9.683 73.656 ;
     RECT  9.173 25.2 9.709 26.856 ;
     RECT  8.104 94.56 9.713 94.584 ;
     RECT  8.956 41.616 9.745 41.64 ;
     RECT  8.245 122.496 9.749 122.52 ;
     RECT  9.133 39.888 9.781 40.44 ;
     RECT  9.683 72.72 9.785 73.656 ;
     RECT  9.205 117.408 9.785 118.584 ;
     RECT  9.709 25.2 9.817 27.096 ;
     RECT  9.785 73.632 9.821 73.656 ;
     RECT  9.676 75.264 9.821 75.288 ;
     RECT  9.785 117.408 9.821 118.152 ;
     RECT  9.493 66.096 9.827 67.8 ;
     RECT  8.777 44.928 9.889 47.88 ;
     RECT  9.241 49.056 9.889 50.184 ;
     RECT  9.817 25.2 9.925 27.24 ;
     RECT  8.243 82.944 9.929 82.968 ;
     RECT  8.387 99.984 9.961 101.208 ;
     RECT  9.461 102.48 9.961 103.656 ;
     RECT  8.963 104.784 9.961 107.256 ;
     RECT  9.601 119.952 9.965 121.176 ;
     RECT  9.565 51.936 10.019 59.88 ;
     RECT  9.889 44.928 10.069 50.184 ;
     RECT  10.069 44.448 10.141 50.184 ;
     RECT  9.529 21.168 10.145 22.584 ;
     RECT  9.317 37.584 10.163 37.608 ;
     RECT  10.105 94.08 10.189 94.104 ;
     RECT  10.105 51.888 10.211 51.912 ;
     RECT  9.965 119.952 10.213 120.84 ;
     RECT  10.213 119.664 10.217 120.84 ;
     RECT  10.019 52.896 10.249 59.88 ;
     RECT  9.493 60.96 10.249 63.96 ;
     RECT  9.925 25.2 10.261 27.624 ;
     RECT  9.781 39.456 10.261 40.44 ;
     RECT  9.745 41.616 10.261 42.264 ;
     RECT  8.104 88.128 10.261 88.2 ;
     RECT  8.813 29.76 10.289 36.024 ;
     RECT  10.249 52.896 10.289 63.96 ;
     RECT  9.676 76.992 10.289 77.016 ;
     RECT  10.22 19.776 10.307 19.8 ;
     RECT  10.261 39.456 10.307 42.264 ;
     RECT  9.961 102.48 10.307 107.256 ;
     RECT  10.145 22.56 10.321 22.584 ;
     RECT  10.249 23.568 10.321 23.592 ;
     RECT  10.141 44.448 10.325 50.76 ;
     RECT  10.217 119.664 10.325 120.072 ;
     RECT  10.261 88.128 10.348 88.344 ;
     RECT  10.307 40.656 10.357 42.264 ;
     RECT  8.915 43.296 10.357 43.32 ;
     RECT  8.291 97.536 10.357 98.952 ;
     RECT  9.961 99.984 10.357 101.448 ;
     RECT  10.289 29.856 10.361 36.024 ;
     RECT  9.821 117.84 10.361 118.152 ;
     RECT  10.321 22.56 10.364 23.592 ;
     RECT  8.461 109.392 10.364 109.416 ;
     RECT  10.361 118.128 10.397 118.152 ;
     RECT  10.364 22.56 10.405 23.736 ;
     RECT  10.261 25.056 10.405 27.624 ;
     RECT  10.364 109.392 10.451 110.328 ;
     RECT  10.145 21.168 10.469 21.576 ;
     RECT  10.357 40.656 10.469 43.32 ;
     RECT  10.307 102.48 10.501 103.704 ;
     RECT  10.361 30.576 10.537 36.024 ;
     RECT  9.827 66.096 10.537 66.12 ;
     RECT  8.104 78.624 10.541 79.512 ;
     RECT  8.849 90.432 10.547 90.456 ;
     RECT  10.348 88.128 10.613 88.2 ;
     RECT  10.469 41.952 10.645 43.32 ;
     RECT  10.325 44.448 10.645 47.88 ;
     RECT  10.469 40.656 10.682 40.728 ;
     RECT  10.307 39.456 10.748 39.576 ;
     RECT  10.537 30.576 10.757 36.072 ;
     RECT  10.289 55.248 10.789 63.96 ;
     RECT  10.789 55.248 10.825 64.152 ;
     RECT  10.537 65.712 10.825 66.12 ;
     RECT  10.717 74.448 10.829 74.472 ;
     RECT  10.748 38.688 10.835 39.576 ;
     RECT  10.357 97.536 10.837 101.448 ;
     RECT  10.501 102.432 10.837 103.704 ;
     RECT  9.683 70.8 10.861 71.688 ;
     RECT  9.827 67.248 10.865 67.8 ;
     RECT  10.753 76.32 10.865 76.344 ;
     RECT  10.325 120 10.865 120.072 ;
     RECT  10.825 55.248 10.897 66.12 ;
     RECT  10.865 67.248 10.897 67.416 ;
     RECT  10.393 122.064 11.029 122.088 ;
     RECT  10.865 120.048 11.045 120.072 ;
     RECT  11.029 121.344 11.075 122.088 ;
     RECT  10.451 109.392 11.257 109.416 ;
     RECT  10.405 22.56 11.261 27.624 ;
     RECT  11.075 121.344 11.293 121.368 ;
     RECT  10.757 32.448 11.297 36.072 ;
     RECT  11.257 109.248 11.297 109.416 ;
     RECT  11.261 22.56 11.333 24.168 ;
     RECT  11.293 120.096 11.333 121.368 ;
     RECT  10.289 52.896 11.365 54.216 ;
     RECT  10.897 55.248 11.365 67.416 ;
     RECT  10.469 21.168 11.401 21.432 ;
     RECT  10.325 49.056 11.401 50.76 ;
     RECT  11.297 32.448 11.405 36.024 ;
     RECT  11.333 120.096 11.411 120.888 ;
     RECT  10.645 41.952 11.413 47.88 ;
     RECT  11.405 35.664 11.441 36.024 ;
     RECT  11.413 41.952 11.441 47.928 ;
     RECT  11.365 52.896 11.513 67.416 ;
     RECT  11.261 25.296 11.549 27.624 ;
     RECT  11.401 49.056 11.557 51.672 ;
     RECT  11.513 52.896 11.585 63.24 ;
     RECT  9.601 85.92 11.617 86.328 ;
     RECT  10.613 88.176 11.617 88.2 ;
     RECT  11.411 120.096 11.621 120.12 ;
     RECT  11.612 28.896 11.699 28.92 ;
     RECT  11.513 64.32 11.699 67.416 ;
     RECT  11.549 25.488 11.725 27.624 ;
     RECT  11.725 25.488 11.765 27.864 ;
     RECT  11.441 44.88 11.833 47.928 ;
     RECT  11.557 48.912 11.833 51.672 ;
     RECT  10.757 30.576 11.869 31.464 ;
     RECT  11.405 32.448 11.869 34.248 ;
     RECT  10.682 40.656 11.873 40.68 ;
     RECT  11.833 44.88 11.901 51.672 ;
     RECT  10.837 97.536 11.909 103.704 ;
     RECT  11.901 46.176 11.917 51.672 ;
     RECT  8.104 84.816 11.941 84.84 ;
     RECT  11.441 41.952 11.945 43.32 ;
     RECT  11.585 52.896 11.977 61.944 ;
     RECT  11.617 85.92 11.987 88.2 ;
     RECT  11.401 21.072 12.049 21.432 ;
     RECT  11.917 49.056 12.085 51.672 ;
     RECT  11.765 26.64 12.089 27.864 ;
     RECT  12.049 21.072 12.193 21.48 ;
     RECT  10.835 39.264 12.337 39.576 ;
     RECT  11.221 37.056 12.409 37.08 ;
     RECT  11.765 25.488 12.517 25.56 ;
     RECT  12.409 37.056 12.517 37.704 ;
     RECT  12.337 38.688 12.517 39.576 ;
     RECT  11.333 23.52 12.589 24.168 ;
     RECT  12.517 25.296 12.589 25.56 ;
     RECT  11.945 41.952 12.661 41.976 ;
     RECT  12.193 21.072 12.733 21.528 ;
     RECT  11.221 75.792 12.733 75.816 ;
     RECT  12.733 75.792 12.841 75.96 ;
     RECT  12.805 74.64 12.877 74.664 ;
     RECT  12.661 41.76 12.908 41.976 ;
     RECT  11.945 43.296 12.908 43.32 ;
     RECT  11.585 62.928 12.913 63.24 ;
     RECT  11.699 64.32 12.913 66.744 ;
     RECT  11.901 44.88 12.941 44.904 ;
     RECT  11.917 46.176 12.941 47.832 ;
     RECT  11.869 30.576 12.949 34.248 ;
     RECT  11.977 52.752 12.949 61.944 ;
     RECT  12.913 62.928 12.949 66.744 ;
     RECT  12.941 44.88 12.977 47.832 ;
     RECT  12.085 49.056 12.977 51.768 ;
     RECT  12.589 23.52 12.985 25.56 ;
     RECT  11.441 36 12.985 36.024 ;
     RECT  12.517 37.056 12.985 39.576 ;
     RECT  12.085 78.336 12.985 78.36 ;
     RECT  10.541 79.488 12.985 79.512 ;
     RECT  12.733 20.352 13.021 21.528 ;
     RECT  12.985 36 13.057 39.576 ;
     RECT  12.908 41.76 13.093 43.32 ;
     RECT  13.057 18.96 13.129 18.984 ;
     RECT  12.977 44.88 13.129 51.768 ;
     RECT  12.949 52.752 13.129 66.744 ;
     RECT  12.985 23.28 13.165 25.56 ;
     RECT  10.861 70.8 13.165 72.264 ;
     RECT  12.949 29.616 13.201 34.248 ;
     RECT  13.129 18.816 13.208 18.984 ;
     RECT  13.021 20.304 13.208 21.528 ;
     RECT  13.165 23.136 13.208 25.56 ;
     RECT  12.089 27.168 13.208 27.864 ;
     RECT  13.201 29.616 13.208 34.44 ;
     RECT  13.057 36 13.208 40.152 ;
     RECT  13.093 41.76 13.208 43.368 ;
     RECT  13.129 44.88 13.208 66.744 ;
     RECT  13.165 70.368 13.208 72.264 ;
     RECT  12.877 74.304 13.208 74.664 ;
     RECT  12.841 75.792 13.208 76.392 ;
     RECT  12.985 78.336 13.208 79.512 ;
     RECT  9.961 83.52 13.208 83.544 ;
     RECT  11.941 84.816 13.208 84.936 ;
     RECT  11.987 85.92 13.208 86.328 ;
     RECT  11.987 88.176 13.208 88.2 ;
     RECT  11.909 97.68 13.208 103.704 ;
     RECT  10.307 104.784 13.208 106.728 ;
     RECT  11.297 109.248 13.208 109.272 ;
     RECT  13.208 2.148 13.312 127.452 ;
     RECT  13.312 2.418 13.504 127.182 ;
     RECT  13.504 37.056 13.565 64.152 ;
     RECT  13.565 37.44 13.601 64.152 ;
     RECT  13.504 29.616 13.619 36.024 ;
     RECT  13.504 65.232 13.619 66.36 ;
     RECT  13.601 39.552 13.637 64.152 ;
     RECT  13.619 29.712 13.709 36.024 ;
     RECT  13.637 39.552 13.811 42.456 ;
     RECT  13.504 97.776 13.811 103.752 ;
     RECT  13.504 77.184 13.925 77.592 ;
     RECT  13.504 19.92 13.961 27.192 ;
     RECT  13.811 39.552 14.284 41.448 ;
     RECT  13.811 97.776 14.285 103.032 ;
     RECT  13.601 37.44 14.357 38.28 ;
     RECT  13.961 19.92 14.393 21.24 ;
     RECT  13.637 43.728 14.531 64.152 ;
     RECT  13.619 65.232 14.531 66.264 ;
     RECT  14.531 46.176 14.537 64.152 ;
     RECT  13.504 78.624 14.537 79.512 ;
     RECT  13.961 22.32 14.645 27.192 ;
     RECT  13.504 75.936 14.677 75.96 ;
     RECT  13.811 42.432 14.713 42.456 ;
     RECT  14.531 43.728 14.713 44.952 ;
     RECT  13.709 30.144 14.753 36.024 ;
     RECT  14.537 46.704 14.753 64.152 ;
     RECT  14.753 46.704 14.761 48.792 ;
     RECT  14.357 37.44 14.773 38.184 ;
     RECT  14.531 66.144 14.819 66.264 ;
     RECT  14.753 50.304 14.861 64.152 ;
     RECT  14.677 75.936 14.861 76.776 ;
     RECT  14.713 42.432 14.897 44.952 ;
     RECT  14.393 19.92 14.929 20.664 ;
     RECT  13.504 84.816 14.933 86.328 ;
     RECT  13.504 70.368 15.005 72.264 ;
     RECT  14.861 50.64 15.073 64.152 ;
     RECT  14.897 43.824 15.077 44.952 ;
     RECT  15.005 70.368 15.077 70.728 ;
     RECT  14.645 22.32 15.185 26.952 ;
     RECT  15.005 72.24 15.185 72.264 ;
     RECT  14.929 19.536 15.289 20.664 ;
     RECT  14.285 97.776 15.317 98.952 ;
     RECT  15.289 19.488 15.361 20.664 ;
     RECT  15.317 96.912 15.401 98.952 ;
     RECT  15.361 19.44 15.433 20.664 ;
     RECT  14.773 36.528 15.473 38.184 ;
     RECT  14.929 28.992 15.505 29.016 ;
     RECT  14.753 30.144 15.505 35.16 ;
     RECT  14.284 41.424 15.505 41.448 ;
     RECT  14.897 42.432 15.505 42.696 ;
     RECT  15.077 44.928 15.505 44.952 ;
     RECT  15.548 76.992 15.635 77.016 ;
     RECT  15.077 43.824 15.653 43.848 ;
     RECT  15.073 50.64 15.757 64.584 ;
     RECT  14.284 39.552 15.761 40.152 ;
     RECT  15.757 50.64 15.829 64.92 ;
     RECT  15.185 25.584 15.833 26.952 ;
     RECT  15.185 22.32 15.905 24.504 ;
     RECT  15.433 19.248 15.937 20.664 ;
     RECT  15.865 72.432 16.009 72.456 ;
     RECT  15.505 28.992 16.013 35.16 ;
     RECT  15.829 50.64 16.049 64.968 ;
     RECT  16.013 34.8 16.067 35.16 ;
     RECT  15.937 19.248 16.085 21.24 ;
     RECT  16.013 28.992 16.156 33.72 ;
     RECT  15.505 41.424 16.189 42.696 ;
     RECT  13.504 109.248 16.193 109.272 ;
     RECT  15.473 36.528 16.225 36.792 ;
     RECT  15.905 23.28 16.261 24.504 ;
     RECT  15.833 25.584 16.261 25.608 ;
     RECT  16.049 50.64 16.265 64.92 ;
     RECT  16.085 19.44 16.301 21.24 ;
     RECT  16.009 72.432 16.301 73.224 ;
     RECT  14.861 75.936 16.319 75.96 ;
     RECT  16.301 72.432 16.333 72.984 ;
     RECT  14.761 46.752 16.337 48.792 ;
     RECT  15.833 26.736 16.369 26.952 ;
     RECT  14.819 66.24 16.369 66.264 ;
     RECT  16.319 75.792 16.373 75.96 ;
     RECT  16.316 74.352 16.403 74.376 ;
     RECT  16.067 34.944 16.405 35.16 ;
     RECT  15.473 38.16 16.441 38.184 ;
     RECT  16.369 66 16.441 66.264 ;
     RECT  16.441 65.952 16.477 66.264 ;
     RECT  16.405 34.944 16.517 35.352 ;
     RECT  16.333 72 16.549 72.984 ;
     RECT  16.265 50.64 16.553 52.488 ;
     RECT  16.265 54.096 16.553 64.92 ;
     RECT  16.225 36.48 16.589 36.792 ;
     RECT  16.549 71.808 16.595 72.984 ;
     RECT  16.595 72.96 16.625 72.984 ;
     RECT  16.189 40.608 16.657 42.696 ;
     RECT  16.337 46.944 16.661 48.792 ;
     RECT  16.156 33.504 16.697 33.72 ;
     RECT  16.657 40.608 16.729 42.744 ;
     RECT  15.505 44.928 16.801 45.288 ;
     RECT  16.373 75.792 16.913 75.816 ;
     RECT  16.261 23.28 16.94 25.608 ;
     RECT  16.729 40.608 16.981 43.368 ;
     RECT  16.156 28.992 17.017 32.472 ;
     RECT  16.94 23.232 17.027 25.608 ;
     RECT  16.369 26.736 17.053 27.384 ;
     RECT  17.017 28.416 17.053 32.472 ;
     RECT  16.553 64.848 17.077 64.92 ;
     RECT  16.477 65.952 17.077 66.84 ;
     RECT  17.027 23.28 17.093 25.608 ;
     RECT  16.697 33.696 17.093 33.72 ;
     RECT  17.093 23.952 17.111 25.608 ;
     RECT  16.553 54.096 17.129 63.864 ;
     RECT  17.111 23.952 17.173 25.656 ;
     RECT  17.053 26.736 17.173 32.472 ;
     RECT  17.173 23.952 17.237 32.472 ;
     RECT  16.301 19.44 17.269 21.144 ;
     RECT  17.237 23.952 17.273 23.976 ;
     RECT  16.981 40.416 17.413 43.368 ;
     RECT  16.801 44.448 17.413 45.288 ;
     RECT  16.553 50.64 17.413 52.296 ;
     RECT  17.129 54.096 17.413 61.656 ;
     RECT  17.237 25.248 17.453 32.472 ;
     RECT  17.413 50.4 17.485 52.296 ;
     RECT  17.269 19.392 17.561 21.144 ;
     RECT  17.077 64.848 17.597 67.752 ;
     RECT  17.597 64.848 17.633 65.352 ;
     RECT  16.661 47.376 17.665 48.792 ;
     RECT  17.485 49.872 17.665 52.296 ;
     RECT  17.413 40.416 17.701 45.288 ;
     RECT  16.517 35.04 17.737 35.352 ;
     RECT  16.589 36.48 17.737 36.552 ;
     RECT  16.441 38.16 17.737 38.76 ;
     RECT  17.597 66.48 17.773 67.752 ;
     RECT  13.504 82.416 17.852 82.44 ;
     RECT  13.504 83.52 17.852 83.544 ;
     RECT  17.701 40.368 17.953 45.288 ;
     RECT  17.737 35.04 18.025 36.552 ;
     RECT  17.737 38.16 18.025 39.24 ;
     RECT  17.665 47.376 18.061 52.296 ;
     RECT  17.413 53.568 18.133 61.656 ;
     RECT  17.129 62.688 18.133 63.864 ;
     RECT  18.025 35.04 18.205 39.24 ;
     RECT  17.953 40.368 18.205 46.248 ;
     RECT  17.453 25.248 18.241 27.336 ;
     RECT  18.061 47.376 18.277 52.44 ;
     RECT  18.133 53.568 18.277 63.864 ;
     RECT  18.205 35.04 18.349 46.248 ;
     RECT  18.241 25.2 18.457 27.336 ;
     RECT  17.453 28.416 18.457 32.472 ;
     RECT  17.561 19.44 18.608 21.144 ;
     RECT  18.457 25.2 18.608 32.472 ;
     RECT  18.241 33.6 18.608 33.624 ;
     RECT  18.349 34.656 18.608 46.248 ;
     RECT  18.277 47.376 18.608 63.864 ;
     RECT  17.633 65.232 18.608 65.352 ;
     RECT  17.773 66.48 18.608 68.232 ;
     RECT  15.077 70.368 18.608 70.392 ;
     RECT  16.595 71.808 18.608 71.832 ;
     RECT  14.537 79.488 18.608 79.512 ;
     RECT  17.701 80.592 18.608 80.616 ;
     RECT  17.852 82.416 18.608 83.544 ;
     RECT  14.933 84.912 18.608 86.328 ;
     RECT  13.504 88.176 18.608 88.2 ;
     RECT  15.401 97.776 18.608 98.952 ;
     RECT  14.285 99.984 18.608 103.032 ;
     RECT  13.504 104.784 18.608 106.728 ;
     RECT  18.608 2.148 18.712 127.452 ;
     RECT  18.712 2.418 18.904 127.182 ;
     RECT  18.904 19.584 19.001 23.352 ;
     RECT  18.904 36.528 19.073 39.144 ;
     RECT  18.904 84.912 19.091 84.936 ;
     RECT  18.904 24.48 19.145 32.808 ;
     RECT  18.904 34.08 19.145 35.448 ;
     RECT  18.904 82.656 19.181 83.688 ;
     RECT  18.904 85.92 19.181 89.352 ;
     RECT  18.904 80.496 19.225 80.952 ;
     RECT  19.181 85.92 19.225 88.872 ;
     RECT  19.181 82.752 19.245 83.688 ;
     RECT  18.904 78.672 19.283 79.512 ;
     RECT  19.225 85.92 19.283 86.616 ;
     RECT  19.245 82.752 19.379 83.544 ;
     RECT  18.904 90.576 19.379 90.6 ;
     RECT  18.904 40.368 19.433 63.864 ;
     RECT  18.904 64.944 19.469 68.232 ;
     RECT  19.225 80.496 19.469 80.52 ;
     RECT  19.283 85.92 19.469 86.328 ;
     RECT  19.001 21.696 19.505 23.352 ;
     RECT  19.283 78.864 19.505 79.512 ;
     RECT  19.433 40.368 19.541 63.816 ;
     RECT  19.145 34.656 19.757 35.448 ;
     RECT  19.073 36.96 19.811 39.144 ;
     RECT  19.541 40.368 19.865 52.488 ;
     RECT  19.757 35.04 19.897 35.448 ;
     RECT  19.811 37.776 19.933 39.144 ;
     RECT  19.865 40.368 19.933 49.608 ;
     RECT  19.145 24.48 20.081 27.96 ;
     RECT  20.081 27.12 20.245 27.96 ;
     RECT  19.145 28.944 20.245 32.808 ;
     RECT  18.904 99.984 20.257 103.032 ;
     RECT  18.904 104.208 20.257 106.728 ;
     RECT  19.001 19.584 20.329 20.616 ;
     RECT  19.505 21.744 20.473 23.352 ;
     RECT  20.081 24.48 20.473 26.088 ;
     RECT  19.541 53.808 20.473 63.816 ;
     RECT  19.469 64.944 20.473 64.968 ;
     RECT  19.469 66.48 20.509 68.232 ;
     RECT  20.509 66.192 20.545 68.232 ;
     RECT  20.329 19.584 20.581 20.76 ;
     RECT  20.473 21.744 20.581 26.088 ;
     RECT  19.865 51.024 20.581 52.488 ;
     RECT  20.473 53.808 20.581 64.968 ;
     RECT  20.581 19.584 20.585 26.088 ;
     RECT  19.469 86.304 20.689 86.328 ;
     RECT  19.225 87.792 20.689 88.872 ;
     RECT  20.245 27.12 20.765 32.808 ;
     RECT  20.689 86.304 20.773 89.112 ;
     RECT  20.773 88.176 20.819 89.112 ;
     RECT  20.585 19.584 21.049 25.656 ;
     RECT  20.581 51.024 21.049 64.968 ;
     RECT  19.933 37.776 21.085 49.608 ;
     RECT  21.049 50.736 21.085 65.16 ;
     RECT  21.049 19.392 21.125 25.656 ;
     RECT  19.897 35.04 21.265 35.88 ;
     RECT  18.904 70.368 21.395 70.392 ;
     RECT  21.085 37.776 21.517 65.16 ;
     RECT  20.545 66.192 21.517 68.424 ;
     RECT  20.765 27.984 21.589 32.808 ;
     RECT  21.265 34.752 21.625 35.88 ;
     RECT  21.517 37.776 21.661 68.424 ;
     RECT  21.589 27.984 21.877 33.288 ;
     RECT  19.379 83.52 21.923 83.544 ;
     RECT  21.877 27.072 21.949 33.288 ;
     RECT  21.625 34.752 21.949 36.168 ;
     RECT  20.773 86.304 21.971 86.328 ;
     RECT  21.125 19.392 22.201 21 ;
     RECT  21.125 21.984 22.201 25.656 ;
     RECT  21.661 37.776 22.201 68.616 ;
     RECT  22.201 19.392 22.357 25.656 ;
     RECT  21.949 27.072 22.357 36.168 ;
     RECT  18.904 97.776 22.525 99 ;
     RECT  20.257 99.984 22.525 106.728 ;
     RECT  22.357 19.392 22.529 36.168 ;
     RECT  22.529 20.016 22.565 36.168 ;
     RECT  22.565 23.28 22.896 36.168 ;
     RECT  22.201 37.68 22.896 68.616 ;
     RECT  22.896 23.28 22.968 68.616 ;
     RECT  19.505 79.488 22.968 79.512 ;
     RECT  20.819 88.176 22.968 88.2 ;
     RECT  22.525 97.776 22.968 106.728 ;
     RECT  22.565 20.016 22.997 22.248 ;
     RECT  22.968 23.28 23.141 106.728 ;
     RECT  22.997 20.16 24.008 21.96 ;
     RECT  23.141 23.28 24.008 27.096 ;
     RECT  23.141 28.08 24.008 106.728 ;
     RECT  24.008 2.148 24.112 27.096 ;
     RECT  24.008 28.08 24.145 127.452 ;
     RECT  24.112 2.418 24.304 27.096 ;
     RECT  24.145 28.08 24.304 127.944 ;
     RECT  24.304 19.92 24.581 27.096 ;
     RECT  24.581 21.264 25.265 27.096 ;
     RECT  24.581 19.92 25.369 20.184 ;
     RECT  25.265 21.408 25.373 27.096 ;
     RECT  25.373 22.224 26.449 27.096 ;
     RECT  26.449 21.792 26.521 27.096 ;
     RECT  26.521 21.312 26.629 27.096 ;
     RECT  25.369 19.248 26.737 20.184 ;
     RECT  26.629 21.264 26.737 27.096 ;
     RECT  24.304 28.08 27.059 106.728 ;
     RECT  26.737 19.248 27.533 27.096 ;
     RECT  27.533 19.248 28.289 20.088 ;
     RECT  27.533 21.312 28.289 27.096 ;
     RECT  28.289 21.312 28.397 21.816 ;
     RECT  28.289 19.872 28.681 20.088 ;
     RECT  28.397 21.408 29.365 21.816 ;
     RECT  29.365 21.408 29.401 21.96 ;
     RECT  28.681 19.872 29.408 20.136 ;
     RECT  29.401 21.168 29.408 21.96 ;
     RECT  28.289 23.04 29.408 27.096 ;
     RECT  27.059 28.08 29.408 103.368 ;
     RECT  27.059 104.832 29.408 106.728 ;
     RECT  27.013 108.432 29.408 108.456 ;
     RECT  24.304 127.92 29.408 127.944 ;
     RECT  29.408 2.148 29.512 27.096 ;
     RECT  29.512 2.418 29.704 27.096 ;
     RECT  29.408 28.08 29.704 127.944 ;
     RECT  29.704 19.776 31.187 27.096 ;
     RECT  31.187 23.376 31.241 27.096 ;
     RECT  31.187 19.776 31.385 22.008 ;
     RECT  31.241 23.52 31.457 27.096 ;
     RECT  31.385 19.824 31.859 22.008 ;
     RECT  31.859 20.064 32.281 22.008 ;
     RECT  31.457 23.664 32.569 27.096 ;
     RECT  32.569 23.568 32.641 27.096 ;
     RECT  32.641 23.328 33.635 27.096 ;
     RECT  32.281 20.064 33.973 22.056 ;
     RECT  33.973 20.064 34.808 22.248 ;
     RECT  33.635 23.568 34.808 27.096 ;
     RECT  29.704 28.08 34.808 103.368 ;
     RECT  29.704 104.832 34.808 106.728 ;
     RECT  29.704 108.576 34.808 108.6 ;
     RECT  29.704 127.92 34.808 127.944 ;
     RECT  34.808 2.148 34.912 27.096 ;
     RECT  34.912 2.418 35.104 27.096 ;
     RECT  34.808 28.08 35.104 127.944 ;
     RECT  35.104 19.872 36.083 23.352 ;
     RECT  36.083 20.064 36.173 23.352 ;
     RECT  35.104 24.432 36.389 27.096 ;
     RECT  36.173 23.328 36.677 23.352 ;
     RECT  35.104 28.08 37.141 103.368 ;
     RECT  35.104 104.832 37.141 106.728 ;
     RECT  37.105 23.664 37.825 23.688 ;
     RECT  36.173 20.064 37.897 22.008 ;
     RECT  37.825 23.088 37.897 23.688 ;
     RECT  37.897 20.064 37.973 23.688 ;
     RECT  37.973 21.936 38.297 23.688 ;
     RECT  36.389 24.96 38.401 27.096 ;
     RECT  38.297 21.984 38.437 23.688 ;
     RECT  38.401 24.72 38.437 27.096 ;
     RECT  38.437 21.984 38.621 27.096 ;
     RECT  38.621 22.08 38.801 27.096 ;
     RECT  37.973 20.064 40.208 20.952 ;
     RECT  38.801 22.464 40.208 27.096 ;
     RECT  37.141 28.08 40.208 106.728 ;
     RECT  35.104 108.576 40.208 108.6 ;
     RECT  35.104 127.92 40.208 127.944 ;
     RECT  40.208 2.148 40.312 27.096 ;
     RECT  40.312 2.418 40.504 27.096 ;
     RECT  40.208 28.08 40.504 127.944 ;
     RECT  40.504 24.432 40.601 27.096 ;
     RECT  40.504 20.592 41.213 22.776 ;
     RECT  41.213 20.592 41.393 22.584 ;
     RECT  41.393 20.592 41.429 22.488 ;
     RECT  40.601 24.624 42.037 27.096 ;
     RECT  41.429 20.592 42.113 21.624 ;
     RECT  42.113 20.976 42.653 21.624 ;
     RECT  42.505 22.752 42.757 22.776 ;
     RECT  42.757 22.752 42.793 23.4 ;
     RECT  42.037 24.48 42.793 27.096 ;
     RECT  42.793 22.752 42.802 27.096 ;
     RECT  42.653 20.976 42.833 21.24 ;
     RECT  40.504 28.08 43.763 106.728 ;
     RECT  42.802 22.704 43.805 27.096 ;
     RECT  40.504 108.576 43.913 108.6 ;
     RECT  42.833 20.976 43.981 21 ;
     RECT  43.805 22.704 44.089 23.688 ;
     RECT  44.053 108.528 44.201 108.552 ;
     RECT  43.981 20.16 44.725 21 ;
     RECT  44.725 20.16 45.608 21.144 ;
     RECT  44.089 22.224 45.608 23.688 ;
     RECT  43.805 24.912 45.608 27.096 ;
     RECT  43.763 28.08 45.608 106.44 ;
     RECT  40.504 127.92 45.608 127.944 ;
     RECT  45.608 2.148 45.712 27.096 ;
     RECT  45.712 2.418 45.904 27.096 ;
     RECT  45.608 28.08 45.904 127.944 ;
     RECT  45.904 23.04 45.929 23.688 ;
     RECT  45.904 24.864 46.073 27.096 ;
     RECT  45.904 20.16 46.433 21.72 ;
     RECT  46.433 20.16 46.505 21.384 ;
     RECT  45.929 23.04 46.613 23.352 ;
     RECT  46.505 20.16 47.045 20.472 ;
     RECT  47.045 20.448 47.509 20.472 ;
     RECT  46.073 24.912 47.689 27.096 ;
     RECT  47.509 20.448 47.693 21.432 ;
     RECT  46.613 23.328 47.833 23.352 ;
     RECT  47.689 24.336 47.833 27.096 ;
     RECT  47.693 20.448 48.089 21.384 ;
     RECT  47.833 23.328 48.625 27.096 ;
     RECT  48.625 23.28 48.733 27.096 ;
     RECT  48.089 21.36 48.841 21.384 ;
     RECT  48.733 22.56 48.841 27.096 ;
     RECT  48.841 21.36 48.917 27.096 ;
     RECT  48.917 21.36 48.953 23.352 ;
     RECT  48.953 21.888 49.009 23.352 ;
     RECT  49.009 21.888 49.313 23.304 ;
     RECT  49.313 21.888 50.281 23.208 ;
     RECT  50.281 21.456 50.317 23.208 ;
     RECT  48.917 24.336 50.317 27.096 ;
     RECT  50.317 21.456 51.008 27.096 ;
     RECT  45.904 28.08 51.008 106.44 ;
     RECT  47.365 117.072 51.008 117.096 ;
     RECT  45.904 127.92 51.008 127.944 ;
     RECT  51.008 2.148 51.112 27.096 ;
     RECT  51.112 2.418 51.304 27.096 ;
     RECT  51.008 28.08 51.304 127.944 ;
     RECT  51.304 117.072 51.761 117.24 ;
     RECT  51.304 21.792 52.481 27.096 ;
     RECT  52.481 23.328 52.636 27.096 ;
     RECT  52.636 24.96 52.913 27.096 ;
     RECT  52.913 25.248 53.093 27.096 ;
     RECT  52.636 23.328 53.417 23.928 ;
     RECT  53.125 20.496 53.737 20.52 ;
     RECT  53.417 23.328 53.881 23.352 ;
     RECT  52.481 21.792 53.989 21.816 ;
     RECT  53.881 22.8 53.989 23.352 ;
     RECT  53.093 25.44 54.425 27.096 ;
     RECT  53.737 20.496 54.709 20.712 ;
     RECT  53.989 21.792 54.709 23.352 ;
     RECT  54.709 20.496 54.929 23.928 ;
     RECT  54.929 21.168 55.109 23.928 ;
     RECT  55.109 21.408 55.145 23.928 ;
     RECT  51.761 117.216 55.285 117.24 ;
     RECT  54.425 25.44 55.897 25.752 ;
     RECT  56.257 20.592 56.408 20.616 ;
     RECT  55.145 21.792 56.408 23.928 ;
     RECT  55.897 24.912 56.408 25.752 ;
     RECT  51.304 28.08 56.408 106.44 ;
     RECT  55.285 117.12 56.408 117.432 ;
     RECT  51.304 127.92 56.408 127.944 ;
     RECT  56.408 2.148 56.512 25.932 ;
     RECT  56.512 2.418 56.704 25.752 ;
     RECT  56.408 28.08 56.704 127.944 ;
     RECT  56.704 23.904 57.161 25.752 ;
     RECT  56.704 21.648 57.809 22.632 ;
     RECT  56.704 20.592 57.845 20.616 ;
     RECT  57.161 23.904 57.953 24.504 ;
     RECT  57.809 21.648 58.061 22.584 ;
     RECT  58.061 21.648 58.385 22.296 ;
     RECT  58.385 21.648 58.421 22.056 ;
     RECT  57.953 24.48 58.813 24.504 ;
     RECT  57.161 25.488 58.813 25.752 ;
     RECT  58.421 21.648 58.889 21.672 ;
     RECT  58.309 19.632 59.101 19.656 ;
     RECT  58.813 24.48 59.173 25.752 ;
     RECT  59.101 19.632 59.429 19.992 ;
     RECT  59.173 23.904 59.989 25.752 ;
     RECT  59.989 23.328 60.076 25.752 ;
     RECT  59.429 19.776 60.397 19.992 ;
     RECT  60.397 19.776 60.757 20.472 ;
     RECT  60.397 22.08 60.937 22.104 ;
     RECT  59.893 14.64 60.949 14.664 ;
     RECT  60.685 15.984 60.949 16.008 ;
     RECT  60.949 14.64 61.808 16.824 ;
     RECT  60.757 19.392 61.808 20.472 ;
     RECT  60.937 21.648 61.808 22.2 ;
     RECT  60.076 23.904 61.808 25.752 ;
     RECT  56.704 28.08 61.808 106.44 ;
     RECT  56.704 127.92 61.808 127.944 ;
     RECT  61.808 2.148 61.912 25.932 ;
     RECT  61.912 2.418 62.104 25.752 ;
     RECT  61.808 28.08 62.104 127.944 ;
     RECT  62.104 14.64 62.705 15.288 ;
     RECT  62.104 16.8 63.205 16.824 ;
     RECT  62.104 19.776 63.205 19.8 ;
     RECT  62.104 20.832 63.205 20.856 ;
     RECT  63.205 19.776 63.289 20.856 ;
     RECT  62.705 14.64 67.208 15.192 ;
     RECT  63.205 16.8 67.208 17.352 ;
     RECT  63.289 19.776 67.208 19.8 ;
     RECT  63.289 20.832 67.208 20.856 ;
     RECT  62.104 21.936 67.208 21.96 ;
     RECT  62.104 23.808 67.208 25.752 ;
     RECT  62.104 28.08 67.208 106.44 ;
     RECT  62.104 127.92 67.208 127.944 ;
     RECT  67.208 2.148 67.312 25.932 ;
     RECT  67.312 2.418 67.504 25.752 ;
     RECT  67.208 28.08 67.504 127.944 ;
     RECT  54.425 27.072 70.657 27.096 ;
     RECT  67.504 28.08 70.657 106.44 ;
     RECT  70.657 27.072 71.197 106.44 ;
     RECT  67.504 23.808 71.665 25.752 ;
     RECT  71.197 27.024 71.665 106.44 ;
     RECT  67.504 14.64 72.608 15.192 ;
     RECT  67.504 16.8 72.608 17.352 ;
     RECT  67.504 19.776 72.608 19.8 ;
     RECT  67.504 20.832 72.608 20.856 ;
     RECT  67.504 21.936 72.608 21.96 ;
     RECT  71.665 23.808 72.608 106.44 ;
     RECT  67.504 127.92 72.608 127.944 ;
     RECT  72.608 2.148 72.712 127.944 ;
     RECT  72.712 2.418 72.904 127.944 ;
     RECT  72.904 23.808 73.235 106.44 ;
     RECT  73.235 26.448 74.693 106.44 ;
     RECT  72.904 14.64 78.008 15.192 ;
     RECT  72.904 16.8 78.008 17.352 ;
     RECT  72.904 19.776 78.008 19.8 ;
     RECT  72.904 20.832 78.008 20.856 ;
     RECT  72.904 21.936 78.008 21.96 ;
     RECT  73.235 23.808 78.008 25.176 ;
     RECT  74.693 26.448 78.008 106.296 ;
     RECT  72.904 127.92 78.008 127.944 ;
     RECT  78.008 2.148 78.112 127.944 ;
     RECT  78.112 2.418 78.304 127.944 ;
     RECT  78.304 23.808 78.653 25.272 ;
     RECT  78.304 26.448 78.947 106.296 ;
     RECT  78.304 14.64 83.408 15.192 ;
     RECT  78.304 16.8 83.408 17.352 ;
     RECT  78.304 19.776 83.408 19.8 ;
     RECT  78.304 20.832 83.408 20.856 ;
     RECT  78.304 21.936 83.408 21.96 ;
     RECT  78.653 23.808 83.408 25.176 ;
     RECT  78.947 26.448 83.408 105.912 ;
     RECT  78.304 127.92 83.408 127.944 ;
     RECT  83.408 2.148 83.512 127.944 ;
     RECT  83.512 2.418 83.704 127.944 ;
     RECT  83.704 14.64 86.641 15.192 ;
     RECT  83.704 23.808 86.641 25.176 ;
     RECT  86.641 14.64 88.808 15.288 ;
     RECT  83.704 16.8 88.808 17.352 ;
     RECT  83.704 19.776 88.808 19.8 ;
     RECT  83.704 20.832 88.808 20.856 ;
     RECT  83.704 21.936 88.808 21.96 ;
     RECT  86.641 23.808 88.808 25.272 ;
     RECT  83.704 26.448 88.808 105.912 ;
     RECT  83.704 127.92 88.808 127.944 ;
     RECT  88.808 2.148 88.912 127.944 ;
     RECT  88.912 2.418 89.104 127.944 ;
     RECT  89.104 14.64 90.065 15.288 ;
     RECT  89.104 19.776 90.065 19.8 ;
     RECT  89.104 23.808 90.065 25.272 ;
     RECT  90.065 23.808 90.677 24.648 ;
     RECT  90.065 14.64 91.141 14.664 ;
     RECT  91.141 14.64 91.217 15.288 ;
     RECT  91.141 25.44 91.753 25.464 ;
     RECT  90.677 23.808 91.793 23.832 ;
     RECT  91.217 15.264 92.293 15.288 ;
     RECT  89.104 16.8 92.333 17.352 ;
     RECT  89.104 21.936 92.333 21.96 ;
     RECT  92.333 16.8 92.945 16.824 ;
     RECT  93.409 17.424 94.021 17.448 ;
     RECT  92.293 14.64 94.208 15.288 ;
     RECT  94.021 16.8 94.208 17.448 ;
     RECT  91.141 19.776 94.208 19.8 ;
     RECT  90.601 20.832 94.208 20.856 ;
     RECT  93.409 21.936 94.208 21.96 ;
     RECT  92.869 23.904 94.208 23.928 ;
     RECT  91.753 24.912 94.208 25.464 ;
     RECT  89.104 26.448 94.208 105.912 ;
     RECT  89.104 127.92 94.208 127.944 ;
     RECT  94.208 2.148 94.312 127.944 ;
     RECT  94.312 2.418 94.504 127.944 ;
     RECT  94.504 14.64 94.637 15.288 ;
     RECT  94.504 23.808 94.637 23.928 ;
     RECT  94.504 16.8 94.673 17.448 ;
     RECT  94.637 14.64 99.608 15.192 ;
     RECT  94.673 16.8 99.608 17.352 ;
     RECT  94.504 19.776 99.608 19.8 ;
     RECT  94.504 20.832 99.608 20.856 ;
     RECT  94.504 21.936 99.608 21.96 ;
     RECT  94.637 23.808 99.608 23.832 ;
     RECT  94.504 24.912 99.608 25.464 ;
     RECT  94.504 26.448 99.608 105.912 ;
     RECT  94.504 127.92 99.608 127.944 ;
     RECT  99.608 2.148 99.712 127.944 ;
     RECT  99.712 2.418 99.904 127.944 ;
     RECT  99.904 14.64 105.008 15.192 ;
     RECT  99.904 16.8 105.008 17.352 ;
     RECT  99.904 19.776 105.008 19.8 ;
     RECT  99.904 20.832 105.008 20.856 ;
     RECT  99.904 21.936 105.008 21.96 ;
     RECT  99.904 23.808 105.008 23.832 ;
     RECT  99.904 24.912 105.008 25.464 ;
     RECT  99.904 26.448 105.008 105.912 ;
     RECT  99.904 127.92 105.008 127.944 ;
     RECT  105.008 2.148 105.112 127.944 ;
     RECT  105.112 2.418 105.304 127.944 ;
     RECT  105.304 14.64 110.408 15.192 ;
     RECT  105.304 16.8 110.408 17.352 ;
     RECT  105.304 19.776 110.408 19.8 ;
     RECT  105.304 20.832 110.408 20.856 ;
     RECT  105.304 21.936 110.408 21.96 ;
     RECT  105.304 23.808 110.408 23.832 ;
     RECT  105.304 24.912 110.408 25.464 ;
     RECT  105.304 26.448 110.408 105.912 ;
     RECT  105.304 127.92 110.408 127.944 ;
     RECT  110.408 2.148 110.512 127.944 ;
     RECT  110.512 2.418 110.704 127.944 ;
     RECT  110.704 14.64 115.808 15.192 ;
     RECT  110.704 16.8 115.808 17.352 ;
     RECT  110.704 19.776 115.808 19.8 ;
     RECT  110.704 20.832 115.808 20.856 ;
     RECT  110.704 21.936 115.808 21.96 ;
     RECT  110.704 23.808 115.808 23.832 ;
     RECT  110.704 24.912 115.808 25.464 ;
     RECT  110.704 26.448 115.808 105.912 ;
     RECT  110.704 127.92 115.808 127.944 ;
     RECT  115.808 2.148 115.912 127.944 ;
     RECT  115.912 2.418 116.104 127.944 ;
     RECT  116.104 14.64 121.208 15.192 ;
     RECT  116.104 16.8 121.208 17.352 ;
     RECT  116.104 19.776 121.208 19.8 ;
     RECT  116.104 20.832 121.208 20.856 ;
     RECT  116.104 21.936 121.208 21.96 ;
     RECT  116.104 23.808 121.208 23.832 ;
     RECT  116.104 24.912 121.208 25.464 ;
     RECT  116.104 26.448 121.208 105.912 ;
     RECT  116.104 127.92 121.208 127.944 ;
     RECT  121.208 2.148 121.312 127.944 ;
     RECT  121.312 2.418 121.504 127.944 ;
     RECT  121.504 14.64 126.608 15.192 ;
     RECT  121.504 16.8 126.608 17.352 ;
     RECT  121.504 19.776 126.608 19.8 ;
     RECT  121.504 20.832 126.608 20.856 ;
     RECT  121.504 21.936 126.608 21.96 ;
     RECT  121.504 23.808 126.608 23.832 ;
     RECT  121.504 24.912 126.608 25.464 ;
     RECT  121.504 26.448 126.608 105.912 ;
     RECT  121.504 127.92 126.608 127.944 ;
     RECT  126.608 2.148 126.712 127.944 ;
     RECT  126.712 2.418 126.904 127.944 ;
     RECT  126.904 14.64 132.008 15.192 ;
     RECT  126.904 16.8 132.008 17.352 ;
     RECT  126.904 19.776 132.008 19.8 ;
     RECT  126.904 20.832 132.008 20.856 ;
     RECT  126.904 21.936 132.008 21.96 ;
     RECT  126.904 23.808 132.008 23.832 ;
     RECT  126.904 24.912 132.008 25.464 ;
     RECT  126.904 26.448 132.008 105.912 ;
     RECT  126.904 127.92 132.008 127.944 ;
     RECT  132.008 2.148 132.112 127.944 ;
     RECT  132.112 2.418 132.304 127.944 ;
     RECT  132.304 14.64 137.408 15.192 ;
     RECT  132.304 16.8 137.408 17.352 ;
     RECT  132.304 19.776 137.408 19.8 ;
     RECT  132.304 20.832 137.408 20.856 ;
     RECT  132.304 21.936 137.408 21.96 ;
     RECT  132.304 23.808 137.408 23.832 ;
     RECT  132.304 24.912 137.408 25.464 ;
     RECT  132.304 26.448 137.408 105.912 ;
     RECT  132.304 127.92 137.408 127.944 ;
     RECT  137.408 2.148 137.512 127.944 ;
     RECT  137.512 2.418 137.704 127.944 ;
     RECT  137.704 14.64 142.808 15.192 ;
     RECT  137.704 16.8 142.808 17.352 ;
     RECT  137.704 19.776 142.808 19.8 ;
     RECT  137.704 20.832 142.808 20.856 ;
     RECT  137.704 21.936 142.808 21.96 ;
     RECT  137.704 23.808 142.808 23.832 ;
     RECT  137.704 24.912 142.808 25.464 ;
     RECT  137.704 26.448 142.808 105.912 ;
     RECT  137.704 127.92 142.808 127.944 ;
     RECT  142.808 2.148 142.912 127.944 ;
     RECT  142.912 2.418 143.104 127.944 ;
     RECT  143.104 14.64 148.208 15.192 ;
     RECT  143.104 16.8 148.208 17.352 ;
     RECT  143.104 19.776 148.208 19.8 ;
     RECT  143.104 20.832 148.208 20.856 ;
     RECT  143.104 21.936 148.208 21.96 ;
     RECT  143.104 23.808 148.208 23.832 ;
     RECT  143.104 24.912 148.208 25.464 ;
     RECT  143.104 26.448 148.208 105.912 ;
     RECT  143.104 127.92 148.208 127.944 ;
     RECT  148.208 2.148 148.312 127.944 ;
     RECT  148.312 2.418 148.504 127.944 ;
     RECT  148.504 14.64 153.608 15.192 ;
     RECT  148.504 16.8 153.608 17.352 ;
     RECT  148.504 19.776 153.608 19.8 ;
     RECT  148.504 20.832 153.608 20.856 ;
     RECT  148.504 21.936 153.608 21.96 ;
     RECT  148.504 23.808 153.608 23.832 ;
     RECT  148.504 24.912 153.608 25.464 ;
     RECT  148.504 26.448 153.608 105.912 ;
     RECT  148.504 127.92 153.608 127.944 ;
     RECT  153.608 2.148 153.712 127.944 ;
     RECT  153.712 2.418 153.904 127.944 ;
     RECT  153.904 14.64 159.008 15.192 ;
     RECT  153.904 16.8 159.008 17.352 ;
     RECT  153.904 19.776 159.008 19.8 ;
     RECT  153.904 20.832 159.008 20.856 ;
     RECT  153.904 21.936 159.008 21.96 ;
     RECT  153.904 23.808 159.008 23.832 ;
     RECT  153.904 24.912 159.008 25.464 ;
     RECT  153.904 26.448 159.008 105.912 ;
     RECT  153.904 127.92 159.008 127.944 ;
     RECT  159.008 2.148 159.112 127.944 ;
     RECT  159.112 2.418 159.304 127.944 ;
     RECT  159.304 127.92 160.547 127.944 ;
     RECT  159.304 14.64 164.408 15.192 ;
     RECT  159.304 16.8 164.408 17.352 ;
     RECT  159.304 19.776 164.408 19.8 ;
     RECT  159.304 20.832 164.408 20.856 ;
     RECT  159.304 21.936 164.408 21.96 ;
     RECT  159.304 23.808 164.408 23.832 ;
     RECT  159.304 24.912 164.408 25.464 ;
     RECT  159.304 26.448 164.408 105.912 ;
     RECT  164.408 2.148 164.512 127.452 ;
     RECT  164.512 2.418 164.704 127.182 ;
     RECT  164.704 14.64 169.808 15.192 ;
     RECT  164.704 16.8 169.808 17.352 ;
     RECT  164.704 19.776 169.808 19.8 ;
     RECT  164.704 20.832 169.808 20.856 ;
     RECT  164.704 21.936 169.808 21.96 ;
     RECT  164.704 23.808 169.808 23.832 ;
     RECT  164.704 24.912 169.808 25.464 ;
     RECT  164.704 26.448 169.808 105.912 ;
     RECT  169.808 2.148 169.912 127.452 ;
     RECT  169.912 2.418 170.104 127.182 ;
     RECT  170.104 14.64 175.208 15.192 ;
     RECT  170.104 16.8 175.208 17.352 ;
     RECT  170.104 19.776 175.208 19.8 ;
     RECT  170.104 20.832 175.208 20.856 ;
     RECT  170.104 21.936 175.208 21.96 ;
     RECT  170.104 23.808 175.208 23.832 ;
     RECT  170.104 24.912 175.208 25.464 ;
     RECT  170.104 26.448 175.208 105.912 ;
     RECT  175.208 2.148 175.312 127.452 ;
     RECT  175.312 2.418 175.504 127.182 ;
     RECT  175.504 14.64 180.608 15.192 ;
     RECT  175.504 16.8 180.608 17.352 ;
     RECT  175.504 19.776 180.608 19.8 ;
     RECT  175.504 20.832 180.608 20.856 ;
     RECT  175.504 21.936 180.608 21.96 ;
     RECT  175.504 23.808 180.608 23.832 ;
     RECT  175.504 24.912 180.608 25.464 ;
     RECT  175.504 26.448 180.608 105.912 ;
     RECT  180.608 2.148 180.712 127.452 ;
     RECT  180.712 2.418 180.904 127.182 ;
     RECT  180.904 14.64 186.008 15.192 ;
     RECT  180.904 16.8 186.008 17.352 ;
     RECT  180.904 19.776 186.008 19.8 ;
     RECT  180.904 20.832 186.008 20.856 ;
     RECT  180.904 21.936 186.008 21.96 ;
     RECT  180.904 23.808 186.008 23.832 ;
     RECT  180.904 24.912 186.008 25.464 ;
     RECT  180.904 26.448 186.008 105.912 ;
     RECT  186.008 2.148 186.112 127.452 ;
     RECT  186.112 2.418 186.304 127.182 ;
     RECT  187.436 122.4 187.523 122.424 ;
     RECT  186.304 14.64 191.408 15.192 ;
     RECT  186.304 16.8 191.408 17.352 ;
     RECT  186.304 19.776 191.408 19.8 ;
     RECT  186.304 20.832 191.408 20.856 ;
     RECT  186.304 21.936 191.408 21.96 ;
     RECT  186.304 23.808 191.408 23.832 ;
     RECT  186.304 24.912 191.408 25.464 ;
     RECT  186.304 26.448 191.408 105.912 ;
     RECT  188.989 122.352 191.408 122.664 ;
     RECT  191.408 2.148 191.512 127.452 ;
     RECT  191.512 2.418 191.704 127.182 ;
     RECT  191.704 26.448 194.353 105.912 ;
     RECT  191.704 14.64 196.808 15.192 ;
     RECT  191.704 16.8 196.808 17.352 ;
     RECT  191.704 19.776 196.808 19.8 ;
     RECT  191.704 20.832 196.808 20.856 ;
     RECT  191.704 21.936 196.808 21.96 ;
     RECT  191.704 23.808 196.808 23.832 ;
     RECT  191.704 24.912 196.808 25.464 ;
     RECT  194.353 26.448 196.808 106.008 ;
     RECT  191.704 122.352 196.808 122.664 ;
     RECT  196.808 2.148 196.912 127.452 ;
     RECT  196.912 2.418 197.104 127.182 ;
     RECT  197.104 122.352 197.507 122.664 ;
     RECT  197.104 26.448 197.568 106.632 ;
     RECT  197.568 28.848 197.777 68.52 ;
     RECT  197.777 67.728 198.661 68.52 ;
     RECT  198.661 67.728 198.709 69.384 ;
     RECT  197.777 62.976 198.757 66.408 ;
     RECT  198.709 67.728 198.757 69.864 ;
     RECT  197.777 29.04 198.965 43.368 ;
     RECT  197.777 44.4 198.965 47.976 ;
     RECT  197.777 49.008 198.965 59.88 ;
     RECT  198.757 62.976 198.965 69.864 ;
     RECT  197.568 96.768 199.109 106.632 ;
     RECT  198.965 69.36 199.189 69.864 ;
     RECT  198.965 44.4 199.397 47.592 ;
     RECT  199.109 96.768 199.427 106.008 ;
     RECT  198.965 29.04 199.433 42.888 ;
     RECT  199.397 44.4 199.433 47.496 ;
     RECT  198.965 49.104 199.433 59.88 ;
     RECT  199.433 44.4 199.469 47.4 ;
     RECT  199.433 49.104 199.469 51.336 ;
     RECT  199.433 52.368 199.469 59.88 ;
     RECT  199.469 54.336 199.577 57 ;
     RECT  197.777 60.912 199.577 61.896 ;
     RECT  199.469 44.4 199.649 44.424 ;
     RECT  199.469 45.552 199.649 46.728 ;
     RECT  199.577 61.872 199.717 61.896 ;
     RECT  198.965 62.976 199.717 63.432 ;
     RECT  197.568 26.448 199.763 27.624 ;
     RECT  199.763 26.448 199.811 26.472 ;
     RECT  198.901 87.408 199.825 87.432 ;
     RECT  197.568 91.056 199.861 91.08 ;
     RECT  199.381 73.92 199.897 73.944 ;
     RECT  199.469 52.368 199.901 52.392 ;
     RECT  198.965 65.04 199.901 68.232 ;
     RECT  198.565 92.832 199.933 92.856 ;
     RECT  199.577 55.44 199.937 55.464 ;
     RECT  199.577 56.976 199.937 57 ;
     RECT  199.765 76.896 199.957 76.92 ;
     RECT  199.427 105.744 200.003 106.008 ;
     RECT  199.897 72.144 200.005 73.944 ;
     RECT  199.237 74.976 200.005 75 ;
     RECT  199.763 27.6 200.041 27.624 ;
     RECT  199.433 29.04 200.041 42.792 ;
     RECT  199.861 90.624 200.041 91.08 ;
     RECT  199.469 49.104 200.081 49.128 ;
     RECT  199.901 65.424 200.081 68.232 ;
     RECT  199.717 61.872 200.189 63.432 ;
     RECT  199.825 86.976 200.197 87.432 ;
     RECT  200.197 86.976 200.245 88.392 ;
     RECT  200.041 90.624 200.252 91.176 ;
     RECT  200.245 86.496 200.293 88.392 ;
     RECT  200.252 89.664 200.293 91.176 ;
     RECT  200.293 86.496 200.3 91.176 ;
     RECT  200.3 86.304 200.329 91.176 ;
     RECT  200.252 85.056 200.341 85.08 ;
     RECT  200.329 86.304 200.341 91.752 ;
     RECT  200.341 85.056 200.365 91.752 ;
     RECT  199.427 96.768 200.435 104.328 ;
     RECT  200.365 84.96 200.444 91.752 ;
     RECT  200.435 96.768 200.483 103.752 ;
     RECT  200.444 84.72 200.54 91.752 ;
     RECT  199.933 92.832 200.54 93.48 ;
     RECT  199.189 69.36 200.581 70.056 ;
     RECT  199.957 76.896 200.581 77.88 ;
     RECT  200.54 84.72 200.653 93.48 ;
     RECT  200.581 106.608 200.665 106.632 ;
     RECT  200.581 68.64 200.677 70.056 ;
     RECT  200.041 27.6 200.693 42.792 ;
     RECT  200.005 72.144 200.725 75 ;
     RECT  200.653 84.72 200.761 94.104 ;
     RECT  200.677 95.664 200.764 95.688 ;
     RECT  200.581 76.896 200.773 78.696 ;
     RECT  200.677 68.64 200.833 70.152 ;
     RECT  200.725 72.144 200.833 75.816 ;
     RECT  200.773 76.848 200.833 78.696 ;
     RECT  200.483 96.768 200.833 102.792 ;
     RECT  200.833 72.144 200.837 78.696 ;
     RECT  200.833 96.48 200.837 102.792 ;
     RECT  200.081 65.424 200.873 67.272 ;
     RECT  200.761 84.72 200.915 94.632 ;
     RECT  200.189 61.872 200.917 63.288 ;
     RECT  200.837 72.144 200.945 77.88 ;
     RECT  200.837 98.064 200.963 102.792 ;
     RECT  200.833 68.64 200.965 70.632 ;
     RECT  200.945 72.144 200.965 72.168 ;
     RECT  200.915 84.72 200.977 86.952 ;
     RECT  200.915 87.936 200.981 94.632 ;
     RECT  200.963 98.064 201.011 102.696 ;
     RECT  200.873 65.424 201.013 66.36 ;
     RECT  200.917 61.008 201.017 63.288 ;
     RECT  200.981 91.056 201.053 94.632 ;
     RECT  199.649 46.224 201.085 46.728 ;
     RECT  198.853 82.032 201.085 82.056 ;
     RECT  201.053 91.056 201.089 91.608 ;
     RECT  199.577 54.336 201.121 54.36 ;
     RECT  201.013 64.992 201.155 66.36 ;
     RECT  200.693 29.616 201.157 42.792 ;
     RECT  200.981 87.936 201.161 89.688 ;
     RECT  200.653 44.448 201.193 44.472 ;
     RECT  201.085 46.224 201.193 47.064 ;
     RECT  200.945 73.92 201.203 77.88 ;
     RECT  201.121 53.568 201.229 54.36 ;
     RECT  201.157 29.616 201.233 43.368 ;
     RECT  197.104 19.776 201.397 19.8 ;
     RECT  201.301 48.288 201.553 48.312 ;
     RECT  200.773 50.688 201.661 50.712 ;
     RECT  201.553 48.288 201.685 48.936 ;
     RECT  201.661 50.64 201.685 50.712 ;
     RECT  198.709 111.84 201.685 111.864 ;
     RECT  201.644 113.952 201.733 113.976 ;
     RECT  201.229 53.568 201.805 55.272 ;
     RECT  201.781 56.976 201.805 57 ;
     RECT  201.805 53.568 201.877 57 ;
     RECT  200.965 68.64 201.913 72.168 ;
     RECT  201.203 75.264 201.949 77.88 ;
     RECT  201.155 65.424 201.98 66.36 ;
     RECT  201.913 67.776 201.98 72.168 ;
     RECT  201.98 65.424 201.985 72.168 ;
     RECT  201.203 73.92 201.985 73.944 ;
     RECT  201.089 91.584 202.069 91.608 ;
     RECT  201.053 92.64 202.069 94.104 ;
     RECT  202.021 80.256 202.165 80.28 ;
     RECT  200.693 27.6 202.201 28.488 ;
     RECT  201.233 29.616 202.201 42.168 ;
     RECT  197.104 14.64 202.208 15.192 ;
     RECT  197.104 16.8 202.208 17.352 ;
     RECT  201.397 19.584 202.208 19.8 ;
     RECT  197.104 20.832 202.208 20.856 ;
     RECT  197.104 21.936 202.208 21.96 ;
     RECT  197.104 23.808 202.208 23.832 ;
     RECT  197.104 24.912 202.208 25.464 ;
     RECT  202.201 27.6 202.208 42.168 ;
     RECT  201.233 43.296 202.208 43.368 ;
     RECT  201.193 44.448 202.208 47.064 ;
     RECT  201.685 48.288 202.208 50.712 ;
     RECT  201.877 52.992 202.208 57 ;
     RECT  201.625 58.704 202.208 58.728 ;
     RECT  201.017 61.056 202.208 63.288 ;
     RECT  201.157 64.368 202.208 64.392 ;
     RECT  201.985 65.424 202.208 73.944 ;
     RECT  201.949 75.264 202.208 78.6 ;
     RECT  202.165 80.256 202.208 80.376 ;
     RECT  201.085 82.032 202.208 82.728 ;
     RECT  200.977 84.144 202.208 86.952 ;
     RECT  201.161 87.936 202.208 89.496 ;
     RECT  202.069 90.912 202.208 94.104 ;
     RECT  201.829 95.376 202.208 95.4 ;
     RECT  200.837 96.48 202.208 96.888 ;
     RECT  201.011 98.064 202.208 101.208 ;
     RECT  201.011 102.384 202.208 102.696 ;
     RECT  200.293 108.768 202.208 108.792 ;
     RECT  201.685 111.312 202.208 111.864 ;
     RECT  201.733 113.472 202.208 113.976 ;
     RECT  197.507 122.352 202.208 122.376 ;
     RECT  202.208 2.148 202.312 127.452 ;
     RECT  202.312 2.418 202.504 127.182 ;
     RECT  202.504 86.592 202.565 86.76 ;
     RECT  202.504 54.624 202.637 54.648 ;
     RECT  202.504 62.784 202.691 62.856 ;
     RECT  202.504 113.472 202.691 113.496 ;
     RECT  202.504 46.032 202.745 47.064 ;
     RECT  202.504 50.64 202.781 50.664 ;
     RECT  202.504 36.912 202.817 41.208 ;
     RECT  202.504 90.624 202.817 91.704 ;
     RECT  202.504 64.368 202.835 64.392 ;
     RECT  202.504 29.04 202.853 35.784 ;
     RECT  202.817 36.912 202.883 37.848 ;
     RECT  202.504 88.032 202.883 88.92 ;
     RECT  202.504 80.352 202.931 80.376 ;
     RECT  202.883 36.912 202.961 37.608 ;
     RECT  202.691 62.784 202.979 62.808 ;
     RECT  202.853 29.04 203.033 35.352 ;
     RECT  202.504 110.592 203.033 111.864 ;
     RECT  202.504 43.872 203.069 43.896 ;
     RECT  202.504 65.424 203.075 66.264 ;
     RECT  202.504 72.96 203.075 72.984 ;
     RECT  202.745 46.128 203.105 47.064 ;
     RECT  203.033 110.592 203.113 110.616 ;
     RECT  202.504 74.016 203.141 74.664 ;
     RECT  203.075 66.24 203.171 66.264 ;
     RECT  203.033 29.04 203.177 32.856 ;
     RECT  202.817 90.624 203.177 91.32 ;
     RECT  203.177 29.04 203.213 32.376 ;
     RECT  203.105 46.128 203.213 46.152 ;
     RECT  203.213 29.04 203.249 30.744 ;
     RECT  202.504 42.768 203.249 42.792 ;
     RECT  202.504 56.976 203.249 57 ;
     RECT  203.249 29.04 203.267 30.216 ;
     RECT  202.504 52.896 203.285 53.352 ;
     RECT  202.961 37.056 203.315 37.608 ;
     RECT  202.565 86.64 203.321 86.76 ;
     RECT  202.504 77.52 203.357 78.36 ;
     RECT  202.817 38.832 203.393 41.208 ;
     RECT  203.285 53.328 203.393 53.352 ;
     RECT  203.393 39.312 203.429 41.208 ;
     RECT  202.504 44.928 203.429 45 ;
     RECT  203.429 44.976 203.501 45 ;
     RECT  203.267 29.04 203.537 29.784 ;
     RECT  203.315 37.056 203.537 37.416 ;
     RECT  203.429 39.744 203.555 41.208 ;
     RECT  202.504 95.376 203.555 96.936 ;
     RECT  202.504 82.368 203.567 82.68 ;
     RECT  202.504 84.048 203.573 85.128 ;
     RECT  203.321 86.64 203.689 86.664 ;
     RECT  203.555 39.744 203.699 39.912 ;
     RECT  203.177 90.672 203.699 91.32 ;
     RECT  202.504 92.688 203.747 93.48 ;
     RECT  203.497 58.704 203.753 58.728 ;
     RECT  202.883 88.032 203.795 88.392 ;
     RECT  203.141 74.64 203.821 74.664 ;
     RECT  202.504 48.48 203.843 48.504 ;
     RECT  203.497 54.096 203.843 54.12 ;
     RECT  203.821 74.64 203.861 75.192 ;
     RECT  203.795 88.368 203.861 88.392 ;
     RECT  203.797 55.104 203.884 55.128 ;
     RECT  203.567 81.888 203.969 82.68 ;
     RECT  203.573 84.048 203.969 84.984 ;
     RECT  203.033 33.888 204.005 35.352 ;
     RECT  202.504 24.912 204.037 25.464 ;
     RECT  203.213 31.872 204.077 32.376 ;
     RECT  203.996 26.736 204.083 26.76 ;
     RECT  203.699 39.744 204.083 39.864 ;
     RECT  203.555 96.48 204.083 96.936 ;
     RECT  203.537 37.392 204.113 37.416 ;
     RECT  203.555 41.184 204.131 41.208 ;
     RECT  204.083 96.48 204.131 96.504 ;
     RECT  204.083 39.744 204.179 39.768 ;
     RECT  203.747 92.688 204.179 92.952 ;
     RECT  204.005 33.888 204.185 34.2 ;
     RECT  203.861 75.168 204.277 75.192 ;
     RECT  202.504 108.576 204.323 108.6 ;
     RECT  204.077 32.352 204.401 32.376 ;
     RECT  202.504 70.272 204.476 70.296 ;
     RECT  204.005 35.328 204.509 35.352 ;
     RECT  204.476 70.08 204.545 70.296 ;
     RECT  204.545 70.08 204.563 70.104 ;
     RECT  204.185 34.176 204.617 34.2 ;
     RECT  203.033 111.84 205.261 111.864 ;
     RECT  203.699 91.296 205.285 91.32 ;
     RECT  205.261 111.168 205.345 111.864 ;
     RECT  205.285 91.152 205.429 91.32 ;
     RECT  203.357 78.336 205.475 78.36 ;
     RECT  204.649 32.448 205.481 32.472 ;
     RECT  202.504 20.832 206.341 20.856 ;
     RECT  204.277 75.168 206.341 75.672 ;
     RECT  206.341 20.832 206.381 20.952 ;
     RECT  205.429 91.056 207.493 91.32 ;
     RECT  202.504 10.032 207.608 10.056 ;
     RECT  202.504 14.64 207.608 15.192 ;
     RECT  202.504 16.8 207.608 17.352 ;
     RECT  202.504 19.488 207.608 19.8 ;
     RECT  206.381 20.928 207.608 20.952 ;
     RECT  202.504 21.936 207.608 21.96 ;
     RECT  202.504 23.808 207.608 23.832 ;
     RECT  204.037 24.912 207.608 25.752 ;
     RECT  203.537 29.76 207.608 29.784 ;
     RECT  203.797 43.584 207.608 43.608 ;
     RECT  204.829 69.984 207.608 70.008 ;
     RECT  206.341 75.168 207.608 75.768 ;
     RECT  203.969 81.888 207.608 81.912 ;
     RECT  203.969 84.048 207.608 84.072 ;
     RECT  207.493 91.056 207.608 91.416 ;
     RECT  204.179 92.688 207.608 92.712 ;
     RECT  203.555 95.376 207.608 95.4 ;
     RECT  202.504 98.064 207.608 98.376 ;
     RECT  202.504 99.408 207.608 100.248 ;
     RECT  205.345 111.84 207.608 111.864 ;
     RECT  207.608 2.148 207.712 127.452 ;
     RECT  207.712 2.418 207.904 127.182 ;
     RECT  207.904 95.376 208.933 95.4 ;
     RECT  208.933 95.328 209.297 95.4 ;
     RECT  207.904 91.056 209.693 91.416 ;
     RECT  209.693 91.392 209.725 91.416 ;
     RECT  209.725 91.392 209.726 91.464 ;
     RECT  207.904 75.168 210.233 75.768 ;
     RECT  207.904 10.032 210.337 10.056 ;
     RECT  207.904 16.8 210.337 17.352 ;
     RECT  210.337 10.032 210.377 10.152 ;
     RECT  207.904 19.488 210.377 19.8 ;
     RECT  207.904 43.584 211.381 43.608 ;
     RECT  209.726 91.44 211.381 91.464 ;
     RECT  211.381 43.344 211.421 43.608 ;
     RECT  207.904 20.928 211.457 20.952 ;
     RECT  207.904 99.408 211.484 100.248 ;
     RECT  207.904 84.048 211.489 84.072 ;
     RECT  210.377 19.584 211.493 19.8 ;
     RECT  207.904 98.064 211.525 98.376 ;
     RECT  211.484 99.408 211.525 100.536 ;
     RECT  211.525 98.064 211.571 100.536 ;
     RECT  207.904 92.688 211.621 92.712 ;
     RECT  209.297 95.328 211.667 95.352 ;
     RECT  210.377 10.128 211.777 10.152 ;
     RECT  210.233 75.168 211.781 75.192 ;
     RECT  207.904 111.84 211.813 111.864 ;
     RECT  207.904 14.64 211.921 15.192 ;
     RECT  211.621 92.688 211.997 92.856 ;
     RECT  211.571 98.064 211.997 100.344 ;
     RECT  207.904 81.888 212.005 81.912 ;
     RECT  211.813 110.88 212.053 111.864 ;
     RECT  211.597 80.352 212.065 80.376 ;
     RECT  207.904 29.76 212.137 29.784 ;
     RECT  211.957 94.656 212.341 94.68 ;
     RECT  212.341 103.872 212.389 103.896 ;
     RECT  212.005 81.888 212.425 82.056 ;
     RECT  210.733 77.472 212.581 77.496 ;
     RECT  212.425 81.888 212.581 82.44 ;
     RECT  211.489 84.048 212.581 84.984 ;
     RECT  207.904 23.808 212.641 23.832 ;
     RECT  207.904 24.912 212.641 25.752 ;
     RECT  212.569 75.504 212.677 75.528 ;
     RECT  211.493 19.584 212.869 19.608 ;
     RECT  212.029 40.944 212.869 40.968 ;
     RECT  211.997 100.224 212.869 100.344 ;
     RECT  212.053 110.88 212.893 111.96 ;
     RECT  212.281 9.024 213.008 9.048 ;
     RECT  211.777 10.128 213.008 10.296 ;
     RECT  211.921 14.64 213.008 15.432 ;
     RECT  210.337 16.8 213.008 17.448 ;
     RECT  212.869 19.344 213.008 19.608 ;
     RECT  212.137 20.736 213.008 20.76 ;
     RECT  207.904 21.936 213.008 21.96 ;
     RECT  212.641 23.808 213.008 25.752 ;
     RECT  212.137 29.76 213.008 30.6 ;
     RECT  211.057 35.712 213.008 35.736 ;
     RECT  212.281 39.552 213.008 39.576 ;
     RECT  212.869 40.752 213.008 40.968 ;
     RECT  211.421 43.344 213.008 43.368 ;
     RECT  212.821 65.52 213.008 65.544 ;
     RECT  207.904 69.984 213.008 70.008 ;
     RECT  212.677 75.504 213.008 75.72 ;
     RECT  212.581 76.848 213.008 77.496 ;
     RECT  212.389 78.624 213.008 78.648 ;
     RECT  212.065 79.824 213.008 80.376 ;
     RECT  212.581 81.888 213.008 84.984 ;
     RECT  212.053 88.896 213.008 88.92 ;
     RECT  211.381 89.952 213.008 91.464 ;
     RECT  212.389 92.976 213.008 93 ;
     RECT  212.341 94.032 213.008 94.68 ;
     RECT  211.741 95.712 213.008 95.736 ;
     RECT  211.997 98.064 213.008 98.904 ;
     RECT  212.869 100.224 213.008 100.632 ;
     RECT  212.389 103.728 213.008 103.896 ;
     RECT  211.705 104.88 213.008 104.904 ;
     RECT  212.137 105.984 213.008 106.008 ;
     RECT  212.569 108.72 213.008 108.744 ;
     RECT  212.893 110.496 213.008 111.96 ;
     RECT  212.389 114.864 213.008 114.888 ;
     RECT  212.389 118.512 213.008 118.536 ;
     RECT  210.985 121.44 213.008 121.464 ;
     RECT  212.293 124.848 213.008 124.872 ;
     RECT  213.008 2.148 213.112 127.452 ;
     RECT  213.112 2.418 213.304 127.182 ;
     RECT  213.304 8.832 213.365 9.048 ;
     RECT  213.304 39.408 213.437 40.968 ;
     RECT  213.304 107.76 213.437 109.464 ;
     RECT  213.304 42.768 213.443 43.368 ;
     RECT  213.304 105.12 213.473 106.584 ;
     RECT  213.304 82.128 213.545 82.632 ;
     RECT  213.437 40.512 213.581 40.968 ;
     RECT  213.304 35.712 213.587 35.736 ;
     RECT  213.437 39.408 213.587 39.432 ;
     RECT  213.581 40.512 213.587 40.536 ;
     RECT  213.304 14.544 213.683 15.288 ;
     RECT  213.304 75.216 213.725 77.304 ;
     RECT  213.304 111.84 213.725 111.96 ;
     RECT  213.304 21.936 213.797 23.208 ;
     RECT  213.304 80.352 213.797 80.856 ;
     RECT  213.304 91.2 213.797 93 ;
     RECT  213.437 107.76 213.797 108.744 ;
     RECT  213.304 103.728 213.833 103.752 ;
     RECT  213.304 98.88 213.875 98.904 ;
     RECT  213.304 100.176 213.875 102.168 ;
     RECT  213.304 44.592 213.905 44.616 ;
     RECT  213.797 91.44 213.923 93 ;
     RECT  213.304 25.728 213.941 26.28 ;
     RECT  213.875 100.608 213.977 101.4 ;
     RECT  213.797 22.8 214.012 23.208 ;
     RECT  213.304 27.552 214.019 27.576 ;
     RECT  213.304 28.944 214.019 30.6 ;
     RECT  213.304 65.52 214.019 65.544 ;
     RECT  213.725 75.216 214.049 76.872 ;
     RECT  213.304 97.632 214.049 97.656 ;
     RECT  214.019 30.192 214.067 30.6 ;
     RECT  214.049 75.216 214.115 76.392 ;
     RECT  213.797 107.76 214.115 107.784 ;
     RECT  214.115 75.216 214.157 75.96 ;
     RECT  213.304 69.984 214.259 70.008 ;
     RECT  213.304 71.808 214.273 71.832 ;
     RECT  213.545 82.608 214.307 82.632 ;
     RECT  213.304 86.592 214.307 87.096 ;
     RECT  213.365 8.832 214.309 8.856 ;
     RECT  213.304 16.512 214.309 17.448 ;
     RECT  213.304 18.912 214.309 19.608 ;
     RECT  213.304 83.808 214.309 83.832 ;
     RECT  213.304 10.128 214.337 10.152 ;
     RECT  213.304 24.624 214.337 24.648 ;
     RECT  214.309 7.968 214.355 8.856 ;
     RECT  213.304 95.712 214.355 95.736 ;
     RECT  214.309 96.864 214.396 96.888 ;
     RECT  214.157 75.648 214.409 75.96 ;
     RECT  213.473 105.984 214.445 106.584 ;
     RECT  213.923 91.44 214.481 91.464 ;
     RECT  213.304 33.648 214.517 33.672 ;
     RECT  213.304 12.48 214.645 12.504 ;
     RECT  214.369 13.68 214.691 13.704 ;
     RECT  214.355 7.968 214.693 7.992 ;
     RECT  214.645 12.48 214.732 12.552 ;
     RECT  214.693 7.488 214.733 7.992 ;
     RECT  214.309 16.512 214.733 19.608 ;
     RECT  214.652 32.928 214.739 32.952 ;
     RECT  213.941 26.256 214.769 26.28 ;
     RECT  214.733 18.912 214.789 19.608 ;
     RECT  214.733 16.512 214.805 17.592 ;
     RECT  214.789 18.912 214.835 19.704 ;
     RECT  213.977 101.376 214.837 101.4 ;
     RECT  214.835 19.68 214.876 19.704 ;
     RECT  214.837 101.376 214.877 101.496 ;
     RECT  214.805 17.568 214.883 17.592 ;
     RECT  213.443 42.768 214.901 42.792 ;
     RECT  213.304 38.064 214.931 38.088 ;
     RECT  214.901 42.144 214.933 42.792 ;
     RECT  214.933 42.144 214.985 42.84 ;
     RECT  214.012 22.8 215.201 22.824 ;
     RECT  214.307 86.592 215.201 86.616 ;
     RECT  213.725 111.936 215.221 111.96 ;
     RECT  215.221 111.456 215.308 111.96 ;
     RECT  214.409 75.648 215.453 75.768 ;
     RECT  214.985 42.768 215.489 42.84 ;
     RECT  214.732 12.48 215.555 12.504 ;
     RECT  213.304 124.848 215.561 124.872 ;
     RECT  215.509 11.376 215.597 11.4 ;
     RECT  215.489 42.768 215.597 42.792 ;
     RECT  213.797 80.832 215.633 80.856 ;
     RECT  213.304 68.688 215.669 68.712 ;
     RECT  214.877 101.472 215.669 101.496 ;
     RECT  215.308 111.936 215.669 111.96 ;
     RECT  213.304 31.872 215.741 31.896 ;
     RECT  214.733 7.488 215.756 7.512 ;
     RECT  215.453 75.744 215.777 75.768 ;
     RECT  215.756 7.488 215.843 7.848 ;
     RECT  215.797 10.224 215.884 10.248 ;
     RECT  215.797 6.24 215.993 6.264 ;
     RECT  215.797 11.232 215.993 11.256 ;
     RECT  214.729 21.552 216.029 21.576 ;
     RECT  214.445 106.56 216.065 106.584 ;
     RECT  214.805 16.512 216.281 16.536 ;
     RECT  214.881 37.056 216.281 37.08 ;
    LAYER M5 ;
     RECT  2.4 2.137 2.52 2.151 ;
     RECT  7.8 2.137 7.92 2.151 ;
     RECT  13.2 2.137 13.32 2.151 ;
     RECT  18.6 2.137 18.72 2.151 ;
     RECT  24 2.137 24.12 2.151 ;
     RECT  29.4 2.137 29.52 2.151 ;
     RECT  34.8 2.137 34.92 2.151 ;
     RECT  40.2 2.137 40.32 2.151 ;
     RECT  45.6 2.137 45.72 2.151 ;
     RECT  51 2.137 51.12 2.151 ;
     RECT  56.4 2.137 56.52 2.151 ;
     RECT  61.8 2.137 61.92 2.151 ;
     RECT  67.2 2.137 67.32 2.151 ;
     RECT  72.6 2.137 72.72 2.151 ;
     RECT  78 2.137 78.12 2.151 ;
     RECT  83.4 2.137 83.52 2.151 ;
     RECT  88.8 2.137 88.92 2.151 ;
     RECT  94.2 2.137 94.32 2.151 ;
     RECT  99.6 2.137 99.72 2.151 ;
     RECT  105 2.137 105.12 2.151 ;
     RECT  110.4 2.137 110.52 2.151 ;
     RECT  115.8 2.137 115.92 2.151 ;
     RECT  121.2 2.137 121.32 2.151 ;
     RECT  126.6 2.137 126.72 2.151 ;
     RECT  132 2.137 132.12 2.151 ;
     RECT  137.4 2.137 137.52 2.151 ;
     RECT  142.8 2.137 142.92 2.151 ;
     RECT  148.2 2.137 148.32 2.151 ;
     RECT  153.6 2.137 153.72 2.151 ;
     RECT  159 2.137 159.12 2.151 ;
     RECT  164.4 2.137 164.52 2.151 ;
     RECT  169.8 2.137 169.92 2.151 ;
     RECT  175.2 2.137 175.32 2.151 ;
     RECT  180.6 2.137 180.72 2.151 ;
     RECT  186 2.137 186.12 2.151 ;
     RECT  191.4 2.137 191.52 2.151 ;
     RECT  196.8 2.137 196.92 2.151 ;
     RECT  202.2 2.137 202.32 2.151 ;
     RECT  207.6 2.137 207.72 2.151 ;
     RECT  213 2.137 213.12 2.151 ;
     RECT  4.464 5.077 4.488 6.563 ;
     RECT  214.32 7.957 214.344 8.867 ;
     RECT  202.2 2.151 202.512 10.021 ;
     RECT  215.808 6.229 215.832 11.267 ;
     RECT  7.8 2.151 8.112 11.845 ;
     RECT  3.984 7.765 4.008 11.939 ;
     RECT  215.52 11.365 215.544 12.515 ;
     RECT  7.344 11.845 8.112 13.573 ;
     RECT  9.36 10.309 9.384 13.573 ;
     RECT  214.656 12.517 214.68 13.715 ;
     RECT  5.136 11.893 5.16 13.811 ;
     RECT  213 2.151 213.312 14.533 ;
     RECT  61.8 2.151 62.112 15.253 ;
     RECT  213 14.533 213.672 15.253 ;
     RECT  212.016 15.253 213.672 15.443 ;
     RECT  213 15.443 213.672 16.643 ;
     RECT  214.848 16.501 214.872 17.603 ;
     RECT  5.088 14.677 5.112 17.891 ;
     RECT  7.344 13.573 9.384 18.037 ;
     RECT  214.32 18.181 214.344 18.901 ;
     RECT  214.32 18.901 214.824 18.947 ;
     RECT  213 16.643 213.312 19.333 ;
     RECT  60.96 15.253 62.112 19.427 ;
     RECT  202.2 10.021 203.208 19.573 ;
     RECT  6.912 18.037 9.384 19.765 ;
     RECT  34.8 2.151 35.112 19.861 ;
     RECT  6.912 19.765 10.296 19.909 ;
     RECT  24 2.151 24.312 19.909 ;
     RECT  63.216 17.317 63.24 20.003 ;
     RECT  45.6 2.151 45.912 20.149 ;
     RECT  26.496 20.053 26.52 20.195 ;
     RECT  34.8 19.861 36.072 20.531 ;
     RECT  212.88 19.333 213.312 20.771 ;
     RECT  29.4 2.151 29.712 20.821 ;
     RECT  6 19.909 10.296 21.061 ;
     RECT  44.736 20.149 45.912 21.155 ;
     RECT  214.8 18.947 214.824 21.541 ;
     RECT  214.8 21.541 214.92 21.587 ;
     RECT  54.096 20.485 54.12 21.827 ;
     RECT  34.8 20.531 35.208 21.925 ;
     RECT  51 2.151 51.312 21.925 ;
     RECT  31.824 19.813 31.848 21.971 ;
     RECT  61.008 19.427 62.112 22.165 ;
     RECT  24 19.909 25.128 22.213 ;
     RECT  45.6 21.155 45.912 22.213 ;
     RECT  5.28 21.061 10.296 22.549 ;
     RECT  5.28 22.549 10.44 22.595 ;
     RECT  34.8 21.925 35.304 22.835 ;
     RECT  214.896 21.587 214.92 22.835 ;
     RECT  44.976 22.213 45.912 23.075 ;
     RECT  213 20.771 213.312 23.173 ;
     RECT  24 22.213 25.176 23.315 ;
     RECT  60.96 22.165 62.112 23.317 ;
     RECT  54.144 22.741 54.168 23.363 ;
     RECT  31.152 22.741 31.176 23.411 ;
     RECT  42.768 22.741 42.792 23.411 ;
     RECT  25.392 23.317 25.416 24.083 ;
     RECT  16.992 21.109 17.016 24.131 ;
     RECT  29.4 20.821 29.832 24.131 ;
     RECT  10.416 22.595 10.44 24.179 ;
     RECT  40.2 2.151 40.512 24.181 ;
     RECT  60 23.317 62.112 24.227 ;
     RECT  33.6 23.317 33.624 24.323 ;
     RECT  22.416 21.925 22.44 24.325 ;
     RECT  22.416 24.325 22.776 24.515 ;
     RECT  42.048 24.469 42.072 24.613 ;
     RECT  27.936 22.453 27.96 24.659 ;
     RECT  213 23.173 213.96 24.659 ;
     RECT  18.6 2.151 18.912 24.661 ;
     RECT  52.56 23.317 52.584 24.899 ;
     RECT  5.28 22.595 9.384 25.045 ;
     RECT  18.6 24.661 19.464 25.045 ;
     RECT  20.736 24.085 20.76 25.045 ;
     RECT  39.984 24.181 40.512 25.091 ;
     RECT  18.6 25.045 20.76 25.141 ;
     RECT  15.408 23.845 15.432 25.429 ;
     RECT  14.64 25.429 15.432 25.571 ;
     RECT  17.376 25.525 17.4 25.621 ;
     RECT  22.752 24.515 22.776 25.621 ;
     RECT  17.184 25.621 17.4 25.715 ;
     RECT  42.048 24.613 42.6 25.715 ;
     RECT  72.6 2.151 72.912 25.717 ;
     RECT  201.408 19.573 203.208 25.717 ;
     RECT  33.648 25.045 33.672 25.763 ;
     RECT  37.632 25.045 37.656 25.763 ;
     RECT  22.656 25.621 22.776 25.765 ;
     RECT  15.168 25.571 15.432 26.243 ;
     RECT  213 24.659 213.312 26.245 ;
     RECT  5.28 25.045 10.296 26.291 ;
     RECT  22.416 25.765 22.776 26.533 ;
     RECT  201.408 25.717 204.072 26.771 ;
     RECT  199.776 26.437 199.8 27.013 ;
     RECT  22.368 26.533 22.776 27.061 ;
     RECT  17.184 25.715 17.208 27.395 ;
     RECT  21.888 27.061 22.776 27.493 ;
     RECT  11.952 27.157 11.976 27.589 ;
     RECT  201.408 26.771 203.208 27.589 ;
     RECT  11.664 27.589 11.976 27.635 ;
     RECT  5.28 26.291 9.384 27.925 ;
     RECT  21.888 27.493 22.824 28.067 ;
     RECT  21.888 28.067 22.776 28.883 ;
     RECT  11.664 27.635 11.688 28.931 ;
     RECT  4.56 27.925 9.384 28.979 ;
     RECT  13.2 2.151 13.512 29.605 ;
     RECT  201.36 27.589 203.208 29.749 ;
     RECT  199.728 27.013 199.8 30.181 ;
     RECT  201.36 29.749 203.784 30.181 ;
     RECT  213 26.245 214.008 30.181 ;
     RECT  13.104 29.605 13.608 30.371 ;
     RECT  21.888 28.883 22.728 30.757 ;
     RECT  3.984 30.181 4.008 30.851 ;
     RECT  21.888 30.757 22.776 30.947 ;
     RECT  198.384 30.757 198.408 30.947 ;
     RECT  199.728 30.181 203.784 31.043 ;
     RECT  15.168 26.243 15.192 31.333 ;
     RECT  13.2 30.371 13.608 31.427 ;
     RECT  13.2 31.427 13.512 31.525 ;
     RECT  15.168 31.333 16.728 31.811 ;
     RECT  213 30.181 214.056 31.861 ;
     RECT  213 31.861 214.728 31.907 ;
     RECT  200.88 31.043 203.784 32.341 ;
     RECT  5.28 28.979 9.384 32.437 ;
     RECT  15.168 31.811 16.104 32.723 ;
     RECT  214.704 31.907 214.728 32.963 ;
     RECT  199.728 31.043 199.8 33.013 ;
     RECT  200.88 32.341 203.928 33.013 ;
     RECT  15.168 32.723 16.056 33.253 ;
     RECT  18.6 25.141 20.808 33.589 ;
     RECT  13.008 31.525 13.512 33.635 ;
     RECT  3.936 33.013 3.96 34.115 ;
     RECT  18.48 33.589 20.808 34.691 ;
     RECT  21.888 30.947 22.728 34.739 ;
     RECT  14.784 33.253 16.056 34.835 ;
     RECT  13.2 33.635 13.512 35.125 ;
     RECT  14.784 34.835 15.192 35.125 ;
     RECT  16.656 35.029 16.68 35.171 ;
     RECT  213 31.907 213.312 35.701 ;
     RECT  5.28 32.437 9.96 36.997 ;
     RECT  199.728 33.013 203.928 37.141 ;
     RECT  198.816 37.141 203.928 37.331 ;
     RECT  4.368 36.997 9.96 37.573 ;
     RECT  4.368 37.573 10.152 37.667 ;
     RECT  4.368 37.667 4.392 37.859 ;
     RECT  214.896 37.045 214.92 38.099 ;
     RECT  13.2 35.125 15.192 38.149 ;
     RECT  5.52 37.667 10.152 38.435 ;
     RECT  5.568 38.435 10.152 38.677 ;
     RECT  18.6 34.691 20.808 39.205 ;
     RECT  5.568 38.677 10.824 39.299 ;
     RECT  199.728 37.331 203.928 39.733 ;
     RECT  18.288 39.205 20.808 40.019 ;
     RECT  196.8 2.151 197.112 40.069 ;
     RECT  196.8 40.069 197.736 40.259 ;
     RECT  213 35.701 213.576 40.547 ;
     RECT  5.568 39.299 10.296 40.739 ;
     RECT  213 40.547 213.432 40.741 ;
     RECT  18.6 40.019 20.808 41.651 ;
     RECT  3.984 40.789 4.008 41.891 ;
     RECT  18.6 41.651 19.176 42.037 ;
     RECT  13.2 38.149 15.288 42.133 ;
     RECT  13.056 42.133 15.288 42.709 ;
     RECT  5.568 40.739 10.2 42.757 ;
     RECT  214.944 42.133 214.968 42.851 ;
     RECT  5.568 42.757 10.872 42.899 ;
     RECT  11.904 42.709 11.928 43.141 ;
     RECT  16.8 42.709 16.824 43.379 ;
     RECT  212.88 40.741 213.432 44.627 ;
     RECT  5.568 42.899 10.152 45.253 ;
     RECT  11.232 43.141 11.928 45.253 ;
     RECT  12.96 42.709 15.288 45.635 ;
     RECT  196.8 40.259 197.112 46.213 ;
     RECT  5.568 45.253 11.928 46.693 ;
     RECT  13.008 45.635 15.288 46.693 ;
     RECT  5.568 46.693 15.288 46.787 ;
     RECT  5.568 46.787 10.44 46.835 ;
     RECT  5.568 46.835 10.152 47.363 ;
     RECT  9.264 47.363 10.152 47.845 ;
     RECT  11.424 46.787 15.288 47.939 ;
     RECT  5.568 47.363 8.232 48.421 ;
     RECT  9.264 47.845 10.296 48.421 ;
     RECT  18.432 42.037 19.176 48.421 ;
     RECT  5.568 48.421 10.296 48.515 ;
     RECT  11.568 47.939 15.288 48.947 ;
     RECT  2.4 2.151 2.712 48.949 ;
     RECT  11.616 48.947 15.288 49.139 ;
     RECT  18.288 48.421 19.176 49.189 ;
     RECT  18.192 49.189 19.176 49.525 ;
     RECT  20.16 41.651 20.808 49.525 ;
     RECT  2.4 48.949 3.432 49.619 ;
     RECT  18.192 49.525 20.808 50.003 ;
     RECT  5.568 48.515 10.152 50.053 ;
     RECT  5.568 50.053 10.2 50.677 ;
     RECT  11.664 49.139 11.88 50.677 ;
     RECT  5.568 50.677 11.88 50.819 ;
     RECT  18.288 50.003 20.808 51.059 ;
     RECT  13.056 49.139 15.288 51.157 ;
     RECT  18.288 51.059 19.176 52.405 ;
     RECT  5.568 50.819 11.688 53.363 ;
     RECT  18.096 52.405 19.176 53.557 ;
     RECT  20.16 51.059 20.808 53.557 ;
     RECT  16.944 44.965 16.968 54.085 ;
     RECT  9.36 53.363 11.688 54.131 ;
     RECT  5.568 53.363 8.376 54.179 ;
     RECT  196.8 46.213 198.072 54.325 ;
     RECT  6.912 54.179 8.376 54.661 ;
     RECT  9.36 54.131 10.872 54.661 ;
     RECT  12 54.565 12.024 54.901 ;
     RECT  13.056 51.157 15.384 54.901 ;
     RECT  12 54.901 15.384 55.285 ;
     RECT  16.896 54.085 16.968 55.717 ;
     RECT  5.664 54.179 5.688 55.813 ;
     RECT  16.656 55.717 16.968 55.859 ;
     RECT  11.856 55.285 15.384 56.483 ;
     RECT  5.136 55.813 5.688 56.531 ;
     RECT  5.664 56.531 5.688 56.917 ;
     RECT  6.912 54.661 10.872 56.917 ;
     RECT  12.672 56.483 15.384 56.965 ;
     RECT  12.672 56.965 15.432 57.541 ;
     RECT  16.944 55.859 16.968 57.973 ;
     RECT  18.096 53.557 20.808 57.973 ;
     RECT  11.952 57.541 15.432 58.309 ;
     RECT  11.856 58.309 15.432 58.645 ;
     RECT  11.856 58.645 15.48 58.787 ;
     RECT  11.856 58.787 11.976 59.459 ;
     RECT  5.664 56.917 10.872 59.797 ;
     RECT  13.056 58.787 15.48 59.797 ;
     RECT  11.952 59.459 11.976 60.467 ;
     RECT  196.8 54.325 198.12 61.861 ;
     RECT  5.28 59.797 10.872 61.909 ;
     RECT  13.056 59.797 15.96 62.339 ;
     RECT  5.28 61.909 10.92 62.387 ;
     RECT  9.36 62.387 10.92 62.389 ;
     RECT  5.28 62.387 8.112 62.533 ;
     RECT  9.36 62.389 10.968 62.629 ;
     RECT  196.8 61.861 198.216 62.965 ;
     RECT  21.888 34.739 22.68 63.107 ;
     RECT  13.056 62.339 15.384 63.205 ;
     RECT  9.36 62.629 11.208 64.549 ;
     RECT  12.336 63.205 15.384 64.549 ;
     RECT  5.088 62.533 8.112 64.595 ;
     RECT  9.36 64.549 15.384 64.595 ;
     RECT  9.36 64.595 12.024 65.363 ;
     RECT  196.8 62.965 198.264 65.413 ;
     RECT  212.88 44.627 213.312 65.509 ;
     RECT  196.8 65.413 198.312 66.181 ;
     RECT  196.8 66.181 198.36 66.373 ;
     RECT  196.8 66.373 198.648 67.237 ;
     RECT  199.728 39.733 204.168 67.237 ;
     RECT  9.36 65.363 11.304 67.381 ;
     RECT  212.88 65.509 214.008 68.677 ;
     RECT  5.664 64.595 8.112 68.915 ;
     RECT  4.512 68.917 4.536 70.021 ;
     RECT  196.8 67.237 204.168 70.069 ;
     RECT  16.944 57.973 20.808 70.357 ;
     RECT  13.056 64.595 15.384 70.739 ;
     RECT  4.416 70.021 4.536 70.835 ;
     RECT  4.416 70.835 4.44 71.315 ;
     RECT  14.928 70.739 15.384 71.363 ;
     RECT  16.944 70.357 21.384 71.797 ;
     RECT  212.88 68.677 214.248 71.843 ;
     RECT  6.528 68.915 8.112 72.517 ;
     RECT  9.36 67.381 11.688 72.517 ;
     RECT  16.56 71.797 21.384 72.995 ;
     RECT  6.528 72.517 11.688 73.235 ;
     RECT  16.944 72.995 21.384 74.341 ;
     RECT  9.12 73.235 11.688 74.627 ;
     RECT  13.056 70.739 13.944 74.629 ;
     RECT  212.88 71.843 213.312 75.205 ;
     RECT  196.8 70.069 204.552 75.683 ;
     RECT  12.816 74.629 13.944 75.827 ;
     RECT  16.368 74.341 21.384 75.827 ;
     RECT  15.36 71.363 15.384 75.925 ;
     RECT  13.056 75.827 13.944 76.403 ;
     RECT  212.88 75.205 214.104 76.403 ;
     RECT  212.88 76.403 213.312 76.837 ;
     RECT  15.36 75.925 15.624 77.027 ;
     RECT  212.592 76.837 213.312 77.507 ;
     RECT  6.528 73.235 8.112 78.037 ;
     RECT  212.88 77.507 213.312 78.613 ;
     RECT  22.656 63.107 22.68 79.477 ;
     RECT  2.4 49.619 2.712 80.341 ;
     RECT  212.4 78.613 213.312 80.341 ;
     RECT  16.944 75.827 21.384 80.627 ;
     RECT  6.432 78.037 8.112 81.157 ;
     RECT  2.4 80.341 3.288 81.829 ;
     RECT  212.016 80.341 213.312 82.067 ;
     RECT  4.704 80.917 4.728 82.163 ;
     RECT  6.432 81.157 8.232 82.597 ;
     RECT  16.944 80.627 16.968 82.597 ;
     RECT  18.096 80.627 21.384 82.597 ;
     RECT  212.592 82.067 213.312 82.597 ;
     RECT  2.4 81.829 3.336 82.787 ;
     RECT  5.76 82.597 8.232 83.267 ;
     RECT  16.944 82.597 21.384 83.509 ;
     RECT  22.464 79.477 22.68 83.509 ;
     RECT  5.76 83.267 8.112 83.749 ;
     RECT  5.232 83.749 8.112 83.891 ;
     RECT  9.36 74.627 11.688 84.901 ;
     RECT  13.2 76.403 13.944 84.995 ;
     RECT  212.592 82.597 214.296 84.995 ;
     RECT  2.4 82.787 2.712 86.005 ;
     RECT  5.232 83.891 5.256 86.581 ;
     RECT  6.432 83.891 8.112 86.581 ;
     RECT  9.36 84.901 11.976 86.819 ;
     RECT  2.4 86.005 3.576 87.011 ;
     RECT  5.232 86.581 8.112 87.011 ;
     RECT  212.88 84.995 214.296 87.107 ;
     RECT  11.952 86.819 11.976 87.251 ;
     RECT  16.944 83.509 22.68 87.827 ;
     RECT  212.88 87.107 213.312 88.885 ;
     RECT  20.784 87.827 22.68 89.123 ;
     RECT  5.232 87.011 5.256 89.845 ;
     RECT  212.064 88.885 213.312 89.987 ;
     RECT  6.432 87.011 8.112 90.037 ;
     RECT  6.432 90.037 8.232 90.517 ;
     RECT  16.944 87.827 19.368 90.611 ;
     RECT  4.32 89.845 5.256 90.659 ;
     RECT  4.32 90.659 5.16 90.755 ;
     RECT  4.32 90.755 4.44 90.947 ;
     RECT  205.44 78.325 205.464 91.141 ;
     RECT  6.24 90.517 8.232 91.187 ;
     RECT  205.296 91.141 205.464 91.187 ;
     RECT  207.6 2.151 207.912 91.285 ;
     RECT  207.504 91.285 207.912 91.427 ;
     RECT  212.88 89.987 213.312 91.429 ;
     RECT  211.392 90.565 211.416 91.475 ;
     RECT  6.72 91.187 8.232 92.293 ;
     RECT  9.36 86.819 10.872 92.293 ;
     RECT  6.72 92.293 10.872 92.387 ;
     RECT  212.88 91.429 213.912 93.011 ;
     RECT  4.416 90.947 4.44 93.539 ;
     RECT  211.632 92.821 211.656 94.021 ;
     RECT  212.88 93.011 213.312 94.021 ;
     RECT  10.128 92.387 10.872 94.115 ;
     RECT  211.632 94.021 213.312 94.691 ;
     RECT  5.472 94.549 5.496 95.125 ;
     RECT  196.8 75.683 204.312 96.371 ;
     RECT  5.184 95.125 5.496 96.899 ;
     RECT  214.32 95.701 214.344 96.899 ;
     RECT  15.36 77.027 15.384 96.947 ;
     RECT  204.048 96.371 204.312 96.947 ;
     RECT  212.88 94.691 213.312 97.621 ;
     RECT  13.2 84.995 13.848 97.669 ;
     RECT  10.512 94.115 10.872 97.717 ;
     RECT  211.632 94.691 211.656 98.485 ;
     RECT  34.8 22.835 35.112 98.725 ;
     RECT  211.632 98.485 211.848 98.869 ;
     RECT  5.184 96.899 5.208 98.917 ;
     RECT  10.368 97.717 10.872 99.059 ;
     RECT  88.8 2.151 89.112 99.445 ;
     RECT  12.576 97.669 13.848 99.541 ;
     RECT  211.536 98.869 211.848 99.635 ;
     RECT  5.184 98.917 5.688 99.685 ;
     RECT  6.72 92.387 8.424 99.685 ;
     RECT  83.4 2.151 83.712 100.117 ;
     RECT  40.2 25.091 40.512 100.165 ;
     RECT  78 2.151 78.312 100.165 ;
     RECT  10.512 99.059 10.872 100.213 ;
     RECT  11.952 99.541 13.848 100.213 ;
     RECT  94.2 2.151 94.512 100.309 ;
     RECT  95.76 98.965 95.784 100.309 ;
     RECT  36.48 100.069 36.504 100.355 ;
     RECT  211.536 99.635 211.704 100.355 ;
     RECT  94.2 100.309 95.784 100.403 ;
     RECT  29.4 24.131 29.712 100.453 ;
     RECT  34.8 98.725 35.352 100.453 ;
     RECT  40.2 100.165 40.632 100.499 ;
     RECT  16.944 90.611 19.272 100.547 ;
     RECT  211.536 100.355 211.56 100.547 ;
     RECT  18.096 100.547 19.272 100.595 ;
     RECT  97.488 100.261 97.512 100.595 ;
     RECT  16.944 100.547 16.968 100.643 ;
     RECT  212.88 97.621 213.864 100.643 ;
     RECT  37.824 100.405 37.848 100.691 ;
     RECT  83.4 100.117 83.832 100.691 ;
     RECT  34.32 100.453 35.352 100.693 ;
     RECT  78 100.165 78.696 100.741 ;
     RECT  29.4 100.453 29.928 100.789 ;
     RECT  88.704 99.445 89.112 100.789 ;
     RECT  34.224 100.693 35.352 100.837 ;
     RECT  60.96 24.227 62.112 100.837 ;
     RECT  142.8 2.151 143.112 100.837 ;
     RECT  5.184 99.685 8.424 100.931 ;
     RECT  36.96 100.885 37.176 101.027 ;
     RECT  88.704 100.789 89.832 101.027 ;
     RECT  18.096 100.595 19.176 101.075 ;
     RECT  75.216 99.973 75.24 101.075 ;
     RECT  142.8 100.837 143.64 101.075 ;
     RECT  34.08 100.837 35.88 101.123 ;
     RECT  21.36 89.123 22.68 101.125 ;
     RECT  42.048 25.715 42.072 101.219 ;
     RECT  110.4 2.151 110.712 101.269 ;
     RECT  18.096 101.075 19.08 101.363 ;
     RECT  43.728 100.357 43.752 101.413 ;
     RECT  34.08 101.123 35.112 101.459 ;
     RECT  50.112 21.925 51.312 101.651 ;
     RECT  72.6 25.717 73.224 101.651 ;
     RECT  43.728 101.413 44.088 101.653 ;
     RECT  18.288 101.363 19.08 101.699 ;
     RECT  10.512 100.213 13.848 102.131 ;
     RECT  112.416 101.989 112.44 102.133 ;
     RECT  10.512 102.131 13.8 102.179 ;
     RECT  110.064 101.269 110.712 102.179 ;
     RECT  213 100.643 213.864 102.179 ;
     RECT  5.184 100.931 8.376 102.275 ;
     RECT  56.4 2.151 56.712 102.421 ;
     RECT  10.512 102.179 10.536 102.467 ;
     RECT  11.664 102.179 13.8 102.659 ;
     RECT  196.8 96.371 203.064 102.707 ;
     RECT  20.88 101.125 22.68 102.709 ;
     RECT  196.8 102.707 200.952 102.803 ;
     RECT  20.88 102.709 22.824 102.947 ;
     RECT  12.576 102.659 13.8 102.995 ;
     RECT  60.912 100.837 62.112 102.995 ;
     RECT  20.88 102.947 22.68 103.283 ;
     RECT  21.936 103.283 22.68 103.379 ;
     RECT  69.072 103.237 69.096 103.523 ;
     RECT  5.184 102.275 8.112 103.621 ;
     RECT  13.104 102.995 13.8 103.715 ;
     RECT  13.2 103.715 13.8 103.763 ;
     RECT  213 102.179 213.312 103.861 ;
     RECT  37.152 101.027 37.176 104.051 ;
     RECT  43.296 101.653 44.088 104.147 ;
     RECT  18.432 101.699 19.08 104.243 ;
     RECT  5.184 103.621 8.424 104.245 ;
     RECT  22.224 103.379 22.68 104.819 ;
     RECT  13.2 103.763 13.752 104.867 ;
     RECT  18.432 104.243 18.912 104.867 ;
     RECT  112.416 102.133 113.16 104.867 ;
     RECT  10.272 103.525 10.296 104.915 ;
     RECT  212.352 103.861 213.312 104.915 ;
     RECT  22.224 104.819 22.248 105.059 ;
     RECT  13.2 104.867 13.608 105.251 ;
     RECT  20.88 103.283 20.904 105.347 ;
     RECT  196.8 102.803 200.616 105.491 ;
     RECT  94.2 100.403 94.872 105.683 ;
     RECT  112.416 104.867 112.44 105.683 ;
     RECT  88.8 101.027 89.832 105.731 ;
     RECT  199.2 105.491 200.616 105.731 ;
     RECT  5.184 104.245 8.952 105.779 ;
     RECT  6.288 105.779 8.952 106.019 ;
     RECT  199.776 105.731 200.616 106.019 ;
     RECT  28.944 100.789 29.928 106.067 ;
     RECT  196.8 105.491 198.072 106.163 ;
     RECT  29.4 106.067 29.928 106.307 ;
     RECT  78 100.741 78.936 106.307 ;
     RECT  5.184 105.779 5.208 106.451 ;
     RECT  213 104.915 213.312 106.549 ;
     RECT  200.592 106.019 200.616 106.643 ;
     RECT  43.728 104.147 44.088 106.739 ;
     RECT  3.984 104.725 4.008 106.979 ;
     RECT  6.288 106.019 8.424 107.219 ;
     RECT  10.272 106.549 10.296 107.267 ;
     RECT  6.528 107.219 8.424 107.315 ;
     RECT  213 106.549 214.104 107.795 ;
     RECT  27.024 101.989 27.048 108.467 ;
     RECT  44.064 106.739 44.088 108.563 ;
     RECT  204.288 96.947 204.312 108.611 ;
     RECT  202.2 102.707 203.064 108.757 ;
     RECT  7.8 107.315 8.424 108.899 ;
     RECT  10.416 109.381 10.44 110.339 ;
     RECT  201.696 108.757 203.064 110.627 ;
     RECT  213 107.795 213.312 110.869 ;
     RECT  205.296 91.187 205.32 111.203 ;
     RECT  198.72 106.549 198.744 111.875 ;
     RECT  212.064 110.869 213.312 111.971 ;
     RECT  215.232 111.445 215.256 111.971 ;
     RECT  4.512 109.861 4.536 112.307 ;
     RECT  201.696 110.627 202.68 113.507 ;
     RECT  212.64 111.971 213.312 114.853 ;
     RECT  6.528 107.315 6.696 115.093 ;
     RECT  7.8 108.899 8.232 115.093 ;
     RECT  47.376 104.245 47.4 117.107 ;
     RECT  55.536 102.421 56.712 117.109 ;
     RECT  55.296 117.109 56.712 117.443 ;
     RECT  9.216 117.877 9.24 118.595 ;
     RECT  6.528 115.093 8.232 119.747 ;
     RECT  10.224 119.653 10.248 119.987 ;
     RECT  11.376 120.085 11.4 120.899 ;
     RECT  7.104 119.747 8.232 121.043 ;
     RECT  212.4 114.853 213.312 121.429 ;
     RECT  6.048 120.757 6.072 122.003 ;
     RECT  7.8 121.043 8.232 122.003 ;
     RECT  11.04 121.333 11.064 122.099 ;
     RECT  201.696 113.507 202.512 122.387 ;
     RECT  187.488 100.549 187.512 122.435 ;
     RECT  7.8 122.003 8.112 122.485 ;
     RECT  196.8 106.163 197.496 122.675 ;
     RECT  212.304 121.429 213.312 124.883 ;
     RECT  7.68 122.485 8.112 125.459 ;
     RECT  2.4 87.011 2.712 127.449 ;
     RECT  7.8 125.459 8.112 127.449 ;
     RECT  13.2 105.251 13.512 127.449 ;
     RECT  18.6 104.867 18.912 127.449 ;
     RECT  24 23.315 24.312 127.449 ;
     RECT  29.4 106.307 29.712 127.449 ;
     RECT  34.8 101.459 35.112 127.449 ;
     RECT  40.2 100.499 40.512 127.449 ;
     RECT  45.6 23.075 45.912 127.449 ;
     RECT  51 101.651 51.312 127.449 ;
     RECT  55.488 117.443 56.712 127.449 ;
     RECT  61.8 102.995 62.112 127.449 ;
     RECT  67.2 2.151 67.512 127.449 ;
     RECT  72.6 101.651 72.912 127.449 ;
     RECT  78 106.307 78.312 127.449 ;
     RECT  83.4 100.691 83.712 127.449 ;
     RECT  88.8 105.731 89.112 127.449 ;
     RECT  94.2 105.683 94.512 127.449 ;
     RECT  99.6 2.151 99.912 127.449 ;
     RECT  105 2.151 105.312 127.449 ;
     RECT  110.4 102.179 110.712 127.449 ;
     RECT  115.8 2.151 116.112 127.449 ;
     RECT  121.2 2.151 121.512 127.449 ;
     RECT  126.6 2.151 126.912 127.449 ;
     RECT  132 2.151 132.312 127.449 ;
     RECT  137.4 2.151 137.712 127.449 ;
     RECT  142.8 101.075 143.112 127.449 ;
     RECT  148.2 2.151 148.512 127.449 ;
     RECT  153.6 2.151 153.912 127.449 ;
     RECT  159 2.151 159.312 127.449 ;
     RECT  164.4 2.151 164.712 127.449 ;
     RECT  169.8 2.151 170.112 127.449 ;
     RECT  175.2 2.151 175.512 127.449 ;
     RECT  180.6 2.151 180.912 127.449 ;
     RECT  186 2.151 186.312 127.449 ;
     RECT  191.4 2.151 191.712 127.449 ;
     RECT  196.8 122.675 197.112 127.449 ;
     RECT  202.2 122.387 202.512 127.449 ;
     RECT  207.6 91.427 207.912 127.449 ;
     RECT  213 124.883 213.312 127.449 ;
     RECT  2.4 127.449 2.52 127.463 ;
     RECT  7.8 127.449 7.92 127.463 ;
     RECT  13.2 127.449 13.32 127.463 ;
     RECT  18.6 127.449 18.72 127.463 ;
     RECT  24 127.449 24.12 127.463 ;
     RECT  29.4 127.449 29.52 127.463 ;
     RECT  34.8 127.449 34.92 127.463 ;
     RECT  40.2 127.449 40.32 127.463 ;
     RECT  45.6 127.449 45.72 127.463 ;
     RECT  51 127.449 51.12 127.463 ;
     RECT  55.488 127.449 56.52 127.463 ;
     RECT  61.8 127.449 61.92 127.463 ;
     RECT  67.2 127.449 67.32 127.463 ;
     RECT  72.6 127.449 72.72 127.463 ;
     RECT  78 127.449 78.12 127.463 ;
     RECT  83.4 127.449 83.52 127.463 ;
     RECT  88.8 127.449 88.92 127.463 ;
     RECT  94.2 127.449 94.32 127.463 ;
     RECT  99.6 127.449 99.72 127.463 ;
     RECT  105 127.449 105.12 127.463 ;
     RECT  110.4 127.449 110.52 127.463 ;
     RECT  115.8 127.449 115.92 127.463 ;
     RECT  121.2 127.449 121.32 127.463 ;
     RECT  126.6 127.449 126.72 127.463 ;
     RECT  132 127.449 132.12 127.463 ;
     RECT  137.4 127.449 137.52 127.463 ;
     RECT  142.8 127.449 142.92 127.463 ;
     RECT  148.2 127.449 148.32 127.463 ;
     RECT  153.6 127.449 153.72 127.463 ;
     RECT  159 127.449 159.12 127.463 ;
     RECT  164.4 127.449 164.52 127.463 ;
     RECT  169.8 127.449 169.92 127.463 ;
     RECT  175.2 127.449 175.32 127.463 ;
     RECT  180.6 127.449 180.72 127.463 ;
     RECT  186 127.449 186.12 127.463 ;
     RECT  191.4 127.449 191.52 127.463 ;
     RECT  196.8 127.449 196.92 127.463 ;
     RECT  202.2 127.449 202.32 127.463 ;
     RECT  207.6 127.449 207.72 127.463 ;
     RECT  213 127.449 213.12 127.463 ;
     RECT  2.712 7.765 3.984 11.939 ;
     RECT  213.312 7.957 214.32 8.867 ;
     RECT  214.344 7.957 215.808 8.867 ;
     RECT  8.112 10.309 9.36 13.573 ;
     RECT  4.008 11.893 5.136 11.939 ;
     RECT  213.312 12.517 214.656 13.715 ;
     RECT  213.312 13.715 213.672 14.533 ;
     RECT  213.672 16.501 214.848 16.643 ;
     RECT  62.112 17.317 63.216 20.003 ;
     RECT  213.312 18.181 214.32 18.947 ;
     RECT  213.312 18.947 214.8 21.587 ;
     RECT  25.128 20.053 26.496 20.195 ;
     RECT  35.208 20.531 35.304 21.925 ;
     RECT  44.976 21.155 45.6 22.213 ;
     RECT  27.96 22.453 29.4 24.659 ;
     RECT  9.384 22.595 10.416 24.179 ;
     RECT  29.832 22.741 31.152 23.411 ;
     RECT  24.312 23.315 25.176 23.317 ;
     RECT  24.312 23.317 25.392 24.083 ;
     RECT  33.624 23.317 34.8 24.323 ;
     RECT  51.312 23.317 52.56 24.899 ;
     RECT  9.384 24.179 10.296 25.045 ;
     RECT  33.648 24.323 34.8 25.045 ;
     RECT  22.776 24.325 24 27.493 ;
     RECT  22.416 24.515 22.752 25.621 ;
     RECT  19.464 24.661 20.736 25.045 ;
     RECT  33.672 25.045 34.8 25.763 ;
     RECT  13.512 25.429 14.64 25.571 ;
     RECT  17.4 25.525 18.6 25.715 ;
     RECT  22.416 25.621 22.656 25.765 ;
     RECT  17.208 25.715 18.6 27.395 ;
     RECT  20.808 27.061 21.888 63.107 ;
     RECT  11.976 27.157 13.2 27.635 ;
     RECT  22.824 27.493 24 28.067 ;
     RECT  11.688 27.635 13.2 28.931 ;
     RECT  22.776 28.067 24 28.883 ;
     RECT  22.728 28.883 24 30.757 ;
     RECT  13.104 28.931 13.2 29.605 ;
     RECT  4.56 28.979 5.28 30.181 ;
     RECT  2.712 30.181 3.984 30.851 ;
     RECT  4.008 30.181 5.28 30.851 ;
     RECT  13.104 30.371 13.2 31.525 ;
     RECT  22.776 30.757 24 30.947 ;
     RECT  197.112 30.757 198.384 30.947 ;
     RECT  198.408 30.757 199.728 30.947 ;
     RECT  22.728 30.947 24 34.739 ;
     RECT  199.8 31.043 200.88 33.013 ;
     RECT  213.312 31.907 214.704 32.963 ;
     RECT  2.712 33.013 3.936 34.115 ;
     RECT  3.96 33.013 5.28 34.115 ;
     RECT  13.512 33.253 14.784 35.125 ;
     RECT  22.68 34.739 24 102.709 ;
     RECT  15.192 34.835 16.056 35.029 ;
     RECT  15.192 35.029 16.656 35.171 ;
     RECT  213.576 37.045 214.896 38.099 ;
     RECT  4.392 37.667 5.52 37.859 ;
     RECT  2.712 40.789 3.984 41.891 ;
     RECT  19.176 41.651 20.16 49.525 ;
     RECT  213.432 42.133 214.944 42.851 ;
     RECT  11.928 42.709 12.96 45.635 ;
     RECT  15.288 42.709 16.8 43.379 ;
     RECT  10.872 42.757 11.904 42.899 ;
     RECT  10.152 42.899 11.904 43.141 ;
     RECT  10.152 43.141 11.232 45.253 ;
     RECT  16.968 44.965 18.432 48.421 ;
     RECT  11.928 45.635 13.008 46.693 ;
     RECT  10.44 46.787 11.424 46.835 ;
     RECT  10.152 46.835 11.424 47.845 ;
     RECT  8.232 47.363 9.264 48.421 ;
     RECT  10.296 47.845 11.424 47.939 ;
     RECT  10.296 47.939 11.568 48.515 ;
     RECT  16.968 48.421 18.288 49.189 ;
     RECT  10.152 48.515 11.568 48.947 ;
     RECT  10.152 48.947 11.616 49.139 ;
     RECT  10.152 49.139 11.664 50.053 ;
     RECT  11.88 49.139 13.056 50.819 ;
     RECT  16.968 49.189 18.192 50.003 ;
     RECT  16.968 50.003 18.288 52.405 ;
     RECT  10.2 50.053 11.664 50.677 ;
     RECT  11.688 50.819 13.056 54.131 ;
     RECT  19.176 51.059 20.16 53.557 ;
     RECT  16.968 52.405 18.096 57.973 ;
     RECT  8.376 53.363 9.36 54.661 ;
     RECT  15.384 54.085 16.896 55.717 ;
     RECT  10.872 54.131 13.056 54.565 ;
     RECT  5.688 54.179 6.912 56.917 ;
     RECT  10.872 54.565 12 55.285 ;
     RECT  12.024 54.565 13.056 54.901 ;
     RECT  10.872 55.285 11.856 56.483 ;
     RECT  15.384 55.717 16.656 55.859 ;
     RECT  15.384 55.859 16.944 56.965 ;
     RECT  10.872 56.483 12.672 57.541 ;
     RECT  15.432 56.965 16.944 58.645 ;
     RECT  10.872 57.541 11.952 58.309 ;
     RECT  10.872 58.309 11.856 59.459 ;
     RECT  15.48 58.645 16.944 59.797 ;
     RECT  11.976 58.787 13.056 60.467 ;
     RECT  10.872 59.459 11.952 60.467 ;
     RECT  15.96 59.797 16.944 62.339 ;
     RECT  10.872 60.467 10.92 61.909 ;
     RECT  198.216 61.861 199.728 62.965 ;
     RECT  8.112 62.387 9.36 72.517 ;
     RECT  198.264 62.965 199.728 65.413 ;
     RECT  11.208 63.205 12.336 64.549 ;
     RECT  12.024 64.595 13.056 65.363 ;
     RECT  198.312 65.413 199.728 66.181 ;
     RECT  198.36 66.181 199.728 66.373 ;
     RECT  198.648 66.373 199.728 67.237 ;
     RECT  11.688 67.381 13.056 74.629 ;
     RECT  21.384 70.357 22.656 79.477 ;
     RECT  13.944 70.739 14.928 71.363 ;
     RECT  13.944 71.363 15.36 84.995 ;
     RECT  15.384 71.797 16.56 72.995 ;
     RECT  15.384 72.995 16.944 74.341 ;
     RECT  8.112 73.235 9.12 74.627 ;
     RECT  15.384 74.341 16.368 75.827 ;
     RECT  8.112 74.627 9.36 81.157 ;
     RECT  11.688 74.629 12.816 75.827 ;
     RECT  11.688 75.827 13.056 76.403 ;
     RECT  15.384 75.827 16.944 75.925 ;
     RECT  15.624 75.925 16.944 77.027 ;
     RECT  11.688 76.403 13.2 84.901 ;
     RECT  212.592 77.507 212.88 78.613 ;
     RECT  204.312 78.325 205.44 91.141 ;
     RECT  21.384 79.477 22.464 83.509 ;
     RECT  16.968 80.627 18.096 82.597 ;
     RECT  3.288 80.917 4.704 81.829 ;
     RECT  8.232 81.157 9.36 83.267 ;
     RECT  3.336 81.829 4.704 82.163 ;
     RECT  8.112 83.267 9.36 90.037 ;
     RECT  5.256 83.891 6.432 86.581 ;
     RECT  11.976 84.901 13.2 87.251 ;
     RECT  13.848 84.995 15.36 96.947 ;
     RECT  10.872 86.819 11.952 87.251 ;
     RECT  5.256 87.011 6.432 90.517 ;
     RECT  19.368 87.827 20.784 89.123 ;
     RECT  212.064 89.987 212.88 90.565 ;
     RECT  8.232 90.037 9.36 92.293 ;
     RECT  5.256 90.517 6.24 90.659 ;
     RECT  211.416 90.565 212.88 91.475 ;
     RECT  5.16 90.659 6.24 90.755 ;
     RECT  204.312 91.141 205.296 108.611 ;
     RECT  211.632 91.475 212.88 92.821 ;
     RECT  211.656 92.821 212.88 94.021 ;
     RECT  5.496 94.549 6.72 96.899 ;
     RECT  211.656 94.691 212.88 98.485 ;
     RECT  213.312 95.701 214.32 96.899 ;
     RECT  203.064 96.371 204.048 96.947 ;
     RECT  5.208 96.899 6.72 98.917 ;
     RECT  213.312 96.899 213.864 97.621 ;
     RECT  203.064 96.947 204.288 108.611 ;
     RECT  211.848 98.485 212.88 99.635 ;
     RECT  5.688 98.917 6.72 99.685 ;
     RECT  94.512 98.965 95.76 100.309 ;
     RECT  10.872 99.541 11.952 100.213 ;
     RECT  211.704 99.635 212.88 100.355 ;
     RECT  35.352 100.069 36.48 100.355 ;
     RECT  40.632 100.165 42.048 100.499 ;
     RECT  35.352 100.355 36.504 100.405 ;
     RECT  211.56 100.355 212.88 100.547 ;
     RECT  35.352 100.405 37.824 100.691 ;
     RECT  16.968 100.547 18.096 100.643 ;
     RECT  186.312 100.549 187.488 122.435 ;
     RECT  35.352 100.691 37.176 100.837 ;
     RECT  35.88 100.837 37.176 100.885 ;
     RECT  35.88 100.885 36.96 101.027 ;
     RECT  35.88 101.027 37.152 101.123 ;
     RECT  44.088 101.413 45.6 108.563 ;
     RECT  10.536 102.179 11.664 102.467 ;
     RECT  8.112 102.275 8.376 103.621 ;
     RECT  200.952 102.707 202.2 102.803 ;
     RECT  22.824 102.709 24 102.947 ;
     RECT  22.68 102.947 24 104.819 ;
     RECT  20.904 103.283 21.936 103.379 ;
     RECT  20.904 103.379 22.224 105.059 ;
     RECT  8.952 104.245 10.272 104.915 ;
     RECT  45.912 104.245 47.376 117.107 ;
     RECT  2.712 104.725 3.984 106.979 ;
     RECT  4.008 104.725 5.184 106.451 ;
     RECT  198.072 105.491 199.2 105.731 ;
     RECT  198.072 105.731 199.776 106.019 ;
     RECT  5.208 105.779 6.288 106.451 ;
     RECT  198.072 106.019 198.744 106.163 ;
     RECT  197.496 106.163 198.744 106.549 ;
     RECT  197.496 106.549 198.72 111.875 ;
     RECT  6.696 107.315 7.8 115.093 ;
     RECT  8.232 117.877 9.216 118.595 ;
     RECT  6.528 119.747 7.104 120.757 ;
     RECT  6.072 120.757 7.104 121.043 ;
     RECT  7.68 121.043 7.8 122.485 ;
  END
END ot_hgi_qdq_sw_program_leaf
END LIBRARY
